VERSION 5.8 ;
BUSBITCHARS "[]" ;
DIVIDERCHAR "/" ;
UNITS
    DATABASE MICRONS 1000 ;
END UNITS

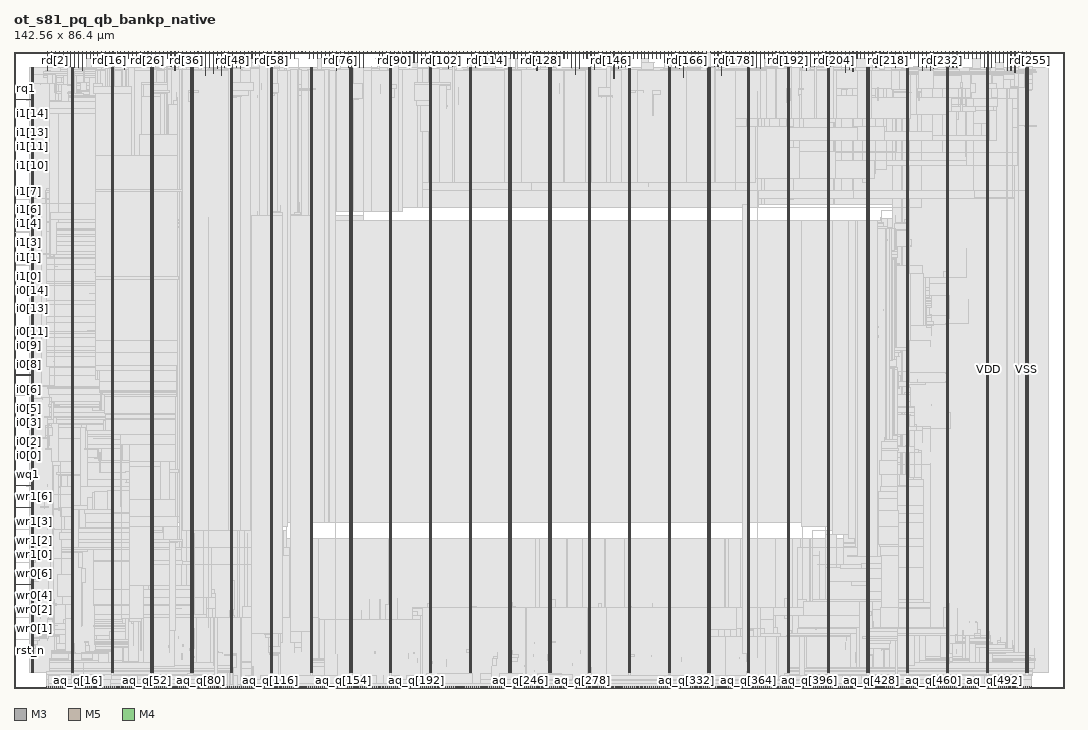
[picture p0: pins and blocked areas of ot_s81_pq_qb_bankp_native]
MACRO ot_s81_pq_qb_bankp_native
  FOREIGN ot_s81_pq_qb_bankp_native 0 0 ;
  CLASS BLOCK ;
  SIZE 142.56 BY 86.4 ;
  PIN aq_q[0]
    DIRECTION INPUT ;
    USE SIGNAL ;
    PORT
      LAYER M3 ;
        RECT  4.428 0 4.446 0.144 ;
    END
  END aq_q[0]
  PIN aq_q[100]
    DIRECTION INPUT ;
    USE SIGNAL ;
    PORT
      LAYER M3 ;
        RECT  30.6 0 30.618 0.144 ;
    END
  END aq_q[100]
  PIN aq_q[101]
    DIRECTION INPUT ;
    USE SIGNAL ;
    PORT
      LAYER M5 ;
        RECT  30.864 0 30.888 0.192 ;
    END
  END aq_q[101]
  PIN aq_q[102]
    DIRECTION INPUT ;
    USE SIGNAL ;
    PORT
      LAYER M3 ;
        RECT  31.104 0 31.122 0.144 ;
    END
  END aq_q[102]
  PIN aq_q[103]
    DIRECTION INPUT ;
    USE SIGNAL ;
    PORT
      LAYER M5 ;
        RECT  31.392 0 31.416 0.192 ;
    END
  END aq_q[103]
  PIN aq_q[104]
    DIRECTION INPUT ;
    USE SIGNAL ;
    PORT
      LAYER M3 ;
        RECT  31.644 0 31.662 0.144 ;
    END
  END aq_q[104]
  PIN aq_q[105]
    DIRECTION INPUT ;
    USE SIGNAL ;
    PORT
      LAYER M5 ;
        RECT  31.92 0 31.944 0.192 ;
    END
  END aq_q[105]
  PIN aq_q[106]
    DIRECTION INPUT ;
    USE SIGNAL ;
    PORT
      LAYER M3 ;
        RECT  32.184 0 32.202 0.144 ;
    END
  END aq_q[106]
  PIN aq_q[107]
    DIRECTION INPUT ;
    USE SIGNAL ;
    PORT
      LAYER M5 ;
        RECT  32.448 0 32.472 0.192 ;
    END
  END aq_q[107]
  PIN aq_q[108]
    DIRECTION INPUT ;
    USE SIGNAL ;
    PORT
      LAYER M3 ;
        RECT  32.688 0 32.706 0.144 ;
    END
  END aq_q[108]
  PIN aq_q[109]
    DIRECTION INPUT ;
    USE SIGNAL ;
    PORT
      LAYER M5 ;
        RECT  32.928 0 32.952 0.192 ;
    END
  END aq_q[109]
  PIN aq_q[10]
    DIRECTION INPUT ;
    USE SIGNAL ;
    PORT
      LAYER M3 ;
        RECT  7.056 0 7.074 0.144 ;
    END
  END aq_q[10]
  PIN aq_q[110]
    DIRECTION INPUT ;
    USE SIGNAL ;
    PORT
      LAYER M3 ;
        RECT  33.228 0 33.246 0.144 ;
    END
  END aq_q[110]
  PIN aq_q[111]
    DIRECTION INPUT ;
    USE SIGNAL ;
    PORT
      LAYER M5 ;
        RECT  33.456 0 33.48 0.192 ;
    END
  END aq_q[111]
  PIN aq_q[112]
    DIRECTION INPUT ;
    USE SIGNAL ;
    PORT
      LAYER M3 ;
        RECT  33.732 0 33.75 0.144 ;
    END
  END aq_q[112]
  PIN aq_q[113]
    DIRECTION INPUT ;
    USE SIGNAL ;
    PORT
      LAYER M5 ;
        RECT  33.984 0 34.008 0.192 ;
    END
  END aq_q[113]
  PIN aq_q[114]
    DIRECTION INPUT ;
    USE SIGNAL ;
    PORT
      LAYER M3 ;
        RECT  34.272 0 34.29 0.144 ;
    END
  END aq_q[114]
  PIN aq_q[115]
    DIRECTION INPUT ;
    USE SIGNAL ;
    PORT
      LAYER M5 ;
        RECT  34.512 0 34.536 0.192 ;
    END
  END aq_q[115]
  PIN aq_q[116]
    DIRECTION INPUT ;
    USE SIGNAL ;
    PORT
      LAYER M3 ;
        RECT  34.776 0 34.794 0.144 ;
    END
  END aq_q[116]
  PIN aq_q[117]
    DIRECTION INPUT ;
    USE SIGNAL ;
    PORT
      LAYER M5 ;
        RECT  35.04 0 35.064 0.192 ;
    END
  END aq_q[117]
  PIN aq_q[118]
    DIRECTION INPUT ;
    USE SIGNAL ;
    PORT
      LAYER M3 ;
        RECT  35.316 0 35.334 0.144 ;
    END
  END aq_q[118]
  PIN aq_q[119]
    DIRECTION INPUT ;
    USE SIGNAL ;
    PORT
      LAYER M5 ;
        RECT  35.568 0 35.592 0.192 ;
    END
  END aq_q[119]
  PIN aq_q[11]
    DIRECTION INPUT ;
    USE SIGNAL ;
    PORT
      LAYER M5 ;
        RECT  7.296 0 7.32 0.192 ;
    END
  END aq_q[11]
  PIN aq_q[120]
    DIRECTION INPUT ;
    USE SIGNAL ;
    PORT
      LAYER M3 ;
        RECT  35.82 0 35.838 0.144 ;
    END
  END aq_q[120]
  PIN aq_q[121]
    DIRECTION INPUT ;
    USE SIGNAL ;
    PORT
      LAYER M5 ;
        RECT  36.096 0 36.12 0.192 ;
    END
  END aq_q[121]
  PIN aq_q[122]
    DIRECTION INPUT ;
    USE SIGNAL ;
    PORT
      LAYER M3 ;
        RECT  36.36 0 36.378 0.144 ;
    END
  END aq_q[122]
  PIN aq_q[123]
    DIRECTION INPUT ;
    USE SIGNAL ;
    PORT
      LAYER M5 ;
        RECT  36.624 0 36.648 0.192 ;
    END
  END aq_q[123]
  PIN aq_q[124]
    DIRECTION INPUT ;
    USE SIGNAL ;
    PORT
      LAYER M3 ;
        RECT  36.864 0 36.882 0.144 ;
    END
  END aq_q[124]
  PIN aq_q[125]
    DIRECTION INPUT ;
    USE SIGNAL ;
    PORT
      LAYER M5 ;
        RECT  37.152 0 37.176 0.192 ;
    END
  END aq_q[125]
  PIN aq_q[126]
    DIRECTION INPUT ;
    USE SIGNAL ;
    PORT
      LAYER M3 ;
        RECT  37.404 0 37.422 0.144 ;
    END
  END aq_q[126]
  PIN aq_q[127]
    DIRECTION INPUT ;
    USE SIGNAL ;
    PORT
      LAYER M5 ;
        RECT  37.68 0 37.704 0.192 ;
    END
  END aq_q[127]
  PIN aq_q[128]
    DIRECTION INPUT ;
    USE SIGNAL ;
    PORT
      LAYER M3 ;
        RECT  37.908 0 37.926 0.144 ;
    END
  END aq_q[128]
  PIN aq_q[129]
    DIRECTION INPUT ;
    USE SIGNAL ;
    PORT
      LAYER M5 ;
        RECT  38.16 0 38.184 0.192 ;
    END
  END aq_q[129]
  PIN aq_q[12]
    DIRECTION INPUT ;
    USE SIGNAL ;
    PORT
      LAYER M3 ;
        RECT  7.596 0 7.614 0.144 ;
    END
  END aq_q[12]
  PIN aq_q[130]
    DIRECTION INPUT ;
    USE SIGNAL ;
    PORT
      LAYER M3 ;
        RECT  38.448 0 38.466 0.144 ;
    END
  END aq_q[130]
  PIN aq_q[131]
    DIRECTION INPUT ;
    USE SIGNAL ;
    PORT
      LAYER M5 ;
        RECT  38.688 0 38.712 0.192 ;
    END
  END aq_q[131]
  PIN aq_q[132]
    DIRECTION INPUT ;
    USE SIGNAL ;
    PORT
      LAYER M3 ;
        RECT  38.952 0 38.97 0.144 ;
    END
  END aq_q[132]
  PIN aq_q[133]
    DIRECTION INPUT ;
    USE SIGNAL ;
    PORT
      LAYER M5 ;
        RECT  39.216 0 39.24 0.192 ;
    END
  END aq_q[133]
  PIN aq_q[134]
    DIRECTION INPUT ;
    USE SIGNAL ;
    PORT
      LAYER M3 ;
        RECT  39.492 0 39.51 0.144 ;
    END
  END aq_q[134]
  PIN aq_q[135]
    DIRECTION INPUT ;
    USE SIGNAL ;
    PORT
      LAYER M5 ;
        RECT  39.744 0 39.768 0.192 ;
    END
  END aq_q[135]
  PIN aq_q[136]
    DIRECTION INPUT ;
    USE SIGNAL ;
    PORT
      LAYER M3 ;
        RECT  40.032 0 40.05 0.144 ;
    END
  END aq_q[136]
  PIN aq_q[137]
    DIRECTION INPUT ;
    USE SIGNAL ;
    PORT
      LAYER M5 ;
        RECT  40.272 0 40.296 0.192 ;
    END
  END aq_q[137]
  PIN aq_q[138]
    DIRECTION INPUT ;
    USE SIGNAL ;
    PORT
      LAYER M3 ;
        RECT  40.536 0 40.554 0.144 ;
    END
  END aq_q[138]
  PIN aq_q[139]
    DIRECTION INPUT ;
    USE SIGNAL ;
    PORT
      LAYER M5 ;
        RECT  40.8 0 40.824 0.192 ;
    END
  END aq_q[139]
  PIN aq_q[13]
    DIRECTION INPUT ;
    USE SIGNAL ;
    PORT
      LAYER M5 ;
        RECT  7.824 0 7.848 0.192 ;
    END
  END aq_q[13]
  PIN aq_q[140]
    DIRECTION INPUT ;
    USE SIGNAL ;
    PORT
      LAYER M3 ;
        RECT  41.076 0 41.094 0.144 ;
    END
  END aq_q[140]
  PIN aq_q[141]
    DIRECTION INPUT ;
    USE SIGNAL ;
    PORT
      LAYER M5 ;
        RECT  41.328 0 41.352 0.192 ;
    END
  END aq_q[141]
  PIN aq_q[142]
    DIRECTION INPUT ;
    USE SIGNAL ;
    PORT
      LAYER M3 ;
        RECT  41.58 0 41.598 0.144 ;
    END
  END aq_q[142]
  PIN aq_q[143]
    DIRECTION INPUT ;
    USE SIGNAL ;
    PORT
      LAYER M5 ;
        RECT  41.856 0 41.88 0.192 ;
    END
  END aq_q[143]
  PIN aq_q[144]
    DIRECTION INPUT ;
    USE SIGNAL ;
    PORT
      LAYER M3 ;
        RECT  42.12 0 42.138 0.144 ;
    END
  END aq_q[144]
  PIN aq_q[145]
    DIRECTION INPUT ;
    USE SIGNAL ;
    PORT
      LAYER M5 ;
        RECT  42.384 0 42.408 0.192 ;
    END
  END aq_q[145]
  PIN aq_q[146]
    DIRECTION INPUT ;
    USE SIGNAL ;
    PORT
      LAYER M3 ;
        RECT  42.624 0 42.642 0.144 ;
    END
  END aq_q[146]
  PIN aq_q[147]
    DIRECTION INPUT ;
    USE SIGNAL ;
    PORT
      LAYER M5 ;
        RECT  42.912 0 42.936 0.192 ;
    END
  END aq_q[147]
  PIN aq_q[148]
    DIRECTION INPUT ;
    USE SIGNAL ;
    PORT
      LAYER M3 ;
        RECT  43.164 0 43.182 0.144 ;
    END
  END aq_q[148]
  PIN aq_q[149]
    DIRECTION INPUT ;
    USE SIGNAL ;
    PORT
      LAYER M5 ;
        RECT  43.392 0 43.416 0.192 ;
    END
  END aq_q[149]
  PIN aq_q[14]
    DIRECTION INPUT ;
    USE SIGNAL ;
    PORT
      LAYER M3 ;
        RECT  8.1 0 8.118 0.144 ;
    END
  END aq_q[14]
  PIN aq_q[150]
    DIRECTION INPUT ;
    USE SIGNAL ;
    PORT
      LAYER M3 ;
        RECT  43.668 0 43.686 0.144 ;
    END
  END aq_q[150]
  PIN aq_q[151]
    DIRECTION INPUT ;
    USE SIGNAL ;
    PORT
      LAYER M5 ;
        RECT  43.92 0 43.944 0.192 ;
    END
  END aq_q[151]
  PIN aq_q[152]
    DIRECTION INPUT ;
    USE SIGNAL ;
    PORT
      LAYER M3 ;
        RECT  44.208 0 44.226 0.144 ;
    END
  END aq_q[152]
  PIN aq_q[153]
    DIRECTION INPUT ;
    USE SIGNAL ;
    PORT
      LAYER M5 ;
        RECT  44.448 0 44.472 0.192 ;
    END
  END aq_q[153]
  PIN aq_q[154]
    DIRECTION INPUT ;
    USE SIGNAL ;
    PORT
      LAYER M3 ;
        RECT  44.712 0 44.73 0.144 ;
    END
  END aq_q[154]
  PIN aq_q[155]
    DIRECTION INPUT ;
    USE SIGNAL ;
    PORT
      LAYER M5 ;
        RECT  44.976 0 45 0.192 ;
    END
  END aq_q[155]
  PIN aq_q[156]
    DIRECTION INPUT ;
    USE SIGNAL ;
    PORT
      LAYER M3 ;
        RECT  45.252 0 45.27 0.144 ;
    END
  END aq_q[156]
  PIN aq_q[157]
    DIRECTION INPUT ;
    USE SIGNAL ;
    PORT
      LAYER M5 ;
        RECT  45.504 0 45.528 0.192 ;
    END
  END aq_q[157]
  PIN aq_q[158]
    DIRECTION INPUT ;
    USE SIGNAL ;
    PORT
      LAYER M3 ;
        RECT  45.756 0 45.774 0.144 ;
    END
  END aq_q[158]
  PIN aq_q[159]
    DIRECTION INPUT ;
    USE SIGNAL ;
    PORT
      LAYER M5 ;
        RECT  46.032 0 46.056 0.192 ;
    END
  END aq_q[159]
  PIN aq_q[15]
    DIRECTION INPUT ;
    USE SIGNAL ;
    PORT
      LAYER M5 ;
        RECT  8.352 0 8.376 0.192 ;
    END
  END aq_q[15]
  PIN aq_q[160]
    DIRECTION INPUT ;
    USE SIGNAL ;
    PORT
      LAYER M3 ;
        RECT  46.296 0 46.314 0.144 ;
    END
  END aq_q[160]
  PIN aq_q[161]
    DIRECTION INPUT ;
    USE SIGNAL ;
    PORT
      LAYER M5 ;
        RECT  46.56 0 46.584 0.192 ;
    END
  END aq_q[161]
  PIN aq_q[162]
    DIRECTION INPUT ;
    USE SIGNAL ;
    PORT
      LAYER M3 ;
        RECT  46.8 0 46.818 0.144 ;
    END
  END aq_q[162]
  PIN aq_q[163]
    DIRECTION INPUT ;
    USE SIGNAL ;
    PORT
      LAYER M5 ;
        RECT  47.088 0 47.112 0.192 ;
    END
  END aq_q[163]
  PIN aq_q[164]
    DIRECTION INPUT ;
    USE SIGNAL ;
    PORT
      LAYER M3 ;
        RECT  47.34 0 47.358 0.144 ;
    END
  END aq_q[164]
  PIN aq_q[165]
    DIRECTION INPUT ;
    USE SIGNAL ;
    PORT
      LAYER M5 ;
        RECT  47.616 0 47.64 0.192 ;
    END
  END aq_q[165]
  PIN aq_q[166]
    DIRECTION INPUT ;
    USE SIGNAL ;
    PORT
      LAYER M3 ;
        RECT  47.844 0 47.862 0.144 ;
    END
  END aq_q[166]
  PIN aq_q[167]
    DIRECTION INPUT ;
    USE SIGNAL ;
    PORT
      LAYER M5 ;
        RECT  48.096 0 48.12 0.192 ;
    END
  END aq_q[167]
  PIN aq_q[168]
    DIRECTION INPUT ;
    USE SIGNAL ;
    PORT
      LAYER M3 ;
        RECT  48.384 0 48.402 0.144 ;
    END
  END aq_q[168]
  PIN aq_q[169]
    DIRECTION INPUT ;
    USE SIGNAL ;
    PORT
      LAYER M5 ;
        RECT  48.624 0 48.648 0.192 ;
    END
  END aq_q[169]
  PIN aq_q[16]
    DIRECTION INPUT ;
    USE SIGNAL ;
    PORT
      LAYER M3 ;
        RECT  8.64 0 8.658 0.144 ;
    END
  END aq_q[16]
  PIN aq_q[170]
    DIRECTION INPUT ;
    USE SIGNAL ;
    PORT
      LAYER M3 ;
        RECT  48.924 0 48.942 0.144 ;
    END
  END aq_q[170]
  PIN aq_q[171]
    DIRECTION INPUT ;
    USE SIGNAL ;
    PORT
      LAYER M5 ;
        RECT  49.152 0 49.176 0.192 ;
    END
  END aq_q[171]
  PIN aq_q[172]
    DIRECTION INPUT ;
    USE SIGNAL ;
    PORT
      LAYER M3 ;
        RECT  49.428 0 49.446 0.144 ;
    END
  END aq_q[172]
  PIN aq_q[173]
    DIRECTION INPUT ;
    USE SIGNAL ;
    PORT
      LAYER M5 ;
        RECT  49.68 0 49.704 0.192 ;
    END
  END aq_q[173]
  PIN aq_q[174]
    DIRECTION INPUT ;
    USE SIGNAL ;
    PORT
      LAYER M3 ;
        RECT  49.968 0 49.986 0.144 ;
    END
  END aq_q[174]
  PIN aq_q[175]
    DIRECTION INPUT ;
    USE SIGNAL ;
    PORT
      LAYER M5 ;
        RECT  50.208 0 50.232 0.192 ;
    END
  END aq_q[175]
  PIN aq_q[176]
    DIRECTION INPUT ;
    USE SIGNAL ;
    PORT
      LAYER M3 ;
        RECT  50.472 0 50.49 0.144 ;
    END
  END aq_q[176]
  PIN aq_q[177]
    DIRECTION INPUT ;
    USE SIGNAL ;
    PORT
      LAYER M5 ;
        RECT  50.736 0 50.76 0.192 ;
    END
  END aq_q[177]
  PIN aq_q[178]
    DIRECTION INPUT ;
    USE SIGNAL ;
    PORT
      LAYER M3 ;
        RECT  51.012 0 51.03 0.144 ;
    END
  END aq_q[178]
  PIN aq_q[179]
    DIRECTION INPUT ;
    USE SIGNAL ;
    PORT
      LAYER M5 ;
        RECT  51.264 0 51.288 0.192 ;
    END
  END aq_q[179]
  PIN aq_q[17]
    DIRECTION INPUT ;
    USE SIGNAL ;
    PORT
      LAYER M5 ;
        RECT  8.88 0 8.904 0.192 ;
    END
  END aq_q[17]
  PIN aq_q[180]
    DIRECTION INPUT ;
    USE SIGNAL ;
    PORT
      LAYER M3 ;
        RECT  51.516 0 51.534 0.144 ;
    END
  END aq_q[180]
  PIN aq_q[181]
    DIRECTION INPUT ;
    USE SIGNAL ;
    PORT
      LAYER M5 ;
        RECT  51.792 0 51.816 0.192 ;
    END
  END aq_q[181]
  PIN aq_q[182]
    DIRECTION INPUT ;
    USE SIGNAL ;
    PORT
      LAYER M3 ;
        RECT  52.056 0 52.074 0.144 ;
    END
  END aq_q[182]
  PIN aq_q[183]
    DIRECTION INPUT ;
    USE SIGNAL ;
    PORT
      LAYER M5 ;
        RECT  52.32 0 52.344 0.192 ;
    END
  END aq_q[183]
  PIN aq_q[184]
    DIRECTION INPUT ;
    USE SIGNAL ;
    PORT
      LAYER M3 ;
        RECT  52.56 0 52.578 0.144 ;
    END
  END aq_q[184]
  PIN aq_q[185]
    DIRECTION INPUT ;
    USE SIGNAL ;
    PORT
      LAYER M5 ;
        RECT  52.848 0 52.872 0.192 ;
    END
  END aq_q[185]
  PIN aq_q[186]
    DIRECTION INPUT ;
    USE SIGNAL ;
    PORT
      LAYER M3 ;
        RECT  53.1 0 53.118 0.144 ;
    END
  END aq_q[186]
  PIN aq_q[187]
    DIRECTION INPUT ;
    USE SIGNAL ;
    PORT
      LAYER M5 ;
        RECT  53.328 0 53.352 0.192 ;
    END
  END aq_q[187]
  PIN aq_q[188]
    DIRECTION INPUT ;
    USE SIGNAL ;
    PORT
      LAYER M3 ;
        RECT  53.604 0 53.622 0.144 ;
    END
  END aq_q[188]
  PIN aq_q[189]
    DIRECTION INPUT ;
    USE SIGNAL ;
    PORT
      LAYER M5 ;
        RECT  53.856 0 53.88 0.192 ;
    END
  END aq_q[189]
  PIN aq_q[18]
    DIRECTION INPUT ;
    USE SIGNAL ;
    PORT
      LAYER M3 ;
        RECT  9.144 0 9.162 0.144 ;
    END
  END aq_q[18]
  PIN aq_q[190]
    DIRECTION INPUT ;
    USE SIGNAL ;
    PORT
      LAYER M3 ;
        RECT  54.144 0 54.162 0.144 ;
    END
  END aq_q[190]
  PIN aq_q[191]
    DIRECTION INPUT ;
    USE SIGNAL ;
    PORT
      LAYER M5 ;
        RECT  54.384 0 54.408 0.192 ;
    END
  END aq_q[191]
  PIN aq_q[192]
    DIRECTION INPUT ;
    USE SIGNAL ;
    PORT
      LAYER M3 ;
        RECT  54.648 0 54.666 0.144 ;
    END
  END aq_q[192]
  PIN aq_q[193]
    DIRECTION INPUT ;
    USE SIGNAL ;
    PORT
      LAYER M5 ;
        RECT  54.912 0 54.936 0.192 ;
    END
  END aq_q[193]
  PIN aq_q[194]
    DIRECTION INPUT ;
    USE SIGNAL ;
    PORT
      LAYER M3 ;
        RECT  55.188 0 55.206 0.144 ;
    END
  END aq_q[194]
  PIN aq_q[195]
    DIRECTION INPUT ;
    USE SIGNAL ;
    PORT
      LAYER M5 ;
        RECT  55.44 0 55.464 0.192 ;
    END
  END aq_q[195]
  PIN aq_q[196]
    DIRECTION INPUT ;
    USE SIGNAL ;
    PORT
      LAYER M3 ;
        RECT  55.692 0 55.71 0.144 ;
    END
  END aq_q[196]
  PIN aq_q[197]
    DIRECTION INPUT ;
    USE SIGNAL ;
    PORT
      LAYER M5 ;
        RECT  55.968 0 55.992 0.192 ;
    END
  END aq_q[197]
  PIN aq_q[198]
    DIRECTION INPUT ;
    USE SIGNAL ;
    PORT
      LAYER M3 ;
        RECT  56.232 0 56.25 0.144 ;
    END
  END aq_q[198]
  PIN aq_q[199]
    DIRECTION INPUT ;
    USE SIGNAL ;
    PORT
      LAYER M5 ;
        RECT  56.496 0 56.52 0.192 ;
    END
  END aq_q[199]
  PIN aq_q[19]
    DIRECTION INPUT ;
    USE SIGNAL ;
    PORT
      LAYER M5 ;
        RECT  9.408 0 9.432 0.192 ;
    END
  END aq_q[19]
  PIN aq_q[1]
    DIRECTION INPUT ;
    USE SIGNAL ;
    PORT
      LAYER M5 ;
        RECT  4.704 0 4.728 0.192 ;
    END
  END aq_q[1]
  PIN aq_q[200]
    DIRECTION INPUT ;
    USE SIGNAL ;
    PORT
      LAYER M3 ;
        RECT  56.772 0 56.79 0.144 ;
    END
  END aq_q[200]
  PIN aq_q[201]
    DIRECTION INPUT ;
    USE SIGNAL ;
    PORT
      LAYER M5 ;
        RECT  57.024 0 57.048 0.192 ;
    END
  END aq_q[201]
  PIN aq_q[202]
    DIRECTION INPUT ;
    USE SIGNAL ;
    PORT
      LAYER M3 ;
        RECT  57.276 0 57.294 0.144 ;
    END
  END aq_q[202]
  PIN aq_q[203]
    DIRECTION INPUT ;
    USE SIGNAL ;
    PORT
      LAYER M5 ;
        RECT  57.552 0 57.576 0.192 ;
    END
  END aq_q[203]
  PIN aq_q[204]
    DIRECTION INPUT ;
    USE SIGNAL ;
    PORT
      LAYER M3 ;
        RECT  57.816 0 57.834 0.144 ;
    END
  END aq_q[204]
  PIN aq_q[205]
    DIRECTION INPUT ;
    USE SIGNAL ;
    PORT
      LAYER M5 ;
        RECT  58.08 0 58.104 0.192 ;
    END
  END aq_q[205]
  PIN aq_q[206]
    DIRECTION INPUT ;
    USE SIGNAL ;
    PORT
      LAYER M3 ;
        RECT  58.32 0 58.338 0.144 ;
    END
  END aq_q[206]
  PIN aq_q[207]
    DIRECTION INPUT ;
    USE SIGNAL ;
    PORT
      LAYER M5 ;
        RECT  58.56 0 58.584 0.192 ;
    END
  END aq_q[207]
  PIN aq_q[208]
    DIRECTION INPUT ;
    USE SIGNAL ;
    PORT
      LAYER M3 ;
        RECT  58.86 0 58.878 0.144 ;
    END
  END aq_q[208]
  PIN aq_q[209]
    DIRECTION INPUT ;
    USE SIGNAL ;
    PORT
      LAYER M5 ;
        RECT  59.088 0 59.112 0.192 ;
    END
  END aq_q[209]
  PIN aq_q[20]
    DIRECTION INPUT ;
    USE SIGNAL ;
    PORT
      LAYER M3 ;
        RECT  9.684 0 9.702 0.144 ;
    END
  END aq_q[20]
  PIN aq_q[210]
    DIRECTION INPUT ;
    USE SIGNAL ;
    PORT
      LAYER M3 ;
        RECT  59.364 0 59.382 0.144 ;
    END
  END aq_q[210]
  PIN aq_q[211]
    DIRECTION INPUT ;
    USE SIGNAL ;
    PORT
      LAYER M5 ;
        RECT  59.616 0 59.64 0.192 ;
    END
  END aq_q[211]
  PIN aq_q[212]
    DIRECTION INPUT ;
    USE SIGNAL ;
    PORT
      LAYER M3 ;
        RECT  59.904 0 59.922 0.144 ;
    END
  END aq_q[212]
  PIN aq_q[213]
    DIRECTION INPUT ;
    USE SIGNAL ;
    PORT
      LAYER M5 ;
        RECT  60.144 0 60.168 0.192 ;
    END
  END aq_q[213]
  PIN aq_q[214]
    DIRECTION INPUT ;
    USE SIGNAL ;
    PORT
      LAYER M3 ;
        RECT  60.408 0 60.426 0.144 ;
    END
  END aq_q[214]
  PIN aq_q[215]
    DIRECTION INPUT ;
    USE SIGNAL ;
    PORT
      LAYER M5 ;
        RECT  60.672 0 60.696 0.192 ;
    END
  END aq_q[215]
  PIN aq_q[216]
    DIRECTION INPUT ;
    USE SIGNAL ;
    PORT
      LAYER M3 ;
        RECT  60.948 0 60.966 0.144 ;
    END
  END aq_q[216]
  PIN aq_q[217]
    DIRECTION INPUT ;
    USE SIGNAL ;
    PORT
      LAYER M5 ;
        RECT  61.2 0 61.224 0.192 ;
    END
  END aq_q[217]
  PIN aq_q[218]
    DIRECTION INPUT ;
    USE SIGNAL ;
    PORT
      LAYER M3 ;
        RECT  61.452 0 61.47 0.144 ;
    END
  END aq_q[218]
  PIN aq_q[219]
    DIRECTION INPUT ;
    USE SIGNAL ;
    PORT
      LAYER M5 ;
        RECT  61.728 0 61.752 0.192 ;
    END
  END aq_q[219]
  PIN aq_q[21]
    DIRECTION INPUT ;
    USE SIGNAL ;
    PORT
      LAYER M5 ;
        RECT  9.936 0 9.96 0.192 ;
    END
  END aq_q[21]
  PIN aq_q[220]
    DIRECTION INPUT ;
    USE SIGNAL ;
    PORT
      LAYER M3 ;
        RECT  61.992 0 62.01 0.144 ;
    END
  END aq_q[220]
  PIN aq_q[221]
    DIRECTION INPUT ;
    USE SIGNAL ;
    PORT
      LAYER M5 ;
        RECT  62.256 0 62.28 0.192 ;
    END
  END aq_q[221]
  PIN aq_q[222]
    DIRECTION INPUT ;
    USE SIGNAL ;
    PORT
      LAYER M3 ;
        RECT  62.496 0 62.514 0.144 ;
    END
  END aq_q[222]
  PIN aq_q[223]
    DIRECTION INPUT ;
    USE SIGNAL ;
    PORT
      LAYER M5 ;
        RECT  62.784 0 62.808 0.192 ;
    END
  END aq_q[223]
  PIN aq_q[224]
    DIRECTION INPUT ;
    USE SIGNAL ;
    PORT
      LAYER M3 ;
        RECT  63.036 0 63.054 0.144 ;
    END
  END aq_q[224]
  PIN aq_q[225]
    DIRECTION INPUT ;
    USE SIGNAL ;
    PORT
      LAYER M5 ;
        RECT  63.312 0 63.336 0.192 ;
    END
  END aq_q[225]
  PIN aq_q[226]
    DIRECTION INPUT ;
    USE SIGNAL ;
    PORT
      LAYER M3 ;
        RECT  63.54 0 63.558 0.144 ;
    END
  END aq_q[226]
  PIN aq_q[227]
    DIRECTION INPUT ;
    USE SIGNAL ;
    PORT
      LAYER M5 ;
        RECT  63.792 0 63.816 0.192 ;
    END
  END aq_q[227]
  PIN aq_q[228]
    DIRECTION INPUT ;
    USE SIGNAL ;
    PORT
      LAYER M3 ;
        RECT  64.08 0 64.098 0.144 ;
    END
  END aq_q[228]
  PIN aq_q[229]
    DIRECTION INPUT ;
    USE SIGNAL ;
    PORT
      LAYER M5 ;
        RECT  64.32 0 64.344 0.192 ;
    END
  END aq_q[229]
  PIN aq_q[22]
    DIRECTION INPUT ;
    USE SIGNAL ;
    PORT
      LAYER M3 ;
        RECT  10.188 0 10.206 0.144 ;
    END
  END aq_q[22]
  PIN aq_q[230]
    DIRECTION INPUT ;
    USE SIGNAL ;
    PORT
      LAYER M3 ;
        RECT  64.584 0 64.602 0.144 ;
    END
  END aq_q[230]
  PIN aq_q[231]
    DIRECTION INPUT ;
    USE SIGNAL ;
    PORT
      LAYER M5 ;
        RECT  64.848 0 64.872 0.192 ;
    END
  END aq_q[231]
  PIN aq_q[232]
    DIRECTION INPUT ;
    USE SIGNAL ;
    PORT
      LAYER M3 ;
        RECT  65.124 0 65.142 0.144 ;
    END
  END aq_q[232]
  PIN aq_q[233]
    DIRECTION INPUT ;
    USE SIGNAL ;
    PORT
      LAYER M5 ;
        RECT  65.376 0 65.4 0.192 ;
    END
  END aq_q[233]
  PIN aq_q[234]
    DIRECTION INPUT ;
    USE SIGNAL ;
    PORT
      LAYER M3 ;
        RECT  65.664 0 65.682 0.144 ;
    END
  END aq_q[234]
  PIN aq_q[235]
    DIRECTION INPUT ;
    USE SIGNAL ;
    PORT
      LAYER M5 ;
        RECT  65.904 0 65.928 0.192 ;
    END
  END aq_q[235]
  PIN aq_q[236]
    DIRECTION INPUT ;
    USE SIGNAL ;
    PORT
      LAYER M3 ;
        RECT  66.168 0 66.186 0.144 ;
    END
  END aq_q[236]
  PIN aq_q[237]
    DIRECTION INPUT ;
    USE SIGNAL ;
    PORT
      LAYER M5 ;
        RECT  66.432 0 66.456 0.192 ;
    END
  END aq_q[237]
  PIN aq_q[238]
    DIRECTION INPUT ;
    USE SIGNAL ;
    PORT
      LAYER M3 ;
        RECT  66.708 0 66.726 0.144 ;
    END
  END aq_q[238]
  PIN aq_q[239]
    DIRECTION INPUT ;
    USE SIGNAL ;
    PORT
      LAYER M5 ;
        RECT  66.96 0 66.984 0.192 ;
    END
  END aq_q[239]
  PIN aq_q[23]
    DIRECTION INPUT ;
    USE SIGNAL ;
    PORT
      LAYER M5 ;
        RECT  10.464 0 10.488 0.192 ;
    END
  END aq_q[23]
  PIN aq_q[240]
    DIRECTION INPUT ;
    USE SIGNAL ;
    PORT
      LAYER M3 ;
        RECT  67.212 0 67.23 0.144 ;
    END
  END aq_q[240]
  PIN aq_q[241]
    DIRECTION INPUT ;
    USE SIGNAL ;
    PORT
      LAYER M5 ;
        RECT  67.488 0 67.512 0.192 ;
    END
  END aq_q[241]
  PIN aq_q[242]
    DIRECTION INPUT ;
    USE SIGNAL ;
    PORT
      LAYER M3 ;
        RECT  67.752 0 67.77 0.144 ;
    END
  END aq_q[242]
  PIN aq_q[243]
    DIRECTION INPUT ;
    USE SIGNAL ;
    PORT
      LAYER M5 ;
        RECT  68.016 0 68.04 0.192 ;
    END
  END aq_q[243]
  PIN aq_q[244]
    DIRECTION INPUT ;
    USE SIGNAL ;
    PORT
      LAYER M3 ;
        RECT  68.256 0 68.274 0.144 ;
    END
  END aq_q[244]
  PIN aq_q[245]
    DIRECTION INPUT ;
    USE SIGNAL ;
    PORT
      LAYER M5 ;
        RECT  68.544 0 68.568 0.192 ;
    END
  END aq_q[245]
  PIN aq_q[246]
    DIRECTION INPUT ;
    USE SIGNAL ;
    PORT
      LAYER M3 ;
        RECT  68.796 0 68.814 0.144 ;
    END
  END aq_q[246]
  PIN aq_q[247]
    DIRECTION INPUT ;
    USE SIGNAL ;
    PORT
      LAYER M5 ;
        RECT  69.024 0 69.048 0.192 ;
    END
  END aq_q[247]
  PIN aq_q[248]
    DIRECTION INPUT ;
    USE SIGNAL ;
    PORT
      LAYER M3 ;
        RECT  69.3 0 69.318 0.144 ;
    END
  END aq_q[248]
  PIN aq_q[249]
    DIRECTION INPUT ;
    USE SIGNAL ;
    PORT
      LAYER M5 ;
        RECT  69.552 0 69.576 0.192 ;
    END
  END aq_q[249]
  PIN aq_q[24]
    DIRECTION INPUT ;
    USE SIGNAL ;
    PORT
      LAYER M3 ;
        RECT  10.728 0 10.746 0.144 ;
    END
  END aq_q[24]
  PIN aq_q[250]
    DIRECTION INPUT ;
    USE SIGNAL ;
    PORT
      LAYER M3 ;
        RECT  69.84 0 69.858 0.144 ;
    END
  END aq_q[250]
  PIN aq_q[251]
    DIRECTION INPUT ;
    USE SIGNAL ;
    PORT
      LAYER M5 ;
        RECT  70.08 0 70.104 0.192 ;
    END
  END aq_q[251]
  PIN aq_q[252]
    DIRECTION INPUT ;
    USE SIGNAL ;
    PORT
      LAYER M3 ;
        RECT  70.344 0 70.362 0.144 ;
    END
  END aq_q[252]
  PIN aq_q[253]
    DIRECTION INPUT ;
    USE SIGNAL ;
    PORT
      LAYER M5 ;
        RECT  70.608 0 70.632 0.192 ;
    END
  END aq_q[253]
  PIN aq_q[254]
    DIRECTION INPUT ;
    USE SIGNAL ;
    PORT
      LAYER M3 ;
        RECT  70.884 0 70.902 0.144 ;
    END
  END aq_q[254]
  PIN aq_q[255]
    DIRECTION INPUT ;
    USE SIGNAL ;
    PORT
      LAYER M5 ;
        RECT  71.136 0 71.16 0.192 ;
    END
  END aq_q[255]
  PIN aq_q[256]
    DIRECTION INPUT ;
    USE SIGNAL ;
    PORT
      LAYER M3 ;
        RECT  71.388 0 71.406 0.144 ;
    END
  END aq_q[256]
  PIN aq_q[257]
    DIRECTION INPUT ;
    USE SIGNAL ;
    PORT
      LAYER M5 ;
        RECT  71.664 0 71.688 0.192 ;
    END
  END aq_q[257]
  PIN aq_q[258]
    DIRECTION INPUT ;
    USE SIGNAL ;
    PORT
      LAYER M3 ;
        RECT  71.928 0 71.946 0.144 ;
    END
  END aq_q[258]
  PIN aq_q[259]
    DIRECTION INPUT ;
    USE SIGNAL ;
    PORT
      LAYER M5 ;
        RECT  72.192 0 72.216 0.192 ;
    END
  END aq_q[259]
  PIN aq_q[25]
    DIRECTION INPUT ;
    USE SIGNAL ;
    PORT
      LAYER M5 ;
        RECT  10.992 0 11.016 0.192 ;
    END
  END aq_q[25]
  PIN aq_q[260]
    DIRECTION INPUT ;
    USE SIGNAL ;
    PORT
      LAYER M3 ;
        RECT  72.432 0 72.45 0.144 ;
    END
  END aq_q[260]
  PIN aq_q[261]
    DIRECTION INPUT ;
    USE SIGNAL ;
    PORT
      LAYER M5 ;
        RECT  72.72 0 72.744 0.192 ;
    END
  END aq_q[261]
  PIN aq_q[262]
    DIRECTION INPUT ;
    USE SIGNAL ;
    PORT
      LAYER M3 ;
        RECT  72.972 0 72.99 0.144 ;
    END
  END aq_q[262]
  PIN aq_q[263]
    DIRECTION INPUT ;
    USE SIGNAL ;
    PORT
      LAYER M5 ;
        RECT  73.248 0 73.272 0.192 ;
    END
  END aq_q[263]
  PIN aq_q[264]
    DIRECTION INPUT ;
    USE SIGNAL ;
    PORT
      LAYER M3 ;
        RECT  73.512 0 73.53 0.144 ;
    END
  END aq_q[264]
  PIN aq_q[265]
    DIRECTION INPUT ;
    USE SIGNAL ;
    PORT
      LAYER M5 ;
        RECT  73.776 0 73.8 0.192 ;
    END
  END aq_q[265]
  PIN aq_q[266]
    DIRECTION INPUT ;
    USE SIGNAL ;
    PORT
      LAYER M3 ;
        RECT  74.016 0 74.034 0.144 ;
    END
  END aq_q[266]
  PIN aq_q[267]
    DIRECTION INPUT ;
    USE SIGNAL ;
    PORT
      LAYER M5 ;
        RECT  74.256 0 74.28 0.192 ;
    END
  END aq_q[267]
  PIN aq_q[268]
    DIRECTION INPUT ;
    USE SIGNAL ;
    PORT
      LAYER M3 ;
        RECT  74.556 0 74.574 0.144 ;
    END
  END aq_q[268]
  PIN aq_q[269]
    DIRECTION INPUT ;
    USE SIGNAL ;
    PORT
      LAYER M5 ;
        RECT  74.784 0 74.808 0.192 ;
    END
  END aq_q[269]
  PIN aq_q[26]
    DIRECTION INPUT ;
    USE SIGNAL ;
    PORT
      LAYER M3 ;
        RECT  11.232 0 11.25 0.144 ;
    END
  END aq_q[26]
  PIN aq_q[270]
    DIRECTION INPUT ;
    USE SIGNAL ;
    PORT
      LAYER M3 ;
        RECT  75.06 0 75.078 0.144 ;
    END
  END aq_q[270]
  PIN aq_q[271]
    DIRECTION INPUT ;
    USE SIGNAL ;
    PORT
      LAYER M5 ;
        RECT  75.312 0 75.336 0.192 ;
    END
  END aq_q[271]
  PIN aq_q[272]
    DIRECTION INPUT ;
    USE SIGNAL ;
    PORT
      LAYER M3 ;
        RECT  75.6 0 75.618 0.144 ;
    END
  END aq_q[272]
  PIN aq_q[273]
    DIRECTION INPUT ;
    USE SIGNAL ;
    PORT
      LAYER M5 ;
        RECT  75.84 0 75.864 0.192 ;
    END
  END aq_q[273]
  PIN aq_q[274]
    DIRECTION INPUT ;
    USE SIGNAL ;
    PORT
      LAYER M3 ;
        RECT  76.104 0 76.122 0.144 ;
    END
  END aq_q[274]
  PIN aq_q[275]
    DIRECTION INPUT ;
    USE SIGNAL ;
    PORT
      LAYER M5 ;
        RECT  76.368 0 76.392 0.192 ;
    END
  END aq_q[275]
  PIN aq_q[276]
    DIRECTION INPUT ;
    USE SIGNAL ;
    PORT
      LAYER M3 ;
        RECT  76.644 0 76.662 0.144 ;
    END
  END aq_q[276]
  PIN aq_q[277]
    DIRECTION INPUT ;
    USE SIGNAL ;
    PORT
      LAYER M5 ;
        RECT  76.896 0 76.92 0.192 ;
    END
  END aq_q[277]
  PIN aq_q[278]
    DIRECTION INPUT ;
    USE SIGNAL ;
    PORT
      LAYER M3 ;
        RECT  77.148 0 77.166 0.144 ;
    END
  END aq_q[278]
  PIN aq_q[279]
    DIRECTION INPUT ;
    USE SIGNAL ;
    PORT
      LAYER M5 ;
        RECT  77.424 0 77.448 0.192 ;
    END
  END aq_q[279]
  PIN aq_q[27]
    DIRECTION INPUT ;
    USE SIGNAL ;
    PORT
      LAYER M5 ;
        RECT  11.52 0 11.544 0.192 ;
    END
  END aq_q[27]
  PIN aq_q[280]
    DIRECTION INPUT ;
    USE SIGNAL ;
    PORT
      LAYER M3 ;
        RECT  77.688 0 77.706 0.144 ;
    END
  END aq_q[280]
  PIN aq_q[281]
    DIRECTION INPUT ;
    USE SIGNAL ;
    PORT
      LAYER M5 ;
        RECT  77.952 0 77.976 0.192 ;
    END
  END aq_q[281]
  PIN aq_q[282]
    DIRECTION INPUT ;
    USE SIGNAL ;
    PORT
      LAYER M3 ;
        RECT  78.192 0 78.21 0.144 ;
    END
  END aq_q[282]
  PIN aq_q[283]
    DIRECTION INPUT ;
    USE SIGNAL ;
    PORT
      LAYER M5 ;
        RECT  78.48 0 78.504 0.192 ;
    END
  END aq_q[283]
  PIN aq_q[284]
    DIRECTION INPUT ;
    USE SIGNAL ;
    PORT
      LAYER M3 ;
        RECT  78.732 0 78.75 0.144 ;
    END
  END aq_q[284]
  PIN aq_q[285]
    DIRECTION INPUT ;
    USE SIGNAL ;
    PORT
      LAYER M5 ;
        RECT  79.008 0 79.032 0.192 ;
    END
  END aq_q[285]
  PIN aq_q[286]
    DIRECTION INPUT ;
    USE SIGNAL ;
    PORT
      LAYER M3 ;
        RECT  79.236 0 79.254 0.144 ;
    END
  END aq_q[286]
  PIN aq_q[287]
    DIRECTION INPUT ;
    USE SIGNAL ;
    PORT
      LAYER M5 ;
        RECT  79.488 0 79.512 0.192 ;
    END
  END aq_q[287]
  PIN aq_q[288]
    DIRECTION INPUT ;
    USE SIGNAL ;
    PORT
      LAYER M3 ;
        RECT  79.776 0 79.794 0.144 ;
    END
  END aq_q[288]
  PIN aq_q[289]
    DIRECTION INPUT ;
    USE SIGNAL ;
    PORT
      LAYER M5 ;
        RECT  80.016 0 80.04 0.192 ;
    END
  END aq_q[289]
  PIN aq_q[28]
    DIRECTION INPUT ;
    USE SIGNAL ;
    PORT
      LAYER M3 ;
        RECT  11.772 0 11.79 0.144 ;
    END
  END aq_q[28]
  PIN aq_q[290]
    DIRECTION INPUT ;
    USE SIGNAL ;
    PORT
      LAYER M3 ;
        RECT  80.28 0 80.298 0.144 ;
    END
  END aq_q[290]
  PIN aq_q[291]
    DIRECTION INPUT ;
    USE SIGNAL ;
    PORT
      LAYER M5 ;
        RECT  80.544 0 80.568 0.192 ;
    END
  END aq_q[291]
  PIN aq_q[292]
    DIRECTION INPUT ;
    USE SIGNAL ;
    PORT
      LAYER M3 ;
        RECT  80.82 0 80.838 0.144 ;
    END
  END aq_q[292]
  PIN aq_q[293]
    DIRECTION INPUT ;
    USE SIGNAL ;
    PORT
      LAYER M5 ;
        RECT  81.072 0 81.096 0.192 ;
    END
  END aq_q[293]
  PIN aq_q[294]
    DIRECTION INPUT ;
    USE SIGNAL ;
    PORT
      LAYER M3 ;
        RECT  81.324 0 81.342 0.144 ;
    END
  END aq_q[294]
  PIN aq_q[295]
    DIRECTION INPUT ;
    USE SIGNAL ;
    PORT
      LAYER M5 ;
        RECT  81.6 0 81.624 0.192 ;
    END
  END aq_q[295]
  PIN aq_q[296]
    DIRECTION INPUT ;
    USE SIGNAL ;
    PORT
      LAYER M3 ;
        RECT  81.864 0 81.882 0.144 ;
    END
  END aq_q[296]
  PIN aq_q[297]
    DIRECTION INPUT ;
    USE SIGNAL ;
    PORT
      LAYER M5 ;
        RECT  82.128 0 82.152 0.192 ;
    END
  END aq_q[297]
  PIN aq_q[298]
    DIRECTION INPUT ;
    USE SIGNAL ;
    PORT
      LAYER M3 ;
        RECT  82.404 0 82.422 0.144 ;
    END
  END aq_q[298]
  PIN aq_q[299]
    DIRECTION INPUT ;
    USE SIGNAL ;
    PORT
      LAYER M5 ;
        RECT  82.656 0 82.68 0.192 ;
    END
  END aq_q[299]
  PIN aq_q[29]
    DIRECTION INPUT ;
    USE SIGNAL ;
    PORT
      LAYER M5 ;
        RECT  12.048 0 12.072 0.192 ;
    END
  END aq_q[29]
  PIN aq_q[2]
    DIRECTION INPUT ;
    USE SIGNAL ;
    PORT
      LAYER M3 ;
        RECT  4.968 0 4.986 0.144 ;
    END
  END aq_q[2]
  PIN aq_q[300]
    DIRECTION INPUT ;
    USE SIGNAL ;
    PORT
      LAYER M3 ;
        RECT  82.908 0 82.926 0.144 ;
    END
  END aq_q[300]
  PIN aq_q[301]
    DIRECTION INPUT ;
    USE SIGNAL ;
    PORT
      LAYER M5 ;
        RECT  83.184 0 83.208 0.192 ;
    END
  END aq_q[301]
  PIN aq_q[302]
    DIRECTION INPUT ;
    USE SIGNAL ;
    PORT
      LAYER M3 ;
        RECT  83.448 0 83.466 0.144 ;
    END
  END aq_q[302]
  PIN aq_q[303]
    DIRECTION INPUT ;
    USE SIGNAL ;
    PORT
      LAYER M5 ;
        RECT  83.712 0 83.736 0.192 ;
    END
  END aq_q[303]
  PIN aq_q[304]
    DIRECTION INPUT ;
    USE SIGNAL ;
    PORT
      LAYER M3 ;
        RECT  83.952 0 83.97 0.144 ;
    END
  END aq_q[304]
  PIN aq_q[305]
    DIRECTION INPUT ;
    USE SIGNAL ;
    PORT
      LAYER M5 ;
        RECT  84.192 0 84.216 0.192 ;
    END
  END aq_q[305]
  PIN aq_q[306]
    DIRECTION INPUT ;
    USE SIGNAL ;
    PORT
      LAYER M3 ;
        RECT  84.492 0 84.51 0.144 ;
    END
  END aq_q[306]
  PIN aq_q[307]
    DIRECTION INPUT ;
    USE SIGNAL ;
    PORT
      LAYER M5 ;
        RECT  84.72 0 84.744 0.192 ;
    END
  END aq_q[307]
  PIN aq_q[308]
    DIRECTION INPUT ;
    USE SIGNAL ;
    PORT
      LAYER M3 ;
        RECT  84.996 0 85.014 0.144 ;
    END
  END aq_q[308]
  PIN aq_q[309]
    DIRECTION INPUT ;
    USE SIGNAL ;
    PORT
      LAYER M5 ;
        RECT  85.248 0 85.272 0.192 ;
    END
  END aq_q[309]
  PIN aq_q[30]
    DIRECTION INPUT ;
    USE SIGNAL ;
    PORT
      LAYER M3 ;
        RECT  12.276 0 12.294 0.144 ;
    END
  END aq_q[30]
  PIN aq_q[310]
    DIRECTION INPUT ;
    USE SIGNAL ;
    PORT
      LAYER M3 ;
        RECT  85.536 0 85.554 0.144 ;
    END
  END aq_q[310]
  PIN aq_q[311]
    DIRECTION INPUT ;
    USE SIGNAL ;
    PORT
      LAYER M5 ;
        RECT  85.776 0 85.8 0.192 ;
    END
  END aq_q[311]
  PIN aq_q[312]
    DIRECTION INPUT ;
    USE SIGNAL ;
    PORT
      LAYER M3 ;
        RECT  86.04 0 86.058 0.144 ;
    END
  END aq_q[312]
  PIN aq_q[313]
    DIRECTION INPUT ;
    USE SIGNAL ;
    PORT
      LAYER M5 ;
        RECT  86.304 0 86.328 0.192 ;
    END
  END aq_q[313]
  PIN aq_q[314]
    DIRECTION INPUT ;
    USE SIGNAL ;
    PORT
      LAYER M3 ;
        RECT  86.58 0 86.598 0.144 ;
    END
  END aq_q[314]
  PIN aq_q[315]
    DIRECTION INPUT ;
    USE SIGNAL ;
    PORT
      LAYER M5 ;
        RECT  86.832 0 86.856 0.192 ;
    END
  END aq_q[315]
  PIN aq_q[316]
    DIRECTION INPUT ;
    USE SIGNAL ;
    PORT
      LAYER M3 ;
        RECT  87.084 0 87.102 0.144 ;
    END
  END aq_q[316]
  PIN aq_q[317]
    DIRECTION INPUT ;
    USE SIGNAL ;
    PORT
      LAYER M5 ;
        RECT  87.36 0 87.384 0.192 ;
    END
  END aq_q[317]
  PIN aq_q[318]
    DIRECTION INPUT ;
    USE SIGNAL ;
    PORT
      LAYER M3 ;
        RECT  87.624 0 87.642 0.144 ;
    END
  END aq_q[318]
  PIN aq_q[319]
    DIRECTION INPUT ;
    USE SIGNAL ;
    PORT
      LAYER M5 ;
        RECT  87.888 0 87.912 0.192 ;
    END
  END aq_q[319]
  PIN aq_q[31]
    DIRECTION INPUT ;
    USE SIGNAL ;
    PORT
      LAYER M5 ;
        RECT  12.528 0 12.552 0.192 ;
    END
  END aq_q[31]
  PIN aq_q[320]
    DIRECTION INPUT ;
    USE SIGNAL ;
    PORT
      LAYER M3 ;
        RECT  88.128 0 88.146 0.144 ;
    END
  END aq_q[320]
  PIN aq_q[321]
    DIRECTION INPUT ;
    USE SIGNAL ;
    PORT
      LAYER M5 ;
        RECT  88.416 0 88.44 0.192 ;
    END
  END aq_q[321]
  PIN aq_q[322]
    DIRECTION INPUT ;
    USE SIGNAL ;
    PORT
      LAYER M3 ;
        RECT  88.668 0 88.686 0.144 ;
    END
  END aq_q[322]
  PIN aq_q[323]
    DIRECTION INPUT ;
    USE SIGNAL ;
    PORT
      LAYER M5 ;
        RECT  88.944 0 88.968 0.192 ;
    END
  END aq_q[323]
  PIN aq_q[324]
    DIRECTION INPUT ;
    USE SIGNAL ;
    PORT
      LAYER M3 ;
        RECT  89.172 0 89.19 0.144 ;
    END
  END aq_q[324]
  PIN aq_q[325]
    DIRECTION INPUT ;
    USE SIGNAL ;
    PORT
      LAYER M5 ;
        RECT  89.424 0 89.448 0.192 ;
    END
  END aq_q[325]
  PIN aq_q[326]
    DIRECTION INPUT ;
    USE SIGNAL ;
    PORT
      LAYER M3 ;
        RECT  89.712 0 89.73 0.144 ;
    END
  END aq_q[326]
  PIN aq_q[327]
    DIRECTION INPUT ;
    USE SIGNAL ;
    PORT
      LAYER M5 ;
        RECT  89.952 0 89.976 0.192 ;
    END
  END aq_q[327]
  PIN aq_q[328]
    DIRECTION INPUT ;
    USE SIGNAL ;
    PORT
      LAYER M3 ;
        RECT  90.252 0 90.27 0.144 ;
    END
  END aq_q[328]
  PIN aq_q[329]
    DIRECTION INPUT ;
    USE SIGNAL ;
    PORT
      LAYER M5 ;
        RECT  90.48 0 90.504 0.192 ;
    END
  END aq_q[329]
  PIN aq_q[32]
    DIRECTION INPUT ;
    USE SIGNAL ;
    PORT
      LAYER M3 ;
        RECT  12.816 0 12.834 0.144 ;
    END
  END aq_q[32]
  PIN aq_q[330]
    DIRECTION INPUT ;
    USE SIGNAL ;
    PORT
      LAYER M3 ;
        RECT  90.756 0 90.774 0.144 ;
    END
  END aq_q[330]
  PIN aq_q[331]
    DIRECTION INPUT ;
    USE SIGNAL ;
    PORT
      LAYER M5 ;
        RECT  91.008 0 91.032 0.192 ;
    END
  END aq_q[331]
  PIN aq_q[332]
    DIRECTION INPUT ;
    USE SIGNAL ;
    PORT
      LAYER M3 ;
        RECT  91.296 0 91.314 0.144 ;
    END
  END aq_q[332]
  PIN aq_q[333]
    DIRECTION INPUT ;
    USE SIGNAL ;
    PORT
      LAYER M5 ;
        RECT  91.536 0 91.56 0.192 ;
    END
  END aq_q[333]
  PIN aq_q[334]
    DIRECTION INPUT ;
    USE SIGNAL ;
    PORT
      LAYER M3 ;
        RECT  91.8 0 91.818 0.144 ;
    END
  END aq_q[334]
  PIN aq_q[335]
    DIRECTION INPUT ;
    USE SIGNAL ;
    PORT
      LAYER M5 ;
        RECT  92.064 0 92.088 0.192 ;
    END
  END aq_q[335]
  PIN aq_q[336]
    DIRECTION INPUT ;
    USE SIGNAL ;
    PORT
      LAYER M3 ;
        RECT  92.34 0 92.358 0.144 ;
    END
  END aq_q[336]
  PIN aq_q[337]
    DIRECTION INPUT ;
    USE SIGNAL ;
    PORT
      LAYER M5 ;
        RECT  92.592 0 92.616 0.192 ;
    END
  END aq_q[337]
  PIN aq_q[338]
    DIRECTION INPUT ;
    USE SIGNAL ;
    PORT
      LAYER M3 ;
        RECT  92.844 0 92.862 0.144 ;
    END
  END aq_q[338]
  PIN aq_q[339]
    DIRECTION INPUT ;
    USE SIGNAL ;
    PORT
      LAYER M5 ;
        RECT  93.12 0 93.144 0.192 ;
    END
  END aq_q[339]
  PIN aq_q[33]
    DIRECTION INPUT ;
    USE SIGNAL ;
    PORT
      LAYER M5 ;
        RECT  13.056 0 13.08 0.192 ;
    END
  END aq_q[33]
  PIN aq_q[340]
    DIRECTION INPUT ;
    USE SIGNAL ;
    PORT
      LAYER M3 ;
        RECT  93.384 0 93.402 0.144 ;
    END
  END aq_q[340]
  PIN aq_q[341]
    DIRECTION INPUT ;
    USE SIGNAL ;
    PORT
      LAYER M5 ;
        RECT  93.648 0 93.672 0.192 ;
    END
  END aq_q[341]
  PIN aq_q[342]
    DIRECTION INPUT ;
    USE SIGNAL ;
    PORT
      LAYER M3 ;
        RECT  93.888 0 93.906 0.144 ;
    END
  END aq_q[342]
  PIN aq_q[343]
    DIRECTION INPUT ;
    USE SIGNAL ;
    PORT
      LAYER M5 ;
        RECT  94.176 0 94.2 0.192 ;
    END
  END aq_q[343]
  PIN aq_q[344]
    DIRECTION INPUT ;
    USE SIGNAL ;
    PORT
      LAYER M3 ;
        RECT  94.428 0 94.446 0.144 ;
    END
  END aq_q[344]
  PIN aq_q[345]
    DIRECTION INPUT ;
    USE SIGNAL ;
    PORT
      LAYER M5 ;
        RECT  94.656 0 94.68 0.192 ;
    END
  END aq_q[345]
  PIN aq_q[346]
    DIRECTION INPUT ;
    USE SIGNAL ;
    PORT
      LAYER M3 ;
        RECT  94.932 0 94.95 0.144 ;
    END
  END aq_q[346]
  PIN aq_q[347]
    DIRECTION INPUT ;
    USE SIGNAL ;
    PORT
      LAYER M5 ;
        RECT  95.184 0 95.208 0.192 ;
    END
  END aq_q[347]
  PIN aq_q[348]
    DIRECTION INPUT ;
    USE SIGNAL ;
    PORT
      LAYER M3 ;
        RECT  95.472 0 95.49 0.144 ;
    END
  END aq_q[348]
  PIN aq_q[349]
    DIRECTION INPUT ;
    USE SIGNAL ;
    PORT
      LAYER M5 ;
        RECT  95.712 0 95.736 0.192 ;
    END
  END aq_q[349]
  PIN aq_q[34]
    DIRECTION INPUT ;
    USE SIGNAL ;
    PORT
      LAYER M3 ;
        RECT  13.32 0 13.338 0.144 ;
    END
  END aq_q[34]
  PIN aq_q[350]
    DIRECTION INPUT ;
    USE SIGNAL ;
    PORT
      LAYER M3 ;
        RECT  95.976 0 95.994 0.144 ;
    END
  END aq_q[350]
  PIN aq_q[351]
    DIRECTION INPUT ;
    USE SIGNAL ;
    PORT
      LAYER M5 ;
        RECT  96.24 0 96.264 0.192 ;
    END
  END aq_q[351]
  PIN aq_q[352]
    DIRECTION INPUT ;
    USE SIGNAL ;
    PORT
      LAYER M3 ;
        RECT  96.516 0 96.534 0.144 ;
    END
  END aq_q[352]
  PIN aq_q[353]
    DIRECTION INPUT ;
    USE SIGNAL ;
    PORT
      LAYER M5 ;
        RECT  96.768 0 96.792 0.192 ;
    END
  END aq_q[353]
  PIN aq_q[354]
    DIRECTION INPUT ;
    USE SIGNAL ;
    PORT
      LAYER M3 ;
        RECT  97.02 0 97.038 0.144 ;
    END
  END aq_q[354]
  PIN aq_q[355]
    DIRECTION INPUT ;
    USE SIGNAL ;
    PORT
      LAYER M5 ;
        RECT  97.296 0 97.32 0.192 ;
    END
  END aq_q[355]
  PIN aq_q[356]
    DIRECTION INPUT ;
    USE SIGNAL ;
    PORT
      LAYER M3 ;
        RECT  97.56 0 97.578 0.144 ;
    END
  END aq_q[356]
  PIN aq_q[357]
    DIRECTION INPUT ;
    USE SIGNAL ;
    PORT
      LAYER M5 ;
        RECT  97.824 0 97.848 0.192 ;
    END
  END aq_q[357]
  PIN aq_q[358]
    DIRECTION INPUT ;
    USE SIGNAL ;
    PORT
      LAYER M3 ;
        RECT  98.064 0 98.082 0.144 ;
    END
  END aq_q[358]
  PIN aq_q[359]
    DIRECTION INPUT ;
    USE SIGNAL ;
    PORT
      LAYER M5 ;
        RECT  98.352 0 98.376 0.192 ;
    END
  END aq_q[359]
  PIN aq_q[35]
    DIRECTION INPUT ;
    USE SIGNAL ;
    PORT
      LAYER M5 ;
        RECT  13.584 0 13.608 0.192 ;
    END
  END aq_q[35]
  PIN aq_q[360]
    DIRECTION INPUT ;
    USE SIGNAL ;
    PORT
      LAYER M3 ;
        RECT  98.604 0 98.622 0.144 ;
    END
  END aq_q[360]
  PIN aq_q[361]
    DIRECTION INPUT ;
    USE SIGNAL ;
    PORT
      LAYER M5 ;
        RECT  98.88 0 98.904 0.192 ;
    END
  END aq_q[361]
  PIN aq_q[362]
    DIRECTION INPUT ;
    USE SIGNAL ;
    PORT
      LAYER M3 ;
        RECT  99.144 0 99.162 0.144 ;
    END
  END aq_q[362]
  PIN aq_q[363]
    DIRECTION INPUT ;
    USE SIGNAL ;
    PORT
      LAYER M5 ;
        RECT  99.408 0 99.432 0.192 ;
    END
  END aq_q[363]
  PIN aq_q[364]
    DIRECTION INPUT ;
    USE SIGNAL ;
    PORT
      LAYER M3 ;
        RECT  99.648 0 99.666 0.144 ;
    END
  END aq_q[364]
  PIN aq_q[365]
    DIRECTION INPUT ;
    USE SIGNAL ;
    PORT
      LAYER M5 ;
        RECT  99.888 0 99.912 0.192 ;
    END
  END aq_q[365]
  PIN aq_q[366]
    DIRECTION INPUT ;
    USE SIGNAL ;
    PORT
      LAYER M3 ;
        RECT  100.188 0 100.206 0.144 ;
    END
  END aq_q[366]
  PIN aq_q[367]
    DIRECTION INPUT ;
    USE SIGNAL ;
    PORT
      LAYER M5 ;
        RECT  100.416 0 100.44 0.192 ;
    END
  END aq_q[367]
  PIN aq_q[368]
    DIRECTION INPUT ;
    USE SIGNAL ;
    PORT
      LAYER M3 ;
        RECT  100.692 0 100.71 0.144 ;
    END
  END aq_q[368]
  PIN aq_q[369]
    DIRECTION INPUT ;
    USE SIGNAL ;
    PORT
      LAYER M5 ;
        RECT  100.944 0 100.968 0.192 ;
    END
  END aq_q[369]
  PIN aq_q[36]
    DIRECTION INPUT ;
    USE SIGNAL ;
    PORT
      LAYER M3 ;
        RECT  13.86 0 13.878 0.144 ;
    END
  END aq_q[36]
  PIN aq_q[370]
    DIRECTION INPUT ;
    USE SIGNAL ;
    PORT
      LAYER M3 ;
        RECT  101.232 0 101.25 0.144 ;
    END
  END aq_q[370]
  PIN aq_q[371]
    DIRECTION INPUT ;
    USE SIGNAL ;
    PORT
      LAYER M5 ;
        RECT  101.472 0 101.496 0.192 ;
    END
  END aq_q[371]
  PIN aq_q[372]
    DIRECTION INPUT ;
    USE SIGNAL ;
    PORT
      LAYER M3 ;
        RECT  101.736 0 101.754 0.144 ;
    END
  END aq_q[372]
  PIN aq_q[373]
    DIRECTION INPUT ;
    USE SIGNAL ;
    PORT
      LAYER M5 ;
        RECT  102 0 102.024 0.192 ;
    END
  END aq_q[373]
  PIN aq_q[374]
    DIRECTION INPUT ;
    USE SIGNAL ;
    PORT
      LAYER M3 ;
        RECT  102.276 0 102.294 0.144 ;
    END
  END aq_q[374]
  PIN aq_q[375]
    DIRECTION INPUT ;
    USE SIGNAL ;
    PORT
      LAYER M5 ;
        RECT  102.528 0 102.552 0.192 ;
    END
  END aq_q[375]
  PIN aq_q[376]
    DIRECTION INPUT ;
    USE SIGNAL ;
    PORT
      LAYER M3 ;
        RECT  102.78 0 102.798 0.144 ;
    END
  END aq_q[376]
  PIN aq_q[377]
    DIRECTION INPUT ;
    USE SIGNAL ;
    PORT
      LAYER M5 ;
        RECT  103.056 0 103.08 0.192 ;
    END
  END aq_q[377]
  PIN aq_q[378]
    DIRECTION INPUT ;
    USE SIGNAL ;
    PORT
      LAYER M3 ;
        RECT  103.32 0 103.338 0.144 ;
    END
  END aq_q[378]
  PIN aq_q[379]
    DIRECTION INPUT ;
    USE SIGNAL ;
    PORT
      LAYER M5 ;
        RECT  103.584 0 103.608 0.192 ;
    END
  END aq_q[379]
  PIN aq_q[37]
    DIRECTION INPUT ;
    USE SIGNAL ;
    PORT
      LAYER M5 ;
        RECT  14.112 0 14.136 0.192 ;
    END
  END aq_q[37]
  PIN aq_q[380]
    DIRECTION INPUT ;
    USE SIGNAL ;
    PORT
      LAYER M3 ;
        RECT  103.824 0 103.842 0.144 ;
    END
  END aq_q[380]
  PIN aq_q[381]
    DIRECTION INPUT ;
    USE SIGNAL ;
    PORT
      LAYER M5 ;
        RECT  104.112 0 104.136 0.192 ;
    END
  END aq_q[381]
  PIN aq_q[382]
    DIRECTION INPUT ;
    USE SIGNAL ;
    PORT
      LAYER M3 ;
        RECT  104.364 0 104.382 0.144 ;
    END
  END aq_q[382]
  PIN aq_q[383]
    DIRECTION INPUT ;
    USE SIGNAL ;
    PORT
      LAYER M5 ;
        RECT  104.64 0 104.664 0.192 ;
    END
  END aq_q[383]
  PIN aq_q[384]
    DIRECTION INPUT ;
    USE SIGNAL ;
    PORT
      LAYER M3 ;
        RECT  104.868 0 104.886 0.144 ;
    END
  END aq_q[384]
  PIN aq_q[385]
    DIRECTION INPUT ;
    USE SIGNAL ;
    PORT
      LAYER M5 ;
        RECT  105.12 0 105.144 0.192 ;
    END
  END aq_q[385]
  PIN aq_q[386]
    DIRECTION INPUT ;
    USE SIGNAL ;
    PORT
      LAYER M3 ;
        RECT  105.408 0 105.426 0.144 ;
    END
  END aq_q[386]
  PIN aq_q[387]
    DIRECTION INPUT ;
    USE SIGNAL ;
    PORT
      LAYER M5 ;
        RECT  105.648 0 105.672 0.192 ;
    END
  END aq_q[387]
  PIN aq_q[388]
    DIRECTION INPUT ;
    USE SIGNAL ;
    PORT
      LAYER M3 ;
        RECT  105.912 0 105.93 0.144 ;
    END
  END aq_q[388]
  PIN aq_q[389]
    DIRECTION INPUT ;
    USE SIGNAL ;
    PORT
      LAYER M5 ;
        RECT  106.176 0 106.2 0.192 ;
    END
  END aq_q[389]
  PIN aq_q[38]
    DIRECTION INPUT ;
    USE SIGNAL ;
    PORT
      LAYER M3 ;
        RECT  14.364 0 14.382 0.144 ;
    END
  END aq_q[38]
  PIN aq_q[390]
    DIRECTION INPUT ;
    USE SIGNAL ;
    PORT
      LAYER M3 ;
        RECT  106.452 0 106.47 0.144 ;
    END
  END aq_q[390]
  PIN aq_q[391]
    DIRECTION INPUT ;
    USE SIGNAL ;
    PORT
      LAYER M5 ;
        RECT  106.704 0 106.728 0.192 ;
    END
  END aq_q[391]
  PIN aq_q[392]
    DIRECTION INPUT ;
    USE SIGNAL ;
    PORT
      LAYER M3 ;
        RECT  106.992 0 107.01 0.144 ;
    END
  END aq_q[392]
  PIN aq_q[393]
    DIRECTION INPUT ;
    USE SIGNAL ;
    PORT
      LAYER M5 ;
        RECT  107.232 0 107.256 0.192 ;
    END
  END aq_q[393]
  PIN aq_q[394]
    DIRECTION INPUT ;
    USE SIGNAL ;
    PORT
      LAYER M3 ;
        RECT  107.496 0 107.514 0.144 ;
    END
  END aq_q[394]
  PIN aq_q[395]
    DIRECTION INPUT ;
    USE SIGNAL ;
    PORT
      LAYER M5 ;
        RECT  107.76 0 107.784 0.192 ;
    END
  END aq_q[395]
  PIN aq_q[396]
    DIRECTION INPUT ;
    USE SIGNAL ;
    PORT
      LAYER M3 ;
        RECT  108.036 0 108.054 0.144 ;
    END
  END aq_q[396]
  PIN aq_q[397]
    DIRECTION INPUT ;
    USE SIGNAL ;
    PORT
      LAYER M5 ;
        RECT  108.288 0 108.312 0.192 ;
    END
  END aq_q[397]
  PIN aq_q[398]
    DIRECTION INPUT ;
    USE SIGNAL ;
    PORT
      LAYER M3 ;
        RECT  108.54 0 108.558 0.144 ;
    END
  END aq_q[398]
  PIN aq_q[399]
    DIRECTION INPUT ;
    USE SIGNAL ;
    PORT
      LAYER M5 ;
        RECT  108.816 0 108.84 0.192 ;
    END
  END aq_q[399]
  PIN aq_q[39]
    DIRECTION INPUT ;
    USE SIGNAL ;
    PORT
      LAYER M5 ;
        RECT  14.64 0 14.664 0.192 ;
    END
  END aq_q[39]
  PIN aq_q[3]
    DIRECTION INPUT ;
    USE SIGNAL ;
    PORT
      LAYER M5 ;
        RECT  5.232 0 5.256 0.192 ;
    END
  END aq_q[3]
  PIN aq_q[400]
    DIRECTION INPUT ;
    USE SIGNAL ;
    PORT
      LAYER M3 ;
        RECT  109.08 0 109.098 0.144 ;
    END
  END aq_q[400]
  PIN aq_q[401]
    DIRECTION INPUT ;
    USE SIGNAL ;
    PORT
      LAYER M5 ;
        RECT  109.344 0 109.368 0.192 ;
    END
  END aq_q[401]
  PIN aq_q[402]
    DIRECTION INPUT ;
    USE SIGNAL ;
    PORT
      LAYER M3 ;
        RECT  109.584 0 109.602 0.144 ;
    END
  END aq_q[402]
  PIN aq_q[403]
    DIRECTION INPUT ;
    USE SIGNAL ;
    PORT
      LAYER M5 ;
        RECT  109.872 0 109.896 0.192 ;
    END
  END aq_q[403]
  PIN aq_q[404]
    DIRECTION INPUT ;
    USE SIGNAL ;
    PORT
      LAYER M3 ;
        RECT  110.124 0 110.142 0.144 ;
    END
  END aq_q[404]
  PIN aq_q[405]
    DIRECTION INPUT ;
    USE SIGNAL ;
    PORT
      LAYER M5 ;
        RECT  110.352 0 110.376 0.192 ;
    END
  END aq_q[405]
  PIN aq_q[406]
    DIRECTION INPUT ;
    USE SIGNAL ;
    PORT
      LAYER M3 ;
        RECT  110.628 0 110.646 0.144 ;
    END
  END aq_q[406]
  PIN aq_q[407]
    DIRECTION INPUT ;
    USE SIGNAL ;
    PORT
      LAYER M5 ;
        RECT  110.88 0 110.904 0.192 ;
    END
  END aq_q[407]
  PIN aq_q[408]
    DIRECTION INPUT ;
    USE SIGNAL ;
    PORT
      LAYER M3 ;
        RECT  111.168 0 111.186 0.144 ;
    END
  END aq_q[408]
  PIN aq_q[409]
    DIRECTION INPUT ;
    USE SIGNAL ;
    PORT
      LAYER M5 ;
        RECT  111.408 0 111.432 0.192 ;
    END
  END aq_q[409]
  PIN aq_q[40]
    DIRECTION INPUT ;
    USE SIGNAL ;
    PORT
      LAYER M3 ;
        RECT  14.904 0 14.922 0.144 ;
    END
  END aq_q[40]
  PIN aq_q[410]
    DIRECTION INPUT ;
    USE SIGNAL ;
    PORT
      LAYER M3 ;
        RECT  111.672 0 111.69 0.144 ;
    END
  END aq_q[410]
  PIN aq_q[411]
    DIRECTION INPUT ;
    USE SIGNAL ;
    PORT
      LAYER M5 ;
        RECT  111.936 0 111.96 0.192 ;
    END
  END aq_q[411]
  PIN aq_q[412]
    DIRECTION INPUT ;
    USE SIGNAL ;
    PORT
      LAYER M3 ;
        RECT  112.212 0 112.23 0.144 ;
    END
  END aq_q[412]
  PIN aq_q[413]
    DIRECTION INPUT ;
    USE SIGNAL ;
    PORT
      LAYER M5 ;
        RECT  112.464 0 112.488 0.192 ;
    END
  END aq_q[413]
  PIN aq_q[414]
    DIRECTION INPUT ;
    USE SIGNAL ;
    PORT
      LAYER M3 ;
        RECT  112.716 0 112.734 0.144 ;
    END
  END aq_q[414]
  PIN aq_q[415]
    DIRECTION INPUT ;
    USE SIGNAL ;
    PORT
      LAYER M5 ;
        RECT  112.992 0 113.016 0.192 ;
    END
  END aq_q[415]
  PIN aq_q[416]
    DIRECTION INPUT ;
    USE SIGNAL ;
    PORT
      LAYER M3 ;
        RECT  113.256 0 113.274 0.144 ;
    END
  END aq_q[416]
  PIN aq_q[417]
    DIRECTION INPUT ;
    USE SIGNAL ;
    PORT
      LAYER M5 ;
        RECT  113.52 0 113.544 0.192 ;
    END
  END aq_q[417]
  PIN aq_q[418]
    DIRECTION INPUT ;
    USE SIGNAL ;
    PORT
      LAYER M3 ;
        RECT  113.76 0 113.778 0.144 ;
    END
  END aq_q[418]
  PIN aq_q[419]
    DIRECTION INPUT ;
    USE SIGNAL ;
    PORT
      LAYER M5 ;
        RECT  114.048 0 114.072 0.192 ;
    END
  END aq_q[419]
  PIN aq_q[41]
    DIRECTION INPUT ;
    USE SIGNAL ;
    PORT
      LAYER M5 ;
        RECT  15.168 0 15.192 0.192 ;
    END
  END aq_q[41]
  PIN aq_q[420]
    DIRECTION INPUT ;
    USE SIGNAL ;
    PORT
      LAYER M3 ;
        RECT  114.3 0 114.318 0.144 ;
    END
  END aq_q[420]
  PIN aq_q[421]
    DIRECTION INPUT ;
    USE SIGNAL ;
    PORT
      LAYER M5 ;
        RECT  114.576 0 114.6 0.192 ;
    END
  END aq_q[421]
  PIN aq_q[422]
    DIRECTION INPUT ;
    USE SIGNAL ;
    PORT
      LAYER M3 ;
        RECT  114.804 0 114.822 0.144 ;
    END
  END aq_q[422]
  PIN aq_q[423]
    DIRECTION INPUT ;
    USE SIGNAL ;
    PORT
      LAYER M5 ;
        RECT  115.056 0 115.08 0.192 ;
    END
  END aq_q[423]
  PIN aq_q[424]
    DIRECTION INPUT ;
    USE SIGNAL ;
    PORT
      LAYER M3 ;
        RECT  115.344 0 115.362 0.144 ;
    END
  END aq_q[424]
  PIN aq_q[425]
    DIRECTION INPUT ;
    USE SIGNAL ;
    PORT
      LAYER M5 ;
        RECT  115.584 0 115.608 0.192 ;
    END
  END aq_q[425]
  PIN aq_q[426]
    DIRECTION INPUT ;
    USE SIGNAL ;
    PORT
      LAYER M3 ;
        RECT  115.884 0 115.902 0.144 ;
    END
  END aq_q[426]
  PIN aq_q[427]
    DIRECTION INPUT ;
    USE SIGNAL ;
    PORT
      LAYER M5 ;
        RECT  116.112 0 116.136 0.192 ;
    END
  END aq_q[427]
  PIN aq_q[428]
    DIRECTION INPUT ;
    USE SIGNAL ;
    PORT
      LAYER M3 ;
        RECT  116.388 0 116.406 0.144 ;
    END
  END aq_q[428]
  PIN aq_q[429]
    DIRECTION INPUT ;
    USE SIGNAL ;
    PORT
      LAYER M5 ;
        RECT  116.64 0 116.664 0.192 ;
    END
  END aq_q[429]
  PIN aq_q[42]
    DIRECTION INPUT ;
    USE SIGNAL ;
    PORT
      LAYER M3 ;
        RECT  15.444 0 15.462 0.144 ;
    END
  END aq_q[42]
  PIN aq_q[430]
    DIRECTION INPUT ;
    USE SIGNAL ;
    PORT
      LAYER M3 ;
        RECT  116.928 0 116.946 0.144 ;
    END
  END aq_q[430]
  PIN aq_q[431]
    DIRECTION INPUT ;
    USE SIGNAL ;
    PORT
      LAYER M5 ;
        RECT  117.168 0 117.192 0.192 ;
    END
  END aq_q[431]
  PIN aq_q[432]
    DIRECTION INPUT ;
    USE SIGNAL ;
    PORT
      LAYER M3 ;
        RECT  117.432 0 117.45 0.144 ;
    END
  END aq_q[432]
  PIN aq_q[433]
    DIRECTION INPUT ;
    USE SIGNAL ;
    PORT
      LAYER M5 ;
        RECT  117.696 0 117.72 0.192 ;
    END
  END aq_q[433]
  PIN aq_q[434]
    DIRECTION INPUT ;
    USE SIGNAL ;
    PORT
      LAYER M3 ;
        RECT  117.972 0 117.99 0.144 ;
    END
  END aq_q[434]
  PIN aq_q[435]
    DIRECTION INPUT ;
    USE SIGNAL ;
    PORT
      LAYER M5 ;
        RECT  118.224 0 118.248 0.192 ;
    END
  END aq_q[435]
  PIN aq_q[436]
    DIRECTION INPUT ;
    USE SIGNAL ;
    PORT
      LAYER M3 ;
        RECT  118.476 0 118.494 0.144 ;
    END
  END aq_q[436]
  PIN aq_q[437]
    DIRECTION INPUT ;
    USE SIGNAL ;
    PORT
      LAYER M5 ;
        RECT  118.752 0 118.776 0.192 ;
    END
  END aq_q[437]
  PIN aq_q[438]
    DIRECTION INPUT ;
    USE SIGNAL ;
    PORT
      LAYER M3 ;
        RECT  119.016 0 119.034 0.144 ;
    END
  END aq_q[438]
  PIN aq_q[439]
    DIRECTION INPUT ;
    USE SIGNAL ;
    PORT
      LAYER M5 ;
        RECT  119.28 0 119.304 0.192 ;
    END
  END aq_q[439]
  PIN aq_q[43]
    DIRECTION INPUT ;
    USE SIGNAL ;
    PORT
      LAYER M5 ;
        RECT  15.696 0 15.72 0.192 ;
    END
  END aq_q[43]
  PIN aq_q[440]
    DIRECTION INPUT ;
    USE SIGNAL ;
    PORT
      LAYER M3 ;
        RECT  119.52 0 119.538 0.144 ;
    END
  END aq_q[440]
  PIN aq_q[441]
    DIRECTION INPUT ;
    USE SIGNAL ;
    PORT
      LAYER M5 ;
        RECT  119.808 0 119.832 0.192 ;
    END
  END aq_q[441]
  PIN aq_q[442]
    DIRECTION INPUT ;
    USE SIGNAL ;
    PORT
      LAYER M3 ;
        RECT  120.06 0 120.078 0.144 ;
    END
  END aq_q[442]
  PIN aq_q[443]
    DIRECTION INPUT ;
    USE SIGNAL ;
    PORT
      LAYER M5 ;
        RECT  120.288 0 120.312 0.192 ;
    END
  END aq_q[443]
  PIN aq_q[444]
    DIRECTION INPUT ;
    USE SIGNAL ;
    PORT
      LAYER M3 ;
        RECT  120.564 0 120.582 0.144 ;
    END
  END aq_q[444]
  PIN aq_q[445]
    DIRECTION INPUT ;
    USE SIGNAL ;
    PORT
      LAYER M5 ;
        RECT  120.816 0 120.84 0.192 ;
    END
  END aq_q[445]
  PIN aq_q[446]
    DIRECTION INPUT ;
    USE SIGNAL ;
    PORT
      LAYER M3 ;
        RECT  121.104 0 121.122 0.144 ;
    END
  END aq_q[446]
  PIN aq_q[447]
    DIRECTION INPUT ;
    USE SIGNAL ;
    PORT
      LAYER M5 ;
        RECT  121.344 0 121.368 0.192 ;
    END
  END aq_q[447]
  PIN aq_q[448]
    DIRECTION INPUT ;
    USE SIGNAL ;
    PORT
      LAYER M3 ;
        RECT  121.608 0 121.626 0.144 ;
    END
  END aq_q[448]
  PIN aq_q[449]
    DIRECTION INPUT ;
    USE SIGNAL ;
    PORT
      LAYER M5 ;
        RECT  121.872 0 121.896 0.192 ;
    END
  END aq_q[449]
  PIN aq_q[44]
    DIRECTION INPUT ;
    USE SIGNAL ;
    PORT
      LAYER M3 ;
        RECT  15.948 0 15.966 0.144 ;
    END
  END aq_q[44]
  PIN aq_q[450]
    DIRECTION INPUT ;
    USE SIGNAL ;
    PORT
      LAYER M3 ;
        RECT  122.148 0 122.166 0.144 ;
    END
  END aq_q[450]
  PIN aq_q[451]
    DIRECTION INPUT ;
    USE SIGNAL ;
    PORT
      LAYER M5 ;
        RECT  122.4 0 122.424 0.192 ;
    END
  END aq_q[451]
  PIN aq_q[452]
    DIRECTION INPUT ;
    USE SIGNAL ;
    PORT
      LAYER M3 ;
        RECT  122.652 0 122.67 0.144 ;
    END
  END aq_q[452]
  PIN aq_q[453]
    DIRECTION INPUT ;
    USE SIGNAL ;
    PORT
      LAYER M5 ;
        RECT  122.928 0 122.952 0.192 ;
    END
  END aq_q[453]
  PIN aq_q[454]
    DIRECTION INPUT ;
    USE SIGNAL ;
    PORT
      LAYER M3 ;
        RECT  123.192 0 123.21 0.144 ;
    END
  END aq_q[454]
  PIN aq_q[455]
    DIRECTION INPUT ;
    USE SIGNAL ;
    PORT
      LAYER M5 ;
        RECT  123.456 0 123.48 0.192 ;
    END
  END aq_q[455]
  PIN aq_q[456]
    DIRECTION INPUT ;
    USE SIGNAL ;
    PORT
      LAYER M3 ;
        RECT  123.732 0 123.75 0.144 ;
    END
  END aq_q[456]
  PIN aq_q[457]
    DIRECTION INPUT ;
    USE SIGNAL ;
    PORT
      LAYER M5 ;
        RECT  123.984 0 124.008 0.192 ;
    END
  END aq_q[457]
  PIN aq_q[458]
    DIRECTION INPUT ;
    USE SIGNAL ;
    PORT
      LAYER M3 ;
        RECT  124.236 0 124.254 0.144 ;
    END
  END aq_q[458]
  PIN aq_q[459]
    DIRECTION INPUT ;
    USE SIGNAL ;
    PORT
      LAYER M5 ;
        RECT  124.512 0 124.536 0.192 ;
    END
  END aq_q[459]
  PIN aq_q[45]
    DIRECTION INPUT ;
    USE SIGNAL ;
    PORT
      LAYER M5 ;
        RECT  16.224 0 16.248 0.192 ;
    END
  END aq_q[45]
  PIN aq_q[460]
    DIRECTION INPUT ;
    USE SIGNAL ;
    PORT
      LAYER M3 ;
        RECT  124.776 0 124.794 0.144 ;
    END
  END aq_q[460]
  PIN aq_q[461]
    DIRECTION INPUT ;
    USE SIGNAL ;
    PORT
      LAYER M5 ;
        RECT  125.04 0 125.064 0.192 ;
    END
  END aq_q[461]
  PIN aq_q[462]
    DIRECTION INPUT ;
    USE SIGNAL ;
    PORT
      LAYER M3 ;
        RECT  125.28 0 125.298 0.144 ;
    END
  END aq_q[462]
  PIN aq_q[463]
    DIRECTION INPUT ;
    USE SIGNAL ;
    PORT
      LAYER M5 ;
        RECT  125.52 0 125.544 0.192 ;
    END
  END aq_q[463]
  PIN aq_q[464]
    DIRECTION INPUT ;
    USE SIGNAL ;
    PORT
      LAYER M3 ;
        RECT  125.82 0 125.838 0.144 ;
    END
  END aq_q[464]
  PIN aq_q[465]
    DIRECTION INPUT ;
    USE SIGNAL ;
    PORT
      LAYER M5 ;
        RECT  126.048 0 126.072 0.192 ;
    END
  END aq_q[465]
  PIN aq_q[466]
    DIRECTION INPUT ;
    USE SIGNAL ;
    PORT
      LAYER M3 ;
        RECT  126.324 0 126.342 0.144 ;
    END
  END aq_q[466]
  PIN aq_q[467]
    DIRECTION INPUT ;
    USE SIGNAL ;
    PORT
      LAYER M5 ;
        RECT  126.576 0 126.6 0.192 ;
    END
  END aq_q[467]
  PIN aq_q[468]
    DIRECTION INPUT ;
    USE SIGNAL ;
    PORT
      LAYER M3 ;
        RECT  126.864 0 126.882 0.144 ;
    END
  END aq_q[468]
  PIN aq_q[469]
    DIRECTION INPUT ;
    USE SIGNAL ;
    PORT
      LAYER M5 ;
        RECT  127.104 0 127.128 0.192 ;
    END
  END aq_q[469]
  PIN aq_q[46]
    DIRECTION INPUT ;
    USE SIGNAL ;
    PORT
      LAYER M3 ;
        RECT  16.488 0 16.506 0.144 ;
    END
  END aq_q[46]
  PIN aq_q[470]
    DIRECTION INPUT ;
    USE SIGNAL ;
    PORT
      LAYER M3 ;
        RECT  127.368 0 127.386 0.144 ;
    END
  END aq_q[470]
  PIN aq_q[471]
    DIRECTION INPUT ;
    USE SIGNAL ;
    PORT
      LAYER M5 ;
        RECT  127.632 0 127.656 0.192 ;
    END
  END aq_q[471]
  PIN aq_q[472]
    DIRECTION INPUT ;
    USE SIGNAL ;
    PORT
      LAYER M3 ;
        RECT  127.908 0 127.926 0.144 ;
    END
  END aq_q[472]
  PIN aq_q[473]
    DIRECTION INPUT ;
    USE SIGNAL ;
    PORT
      LAYER M5 ;
        RECT  128.16 0 128.184 0.192 ;
    END
  END aq_q[473]
  PIN aq_q[474]
    DIRECTION INPUT ;
    USE SIGNAL ;
    PORT
      LAYER M3 ;
        RECT  128.412 0 128.43 0.144 ;
    END
  END aq_q[474]
  PIN aq_q[475]
    DIRECTION INPUT ;
    USE SIGNAL ;
    PORT
      LAYER M5 ;
        RECT  128.688 0 128.712 0.192 ;
    END
  END aq_q[475]
  PIN aq_q[476]
    DIRECTION INPUT ;
    USE SIGNAL ;
    PORT
      LAYER M3 ;
        RECT  128.952 0 128.97 0.144 ;
    END
  END aq_q[476]
  PIN aq_q[477]
    DIRECTION INPUT ;
    USE SIGNAL ;
    PORT
      LAYER M5 ;
        RECT  129.216 0 129.24 0.192 ;
    END
  END aq_q[477]
  PIN aq_q[478]
    DIRECTION INPUT ;
    USE SIGNAL ;
    PORT
      LAYER M3 ;
        RECT  129.456 0 129.474 0.144 ;
    END
  END aq_q[478]
  PIN aq_q[479]
    DIRECTION INPUT ;
    USE SIGNAL ;
    PORT
      LAYER M5 ;
        RECT  129.744 0 129.768 0.192 ;
    END
  END aq_q[479]
  PIN aq_q[47]
    DIRECTION INPUT ;
    USE SIGNAL ;
    PORT
      LAYER M5 ;
        RECT  16.752 0 16.776 0.192 ;
    END
  END aq_q[47]
  PIN aq_q[480]
    DIRECTION INPUT ;
    USE SIGNAL ;
    PORT
      LAYER M3 ;
        RECT  129.996 0 130.014 0.144 ;
    END
  END aq_q[480]
  PIN aq_q[481]
    DIRECTION INPUT ;
    USE SIGNAL ;
    PORT
      LAYER M5 ;
        RECT  130.272 0 130.296 0.192 ;
    END
  END aq_q[481]
  PIN aq_q[482]
    DIRECTION INPUT ;
    USE SIGNAL ;
    PORT
      LAYER M3 ;
        RECT  130.5 0 130.518 0.144 ;
    END
  END aq_q[482]
  PIN aq_q[483]
    DIRECTION INPUT ;
    USE SIGNAL ;
    PORT
      LAYER M5 ;
        RECT  130.752 0 130.776 0.192 ;
    END
  END aq_q[483]
  PIN aq_q[484]
    DIRECTION INPUT ;
    USE SIGNAL ;
    PORT
      LAYER M3 ;
        RECT  131.04 0 131.058 0.144 ;
    END
  END aq_q[484]
  PIN aq_q[485]
    DIRECTION INPUT ;
    USE SIGNAL ;
    PORT
      LAYER M5 ;
        RECT  131.28 0 131.304 0.192 ;
    END
  END aq_q[485]
  PIN aq_q[486]
    DIRECTION INPUT ;
    USE SIGNAL ;
    PORT
      LAYER M3 ;
        RECT  131.544 0 131.562 0.144 ;
    END
  END aq_q[486]
  PIN aq_q[487]
    DIRECTION INPUT ;
    USE SIGNAL ;
    PORT
      LAYER M5 ;
        RECT  131.808 0 131.832 0.192 ;
    END
  END aq_q[487]
  PIN aq_q[488]
    DIRECTION INPUT ;
    USE SIGNAL ;
    PORT
      LAYER M3 ;
        RECT  132.084 0 132.102 0.144 ;
    END
  END aq_q[488]
  PIN aq_q[489]
    DIRECTION INPUT ;
    USE SIGNAL ;
    PORT
      LAYER M5 ;
        RECT  132.336 0 132.36 0.192 ;
    END
  END aq_q[489]
  PIN aq_q[48]
    DIRECTION INPUT ;
    USE SIGNAL ;
    PORT
      LAYER M3 ;
        RECT  16.992 0 17.01 0.144 ;
    END
  END aq_q[48]
  PIN aq_q[490]
    DIRECTION INPUT ;
    USE SIGNAL ;
    PORT
      LAYER M3 ;
        RECT  132.624 0 132.642 0.144 ;
    END
  END aq_q[490]
  PIN aq_q[491]
    DIRECTION INPUT ;
    USE SIGNAL ;
    PORT
      LAYER M5 ;
        RECT  132.864 0 132.888 0.192 ;
    END
  END aq_q[491]
  PIN aq_q[492]
    DIRECTION INPUT ;
    USE SIGNAL ;
    PORT
      LAYER M3 ;
        RECT  133.128 0 133.146 0.144 ;
    END
  END aq_q[492]
  PIN aq_q[493]
    DIRECTION INPUT ;
    USE SIGNAL ;
    PORT
      LAYER M5 ;
        RECT  133.392 0 133.416 0.192 ;
    END
  END aq_q[493]
  PIN aq_q[494]
    DIRECTION INPUT ;
    USE SIGNAL ;
    PORT
      LAYER M3 ;
        RECT  133.668 0 133.686 0.144 ;
    END
  END aq_q[494]
  PIN aq_q[495]
    DIRECTION INPUT ;
    USE SIGNAL ;
    PORT
      LAYER M5 ;
        RECT  133.92 0 133.944 0.192 ;
    END
  END aq_q[495]
  PIN aq_q[496]
    DIRECTION INPUT ;
    USE SIGNAL ;
    PORT
      LAYER M3 ;
        RECT  134.172 0 134.19 0.144 ;
    END
  END aq_q[496]
  PIN aq_q[497]
    DIRECTION INPUT ;
    USE SIGNAL ;
    PORT
      LAYER M5 ;
        RECT  134.448 0 134.472 0.192 ;
    END
  END aq_q[497]
  PIN aq_q[498]
    DIRECTION INPUT ;
    USE SIGNAL ;
    PORT
      LAYER M3 ;
        RECT  134.712 0 134.73 0.144 ;
    END
  END aq_q[498]
  PIN aq_q[499]
    DIRECTION INPUT ;
    USE SIGNAL ;
    PORT
      LAYER M5 ;
        RECT  134.976 0 135 0.192 ;
    END
  END aq_q[499]
  PIN aq_q[49]
    DIRECTION INPUT ;
    USE SIGNAL ;
    PORT
      LAYER M5 ;
        RECT  17.232 0 17.256 0.192 ;
    END
  END aq_q[49]
  PIN aq_q[4]
    DIRECTION INPUT ;
    USE SIGNAL ;
    PORT
      LAYER M3 ;
        RECT  5.472 0 5.49 0.144 ;
    END
  END aq_q[4]
  PIN aq_q[500]
    DIRECTION INPUT ;
    USE SIGNAL ;
    PORT
      LAYER M3 ;
        RECT  135.216 0 135.234 0.144 ;
    END
  END aq_q[500]
  PIN aq_q[501]
    DIRECTION INPUT ;
    USE SIGNAL ;
    PORT
      LAYER M5 ;
        RECT  135.504 0 135.528 0.192 ;
    END
  END aq_q[501]
  PIN aq_q[502]
    DIRECTION INPUT ;
    USE SIGNAL ;
    PORT
      LAYER M3 ;
        RECT  135.756 0 135.774 0.144 ;
    END
  END aq_q[502]
  PIN aq_q[503]
    DIRECTION INPUT ;
    USE SIGNAL ;
    PORT
      LAYER M5 ;
        RECT  135.984 0 136.008 0.192 ;
    END
  END aq_q[503]
  PIN aq_q[504]
    DIRECTION INPUT ;
    USE SIGNAL ;
    PORT
      LAYER M3 ;
        RECT  136.26 0 136.278 0.144 ;
    END
  END aq_q[504]
  PIN aq_q[505]
    DIRECTION INPUT ;
    USE SIGNAL ;
    PORT
      LAYER M5 ;
        RECT  136.512 0 136.536 0.192 ;
    END
  END aq_q[505]
  PIN aq_q[506]
    DIRECTION INPUT ;
    USE SIGNAL ;
    PORT
      LAYER M3 ;
        RECT  136.8 0 136.818 0.144 ;
    END
  END aq_q[506]
  PIN aq_q[507]
    DIRECTION INPUT ;
    USE SIGNAL ;
    PORT
      LAYER M5 ;
        RECT  137.04 0 137.064 0.192 ;
    END
  END aq_q[507]
  PIN aq_q[508]
    DIRECTION INPUT ;
    USE SIGNAL ;
    PORT
      LAYER M3 ;
        RECT  137.304 0 137.322 0.144 ;
    END
  END aq_q[508]
  PIN aq_q[509]
    DIRECTION INPUT ;
    USE SIGNAL ;
    PORT
      LAYER M5 ;
        RECT  137.568 0 137.592 0.192 ;
    END
  END aq_q[509]
  PIN aq_q[50]
    DIRECTION INPUT ;
    USE SIGNAL ;
    PORT
      LAYER M3 ;
        RECT  17.532 0 17.55 0.144 ;
    END
  END aq_q[50]
  PIN aq_q[510]
    DIRECTION INPUT ;
    USE SIGNAL ;
    PORT
      LAYER M3 ;
        RECT  137.844 0 137.862 0.144 ;
    END
  END aq_q[510]
  PIN aq_q[511]
    DIRECTION INPUT ;
    USE SIGNAL ;
    PORT
      LAYER M5 ;
        RECT  138.096 0 138.12 0.192 ;
    END
  END aq_q[511]
  PIN aq_q[51]
    DIRECTION INPUT ;
    USE SIGNAL ;
    PORT
      LAYER M5 ;
        RECT  17.76 0 17.784 0.192 ;
    END
  END aq_q[51]
  PIN aq_q[52]
    DIRECTION INPUT ;
    USE SIGNAL ;
    PORT
      LAYER M3 ;
        RECT  18.036 0 18.054 0.144 ;
    END
  END aq_q[52]
  PIN aq_q[53]
    DIRECTION INPUT ;
    USE SIGNAL ;
    PORT
      LAYER M5 ;
        RECT  18.288 0 18.312 0.192 ;
    END
  END aq_q[53]
  PIN aq_q[54]
    DIRECTION INPUT ;
    USE SIGNAL ;
    PORT
      LAYER M3 ;
        RECT  18.576 0 18.594 0.144 ;
    END
  END aq_q[54]
  PIN aq_q[55]
    DIRECTION INPUT ;
    USE SIGNAL ;
    PORT
      LAYER M5 ;
        RECT  18.816 0 18.84 0.192 ;
    END
  END aq_q[55]
  PIN aq_q[56]
    DIRECTION INPUT ;
    USE SIGNAL ;
    PORT
      LAYER M3 ;
        RECT  19.08 0 19.098 0.144 ;
    END
  END aq_q[56]
  PIN aq_q[57]
    DIRECTION INPUT ;
    USE SIGNAL ;
    PORT
      LAYER M5 ;
        RECT  19.344 0 19.368 0.192 ;
    END
  END aq_q[57]
  PIN aq_q[58]
    DIRECTION INPUT ;
    USE SIGNAL ;
    PORT
      LAYER M3 ;
        RECT  19.62 0 19.638 0.144 ;
    END
  END aq_q[58]
  PIN aq_q[59]
    DIRECTION INPUT ;
    USE SIGNAL ;
    PORT
      LAYER M5 ;
        RECT  19.872 0 19.896 0.192 ;
    END
  END aq_q[59]
  PIN aq_q[5]
    DIRECTION INPUT ;
    USE SIGNAL ;
    PORT
      LAYER M5 ;
        RECT  5.76 0 5.784 0.192 ;
    END
  END aq_q[5]
  PIN aq_q[60]
    DIRECTION INPUT ;
    USE SIGNAL ;
    PORT
      LAYER M3 ;
        RECT  20.124 0 20.142 0.144 ;
    END
  END aq_q[60]
  PIN aq_q[61]
    DIRECTION INPUT ;
    USE SIGNAL ;
    PORT
      LAYER M5 ;
        RECT  20.4 0 20.424 0.192 ;
    END
  END aq_q[61]
  PIN aq_q[62]
    DIRECTION INPUT ;
    USE SIGNAL ;
    PORT
      LAYER M3 ;
        RECT  20.664 0 20.682 0.144 ;
    END
  END aq_q[62]
  PIN aq_q[63]
    DIRECTION INPUT ;
    USE SIGNAL ;
    PORT
      LAYER M5 ;
        RECT  20.928 0 20.952 0.192 ;
    END
  END aq_q[63]
  PIN aq_q[64]
    DIRECTION INPUT ;
    USE SIGNAL ;
    PORT
      LAYER M3 ;
        RECT  21.168 0 21.186 0.144 ;
    END
  END aq_q[64]
  PIN aq_q[65]
    DIRECTION INPUT ;
    USE SIGNAL ;
    PORT
      LAYER M5 ;
        RECT  21.456 0 21.48 0.192 ;
    END
  END aq_q[65]
  PIN aq_q[66]
    DIRECTION INPUT ;
    USE SIGNAL ;
    PORT
      LAYER M3 ;
        RECT  21.708 0 21.726 0.144 ;
    END
  END aq_q[66]
  PIN aq_q[67]
    DIRECTION INPUT ;
    USE SIGNAL ;
    PORT
      LAYER M5 ;
        RECT  21.984 0 22.008 0.192 ;
    END
  END aq_q[67]
  PIN aq_q[68]
    DIRECTION INPUT ;
    USE SIGNAL ;
    PORT
      LAYER M3 ;
        RECT  22.212 0 22.23 0.144 ;
    END
  END aq_q[68]
  PIN aq_q[69]
    DIRECTION INPUT ;
    USE SIGNAL ;
    PORT
      LAYER M5 ;
        RECT  22.464 0 22.488 0.192 ;
    END
  END aq_q[69]
  PIN aq_q[6]
    DIRECTION INPUT ;
    USE SIGNAL ;
    PORT
      LAYER M3 ;
        RECT  6.012 0 6.03 0.144 ;
    END
  END aq_q[6]
  PIN aq_q[70]
    DIRECTION INPUT ;
    USE SIGNAL ;
    PORT
      LAYER M3 ;
        RECT  22.752 0 22.77 0.144 ;
    END
  END aq_q[70]
  PIN aq_q[71]
    DIRECTION INPUT ;
    USE SIGNAL ;
    PORT
      LAYER M5 ;
        RECT  22.992 0 23.016 0.192 ;
    END
  END aq_q[71]
  PIN aq_q[72]
    DIRECTION INPUT ;
    USE SIGNAL ;
    PORT
      LAYER M3 ;
        RECT  23.292 0 23.31 0.144 ;
    END
  END aq_q[72]
  PIN aq_q[73]
    DIRECTION INPUT ;
    USE SIGNAL ;
    PORT
      LAYER M5 ;
        RECT  23.52 0 23.544 0.192 ;
    END
  END aq_q[73]
  PIN aq_q[74]
    DIRECTION INPUT ;
    USE SIGNAL ;
    PORT
      LAYER M3 ;
        RECT  23.796 0 23.814 0.144 ;
    END
  END aq_q[74]
  PIN aq_q[75]
    DIRECTION INPUT ;
    USE SIGNAL ;
    PORT
      LAYER M5 ;
        RECT  24.048 0 24.072 0.192 ;
    END
  END aq_q[75]
  PIN aq_q[76]
    DIRECTION INPUT ;
    USE SIGNAL ;
    PORT
      LAYER M3 ;
        RECT  24.336 0 24.354 0.144 ;
    END
  END aq_q[76]
  PIN aq_q[77]
    DIRECTION INPUT ;
    USE SIGNAL ;
    PORT
      LAYER M5 ;
        RECT  24.576 0 24.6 0.192 ;
    END
  END aq_q[77]
  PIN aq_q[78]
    DIRECTION INPUT ;
    USE SIGNAL ;
    PORT
      LAYER M3 ;
        RECT  24.84 0 24.858 0.144 ;
    END
  END aq_q[78]
  PIN aq_q[79]
    DIRECTION INPUT ;
    USE SIGNAL ;
    PORT
      LAYER M5 ;
        RECT  25.104 0 25.128 0.192 ;
    END
  END aq_q[79]
  PIN aq_q[7]
    DIRECTION INPUT ;
    USE SIGNAL ;
    PORT
      LAYER M5 ;
        RECT  6.288 0 6.312 0.192 ;
    END
  END aq_q[7]
  PIN aq_q[80]
    DIRECTION INPUT ;
    USE SIGNAL ;
    PORT
      LAYER M3 ;
        RECT  25.38 0 25.398 0.144 ;
    END
  END aq_q[80]
  PIN aq_q[81]
    DIRECTION INPUT ;
    USE SIGNAL ;
    PORT
      LAYER M5 ;
        RECT  25.632 0 25.656 0.192 ;
    END
  END aq_q[81]
  PIN aq_q[82]
    DIRECTION INPUT ;
    USE SIGNAL ;
    PORT
      LAYER M3 ;
        RECT  25.884 0 25.902 0.144 ;
    END
  END aq_q[82]
  PIN aq_q[83]
    DIRECTION INPUT ;
    USE SIGNAL ;
    PORT
      LAYER M5 ;
        RECT  26.16 0 26.184 0.192 ;
    END
  END aq_q[83]
  PIN aq_q[84]
    DIRECTION INPUT ;
    USE SIGNAL ;
    PORT
      LAYER M3 ;
        RECT  26.424 0 26.442 0.144 ;
    END
  END aq_q[84]
  PIN aq_q[85]
    DIRECTION INPUT ;
    USE SIGNAL ;
    PORT
      LAYER M5 ;
        RECT  26.688 0 26.712 0.192 ;
    END
  END aq_q[85]
  PIN aq_q[86]
    DIRECTION INPUT ;
    USE SIGNAL ;
    PORT
      LAYER M3 ;
        RECT  26.928 0 26.946 0.144 ;
    END
  END aq_q[86]
  PIN aq_q[87]
    DIRECTION INPUT ;
    USE SIGNAL ;
    PORT
      LAYER M5 ;
        RECT  27.216 0 27.24 0.192 ;
    END
  END aq_q[87]
  PIN aq_q[88]
    DIRECTION INPUT ;
    USE SIGNAL ;
    PORT
      LAYER M3 ;
        RECT  27.468 0 27.486 0.144 ;
    END
  END aq_q[88]
  PIN aq_q[89]
    DIRECTION INPUT ;
    USE SIGNAL ;
    PORT
      LAYER M5 ;
        RECT  27.696 0 27.72 0.192 ;
    END
  END aq_q[89]
  PIN aq_q[8]
    DIRECTION INPUT ;
    USE SIGNAL ;
    PORT
      LAYER M3 ;
        RECT  6.552 0 6.57 0.144 ;
    END
  END aq_q[8]
  PIN aq_q[90]
    DIRECTION INPUT ;
    USE SIGNAL ;
    PORT
      LAYER M3 ;
        RECT  27.972 0 27.99 0.144 ;
    END
  END aq_q[90]
  PIN aq_q[91]
    DIRECTION INPUT ;
    USE SIGNAL ;
    PORT
      LAYER M5 ;
        RECT  28.224 0 28.248 0.192 ;
    END
  END aq_q[91]
  PIN aq_q[92]
    DIRECTION INPUT ;
    USE SIGNAL ;
    PORT
      LAYER M3 ;
        RECT  28.512 0 28.53 0.144 ;
    END
  END aq_q[92]
  PIN aq_q[93]
    DIRECTION INPUT ;
    USE SIGNAL ;
    PORT
      LAYER M5 ;
        RECT  28.752 0 28.776 0.192 ;
    END
  END aq_q[93]
  PIN aq_q[94]
    DIRECTION INPUT ;
    USE SIGNAL ;
    PORT
      LAYER M3 ;
        RECT  29.016 0 29.034 0.144 ;
    END
  END aq_q[94]
  PIN aq_q[95]
    DIRECTION INPUT ;
    USE SIGNAL ;
    PORT
      LAYER M5 ;
        RECT  29.28 0 29.304 0.192 ;
    END
  END aq_q[95]
  PIN aq_q[96]
    DIRECTION INPUT ;
    USE SIGNAL ;
    PORT
      LAYER M3 ;
        RECT  29.556 0 29.574 0.144 ;
    END
  END aq_q[96]
  PIN aq_q[97]
    DIRECTION INPUT ;
    USE SIGNAL ;
    PORT
      LAYER M5 ;
        RECT  29.808 0 29.832 0.192 ;
    END
  END aq_q[97]
  PIN aq_q[98]
    DIRECTION INPUT ;
    USE SIGNAL ;
    PORT
      LAYER M3 ;
        RECT  30.06 0 30.078 0.144 ;
    END
  END aq_q[98]
  PIN aq_q[99]
    DIRECTION INPUT ;
    USE SIGNAL ;
    PORT
      LAYER M5 ;
        RECT  30.336 0 30.36 0.192 ;
    END
  END aq_q[99]
  PIN aq_q[9]
    DIRECTION INPUT ;
    USE SIGNAL ;
    PORT
      LAYER M5 ;
        RECT  6.816 0 6.84 0.192 ;
    END
  END aq_q[9]
  PIN clk
    DIRECTION INPUT ;
    USE SIGNAL ;
    PORT
      LAYER M4 ;
        RECT  0 42.48 0.192 42.504 ;
    END
    PORT
      LAYER M4 ;
        RECT  0.156 42.48 2.408 42.504 ;
    END
  END clk
  PIN i0[0]
    DIRECTION INPUT ;
    USE SIGNAL ;
    PORT
      LAYER M4 ;
        RECT  0 30.48 0.192 30.504 ;
    END
  END i0[0]
  PIN i0[10]
    DIRECTION INPUT ;
    USE SIGNAL ;
    PORT
      LAYER M4 ;
        RECT  0 46.944 0.192 46.968 ;
    END
  END i0[10]
  PIN i0[11]
    DIRECTION INPUT ;
    USE SIGNAL ;
    PORT
      LAYER M4 ;
        RECT  0 48.432 0.192 48.456 ;
    END
  END i0[11]
  PIN i0[12]
    DIRECTION INPUT ;
    USE SIGNAL ;
    PORT
      LAYER M4 ;
        RECT  0 49.92 0.192 49.944 ;
    END
  END i0[12]
  PIN i0[13]
    DIRECTION INPUT ;
    USE SIGNAL ;
    PORT
      LAYER M4 ;
        RECT  0 51.456 0.192 51.48 ;
    END
  END i0[13]
  PIN i0[14]
    DIRECTION INPUT ;
    USE SIGNAL ;
    PORT
      LAYER M4 ;
        RECT  0 52.944 0.192 52.968 ;
    END
  END i0[14]
  PIN i0[15]
    DIRECTION INPUT ;
    USE SIGNAL ;
    PORT
      LAYER M4 ;
        RECT  0 54.432 0.192 54.456 ;
    END
  END i0[15]
  PIN i0[1]
    DIRECTION INPUT ;
    USE SIGNAL ;
    PORT
      LAYER M4 ;
        RECT  0 32.016 0.192 32.04 ;
    END
    PORT
      LAYER M4 ;
        RECT  0.156 32.016 0.569 32.04 ;
    END
  END i0[1]
  PIN i0[2]
    DIRECTION INPUT ;
    USE SIGNAL ;
    PORT
      LAYER M4 ;
        RECT  0 33.504 0.192 33.528 ;
    END
    PORT
      LAYER M4 ;
        RECT  0.156 33.504 0.245 33.528 ;
    END
  END i0[2]
  PIN i0[3]
    DIRECTION INPUT ;
    USE SIGNAL ;
    PORT
      LAYER M4 ;
        RECT  0 34.992 0.192 35.016 ;
    END
  END i0[3]
  PIN i0[4]
    DIRECTION INPUT ;
    USE SIGNAL ;
    PORT
      LAYER M4 ;
        RECT  0 36.48 0.192 36.504 ;
    END
    PORT
      LAYER M4 ;
        RECT  0.156 36.48 0.245 36.504 ;
    END
  END i0[4]
  PIN i0[5]
    DIRECTION INPUT ;
    USE SIGNAL ;
    PORT
      LAYER M4 ;
        RECT  0 37.968 0.192 37.992 ;
    END
    PORT
      LAYER M4 ;
        RECT  0.156 37.968 0.245 37.992 ;
    END
  END i0[5]
  PIN i0[6]
    DIRECTION INPUT ;
    USE SIGNAL ;
    PORT
      LAYER M4 ;
        RECT  0 39.456 0.192 39.48 ;
    END
    PORT
      LAYER M4 ;
        RECT  0.156 39.456 0.245 39.48 ;
    END
  END i0[6]
  PIN i0[7]
    DIRECTION INPUT ;
    USE SIGNAL ;
    PORT
      LAYER M4 ;
        RECT  0 40.992 0.192 41.016 ;
    END
    PORT
      LAYER M4 ;
        RECT  0.156 40.992 0.245 41.016 ;
    END
  END i0[7]
  PIN i0[8]
    DIRECTION INPUT ;
    USE SIGNAL ;
    PORT
      LAYER M4 ;
        RECT  0 43.968 0.192 43.992 ;
    END
    PORT
      LAYER M4 ;
        RECT  0.156 43.968 0.245 43.992 ;
    END
  END i0[8]
  PIN i0[9]
    DIRECTION INPUT ;
    USE SIGNAL ;
    PORT
      LAYER M4 ;
        RECT  0 45.456 0.192 45.48 ;
    END
  END i0[9]
  PIN i1[0]
    DIRECTION INPUT ;
    USE SIGNAL ;
    PORT
      LAYER M4 ;
        RECT  0 55.92 0.192 55.944 ;
    END
  END i1[0]
  PIN i1[10]
    DIRECTION INPUT ;
    USE SIGNAL ;
    PORT
      LAYER M4 ;
        RECT  0 70.896 0.192 70.92 ;
    END
  END i1[10]
  PIN i1[11]
    DIRECTION INPUT ;
    USE SIGNAL ;
    PORT
      LAYER M4 ;
        RECT  0 72.384 0.192 72.408 ;
    END
  END i1[11]
  PIN i1[12]
    DIRECTION INPUT ;
    USE SIGNAL ;
    PORT
      LAYER M4 ;
        RECT  0 73.872 0.192 73.896 ;
    END
  END i1[12]
  PIN i1[13]
    DIRECTION INPUT ;
    USE SIGNAL ;
    PORT
      LAYER M4 ;
        RECT  0 75.36 0.192 75.384 ;
    END
  END i1[13]
  PIN i1[14]
    DIRECTION INPUT ;
    USE SIGNAL ;
    PORT
      LAYER M4 ;
        RECT  0 76.848 0.192 76.872 ;
    END
  END i1[14]
  PIN i1[15]
    DIRECTION INPUT ;
    USE SIGNAL ;
    PORT
      LAYER M4 ;
        RECT  0 78.336 0.192 78.36 ;
    END
  END i1[15]
  PIN i1[1]
    DIRECTION INPUT ;
    USE SIGNAL ;
    PORT
      LAYER M4 ;
        RECT  0 57.408 0.192 57.432 ;
    END
    PORT
      LAYER M4 ;
        RECT  0.156 57.408 0.245 57.432 ;
    END
  END i1[1]
  PIN i1[2]
    DIRECTION INPUT ;
    USE SIGNAL ;
    PORT
      LAYER M4 ;
        RECT  0 58.896 0.192 58.92 ;
    END
    PORT
      LAYER M4 ;
        RECT  0.156 58.896 0.245 58.92 ;
    END
  END i1[2]
  PIN i1[3]
    DIRECTION INPUT ;
    USE SIGNAL ;
    PORT
      LAYER M4 ;
        RECT  0 60.432 0.192 60.456 ;
    END
  END i1[3]
  PIN i1[4]
    DIRECTION INPUT ;
    USE SIGNAL ;
    PORT
      LAYER M4 ;
        RECT  0 61.92 0.192 61.944 ;
    END
    PORT
      LAYER M4 ;
        RECT  0.156 61.92 0.245 61.944 ;
    END
  END i1[4]
  PIN i1[5]
    DIRECTION INPUT ;
    USE SIGNAL ;
    PORT
      LAYER M4 ;
        RECT  0 63.408 0.192 63.432 ;
    END
    PORT
      LAYER M4 ;
        RECT  0.156 63.408 2.408 63.432 ;
    END
  END i1[5]
  PIN i1[6]
    DIRECTION INPUT ;
    USE SIGNAL ;
    PORT
      LAYER M4 ;
        RECT  0 64.896 0.192 64.92 ;
    END
    PORT
      LAYER M4 ;
        RECT  0.156 64.896 0.245 64.92 ;
    END
  END i1[6]
  PIN i1[7]
    DIRECTION INPUT ;
    USE SIGNAL ;
    PORT
      LAYER M4 ;
        RECT  0 66.384 0.192 66.408 ;
    END
    PORT
      LAYER M4 ;
        RECT  0.156 66.384 0.245 66.408 ;
    END
  END i1[7]
  PIN i1[8]
    DIRECTION INPUT ;
    USE SIGNAL ;
    PORT
      LAYER M4 ;
        RECT  0 67.872 0.192 67.896 ;
    END
    PORT
      LAYER M4 ;
        RECT  0.156 67.872 0.245 67.896 ;
    END
  END i1[8]
  PIN i1[9]
    DIRECTION INPUT ;
    USE SIGNAL ;
    PORT
      LAYER M4 ;
        RECT  0 69.36 0.192 69.384 ;
    END
  END i1[9]
  PIN rd[0]
    DIRECTION OUTPUT ;
    USE SIGNAL ;
    PORT
      LAYER M3 ;
        RECT  4.572 86.256 4.59 86.4 ;
    END
    PORT
      LAYER M3 ;
        RECT  4.572 83.831 4.59 86.268 ;
    END
  END rd[0]
  PIN rd[100]
    DIRECTION OUTPUT ;
    USE SIGNAL ;
    PORT
      LAYER M3 ;
        RECT  56.88 86.256 56.898 86.4 ;
    END
    PORT
      LAYER M3 ;
        RECT  56.88 85.483 56.898 86.268 ;
    END
  END rd[100]
  PIN rd[101]
    DIRECTION OUTPUT ;
    USE SIGNAL ;
    PORT
      LAYER M5 ;
        RECT  57.408 86.208 57.432 86.4 ;
    END
  END rd[101]
  PIN rd[102]
    DIRECTION OUTPUT ;
    USE SIGNAL ;
    PORT
      LAYER M3 ;
        RECT  57.924 86.256 57.942 86.4 ;
    END
    PORT
      LAYER M3 ;
        RECT  57.924 86.203 57.942 86.268 ;
    END
  END rd[102]
  PIN rd[103]
    DIRECTION OUTPUT ;
    USE SIGNAL ;
    PORT
      LAYER M5 ;
        RECT  58.464 86.208 58.488 86.4 ;
    END
  END rd[103]
  PIN rd[104]
    DIRECTION OUTPUT ;
    USE SIGNAL ;
    PORT
      LAYER M3 ;
        RECT  58.968 86.256 58.986 86.4 ;
    END
    PORT
      LAYER M3 ;
        RECT  58.968 84.101 58.986 86.268 ;
    END
  END rd[104]
  PIN rd[105]
    DIRECTION OUTPUT ;
    USE SIGNAL ;
    PORT
      LAYER M5 ;
        RECT  59.52 86.208 59.544 86.4 ;
    END
    PORT
      LAYER M5 ;
        RECT  59.52 84.373 59.544 86.224 ;
    END
  END rd[105]
  PIN rd[106]
    DIRECTION OUTPUT ;
    USE SIGNAL ;
    PORT
      LAYER M3 ;
        RECT  60.012 86.256 60.03 86.4 ;
    END
    PORT
      LAYER M3 ;
        RECT  60.012 84.413 60.03 86.268 ;
    END
  END rd[106]
  PIN rd[107]
    DIRECTION OUTPUT ;
    USE SIGNAL ;
    PORT
      LAYER M5 ;
        RECT  60.528 86.208 60.552 86.4 ;
    END
  END rd[107]
  PIN rd[108]
    DIRECTION OUTPUT ;
    USE SIGNAL ;
    PORT
      LAYER M3 ;
        RECT  61.056 86.256 61.074 86.4 ;
    END
    PORT
      LAYER M3 ;
        RECT  61.056 86.203 61.074 86.268 ;
    END
  END rd[108]
  PIN rd[109]
    DIRECTION OUTPUT ;
    USE SIGNAL ;
    PORT
      LAYER M5 ;
        RECT  61.584 86.208 61.608 86.4 ;
    END
  END rd[109]
  PIN rd[10]
    DIRECTION OUTPUT ;
    USE SIGNAL ;
    PORT
      LAYER M3 ;
        RECT  9.792 86.256 9.81 86.4 ;
    END
    PORT
      LAYER M3 ;
        RECT  9.792 85.517 9.81 86.268 ;
    END
  END rd[10]
  PIN rd[110]
    DIRECTION OUTPUT ;
    USE SIGNAL ;
    PORT
      LAYER M3 ;
        RECT  62.1 86.256 62.118 86.4 ;
    END
    PORT
      LAYER M3 ;
        RECT  62.1 85.517 62.118 86.268 ;
    END
  END rd[110]
  PIN rd[111]
    DIRECTION OUTPUT ;
    USE SIGNAL ;
    PORT
      LAYER M5 ;
        RECT  62.64 86.208 62.664 86.4 ;
    END
    PORT
      LAYER M5 ;
        RECT  62.64 84.263 62.664 86.224 ;
    END
  END rd[111]
  PIN rd[112]
    DIRECTION OUTPUT ;
    USE SIGNAL ;
    PORT
      LAYER M3 ;
        RECT  63.18 86.256 63.198 86.4 ;
    END
    PORT
      LAYER M3 ;
        RECT  63.18 85.517 63.198 86.268 ;
    END
  END rd[112]
  PIN rd[113]
    DIRECTION OUTPUT ;
    USE SIGNAL ;
    PORT
      LAYER M5 ;
        RECT  63.696 86.208 63.72 86.4 ;
    END
    PORT
      LAYER M5 ;
        RECT  63.696 85.477 63.72 86.224 ;
    END
  END rd[113]
  PIN rd[114]
    DIRECTION OUTPUT ;
    USE SIGNAL ;
    PORT
      LAYER M3 ;
        RECT  64.224 86.256 64.242 86.4 ;
    END
    PORT
      LAYER M3 ;
        RECT  64.224 85.517 64.242 86.268 ;
    END
  END rd[114]
  PIN rd[115]
    DIRECTION OUTPUT ;
    USE SIGNAL ;
    PORT
      LAYER M5 ;
        RECT  64.752 86.208 64.776 86.4 ;
    END
    PORT
      LAYER M5 ;
        RECT  64.752 85.477 64.776 86.224 ;
    END
  END rd[115]
  PIN rd[116]
    DIRECTION OUTPUT ;
    USE SIGNAL ;
    PORT
      LAYER M3 ;
        RECT  65.268 86.256 65.286 86.4 ;
    END
    PORT
      LAYER M3 ;
        RECT  65.268 85.517 65.394 86.261 ;
    END
    PORT
      LAYER M3 ;
        RECT  65.268 86.261 65.286 86.268 ;
    END
  END rd[116]
  PIN rd[117]
    DIRECTION OUTPUT ;
    USE SIGNAL ;
    PORT
      LAYER M5 ;
        RECT  65.76 86.208 65.784 86.4 ;
    END
    PORT
      LAYER M5 ;
        RECT  65.76 85.523 65.784 86.224 ;
    END
  END rd[117]
  PIN rd[118]
    DIRECTION OUTPUT ;
    USE SIGNAL ;
    PORT
      LAYER M3 ;
        RECT  66.312 86.256 66.33 86.4 ;
    END
    PORT
      LAYER M3 ;
        RECT  66.312 85.517 66.33 86.268 ;
    END
  END rd[118]
  PIN rd[119]
    DIRECTION OUTPUT ;
    USE SIGNAL ;
    PORT
      LAYER M5 ;
        RECT  66.816 86.208 66.84 86.4 ;
    END
    PORT
      LAYER M5 ;
        RECT  66.816 85.523 66.84 86.224 ;
    END
  END rd[119]
  PIN rd[11]
    DIRECTION OUTPUT ;
    USE SIGNAL ;
    PORT
      LAYER M5 ;
        RECT  10.32 86.208 10.344 86.4 ;
    END
    PORT
      LAYER M5 ;
        RECT  10.32 85.477 10.344 86.224 ;
    END
  END rd[11]
  PIN rd[120]
    DIRECTION OUTPUT ;
    USE SIGNAL ;
    PORT
      LAYER M3 ;
        RECT  67.356 86.256 67.374 86.4 ;
    END
    PORT
      LAYER M3 ;
        RECT  67.356 85.517 67.374 86.268 ;
    END
  END rd[120]
  PIN rd[121]
    DIRECTION OUTPUT ;
    USE SIGNAL ;
    PORT
      LAYER M5 ;
        RECT  67.872 86.208 67.896 86.4 ;
    END
    PORT
      LAYER M5 ;
        RECT  67.872 85.477 67.896 86.224 ;
    END
  END rd[121]
  PIN rd[122]
    DIRECTION OUTPUT ;
    USE SIGNAL ;
    PORT
      LAYER M3 ;
        RECT  68.4 86.256 68.418 86.4 ;
    END
    PORT
      LAYER M3 ;
        RECT  68.4 85.517 68.418 86.268 ;
    END
  END rd[122]
  PIN rd[123]
    DIRECTION OUTPUT ;
    USE SIGNAL ;
    PORT
      LAYER M5 ;
        RECT  68.928 86.208 68.952 86.4 ;
    END
    PORT
      LAYER M5 ;
        RECT  68.928 85.523 68.952 86.224 ;
    END
  END rd[123]
  PIN rd[124]
    DIRECTION OUTPUT ;
    USE SIGNAL ;
    PORT
      LAYER M3 ;
        RECT  69.444 86.256 69.462 86.4 ;
    END
    PORT
      LAYER M3 ;
        RECT  69.444 85.483 69.462 86.268 ;
    END
  END rd[124]
  PIN rd[125]
    DIRECTION OUTPUT ;
    USE SIGNAL ;
    PORT
      LAYER M5 ;
        RECT  69.984 86.208 70.008 86.4 ;
    END
    PORT
      LAYER M5 ;
        RECT  69.984 85.523 70.008 86.224 ;
    END
  END rd[125]
  PIN rd[126]
    DIRECTION OUTPUT ;
    USE SIGNAL ;
    PORT
      LAYER M3 ;
        RECT  70.488 86.256 70.506 86.4 ;
    END
    PORT
      LAYER M3 ;
        RECT  70.488 84.209 70.506 86.268 ;
    END
  END rd[126]
  PIN rd[127]
    DIRECTION OUTPUT ;
    USE SIGNAL ;
    PORT
      LAYER M5 ;
        RECT  70.992 86.208 71.016 86.4 ;
    END
    PORT
      LAYER M5 ;
        RECT  70.992 83.893 71.016 86.224 ;
    END
  END rd[127]
  PIN rd[128]
    DIRECTION OUTPUT ;
    USE SIGNAL ;
    PORT
      LAYER M3 ;
        RECT  71.532 86.256 71.55 86.4 ;
    END
    PORT
      LAYER M3 ;
        RECT  71.532 85.517 71.55 86.268 ;
    END
  END rd[128]
  PIN rd[129]
    DIRECTION OUTPUT ;
    USE SIGNAL ;
    PORT
      LAYER M5 ;
        RECT  72.048 86.208 72.072 86.4 ;
    END
    PORT
      LAYER M5 ;
        RECT  72.048 85.523 72.072 86.224 ;
    END
  END rd[129]
  PIN rd[12]
    DIRECTION OUTPUT ;
    USE SIGNAL ;
    PORT
      LAYER M3 ;
        RECT  10.836 86.256 10.854 86.4 ;
    END
    PORT
      LAYER M3 ;
        RECT  10.836 85.517 10.854 86.268 ;
    END
  END rd[12]
  PIN rd[130]
    DIRECTION OUTPUT ;
    USE SIGNAL ;
    PORT
      LAYER M3 ;
        RECT  72.576 86.256 72.594 86.4 ;
    END
    PORT
      LAYER M3 ;
        RECT  72.576 85.517 72.594 86.268 ;
    END
  END rd[130]
  PIN rd[131]
    DIRECTION OUTPUT ;
    USE SIGNAL ;
    PORT
      LAYER M5 ;
        RECT  73.104 86.208 73.128 86.4 ;
    END
    PORT
      LAYER M5 ;
        RECT  73.104 85.523 73.128 86.224 ;
    END
  END rd[131]
  PIN rd[132]
    DIRECTION OUTPUT ;
    USE SIGNAL ;
    PORT
      LAYER M3 ;
        RECT  73.62 86.256 73.638 86.4 ;
    END
    PORT
      LAYER M3 ;
        RECT  73.62 85.517 73.638 86.268 ;
    END
  END rd[132]
  PIN rd[133]
    DIRECTION OUTPUT ;
    USE SIGNAL ;
    PORT
      LAYER M5 ;
        RECT  74.16 86.208 74.184 86.4 ;
    END
    PORT
      LAYER M5 ;
        RECT  74.16 85.523 74.184 86.224 ;
    END
  END rd[133]
  PIN rd[134]
    DIRECTION OUTPUT ;
    USE SIGNAL ;
    PORT
      LAYER M3 ;
        RECT  74.664 86.256 74.682 86.4 ;
    END
    PORT
      LAYER M3 ;
        RECT  74.664 85.483 74.682 86.268 ;
    END
  END rd[134]
  PIN rd[135]
    DIRECTION OUTPUT ;
    USE SIGNAL ;
    PORT
      LAYER M5 ;
        RECT  75.168 86.208 75.192 86.4 ;
    END
    PORT
      LAYER M5 ;
        RECT  75.168 85.523 75.192 86.224 ;
    END
  END rd[135]
  PIN rd[136]
    DIRECTION OUTPUT ;
    USE SIGNAL ;
    PORT
      LAYER M3 ;
        RECT  75.708 86.256 75.726 86.4 ;
    END
    PORT
      LAYER M3 ;
        RECT  75.708 84.209 75.726 86.268 ;
    END
  END rd[136]
  PIN rd[137]
    DIRECTION OUTPUT ;
    USE SIGNAL ;
    PORT
      LAYER M5 ;
        RECT  76.224 86.208 76.248 86.4 ;
    END
    PORT
      LAYER M5 ;
        RECT  76.224 83.267 76.248 86.224 ;
    END
  END rd[137]
  PIN rd[138]
    DIRECTION OUTPUT ;
    USE SIGNAL ;
    PORT
      LAYER M3 ;
        RECT  76.752 86.256 76.77 86.4 ;
    END
    PORT
      LAYER M3 ;
        RECT  76.752 84.137 76.77 86.268 ;
    END
  END rd[138]
  PIN rd[139]
    DIRECTION OUTPUT ;
    USE SIGNAL ;
    PORT
      LAYER M5 ;
        RECT  77.28 86.208 77.304 86.4 ;
    END
    PORT
      LAYER M5 ;
        RECT  77.28 85.523 77.304 86.224 ;
    END
  END rd[139]
  PIN rd[13]
    DIRECTION OUTPUT ;
    USE SIGNAL ;
    PORT
      LAYER M5 ;
        RECT  11.376 86.208 11.4 86.4 ;
    END
    PORT
      LAYER M5 ;
        RECT  11.376 85.523 11.4 86.224 ;
    END
  END rd[13]
  PIN rd[140]
    DIRECTION OUTPUT ;
    USE SIGNAL ;
    PORT
      LAYER M3 ;
        RECT  77.796 86.256 77.814 86.4 ;
    END
    PORT
      LAYER M3 ;
        RECT  77.796 85.483 77.814 86.268 ;
    END
  END rd[140]
  PIN rd[141]
    DIRECTION OUTPUT ;
    USE SIGNAL ;
    PORT
      LAYER M5 ;
        RECT  78.336 86.208 78.36 86.4 ;
    END
    PORT
      LAYER M5 ;
        RECT  78.336 85.523 78.36 86.224 ;
    END
  END rd[141]
  PIN rd[142]
    DIRECTION OUTPUT ;
    USE SIGNAL ;
    PORT
      LAYER M3 ;
        RECT  78.84 86.256 78.858 86.4 ;
    END
    PORT
      LAYER M3 ;
        RECT  78.84 84.029 78.858 86.268 ;
    END
  END rd[142]
  PIN rd[143]
    DIRECTION OUTPUT ;
    USE SIGNAL ;
    PORT
      LAYER M5 ;
        RECT  79.392 86.208 79.416 86.4 ;
    END
    PORT
      LAYER M5 ;
        RECT  79.392 85.523 79.416 86.224 ;
    END
  END rd[143]
  PIN rd[144]
    DIRECTION OUTPUT ;
    USE SIGNAL ;
    PORT
      LAYER M3 ;
        RECT  79.92 86.256 79.938 86.4 ;
    END
    PORT
      LAYER M3 ;
        RECT  79.92 85.483 79.938 86.268 ;
    END
  END rd[144]
  PIN rd[145]
    DIRECTION OUTPUT ;
    USE SIGNAL ;
    PORT
      LAYER M5 ;
        RECT  80.4 86.208 80.424 86.4 ;
    END
    PORT
      LAYER M5 ;
        RECT  80.4 85.523 80.424 86.224 ;
    END
  END rd[145]
  PIN rd[146]
    DIRECTION OUTPUT ;
    USE SIGNAL ;
    PORT
      LAYER M3 ;
        RECT  80.964 86.256 80.982 86.4 ;
    END
    PORT
      LAYER M3 ;
        RECT  80.964 86.233 81.09 86.261 ;
    END
    PORT
      LAYER M3 ;
        RECT  80.964 86.261 80.982 86.268 ;
    END
  END rd[146]
  PIN rd[147]
    DIRECTION OUTPUT ;
    USE SIGNAL ;
    PORT
      LAYER M5 ;
        RECT  81.456 86.208 81.48 86.4 ;
    END
    PORT
      LAYER M5 ;
        RECT  81.456 82.789 81.48 86.224 ;
    END
  END rd[147]
  PIN rd[148]
    DIRECTION OUTPUT ;
    USE SIGNAL ;
    PORT
      LAYER M3 ;
        RECT  82.008 86.256 82.026 86.4 ;
    END
    PORT
      LAYER M3 ;
        RECT  82.008 84.101 82.026 86.268 ;
    END
  END rd[148]
  PIN rd[149]
    DIRECTION OUTPUT ;
    USE SIGNAL ;
    PORT
      LAYER M5 ;
        RECT  82.512 86.208 82.536 86.4 ;
    END
    PORT
      LAYER M5 ;
        RECT  82.512 84.263 82.536 86.224 ;
    END
  END rd[149]
  PIN rd[14]
    DIRECTION OUTPUT ;
    USE SIGNAL ;
    PORT
      LAYER M3 ;
        RECT  11.88 86.256 11.898 86.4 ;
    END
    PORT
      LAYER M3 ;
        RECT  11.88 85.483 11.898 86.268 ;
    END
  END rd[14]
  PIN rd[150]
    DIRECTION OUTPUT ;
    USE SIGNAL ;
    PORT
      LAYER M3 ;
        RECT  83.052 86.256 83.07 86.4 ;
    END
    PORT
      LAYER M3 ;
        RECT  83.052 84.413 83.07 86.268 ;
    END
  END rd[150]
  PIN rd[151]
    DIRECTION OUTPUT ;
    USE SIGNAL ;
    PORT
      LAYER M5 ;
        RECT  83.568 86.208 83.592 86.4 ;
    END
    PORT
      LAYER M5 ;
        RECT  83.568 85.523 83.592 86.224 ;
    END
  END rd[151]
  PIN rd[152]
    DIRECTION OUTPUT ;
    USE SIGNAL ;
    PORT
      LAYER M3 ;
        RECT  84.096 86.256 84.114 86.4 ;
    END
    PORT
      LAYER M3 ;
        RECT  84.096 85.483 84.114 86.268 ;
    END
  END rd[152]
  PIN rd[153]
    DIRECTION OUTPUT ;
    USE SIGNAL ;
    PORT
      LAYER M5 ;
        RECT  84.624 86.208 84.648 86.4 ;
    END
    PORT
      LAYER M5 ;
        RECT  84.624 85.523 84.648 86.224 ;
    END
  END rd[153]
  PIN rd[154]
    DIRECTION OUTPUT ;
    USE SIGNAL ;
    PORT
      LAYER M3 ;
        RECT  85.14 86.256 85.158 86.4 ;
    END
    PORT
      LAYER M3 ;
        RECT  85.14 85.517 85.158 86.268 ;
    END
  END rd[154]
  PIN rd[155]
    DIRECTION OUTPUT ;
    USE SIGNAL ;
    PORT
      LAYER M5 ;
        RECT  85.632 86.208 85.656 86.4 ;
    END
    PORT
      LAYER M5 ;
        RECT  85.632 85.477 85.656 86.224 ;
    END
  END rd[155]
  PIN rd[156]
    DIRECTION OUTPUT ;
    USE SIGNAL ;
    PORT
      LAYER M3 ;
        RECT  86.184 86.256 86.202 86.4 ;
    END
    PORT
      LAYER M3 ;
        RECT  86.184 85.517 86.202 86.268 ;
    END
  END rd[156]
  PIN rd[157]
    DIRECTION OUTPUT ;
    USE SIGNAL ;
    PORT
      LAYER M5 ;
        RECT  86.688 86.208 86.712 86.4 ;
    END
    PORT
      LAYER M5 ;
        RECT  86.688 85.523 86.712 86.224 ;
    END
  END rd[157]
  PIN rd[158]
    DIRECTION OUTPUT ;
    USE SIGNAL ;
    PORT
      LAYER M3 ;
        RECT  87.228 86.256 87.246 86.4 ;
    END
    PORT
      LAYER M3 ;
        RECT  87.228 85.483 87.246 86.268 ;
    END
  END rd[158]
  PIN rd[159]
    DIRECTION OUTPUT ;
    USE SIGNAL ;
    PORT
      LAYER M5 ;
        RECT  87.744 86.208 87.768 86.4 ;
    END
    PORT
      LAYER M5 ;
        RECT  87.744 85.523 87.768 86.224 ;
    END
  END rd[159]
  PIN rd[15]
    DIRECTION OUTPUT ;
    USE SIGNAL ;
    PORT
      LAYER M5 ;
        RECT  12.432 86.208 12.456 86.4 ;
    END
  END rd[15]
  PIN rd[160]
    DIRECTION OUTPUT ;
    USE SIGNAL ;
    PORT
      LAYER M3 ;
        RECT  88.272 86.256 88.29 86.4 ;
    END
    PORT
      LAYER M3 ;
        RECT  88.272 84.989 88.29 86.268 ;
    END
  END rd[160]
  PIN rd[161]
    DIRECTION OUTPUT ;
    USE SIGNAL ;
    PORT
      LAYER M5 ;
        RECT  88.8 86.208 88.824 86.4 ;
    END
    PORT
      LAYER M5 ;
        RECT  88.8 84.263 88.824 86.224 ;
    END
  END rd[161]
  PIN rd[162]
    DIRECTION OUTPUT ;
    USE SIGNAL ;
    PORT
      LAYER M3 ;
        RECT  89.316 86.256 89.334 86.4 ;
    END
    PORT
      LAYER M3 ;
        RECT  89.316 84.989 89.334 86.268 ;
    END
  END rd[162]
  PIN rd[163]
    DIRECTION OUTPUT ;
    USE SIGNAL ;
    PORT
      LAYER M5 ;
        RECT  89.856 86.208 89.88 86.4 ;
    END
    PORT
      LAYER M5 ;
        RECT  89.856 84.263 89.88 86.224 ;
    END
  END rd[163]
  PIN rd[164]
    DIRECTION OUTPUT ;
    USE SIGNAL ;
    PORT
      LAYER M3 ;
        RECT  90.36 86.256 90.378 86.4 ;
    END
    PORT
      LAYER M3 ;
        RECT  90.36 84.173 90.378 86.268 ;
    END
  END rd[164]
  PIN rd[165]
    DIRECTION OUTPUT ;
    USE SIGNAL ;
    PORT
      LAYER M5 ;
        RECT  90.864 86.208 90.888 86.4 ;
    END
    PORT
      LAYER M5 ;
        RECT  90.864 82.933 90.888 86.224 ;
    END
  END rd[165]
  PIN rd[166]
    DIRECTION OUTPUT ;
    USE SIGNAL ;
    PORT
      LAYER M3 ;
        RECT  91.404 86.256 91.422 86.4 ;
    END
    PORT
      LAYER M3 ;
        RECT  91.404 86.233 91.494 86.261 ;
    END
    PORT
      LAYER M3 ;
        RECT  91.404 86.261 91.422 86.268 ;
    END
  END rd[166]
  PIN rd[167]
    DIRECTION OUTPUT ;
    USE SIGNAL ;
    PORT
      LAYER M5 ;
        RECT  91.92 86.208 91.944 86.4 ;
    END
    PORT
      LAYER M5 ;
        RECT  91.92 85.477 91.944 86.224 ;
    END
  END rd[167]
  PIN rd[168]
    DIRECTION OUTPUT ;
    USE SIGNAL ;
    PORT
      LAYER M3 ;
        RECT  92.448 86.256 92.466 86.4 ;
    END
    PORT
      LAYER M3 ;
        RECT  92.448 85.517 92.466 86.268 ;
    END
  END rd[168]
  PIN rd[169]
    DIRECTION OUTPUT ;
    USE SIGNAL ;
    PORT
      LAYER M5 ;
        RECT  92.976 86.208 93 86.4 ;
    END
    PORT
      LAYER M5 ;
        RECT  92.976 85.477 93 86.224 ;
    END
  END rd[169]
  PIN rd[16]
    DIRECTION OUTPUT ;
    USE SIGNAL ;
    PORT
      LAYER M3 ;
        RECT  12.96 86.256 12.978 86.4 ;
    END
    PORT
      LAYER M3 ;
        RECT  12.96 86.203 12.978 86.268 ;
    END
  END rd[16]
  PIN rd[170]
    DIRECTION OUTPUT ;
    USE SIGNAL ;
    PORT
      LAYER M3 ;
        RECT  93.492 86.256 93.51 86.4 ;
    END
    PORT
      LAYER M3 ;
        RECT  93.492 86.261 93.51 86.268 ;
    END
  END rd[170]
  PIN rd[171]
    DIRECTION OUTPUT ;
    USE SIGNAL ;
    PORT
      LAYER M5 ;
        RECT  94.032 86.208 94.056 86.4 ;
    END
    PORT
      LAYER M5 ;
        RECT  94.032 84.263 94.056 86.224 ;
    END
  END rd[171]
  PIN rd[172]
    DIRECTION OUTPUT ;
    USE SIGNAL ;
    PORT
      LAYER M3 ;
        RECT  94.536 86.256 94.554 86.4 ;
    END
    PORT
      LAYER M3 ;
        RECT  94.536 86.261 94.554 86.268 ;
    END
  END rd[172]
  PIN rd[173]
    DIRECTION OUTPUT ;
    USE SIGNAL ;
    PORT
      LAYER M5 ;
        RECT  95.088 86.208 95.112 86.4 ;
    END
    PORT
      LAYER M5 ;
        RECT  95.088 84.373 95.112 86.224 ;
    END
  END rd[173]
  PIN rd[174]
    DIRECTION OUTPUT ;
    USE SIGNAL ;
    PORT
      LAYER M3 ;
        RECT  95.58 86.256 95.598 86.4 ;
    END
    PORT
      LAYER M3 ;
        RECT  95.58 84.413 95.598 86.268 ;
    END
  END rd[174]
  PIN rd[175]
    DIRECTION OUTPUT ;
    USE SIGNAL ;
    PORT
      LAYER M5 ;
        RECT  96.096 86.208 96.12 86.4 ;
    END
    PORT
      LAYER M5 ;
        RECT  96.096 83.125 96.12 86.224 ;
    END
  END rd[175]
  PIN rd[176]
    DIRECTION OUTPUT ;
    USE SIGNAL ;
    PORT
      LAYER M3 ;
        RECT  96.66 86.256 96.678 86.4 ;
    END
    PORT
      LAYER M3 ;
        RECT  96.66 84.989 96.678 86.268 ;
    END
  END rd[176]
  PIN rd[177]
    DIRECTION OUTPUT ;
    USE SIGNAL ;
    PORT
      LAYER M5 ;
        RECT  97.152 86.208 97.176 86.4 ;
    END
    PORT
      LAYER M5 ;
        RECT  97.152 84.949 97.176 86.224 ;
    END
  END rd[177]
  PIN rd[178]
    DIRECTION OUTPUT ;
    USE SIGNAL ;
    PORT
      LAYER M3 ;
        RECT  97.704 86.256 97.722 86.4 ;
    END
    PORT
      LAYER M3 ;
        RECT  97.704 85.517 97.722 86.268 ;
    END
  END rd[178]
  PIN rd[179]
    DIRECTION OUTPUT ;
    USE SIGNAL ;
    PORT
      LAYER M5 ;
        RECT  98.208 86.208 98.232 86.4 ;
    END
    PORT
      LAYER M5 ;
        RECT  98.208 85.477 98.232 86.224 ;
    END
  END rd[179]
  PIN rd[17]
    DIRECTION OUTPUT ;
    USE SIGNAL ;
    PORT
      LAYER M5 ;
        RECT  13.44 86.208 13.464 86.4 ;
    END
  END rd[17]
  PIN rd[180]
    DIRECTION OUTPUT ;
    USE SIGNAL ;
    PORT
      LAYER M3 ;
        RECT  98.748 86.256 98.766 86.4 ;
    END
    PORT
      LAYER M3 ;
        RECT  98.748 85.517 98.766 86.268 ;
    END
  END rd[180]
  PIN rd[181]
    DIRECTION OUTPUT ;
    USE SIGNAL ;
    PORT
      LAYER M5 ;
        RECT  99.264 86.208 99.288 86.4 ;
    END
    PORT
      LAYER M5 ;
        RECT  99.264 85.477 99.288 86.224 ;
    END
  END rd[181]
  PIN rd[182]
    DIRECTION OUTPUT ;
    USE SIGNAL ;
    PORT
      LAYER M3 ;
        RECT  99.792 86.256 99.81 86.4 ;
    END
    PORT
      LAYER M3 ;
        RECT  99.792 85.517 99.81 86.268 ;
    END
  END rd[182]
  PIN rd[183]
    DIRECTION OUTPUT ;
    USE SIGNAL ;
    PORT
      LAYER M5 ;
        RECT  100.32 86.208 100.344 86.4 ;
    END
    PORT
      LAYER M5 ;
        RECT  100.32 84.263 100.344 86.224 ;
    END
  END rd[183]
  PIN rd[184]
    DIRECTION OUTPUT ;
    USE SIGNAL ;
    PORT
      LAYER M3 ;
        RECT  100.836 86.256 100.854 86.4 ;
    END
    PORT
      LAYER M3 ;
        RECT  100.836 84.299 100.854 86.268 ;
    END
  END rd[184]
  PIN rd[185]
    DIRECTION OUTPUT ;
    USE SIGNAL ;
    PORT
      LAYER M5 ;
        RECT  101.328 86.208 101.352 86.4 ;
    END
    PORT
      LAYER M5 ;
        RECT  101.328 84.083 101.352 86.224 ;
    END
  END rd[185]
  PIN rd[186]
    DIRECTION OUTPUT ;
    USE SIGNAL ;
    PORT
      LAYER M3 ;
        RECT  101.88 86.256 101.898 86.4 ;
    END
    PORT
      LAYER M3 ;
        RECT  101.88 85.517 101.898 86.268 ;
    END
  END rd[186]
  PIN rd[187]
    DIRECTION OUTPUT ;
    USE SIGNAL ;
    PORT
      LAYER M5 ;
        RECT  102.384 86.208 102.408 86.4 ;
    END
    PORT
      LAYER M5 ;
        RECT  102.384 85.477 102.408 86.224 ;
    END
  END rd[187]
  PIN rd[188]
    DIRECTION OUTPUT ;
    USE SIGNAL ;
    PORT
      LAYER M3 ;
        RECT  102.924 86.256 102.942 86.4 ;
    END
    PORT
      LAYER M3 ;
        RECT  102.924 85.517 102.942 86.268 ;
    END
  END rd[188]
  PIN rd[189]
    DIRECTION OUTPUT ;
    USE SIGNAL ;
    PORT
      LAYER M5 ;
        RECT  103.44 86.208 103.464 86.4 ;
    END
    PORT
      LAYER M5 ;
        RECT  103.44 84.901 103.464 86.224 ;
    END
  END rd[189]
  PIN rd[18]
    DIRECTION OUTPUT ;
    USE SIGNAL ;
    PORT
      LAYER M3 ;
        RECT  14.004 86.256 14.022 86.4 ;
    END
    PORT
      LAYER M3 ;
        RECT  14.004 86.203 14.022 86.268 ;
    END
  END rd[18]
  PIN rd[190]
    DIRECTION OUTPUT ;
    USE SIGNAL ;
    PORT
      LAYER M3 ;
        RECT  103.968 86.256 103.986 86.4 ;
    END
    PORT
      LAYER M3 ;
        RECT  103.968 85.517 103.986 86.268 ;
    END
  END rd[190]
  PIN rd[191]
    DIRECTION OUTPUT ;
    USE SIGNAL ;
    PORT
      LAYER M5 ;
        RECT  104.496 86.208 104.52 86.4 ;
    END
    PORT
      LAYER M5 ;
        RECT  104.496 85.477 104.52 86.224 ;
    END
  END rd[191]
  PIN rd[192]
    DIRECTION OUTPUT ;
    USE SIGNAL ;
    PORT
      LAYER M3 ;
        RECT  105.012 86.256 105.03 86.4 ;
    END
    PORT
      LAYER M3 ;
        RECT  104.94 86.233 105.03 86.261 ;
    END
    PORT
      LAYER M3 ;
        RECT  105.012 86.261 105.03 86.268 ;
    END
  END rd[192]
  PIN rd[193]
    DIRECTION OUTPUT ;
    USE SIGNAL ;
    PORT
      LAYER M5 ;
        RECT  105.552 86.208 105.576 86.4 ;
    END
    PORT
      LAYER M5 ;
        RECT  105.552 85.523 105.576 86.224 ;
    END
  END rd[193]
  PIN rd[194]
    DIRECTION OUTPUT ;
    USE SIGNAL ;
    PORT
      LAYER M3 ;
        RECT  106.056 86.256 106.074 86.4 ;
    END
    PORT
      LAYER M3 ;
        RECT  106.056 85.483 106.074 86.268 ;
    END
  END rd[194]
  PIN rd[195]
    DIRECTION OUTPUT ;
    USE SIGNAL ;
    PORT
      LAYER M5 ;
        RECT  106.56 86.208 106.584 86.4 ;
    END
    PORT
      LAYER M5 ;
        RECT  106.56 85.523 106.584 86.224 ;
    END
  END rd[195]
  PIN rd[196]
    DIRECTION OUTPUT ;
    USE SIGNAL ;
    PORT
      LAYER M3 ;
        RECT  107.1 86.256 107.118 86.4 ;
    END
    PORT
      LAYER M3 ;
        RECT  107.1 84.221 107.118 86.268 ;
    END
  END rd[196]
  PIN rd[197]
    DIRECTION OUTPUT ;
    USE SIGNAL ;
    PORT
      LAYER M5 ;
        RECT  107.616 86.208 107.64 86.4 ;
    END
    PORT
      LAYER M5 ;
        RECT  107.616 83.891 107.64 86.224 ;
    END
  END rd[197]
  PIN rd[198]
    DIRECTION OUTPUT ;
    USE SIGNAL ;
    PORT
      LAYER M3 ;
        RECT  108.144 86.256 108.162 86.4 ;
    END
    PORT
      LAYER M3 ;
        RECT  108.144 84.413 108.162 86.268 ;
    END
  END rd[198]
  PIN rd[199]
    DIRECTION OUTPUT ;
    USE SIGNAL ;
    PORT
      LAYER M5 ;
        RECT  108.672 86.208 108.696 86.4 ;
    END
    PORT
      LAYER M5 ;
        RECT  108.672 84.373 108.696 86.224 ;
    END
  END rd[199]
  PIN rd[19]
    DIRECTION OUTPUT ;
    USE SIGNAL ;
    PORT
      LAYER M5 ;
        RECT  14.496 86.208 14.52 86.4 ;
    END
  END rd[19]
  PIN rd[1]
    DIRECTION OUTPUT ;
    USE SIGNAL ;
    PORT
      LAYER M5 ;
        RECT  5.088 86.208 5.112 86.4 ;
    END
  END rd[1]
  PIN rd[200]
    DIRECTION OUTPUT ;
    USE SIGNAL ;
    PORT
      LAYER M3 ;
        RECT  109.188 86.256 109.206 86.4 ;
    END
    PORT
      LAYER M3 ;
        RECT  109.188 85.517 109.206 86.268 ;
    END
  END rd[200]
  PIN rd[201]
    DIRECTION OUTPUT ;
    USE SIGNAL ;
    PORT
      LAYER M5 ;
        RECT  109.728 86.208 109.752 86.4 ;
    END
    PORT
      LAYER M5 ;
        RECT  109.728 85.477 109.752 86.224 ;
    END
  END rd[201]
  PIN rd[202]
    DIRECTION OUTPUT ;
    USE SIGNAL ;
    PORT
      LAYER M3 ;
        RECT  110.232 86.256 110.25 86.4 ;
    END
    PORT
      LAYER M3 ;
        RECT  110.232 85.517 110.25 86.268 ;
    END
  END rd[202]
  PIN rd[203]
    DIRECTION OUTPUT ;
    USE SIGNAL ;
    PORT
      LAYER M5 ;
        RECT  110.784 86.208 110.808 86.4 ;
    END
    PORT
      LAYER M5 ;
        RECT  110.784 84.373 110.808 86.224 ;
    END
  END rd[203]
  PIN rd[204]
    DIRECTION OUTPUT ;
    USE SIGNAL ;
    PORT
      LAYER M3 ;
        RECT  111.276 86.256 111.294 86.4 ;
    END
    PORT
      LAYER M3 ;
        RECT  111.276 85.517 111.294 86.268 ;
    END
  END rd[204]
  PIN rd[205]
    DIRECTION OUTPUT ;
    USE SIGNAL ;
    PORT
      LAYER M5 ;
        RECT  111.792 86.208 111.816 86.4 ;
    END
    PORT
      LAYER M5 ;
        RECT  111.792 85.477 111.816 86.224 ;
    END
  END rd[205]
  PIN rd[206]
    DIRECTION OUTPUT ;
    USE SIGNAL ;
    PORT
      LAYER M3 ;
        RECT  112.32 86.256 112.338 86.4 ;
    END
    PORT
      LAYER M3 ;
        RECT  112.32 85.517 112.41 86.261 ;
    END
    PORT
      LAYER M3 ;
        RECT  112.32 86.261 112.338 86.268 ;
    END
  END rd[206]
  PIN rd[207]
    DIRECTION OUTPUT ;
    USE SIGNAL ;
    PORT
      LAYER M5 ;
        RECT  112.848 86.208 112.872 86.4 ;
    END
    PORT
      LAYER M5 ;
        RECT  112.848 83.557 112.872 86.224 ;
    END
  END rd[207]
  PIN rd[208]
    DIRECTION OUTPUT ;
    USE SIGNAL ;
    PORT
      LAYER M3 ;
        RECT  113.4 86.256 113.418 86.4 ;
    END
    PORT
      LAYER M3 ;
        RECT  113.4 84.029 113.418 86.268 ;
    END
  END rd[208]
  PIN rd[209]
    DIRECTION OUTPUT ;
    USE SIGNAL ;
    PORT
      LAYER M5 ;
        RECT  113.904 86.208 113.928 86.4 ;
    END
    PORT
      LAYER M5 ;
        RECT  113.904 83.749 113.928 86.224 ;
    END
  END rd[209]
  PIN rd[20]
    DIRECTION OUTPUT ;
    USE SIGNAL ;
    PORT
      LAYER M3 ;
        RECT  15.048 86.256 15.066 86.4 ;
    END
    PORT
      LAYER M3 ;
        RECT  15.048 84.029 15.066 86.268 ;
    END
  END rd[20]
  PIN rd[210]
    DIRECTION OUTPUT ;
    USE SIGNAL ;
    PORT
      LAYER M3 ;
        RECT  114.444 86.256 114.462 86.4 ;
    END
    PORT
      LAYER M3 ;
        RECT  114.444 85.517 114.462 86.268 ;
    END
  END rd[210]
  PIN rd[211]
    DIRECTION OUTPUT ;
    USE SIGNAL ;
    PORT
      LAYER M5 ;
        RECT  114.96 86.208 114.984 86.4 ;
    END
    PORT
      LAYER M5 ;
        RECT  114.96 85.477 114.984 86.224 ;
    END
  END rd[211]
  PIN rd[212]
    DIRECTION OUTPUT ;
    USE SIGNAL ;
    PORT
      LAYER M3 ;
        RECT  115.488 86.256 115.506 86.4 ;
    END
    PORT
      LAYER M3 ;
        RECT  115.488 85.517 115.506 86.268 ;
    END
  END rd[212]
  PIN rd[213]
    DIRECTION OUTPUT ;
    USE SIGNAL ;
    PORT
      LAYER M5 ;
        RECT  116.016 86.208 116.04 86.4 ;
    END
    PORT
      LAYER M5 ;
        RECT  116.016 85.477 116.04 86.224 ;
    END
  END rd[213]
  PIN rd[214]
    DIRECTION OUTPUT ;
    USE SIGNAL ;
    PORT
      LAYER M3 ;
        RECT  116.532 86.256 116.55 86.4 ;
    END
    PORT
      LAYER M3 ;
        RECT  116.532 85.517 116.55 86.268 ;
    END
  END rd[214]
  PIN rd[215]
    DIRECTION OUTPUT ;
    USE SIGNAL ;
    PORT
      LAYER M5 ;
        RECT  117.024 86.208 117.048 86.4 ;
    END
    PORT
      LAYER M5 ;
        RECT  117.024 84.249 117.048 86.224 ;
    END
  END rd[215]
  PIN rd[216]
    DIRECTION OUTPUT ;
    USE SIGNAL ;
    PORT
      LAYER M3 ;
        RECT  117.576 86.256 117.594 86.4 ;
    END
    PORT
      LAYER M3 ;
        RECT  117.576 85.517 117.594 86.268 ;
    END
  END rd[216]
  PIN rd[217]
    DIRECTION OUTPUT ;
    USE SIGNAL ;
    PORT
      LAYER M5 ;
        RECT  118.08 86.208 118.104 86.4 ;
    END
  END rd[217]
  PIN rd[218]
    DIRECTION OUTPUT ;
    USE SIGNAL ;
    PORT
      LAYER M3 ;
        RECT  118.62 86.256 118.638 86.4 ;
    END
    PORT
      LAYER M3 ;
        RECT  118.62 86.203 118.638 86.268 ;
    END
  END rd[218]
  PIN rd[219]
    DIRECTION OUTPUT ;
    USE SIGNAL ;
    PORT
      LAYER M5 ;
        RECT  119.136 86.208 119.16 86.4 ;
    END
  END rd[219]
  PIN rd[21]
    DIRECTION OUTPUT ;
    USE SIGNAL ;
    PORT
      LAYER M5 ;
        RECT  15.552 86.208 15.576 86.4 ;
    END
    PORT
      LAYER M5 ;
        RECT  15.552 85.523 15.576 86.224 ;
    END
  END rd[21]
  PIN rd[220]
    DIRECTION OUTPUT ;
    USE SIGNAL ;
    PORT
      LAYER M3 ;
        RECT  119.664 86.256 119.682 86.4 ;
    END
    PORT
      LAYER M3 ;
        RECT  119.664 84.209 119.682 86.268 ;
    END
  END rd[220]
  PIN rd[221]
    DIRECTION OUTPUT ;
    USE SIGNAL ;
    PORT
      LAYER M5 ;
        RECT  120.192 86.208 120.216 86.4 ;
    END
  END rd[221]
  PIN rd[222]
    DIRECTION OUTPUT ;
    USE SIGNAL ;
    PORT
      LAYER M3 ;
        RECT  120.708 86.256 120.726 86.4 ;
    END
    PORT
      LAYER M3 ;
        RECT  120.708 86.203 120.726 86.268 ;
    END
  END rd[222]
  PIN rd[223]
    DIRECTION OUTPUT ;
    USE SIGNAL ;
    PORT
      LAYER M5 ;
        RECT  121.248 86.208 121.272 86.4 ;
    END
  END rd[223]
  PIN rd[224]
    DIRECTION OUTPUT ;
    USE SIGNAL ;
    PORT
      LAYER M3 ;
        RECT  121.752 86.256 121.77 86.4 ;
    END
    PORT
      LAYER M3 ;
        RECT  121.752 85.483 121.77 86.268 ;
    END
  END rd[224]
  PIN rd[225]
    DIRECTION OUTPUT ;
    USE SIGNAL ;
    PORT
      LAYER M5 ;
        RECT  122.256 86.208 122.28 86.4 ;
    END
    PORT
      LAYER M5 ;
        RECT  122.256 85.523 122.28 86.224 ;
    END
  END rd[225]
  PIN rd[226]
    DIRECTION OUTPUT ;
    USE SIGNAL ;
    PORT
      LAYER M3 ;
        RECT  122.796 86.256 122.814 86.4 ;
    END
    PORT
      LAYER M3 ;
        RECT  122.796 84.317 122.814 86.268 ;
    END
  END rd[226]
  PIN rd[227]
    DIRECTION OUTPUT ;
    USE SIGNAL ;
    PORT
      LAYER M5 ;
        RECT  123.312 86.208 123.336 86.4 ;
    END
    PORT
      LAYER M5 ;
        RECT  123.312 83.891 123.336 86.224 ;
    END
  END rd[227]
  PIN rd[228]
    DIRECTION OUTPUT ;
    USE SIGNAL ;
    PORT
      LAYER M3 ;
        RECT  123.84 86.256 123.858 86.4 ;
    END
    PORT
      LAYER M3 ;
        RECT  123.84 84.209 123.858 86.268 ;
    END
  END rd[228]
  PIN rd[229]
    DIRECTION OUTPUT ;
    USE SIGNAL ;
    PORT
      LAYER M5 ;
        RECT  124.368 86.208 124.392 86.4 ;
    END
    PORT
      LAYER M5 ;
        RECT  124.368 83.843 124.392 86.224 ;
    END
  END rd[229]
  PIN rd[22]
    DIRECTION OUTPUT ;
    USE SIGNAL ;
    PORT
      LAYER M3 ;
        RECT  16.092 86.256 16.11 86.4 ;
    END
    PORT
      LAYER M3 ;
        RECT  16.092 85.483 16.11 86.268 ;
    END
  END rd[22]
  PIN rd[230]
    DIRECTION OUTPUT ;
    USE SIGNAL ;
    PORT
      LAYER M3 ;
        RECT  124.884 86.256 124.902 86.4 ;
    END
    PORT
      LAYER M3 ;
        RECT  124.884 84.101 124.902 86.268 ;
    END
  END rd[230]
  PIN rd[231]
    DIRECTION OUTPUT ;
    USE SIGNAL ;
    PORT
      LAYER M5 ;
        RECT  125.424 86.208 125.448 86.4 ;
    END
  END rd[231]
  PIN rd[232]
    DIRECTION OUTPUT ;
    USE SIGNAL ;
    PORT
      LAYER M3 ;
        RECT  125.928 86.256 125.946 86.4 ;
    END
    PORT
      LAYER M3 ;
        RECT  125.928 86.203 125.946 86.268 ;
    END
  END rd[232]
  PIN rd[233]
    DIRECTION OUTPUT ;
    USE SIGNAL ;
    PORT
      LAYER M5 ;
        RECT  126.48 86.208 126.504 86.4 ;
    END
  END rd[233]
  PIN rd[234]
    DIRECTION OUTPUT ;
    USE SIGNAL ;
    PORT
      LAYER M3 ;
        RECT  126.972 86.256 126.99 86.4 ;
    END
    PORT
      LAYER M3 ;
        RECT  126.972 84.413 126.99 86.268 ;
    END
  END rd[234]
  PIN rd[235]
    DIRECTION OUTPUT ;
    USE SIGNAL ;
    PORT
      LAYER M5 ;
        RECT  127.488 86.208 127.512 86.4 ;
    END
    PORT
      LAYER M5 ;
        RECT  127.488 84.263 127.512 86.224 ;
    END
  END rd[235]
  PIN rd[236]
    DIRECTION OUTPUT ;
    USE SIGNAL ;
    PORT
      LAYER M3 ;
        RECT  128.016 86.256 128.034 86.4 ;
    END
    PORT
      LAYER M3 ;
        RECT  128.016 84.209 128.034 86.268 ;
    END
  END rd[236]
  PIN rd[237]
    DIRECTION OUTPUT ;
    USE SIGNAL ;
    PORT
      LAYER M5 ;
        RECT  128.544 86.208 128.568 86.4 ;
    END
    PORT
      LAYER M5 ;
        RECT  128.544 85.523 128.568 86.224 ;
    END
  END rd[237]
  PIN rd[238]
    DIRECTION OUTPUT ;
    USE SIGNAL ;
    PORT
      LAYER M3 ;
        RECT  129.06 86.256 129.078 86.4 ;
    END
    PORT
      LAYER M3 ;
        RECT  129.06 85.483 129.078 86.268 ;
    END
  END rd[238]
  PIN rd[239]
    DIRECTION OUTPUT ;
    USE SIGNAL ;
    PORT
      LAYER M5 ;
        RECT  129.6 86.208 129.624 86.4 ;
    END
    PORT
      LAYER M5 ;
        RECT  129.6 85.523 129.624 86.224 ;
    END
  END rd[239]
  PIN rd[23]
    DIRECTION OUTPUT ;
    USE SIGNAL ;
    PORT
      LAYER M5 ;
        RECT  16.608 86.208 16.632 86.4 ;
    END
    PORT
      LAYER M5 ;
        RECT  16.608 85.523 16.632 86.224 ;
    END
  END rd[23]
  PIN rd[240]
    DIRECTION OUTPUT ;
    USE SIGNAL ;
    PORT
      LAYER M3 ;
        RECT  130.14 86.256 130.158 86.4 ;
    END
    PORT
      LAYER M3 ;
        RECT  130.14 85.517 130.158 86.268 ;
    END
  END rd[240]
  PIN rd[241]
    DIRECTION OUTPUT ;
    USE SIGNAL ;
    PORT
      LAYER M5 ;
        RECT  130.656 86.208 130.68 86.4 ;
    END
    PORT
      LAYER M5 ;
        RECT  130.656 85.477 130.68 86.224 ;
    END
  END rd[241]
  PIN rd[242]
    DIRECTION OUTPUT ;
    USE SIGNAL ;
    PORT
      LAYER M3 ;
        RECT  131.184 86.256 131.202 86.4 ;
    END
    PORT
      LAYER M3 ;
        RECT  131.184 85.517 131.274 86.261 ;
    END
    PORT
      LAYER M3 ;
        RECT  131.184 86.261 131.202 86.268 ;
    END
  END rd[242]
  PIN rd[243]
    DIRECTION OUTPUT ;
    USE SIGNAL ;
    PORT
      LAYER M5 ;
        RECT  131.712 86.208 131.736 86.4 ;
    END
    PORT
      LAYER M5 ;
        RECT  131.712 84.263 131.736 86.224 ;
    END
  END rd[243]
  PIN rd[244]
    DIRECTION OUTPUT ;
    USE SIGNAL ;
    PORT
      LAYER M3 ;
        RECT  132.228 86.256 132.246 86.4 ;
    END
    PORT
      LAYER M3 ;
        RECT  132.228 84.257 132.246 86.268 ;
    END
  END rd[244]
  PIN rd[245]
    DIRECTION OUTPUT ;
    USE SIGNAL ;
    PORT
      LAYER M5 ;
        RECT  132.72 86.208 132.744 86.4 ;
    END
    PORT
      LAYER M5 ;
        RECT  132.72 84.263 132.744 86.224 ;
    END
  END rd[245]
  PIN rd[246]
    DIRECTION OUTPUT ;
    USE SIGNAL ;
    PORT
      LAYER M3 ;
        RECT  133.272 86.256 133.29 86.4 ;
    END
    PORT
      LAYER M3 ;
        RECT  133.272 84.989 133.29 86.268 ;
    END
  END rd[246]
  PIN rd[247]
    DIRECTION OUTPUT ;
    USE SIGNAL ;
    PORT
      LAYER M5 ;
        RECT  133.776 86.208 133.8 86.4 ;
    END
    PORT
      LAYER M5 ;
        RECT  133.776 84.949 133.8 86.224 ;
    END
  END rd[247]
  PIN rd[248]
    DIRECTION OUTPUT ;
    USE SIGNAL ;
    PORT
      LAYER M3 ;
        RECT  134.316 86.256 134.334 86.4 ;
    END
    PORT
      LAYER M3 ;
        RECT  134.316 84.989 134.334 86.268 ;
    END
  END rd[248]
  PIN rd[249]
    DIRECTION OUTPUT ;
    USE SIGNAL ;
    PORT
      LAYER M5 ;
        RECT  134.832 86.208 134.856 86.4 ;
    END
    PORT
      LAYER M5 ;
        RECT  134.832 83.797 134.856 86.224 ;
    END
  END rd[249]
  PIN rd[24]
    DIRECTION OUTPUT ;
    USE SIGNAL ;
    PORT
      LAYER M3 ;
        RECT  17.136 86.256 17.154 86.4 ;
    END
    PORT
      LAYER M3 ;
        RECT  17.136 85.483 17.154 86.268 ;
    END
  END rd[24]
  PIN rd[250]
    DIRECTION OUTPUT ;
    USE SIGNAL ;
    PORT
      LAYER M3 ;
        RECT  135.36 86.256 135.378 86.4 ;
    END
    PORT
      LAYER M3 ;
        RECT  135.36 83.837 135.378 86.268 ;
    END
  END rd[250]
  PIN rd[251]
    DIRECTION OUTPUT ;
    USE SIGNAL ;
    PORT
      LAYER M5 ;
        RECT  135.888 86.208 135.912 86.4 ;
    END
    PORT
      LAYER M5 ;
        RECT  135.888 83.507 135.912 86.224 ;
    END
  END rd[251]
  PIN rd[252]
    DIRECTION OUTPUT ;
    USE SIGNAL ;
    PORT
      LAYER M3 ;
        RECT  136.404 86.256 136.422 86.4 ;
    END
    PORT
      LAYER M3 ;
        RECT  136.404 84.989 136.422 86.268 ;
    END
  END rd[252]
  PIN rd[253]
    DIRECTION OUTPUT ;
    USE SIGNAL ;
    PORT
      LAYER M5 ;
        RECT  136.944 86.208 136.968 86.4 ;
    END
    PORT
      LAYER M5 ;
        RECT  136.944 84.949 136.968 86.224 ;
    END
  END rd[253]
  PIN rd[254]
    DIRECTION OUTPUT ;
    USE SIGNAL ;
    PORT
      LAYER M3 ;
        RECT  137.448 86.256 137.466 86.4 ;
    END
    PORT
      LAYER M3 ;
        RECT  137.448 84.989 137.466 86.268 ;
    END
  END rd[254]
  PIN rd[255]
    DIRECTION OUTPUT ;
    USE SIGNAL ;
    PORT
      LAYER M5 ;
        RECT  137.952 86.208 137.976 86.4 ;
    END
    PORT
      LAYER M5 ;
        RECT  137.952 85.477 137.976 86.224 ;
    END
  END rd[255]
  PIN rd[25]
    DIRECTION OUTPUT ;
    USE SIGNAL ;
    PORT
      LAYER M5 ;
        RECT  17.664 86.208 17.688 86.4 ;
    END
    PORT
      LAYER M5 ;
        RECT  17.664 85.523 17.688 86.224 ;
    END
  END rd[25]
  PIN rd[26]
    DIRECTION OUTPUT ;
    USE SIGNAL ;
    PORT
      LAYER M3 ;
        RECT  18.18 86.256 18.198 86.4 ;
    END
    PORT
      LAYER M3 ;
        RECT  18.18 85.483 18.198 86.268 ;
    END
  END rd[26]
  PIN rd[27]
    DIRECTION OUTPUT ;
    USE SIGNAL ;
    PORT
      LAYER M5 ;
        RECT  18.672 86.208 18.696 86.4 ;
    END
    PORT
      LAYER M5 ;
        RECT  18.672 85.523 18.696 86.224 ;
    END
  END rd[27]
  PIN rd[28]
    DIRECTION OUTPUT ;
    USE SIGNAL ;
    PORT
      LAYER M3 ;
        RECT  19.224 86.256 19.242 86.4 ;
    END
    PORT
      LAYER M3 ;
        RECT  19.224 84.989 19.242 86.268 ;
    END
  END rd[28]
  PIN rd[29]
    DIRECTION OUTPUT ;
    USE SIGNAL ;
    PORT
      LAYER M5 ;
        RECT  19.728 86.208 19.752 86.4 ;
    END
    PORT
      LAYER M5 ;
        RECT  19.728 85.523 19.752 86.224 ;
    END
  END rd[29]
  PIN rd[2]
    DIRECTION OUTPUT ;
    USE SIGNAL ;
    PORT
      LAYER M3 ;
        RECT  5.616 86.256 5.634 86.4 ;
    END
    PORT
      LAYER M3 ;
        RECT  5.616 86.203 5.634 86.268 ;
    END
  END rd[2]
  PIN rd[30]
    DIRECTION OUTPUT ;
    USE SIGNAL ;
    PORT
      LAYER M3 ;
        RECT  20.268 86.256 20.286 86.4 ;
    END
    PORT
      LAYER M3 ;
        RECT  20.268 85.483 20.286 86.268 ;
    END
  END rd[30]
  PIN rd[31]
    DIRECTION OUTPUT ;
    USE SIGNAL ;
    PORT
      LAYER M5 ;
        RECT  20.784 86.208 20.808 86.4 ;
    END
    PORT
      LAYER M5 ;
        RECT  20.784 85.523 20.808 86.224 ;
    END
  END rd[31]
  PIN rd[32]
    DIRECTION OUTPUT ;
    USE SIGNAL ;
    PORT
      LAYER M3 ;
        RECT  21.312 86.256 21.33 86.4 ;
    END
    PORT
      LAYER M3 ;
        RECT  21.312 84.365 21.33 86.268 ;
    END
  END rd[32]
  PIN rd[33]
    DIRECTION OUTPUT ;
    USE SIGNAL ;
    PORT
      LAYER M5 ;
        RECT  21.84 86.208 21.864 86.4 ;
    END
    PORT
      LAYER M5 ;
        RECT  21.84 83.893 21.864 86.224 ;
    END
  END rd[33]
  PIN rd[34]
    DIRECTION OUTPUT ;
    USE SIGNAL ;
    PORT
      LAYER M3 ;
        RECT  22.356 86.256 22.374 86.4 ;
    END
    PORT
      LAYER M3 ;
        RECT  22.356 85.517 22.374 86.268 ;
    END
  END rd[34]
  PIN rd[35]
    DIRECTION OUTPUT ;
    USE SIGNAL ;
    PORT
      LAYER M5 ;
        RECT  22.896 86.208 22.92 86.4 ;
    END
  END rd[35]
  PIN rd[36]
    DIRECTION OUTPUT ;
    USE SIGNAL ;
    PORT
      LAYER M3 ;
        RECT  23.4 86.256 23.418 86.4 ;
    END
    PORT
      LAYER M3 ;
        RECT  23.4 86.203 23.418 86.268 ;
    END
  END rd[36]
  PIN rd[37]
    DIRECTION OUTPUT ;
    USE SIGNAL ;
    PORT
      LAYER M5 ;
        RECT  23.904 86.208 23.928 86.4 ;
    END
  END rd[37]
  PIN rd[38]
    DIRECTION OUTPUT ;
    USE SIGNAL ;
    PORT
      LAYER M3 ;
        RECT  24.444 86.256 24.462 86.4 ;
    END
    PORT
      LAYER M3 ;
        RECT  24.444 85.517 24.462 86.268 ;
    END
  END rd[38]
  PIN rd[39]
    DIRECTION OUTPUT ;
    USE SIGNAL ;
    PORT
      LAYER M5 ;
        RECT  24.96 86.208 24.984 86.4 ;
    END
    PORT
      LAYER M5 ;
        RECT  24.96 85.523 24.984 86.224 ;
    END
  END rd[39]
  PIN rd[3]
    DIRECTION OUTPUT ;
    USE SIGNAL ;
    PORT
      LAYER M5 ;
        RECT  6.144 86.208 6.168 86.4 ;
    END
  END rd[3]
  PIN rd[40]
    DIRECTION OUTPUT ;
    USE SIGNAL ;
    PORT
      LAYER M3 ;
        RECT  25.488 86.256 25.506 86.4 ;
    END
    PORT
      LAYER M3 ;
        RECT  25.488 85.517 25.506 86.268 ;
    END
  END rd[40]
  PIN rd[41]
    DIRECTION OUTPUT ;
    USE SIGNAL ;
    PORT
      LAYER M5 ;
        RECT  26.016 86.208 26.04 86.4 ;
    END
    PORT
      LAYER M5 ;
        RECT  26.016 83.125 26.04 86.224 ;
    END
  END rd[41]
  PIN rd[42]
    DIRECTION OUTPUT ;
    USE SIGNAL ;
    PORT
      LAYER M3 ;
        RECT  26.532 86.256 26.55 86.4 ;
    END
    PORT
      LAYER M3 ;
        RECT  26.532 84.209 26.55 86.268 ;
    END
  END rd[42]
  PIN rd[43]
    DIRECTION OUTPUT ;
    USE SIGNAL ;
    PORT
      LAYER M5 ;
        RECT  27.072 86.208 27.096 86.4 ;
    END
    PORT
      LAYER M5 ;
        RECT  27.072 83.411 27.096 86.224 ;
    END
  END rd[43]
  PIN rd[44]
    DIRECTION OUTPUT ;
    USE SIGNAL ;
    PORT
      LAYER M3 ;
        RECT  27.576 86.256 27.594 86.4 ;
    END
    PORT
      LAYER M3 ;
        RECT  27.576 84.173 27.594 86.268 ;
    END
  END rd[44]
  PIN rd[45]
    DIRECTION OUTPUT ;
    USE SIGNAL ;
    PORT
      LAYER M5 ;
        RECT  28.128 86.208 28.152 86.4 ;
    END
    PORT
      LAYER M5 ;
        RECT  28.128 83.173 28.152 86.224 ;
    END
  END rd[45]
  PIN rd[46]
    DIRECTION OUTPUT ;
    USE SIGNAL ;
    PORT
      LAYER M3 ;
        RECT  28.62 86.256 28.638 86.4 ;
    END
    PORT
      LAYER M3 ;
        RECT  28.62 84.209 28.638 86.268 ;
    END
  END rd[46]
  PIN rd[47]
    DIRECTION OUTPUT ;
    USE SIGNAL ;
    PORT
      LAYER M5 ;
        RECT  29.136 86.208 29.16 86.4 ;
    END
    PORT
      LAYER M5 ;
        RECT  29.136 84.263 29.16 86.224 ;
    END
  END rd[47]
  PIN rd[48]
    DIRECTION OUTPUT ;
    USE SIGNAL ;
    PORT
      LAYER M3 ;
        RECT  29.7 86.256 29.718 86.4 ;
    END
    PORT
      LAYER M3 ;
        RECT  29.7 84.299 29.718 86.268 ;
    END
  END rd[48]
  PIN rd[49]
    DIRECTION OUTPUT ;
    USE SIGNAL ;
    PORT
      LAYER M5 ;
        RECT  30.192 86.208 30.216 86.4 ;
    END
    PORT
      LAYER M5 ;
        RECT  30.192 84.263 30.216 86.224 ;
    END
  END rd[49]
  PIN rd[4]
    DIRECTION OUTPUT ;
    USE SIGNAL ;
    PORT
      LAYER M3 ;
        RECT  6.66 86.256 6.678 86.4 ;
    END
    PORT
      LAYER M3 ;
        RECT  6.66 85.483 6.678 86.268 ;
    END
  END rd[4]
  PIN rd[50]
    DIRECTION OUTPUT ;
    USE SIGNAL ;
    PORT
      LAYER M3 ;
        RECT  30.744 86.256 30.762 86.4 ;
    END
    PORT
      LAYER M3 ;
        RECT  30.744 84.173 30.762 86.268 ;
    END
  END rd[50]
  PIN rd[51]
    DIRECTION OUTPUT ;
    USE SIGNAL ;
    PORT
      LAYER M5 ;
        RECT  31.248 86.208 31.272 86.4 ;
    END
    PORT
      LAYER M5 ;
        RECT  31.248 85.523 31.272 86.224 ;
    END
  END rd[51]
  PIN rd[52]
    DIRECTION OUTPUT ;
    USE SIGNAL ;
    PORT
      LAYER M3 ;
        RECT  31.788 86.256 31.806 86.4 ;
    END
    PORT
      LAYER M3 ;
        RECT  31.788 85.517 31.806 86.268 ;
    END
  END rd[52]
  PIN rd[53]
    DIRECTION OUTPUT ;
    USE SIGNAL ;
    PORT
      LAYER M5 ;
        RECT  32.304 86.208 32.328 86.4 ;
    END
    PORT
      LAYER M5 ;
        RECT  32.304 85.523 32.328 86.224 ;
    END
  END rd[53]
  PIN rd[54]
    DIRECTION OUTPUT ;
    USE SIGNAL ;
    PORT
      LAYER M3 ;
        RECT  32.832 86.256 32.85 86.4 ;
    END
    PORT
      LAYER M3 ;
        RECT  32.832 85.517 32.85 86.268 ;
    END
  END rd[54]
  PIN rd[55]
    DIRECTION OUTPUT ;
    USE SIGNAL ;
    PORT
      LAYER M5 ;
        RECT  33.36 86.208 33.384 86.4 ;
    END
    PORT
      LAYER M5 ;
        RECT  33.36 84.949 33.384 86.224 ;
    END
  END rd[55]
  PIN rd[56]
    DIRECTION OUTPUT ;
    USE SIGNAL ;
    PORT
      LAYER M3 ;
        RECT  33.876 86.256 33.894 86.4 ;
    END
    PORT
      LAYER M3 ;
        RECT  33.876 84.989 33.894 86.268 ;
    END
  END rd[56]
  PIN rd[57]
    DIRECTION OUTPUT ;
    USE SIGNAL ;
    PORT
      LAYER M5 ;
        RECT  34.368 86.208 34.392 86.4 ;
    END
  END rd[57]
  PIN rd[58]
    DIRECTION OUTPUT ;
    USE SIGNAL ;
    PORT
      LAYER M3 ;
        RECT  34.92 86.256 34.938 86.4 ;
    END
    PORT
      LAYER M3 ;
        RECT  34.92 86.203 34.938 86.268 ;
    END
  END rd[58]
  PIN rd[59]
    DIRECTION OUTPUT ;
    USE SIGNAL ;
    PORT
      LAYER M5 ;
        RECT  35.424 86.208 35.448 86.4 ;
    END
  END rd[59]
  PIN rd[5]
    DIRECTION OUTPUT ;
    USE SIGNAL ;
    PORT
      LAYER M5 ;
        RECT  7.2 86.208 7.224 86.4 ;
    END
    PORT
      LAYER M5 ;
        RECT  7.2 85.523 7.224 86.224 ;
    END
  END rd[5]
  PIN rd[60]
    DIRECTION OUTPUT ;
    USE SIGNAL ;
    PORT
      LAYER M3 ;
        RECT  35.964 86.256 35.982 86.4 ;
    END
    PORT
      LAYER M3 ;
        RECT  35.964 85.517 35.982 86.268 ;
    END
  END rd[60]
  PIN rd[61]
    DIRECTION OUTPUT ;
    USE SIGNAL ;
    PORT
      LAYER M5 ;
        RECT  36.48 86.208 36.504 86.4 ;
    END
    PORT
      LAYER M5 ;
        RECT  36.48 84.949 36.504 86.224 ;
    END
  END rd[61]
  PIN rd[62]
    DIRECTION OUTPUT ;
    USE SIGNAL ;
    PORT
      LAYER M3 ;
        RECT  37.008 86.256 37.026 86.4 ;
    END
    PORT
      LAYER M3 ;
        RECT  37.008 84.989 37.026 86.268 ;
    END
  END rd[62]
  PIN rd[63]
    DIRECTION OUTPUT ;
    USE SIGNAL ;
    PORT
      LAYER M5 ;
        RECT  37.536 86.208 37.56 86.4 ;
    END
    PORT
      LAYER M5 ;
        RECT  37.536 85.523 37.56 86.224 ;
    END
  END rd[63]
  PIN rd[64]
    DIRECTION OUTPUT ;
    USE SIGNAL ;
    PORT
      LAYER M3 ;
        RECT  38.052 86.256 38.07 86.4 ;
    END
    PORT
      LAYER M3 ;
        RECT  38.052 85.517 38.07 86.268 ;
    END
  END rd[64]
  PIN rd[65]
    DIRECTION OUTPUT ;
    USE SIGNAL ;
    PORT
      LAYER M5 ;
        RECT  38.592 86.208 38.616 86.4 ;
    END
  END rd[65]
  PIN rd[66]
    DIRECTION OUTPUT ;
    USE SIGNAL ;
    PORT
      LAYER M3 ;
        RECT  39.096 86.256 39.114 86.4 ;
    END
    PORT
      LAYER M3 ;
        RECT  39.096 86.203 39.114 86.268 ;
    END
  END rd[66]
  PIN rd[67]
    DIRECTION OUTPUT ;
    USE SIGNAL ;
    PORT
      LAYER M5 ;
        RECT  39.6 86.208 39.624 86.4 ;
    END
  END rd[67]
  PIN rd[68]
    DIRECTION OUTPUT ;
    USE SIGNAL ;
    PORT
      LAYER M3 ;
        RECT  40.14 86.256 40.158 86.4 ;
    END
    PORT
      LAYER M3 ;
        RECT  40.14 85.483 40.158 86.268 ;
    END
  END rd[68]
  PIN rd[69]
    DIRECTION OUTPUT ;
    USE SIGNAL ;
    PORT
      LAYER M5 ;
        RECT  40.656 86.208 40.68 86.4 ;
    END
    PORT
      LAYER M5 ;
        RECT  40.656 85.523 40.68 86.224 ;
    END
  END rd[69]
  PIN rd[6]
    DIRECTION OUTPUT ;
    USE SIGNAL ;
    PORT
      LAYER M3 ;
        RECT  7.704 86.256 7.722 86.4 ;
    END
    PORT
      LAYER M3 ;
        RECT  7.704 84.413 7.722 86.268 ;
    END
  END rd[6]
  PIN rd[70]
    DIRECTION OUTPUT ;
    USE SIGNAL ;
    PORT
      LAYER M3 ;
        RECT  41.184 86.256 41.202 86.4 ;
    END
    PORT
      LAYER M3 ;
        RECT  41.184 85.517 41.202 86.268 ;
    END
  END rd[70]
  PIN rd[71]
    DIRECTION OUTPUT ;
    USE SIGNAL ;
    PORT
      LAYER M5 ;
        RECT  41.712 86.208 41.736 86.4 ;
    END
    PORT
      LAYER M5 ;
        RECT  41.712 85.571 41.736 86.224 ;
    END
  END rd[71]
  PIN rd[72]
    DIRECTION OUTPUT ;
    USE SIGNAL ;
    PORT
      LAYER M3 ;
        RECT  42.228 86.256 42.246 86.4 ;
    END
    PORT
      LAYER M3 ;
        RECT  42.228 85.517 42.246 86.268 ;
    END
  END rd[72]
  PIN rd[73]
    DIRECTION OUTPUT ;
    USE SIGNAL ;
    PORT
      LAYER M5 ;
        RECT  42.768 86.208 42.792 86.4 ;
    END
    PORT
      LAYER M5 ;
        RECT  42.768 85.571 42.792 86.224 ;
    END
  END rd[73]
  PIN rd[74]
    DIRECTION OUTPUT ;
    USE SIGNAL ;
    PORT
      LAYER M3 ;
        RECT  43.272 86.256 43.29 86.4 ;
    END
    PORT
      LAYER M3 ;
        RECT  43.272 85.531 43.29 86.268 ;
    END
  END rd[74]
  PIN rd[75]
    DIRECTION OUTPUT ;
    USE SIGNAL ;
    PORT
      LAYER M5 ;
        RECT  43.824 86.208 43.848 86.4 ;
    END
    PORT
      LAYER M5 ;
        RECT  43.824 83.893 43.848 86.224 ;
    END
  END rd[75]
  PIN rd[76]
    DIRECTION OUTPUT ;
    USE SIGNAL ;
    PORT
      LAYER M3 ;
        RECT  44.316 86.256 44.334 86.4 ;
    END
    PORT
      LAYER M3 ;
        RECT  44.316 86.189 44.334 86.268 ;
    END
  END rd[76]
  PIN rd[77]
    DIRECTION OUTPUT ;
    USE SIGNAL ;
    PORT
      LAYER M5 ;
        RECT  44.832 86.208 44.856 86.4 ;
    END
    PORT
      LAYER M5 ;
        RECT  44.832 86.149 44.856 86.224 ;
    END
  END rd[77]
  PIN rd[78]
    DIRECTION OUTPUT ;
    USE SIGNAL ;
    PORT
      LAYER M3 ;
        RECT  45.36 86.256 45.378 86.4 ;
    END
    PORT
      LAYER M3 ;
        RECT  45.36 84.257 45.378 86.268 ;
    END
  END rd[78]
  PIN rd[79]
    DIRECTION OUTPUT ;
    USE SIGNAL ;
    PORT
      LAYER M5 ;
        RECT  45.888 86.208 45.912 86.4 ;
    END
    PORT
      LAYER M5 ;
        RECT  45.888 84.263 45.912 86.224 ;
    END
  END rd[79]
  PIN rd[7]
    DIRECTION OUTPUT ;
    USE SIGNAL ;
    PORT
      LAYER M5 ;
        RECT  8.208 86.208 8.232 86.4 ;
    END
    PORT
      LAYER M5 ;
        RECT  8.208 84.263 8.232 86.224 ;
    END
  END rd[7]
  PIN rd[80]
    DIRECTION OUTPUT ;
    USE SIGNAL ;
    PORT
      LAYER M3 ;
        RECT  46.44 86.256 46.458 86.4 ;
    END
    PORT
      LAYER M3 ;
        RECT  46.44 84.413 46.458 86.268 ;
    END
  END rd[80]
  PIN rd[81]
    DIRECTION OUTPUT ;
    USE SIGNAL ;
    PORT
      LAYER M5 ;
        RECT  46.944 86.208 46.968 86.4 ;
    END
    PORT
      LAYER M5 ;
        RECT  46.944 84.181 46.968 86.224 ;
    END
  END rd[81]
  PIN rd[82]
    DIRECTION OUTPUT ;
    USE SIGNAL ;
    PORT
      LAYER M3 ;
        RECT  47.484 86.256 47.502 86.4 ;
    END
    PORT
      LAYER M3 ;
        RECT  47.484 84.221 47.502 86.268 ;
    END
  END rd[82]
  PIN rd[83]
    DIRECTION OUTPUT ;
    USE SIGNAL ;
    PORT
      LAYER M5 ;
        RECT  48 86.208 48.024 86.4 ;
    END
  END rd[83]
  PIN rd[84]
    DIRECTION OUTPUT ;
    USE SIGNAL ;
    PORT
      LAYER M3 ;
        RECT  48.528 86.256 48.546 86.4 ;
    END
    PORT
      LAYER M3 ;
        RECT  48.528 86.203 48.546 86.268 ;
    END
  END rd[84]
  PIN rd[85]
    DIRECTION OUTPUT ;
    USE SIGNAL ;
    PORT
      LAYER M5 ;
        RECT  49.056 86.208 49.08 86.4 ;
    END
  END rd[85]
  PIN rd[86]
    DIRECTION OUTPUT ;
    USE SIGNAL ;
    PORT
      LAYER M3 ;
        RECT  49.572 86.256 49.59 86.4 ;
    END
    PORT
      LAYER M3 ;
        RECT  49.572 85.517 49.59 86.268 ;
    END
  END rd[86]
  PIN rd[87]
    DIRECTION OUTPUT ;
    USE SIGNAL ;
    PORT
      LAYER M5 ;
        RECT  50.064 86.208 50.088 86.4 ;
    END
    PORT
      LAYER M5 ;
        RECT  50.064 85.523 50.088 86.224 ;
    END
  END rd[87]
  PIN rd[88]
    DIRECTION OUTPUT ;
    USE SIGNAL ;
    PORT
      LAYER M3 ;
        RECT  50.616 86.256 50.634 86.4 ;
    END
    PORT
      LAYER M3 ;
        RECT  50.616 85.483 50.634 86.268 ;
    END
  END rd[88]
  PIN rd[89]
    DIRECTION OUTPUT ;
    USE SIGNAL ;
    PORT
      LAYER M5 ;
        RECT  51.12 86.208 51.144 86.4 ;
    END
    PORT
      LAYER M5 ;
        RECT  51.12 85.523 51.144 86.224 ;
    END
  END rd[89]
  PIN rd[8]
    DIRECTION OUTPUT ;
    USE SIGNAL ;
    PORT
      LAYER M3 ;
        RECT  8.748 86.256 8.766 86.4 ;
    END
    PORT
      LAYER M3 ;
        RECT  8.748 84.209 8.766 86.268 ;
    END
  END rd[8]
  PIN rd[90]
    DIRECTION OUTPUT ;
    USE SIGNAL ;
    PORT
      LAYER M3 ;
        RECT  51.66 86.256 51.678 86.4 ;
    END
    PORT
      LAYER M3 ;
        RECT  51.66 86.233 51.75 86.261 ;
    END
    PORT
      LAYER M3 ;
        RECT  51.66 86.261 51.678 86.268 ;
    END
  END rd[90]
  PIN rd[91]
    DIRECTION OUTPUT ;
    USE SIGNAL ;
    PORT
      LAYER M5 ;
        RECT  52.176 86.208 52.2 86.4 ;
    END
  END rd[91]
  PIN rd[92]
    DIRECTION OUTPUT ;
    USE SIGNAL ;
    PORT
      LAYER M3 ;
        RECT  52.704 86.256 52.722 86.4 ;
    END
    PORT
      LAYER M3 ;
        RECT  52.704 86.203 52.722 86.268 ;
    END
  END rd[92]
  PIN rd[93]
    DIRECTION OUTPUT ;
    USE SIGNAL ;
    PORT
      LAYER M5 ;
        RECT  53.232 86.208 53.256 86.4 ;
    END
  END rd[93]
  PIN rd[94]
    DIRECTION OUTPUT ;
    USE SIGNAL ;
    PORT
      LAYER M3 ;
        RECT  53.748 86.256 53.766 86.4 ;
    END
    PORT
      LAYER M3 ;
        RECT  53.748 84.989 53.766 86.268 ;
    END
  END rd[94]
  PIN rd[95]
    DIRECTION OUTPUT ;
    USE SIGNAL ;
    PORT
      LAYER M5 ;
        RECT  54.288 86.208 54.312 86.4 ;
    END
    PORT
      LAYER M5 ;
        RECT  54.288 84.949 54.312 86.224 ;
    END
  END rd[95]
  PIN rd[96]
    DIRECTION OUTPUT ;
    USE SIGNAL ;
    PORT
      LAYER M3 ;
        RECT  54.792 86.256 54.81 86.4 ;
    END
    PORT
      LAYER M3 ;
        RECT  54.792 84.989 54.81 86.268 ;
    END
  END rd[96]
  PIN rd[97]
    DIRECTION OUTPUT ;
    USE SIGNAL ;
    PORT
      LAYER M5 ;
        RECT  55.296 86.208 55.32 86.4 ;
    END
    PORT
      LAYER M5 ;
        RECT  55.296 85.523 55.32 86.224 ;
    END
  END rd[97]
  PIN rd[98]
    DIRECTION OUTPUT ;
    USE SIGNAL ;
    PORT
      LAYER M3 ;
        RECT  55.836 86.256 55.854 86.4 ;
    END
    PORT
      LAYER M3 ;
        RECT  55.836 85.483 55.854 86.268 ;
    END
  END rd[98]
  PIN rd[99]
    DIRECTION OUTPUT ;
    USE SIGNAL ;
    PORT
      LAYER M5 ;
        RECT  56.352 86.208 56.376 86.4 ;
    END
    PORT
      LAYER M5 ;
        RECT  56.352 85.523 56.376 86.224 ;
    END
  END rd[99]
  PIN rd[9]
    DIRECTION OUTPUT ;
    USE SIGNAL ;
    PORT
      LAYER M5 ;
        RECT  9.264 86.208 9.288 86.4 ;
    END
    PORT
      LAYER M5 ;
        RECT  9.264 83.843 9.288 86.224 ;
    END
  END rd[9]
  PIN rq0
    DIRECTION INPUT ;
    USE SIGNAL ;
    PORT
      LAYER M4 ;
        RECT  0 79.872 0.192 79.896 ;
    END
    PORT
      LAYER M4 ;
        RECT  0.156 79.872 2.408 79.896 ;
    END
  END rq0
  PIN rq1
    DIRECTION INPUT ;
    USE SIGNAL ;
    PORT
      LAYER M4 ;
        RECT  0 81.36 0.192 81.384 ;
    END
    PORT
      LAYER M4 ;
        RECT  0.156 81.36 0.245 81.384 ;
    END
  END rq1
  PIN rst_n
    DIRECTION INPUT ;
    USE SIGNAL ;
    PORT
      LAYER M4 ;
        RECT  0 5.088 0.192 5.112 ;
    END
    PORT
      LAYER M4 ;
        RECT  0.156 5.088 0.245 5.112 ;
    END
  END rst_n
  PIN wq0
    DIRECTION INPUT ;
    USE SIGNAL ;
    PORT
      LAYER M4 ;
        RECT  0 27.504 0.192 27.528 ;
    END
    PORT
      LAYER M4 ;
        RECT  0.156 27.504 2.408 27.528 ;
    END
  END wq0
  PIN wq1
    DIRECTION INPUT ;
    USE SIGNAL ;
    PORT
      LAYER M4 ;
        RECT  0 28.992 0.192 29.016 ;
    END
    PORT
      LAYER M4 ;
        RECT  0.156 28.992 0.245 29.016 ;
    END
  END wq1
  PIN wr0[0]
    DIRECTION INPUT ;
    USE SIGNAL ;
    PORT
      LAYER M4 ;
        RECT  0 6.576 0.192 6.6 ;
    END
    PORT
      LAYER M4 ;
        RECT  0.156 6.576 0.245 6.6 ;
    END
  END wr0[0]
  PIN wr0[1]
    DIRECTION INPUT ;
    USE SIGNAL ;
    PORT
      LAYER M4 ;
        RECT  0 8.064 0.192 8.088 ;
    END
    PORT
      LAYER M4 ;
        RECT  0.156 8.064 0.245 8.088 ;
    END
  END wr0[1]
  PIN wr0[2]
    DIRECTION INPUT ;
    USE SIGNAL ;
    PORT
      LAYER M4 ;
        RECT  0 9.552 0.192 9.576 ;
    END
    PORT
      LAYER M4 ;
        RECT  0.156 9.552 0.245 9.576 ;
    END
  END wr0[2]
  PIN wr0[3]
    DIRECTION INPUT ;
    USE SIGNAL ;
    PORT
      LAYER M4 ;
        RECT  0 11.04 0.192 11.064 ;
    END
    PORT
      LAYER M4 ;
        RECT  0.156 11.04 0.245 11.064 ;
    END
  END wr0[3]
  PIN wr0[4]
    DIRECTION INPUT ;
    USE SIGNAL ;
    PORT
      LAYER M4 ;
        RECT  0 12.576 0.192 12.6 ;
    END
    PORT
      LAYER M4 ;
        RECT  0.156 12.576 2.408 12.6 ;
    END
  END wr0[4]
  PIN wr0[5]
    DIRECTION INPUT ;
    USE SIGNAL ;
    PORT
      LAYER M4 ;
        RECT  0 14.064 0.192 14.088 ;
    END
    PORT
      LAYER M4 ;
        RECT  0.156 14.064 2.408 14.088 ;
    END
  END wr0[5]
  PIN wr0[6]
    DIRECTION INPUT ;
    USE SIGNAL ;
    PORT
      LAYER M4 ;
        RECT  0 15.552 0.192 15.576 ;
    END
    PORT
      LAYER M4 ;
        RECT  0.156 15.552 0.245 15.576 ;
    END
  END wr0[6]
  PIN wr1[0]
    DIRECTION INPUT ;
    USE SIGNAL ;
    PORT
      LAYER M4 ;
        RECT  0 17.04 0.192 17.064 ;
    END
    PORT
      LAYER M4 ;
        RECT  0.156 17.04 0.245 17.064 ;
    END
  END wr1[0]
  PIN wr1[1]
    DIRECTION INPUT ;
    USE SIGNAL ;
    PORT
      LAYER M4 ;
        RECT  0 18.528 0.192 18.552 ;
    END
    PORT
      LAYER M4 ;
        RECT  0.156 18.528 0.245 18.552 ;
    END
  END wr1[1]
  PIN wr1[2]
    DIRECTION INPUT ;
    USE SIGNAL ;
    PORT
      LAYER M4 ;
        RECT  0 20.016 0.192 20.04 ;
    END
    PORT
      LAYER M4 ;
        RECT  0.156 20.016 0.245 20.04 ;
    END
  END wr1[2]
  PIN wr1[3]
    DIRECTION INPUT ;
    USE SIGNAL ;
    PORT
      LAYER M4 ;
        RECT  0 21.552 0.192 21.576 ;
    END
    PORT
      LAYER M4 ;
        RECT  0.156 21.552 0.245 21.576 ;
    END
  END wr1[3]
  PIN wr1[4]
    DIRECTION INPUT ;
    USE SIGNAL ;
    PORT
      LAYER M4 ;
        RECT  0 23.04 0.192 23.064 ;
    END
    PORT
      LAYER M4 ;
        RECT  0.156 23.04 0.245 23.064 ;
    END
  END wr1[4]
  PIN wr1[5]
    DIRECTION INPUT ;
    USE SIGNAL ;
    PORT
      LAYER M4 ;
        RECT  0 24.528 0.192 24.552 ;
    END
    PORT
      LAYER M4 ;
        RECT  0.156 24.528 2.408 24.552 ;
    END
  END wr1[5]
  PIN wr1[6]
    DIRECTION INPUT ;
    USE SIGNAL ;
    PORT
      LAYER M4 ;
        RECT  0 26.016 0.192 26.04 ;
    END
    PORT
      LAYER M4 ;
        RECT  0.156 26.016 0.245 26.04 ;
    END
  END wr1[6]
  PIN VDD
    DIRECTION INOUT ;
    USE POWER ;
    PORT
      LAYER M5 ;
        RECT  137.592 2.151 137.712 84.249 ;
        RECT  132.192 2.151 132.312 84.249 ;
        RECT  126.792 2.151 126.912 84.249 ;
        RECT  121.392 2.151 121.512 84.249 ;
        RECT  115.992 2.151 116.112 84.249 ;
        RECT  110.592 2.151 110.712 84.249 ;
        RECT  105.192 2.151 105.312 84.249 ;
        RECT  99.792 2.151 99.912 84.249 ;
        RECT  94.392 2.151 94.512 84.249 ;
        RECT  88.992 2.151 89.112 84.249 ;
        RECT  83.592 2.151 83.712 84.249 ;
        RECT  78.192 2.151 78.312 84.249 ;
        RECT  72.792 2.151 72.912 84.249 ;
        RECT  67.392 2.151 67.512 84.249 ;
        RECT  61.992 2.151 62.112 84.249 ;
        RECT  56.592 2.151 56.712 84.249 ;
        RECT  51.192 2.151 51.312 84.249 ;
        RECT  45.792 2.151 45.912 84.249 ;
        RECT  40.392 2.151 40.512 84.249 ;
        RECT  34.992 2.151 35.112 84.249 ;
        RECT  29.592 2.151 29.712 84.249 ;
        RECT  24.192 2.151 24.312 84.249 ;
        RECT  18.792 2.151 18.912 84.249 ;
        RECT  13.392 2.151 13.512 84.249 ;
        RECT  7.992 2.151 8.112 84.249 ;
        RECT  2.592 2.151 2.712 84.249 ;
    END
  END VDD
  PIN VSS
    DIRECTION INOUT ;
    USE GROUND ;
    PORT
      LAYER M5 ;
        RECT  137.4 2.137 137.52 84.263 ;
        RECT  132 2.137 132.12 84.263 ;
        RECT  126.6 2.137 126.72 84.263 ;
        RECT  121.2 2.137 121.32 84.263 ;
        RECT  115.8 2.137 115.92 84.263 ;
        RECT  110.4 2.137 110.52 84.263 ;
        RECT  105 2.137 105.12 84.263 ;
        RECT  99.6 2.137 99.72 84.263 ;
        RECT  94.2 2.137 94.32 84.263 ;
        RECT  88.8 2.137 88.92 84.263 ;
        RECT  83.4 2.137 83.52 84.263 ;
        RECT  78 2.137 78.12 84.263 ;
        RECT  72.6 2.137 72.72 84.263 ;
        RECT  67.2 2.137 67.32 84.263 ;
        RECT  61.8 2.137 61.92 84.263 ;
        RECT  56.4 2.137 56.52 84.263 ;
        RECT  51 2.137 51.12 84.263 ;
        RECT  45.6 2.137 45.72 84.263 ;
        RECT  40.2 2.137 40.32 84.263 ;
        RECT  34.8 2.137 34.92 84.263 ;
        RECT  29.4 2.137 29.52 84.263 ;
        RECT  24 2.137 24.12 84.263 ;
        RECT  18.6 2.137 18.72 84.263 ;
        RECT  13.2 2.137 13.32 84.263 ;
        RECT  7.8 2.137 7.92 84.263 ;
        RECT  2.4 2.137 2.52 84.263 ;
    END
  END VSS
  # OT_OBS_CLOSED layer=M5 d_um=1.536 added=269
  OBS
    LAYER RVTN ;
     RECT  2.16 2.16 140.4 2.295 ;
     RECT  2.16 2.565 140.4 2.835 ;
     RECT  2.16 3.105 140.4 3.375 ;
     RECT  2.16 3.645 140.4 3.915 ;
     RECT  2.16 4.185 140.4 4.455 ;
     RECT  2.16 4.725 140.4 4.995 ;
     RECT  2.16 5.265 140.4 5.535 ;
     RECT  2.16 5.805 140.4 6.075 ;
     RECT  2.16 6.345 140.4 6.615 ;
     RECT  2.16 6.885 140.4 7.155 ;
     RECT  2.16 7.425 140.4 7.695 ;
     RECT  2.16 7.965 140.4 8.235 ;
     RECT  2.16 8.505 140.4 8.775 ;
     RECT  2.16 9.045 140.4 9.315 ;
     RECT  2.16 9.585 140.4 9.855 ;
     RECT  2.16 10.125 140.4 10.395 ;
     RECT  2.16 10.665 140.4 10.935 ;
     RECT  2.16 11.205 140.4 11.475 ;
     RECT  2.16 11.745 140.4 12.015 ;
     RECT  2.16 12.285 140.4 12.555 ;
     RECT  2.16 12.825 140.4 13.095 ;
     RECT  2.16 13.365 140.4 13.635 ;
     RECT  2.16 13.905 140.4 14.175 ;
     RECT  2.16 14.445 140.4 14.715 ;
     RECT  2.16 14.985 140.4 15.255 ;
     RECT  2.16 15.525 140.4 15.795 ;
     RECT  2.16 16.065 140.4 16.335 ;
     RECT  2.16 16.605 140.4 16.875 ;
     RECT  2.16 17.145 140.4 17.415 ;
     RECT  2.16 17.685 140.4 17.955 ;
     RECT  2.16 18.225 140.4 18.495 ;
     RECT  2.16 18.765 140.4 19.035 ;
     RECT  2.16 19.305 140.4 19.575 ;
     RECT  2.16 19.845 140.4 20.115 ;
     RECT  2.16 20.385 20.412 20.655 ;
     RECT  119.34 20.385 140.4 20.655 ;
     RECT  2.16 20.925 20.412 21.195 ;
     RECT  119.34 20.925 140.4 21.195 ;
     RECT  2.16 21.465 20.412 21.735 ;
     RECT  119.34 21.465 140.4 21.735 ;
     RECT  2.16 22.005 20.412 22.275 ;
     RECT  119.34 22.005 140.4 22.275 ;
     RECT  2.16 22.545 20.412 22.815 ;
     RECT  119.34 22.545 140.4 22.815 ;
     RECT  2.16 23.085 20.412 23.355 ;
     RECT  119.34 23.085 140.4 23.355 ;
     RECT  2.16 23.625 20.412 23.895 ;
     RECT  119.34 23.625 140.4 23.895 ;
     RECT  2.16 24.165 20.412 24.435 ;
     RECT  119.34 24.165 140.4 24.435 ;
     RECT  2.16 24.705 20.412 24.975 ;
     RECT  119.34 24.705 140.4 24.975 ;
     RECT  2.16 25.245 20.412 25.515 ;
     RECT  119.34 25.245 140.4 25.515 ;
     RECT  2.16 25.785 20.412 26.055 ;
     RECT  119.34 25.785 140.4 26.055 ;
     RECT  2.16 26.325 20.412 26.595 ;
     RECT  119.34 26.325 140.4 26.595 ;
     RECT  2.16 26.865 20.412 27.135 ;
     RECT  119.34 26.865 140.4 27.135 ;
     RECT  2.16 27.405 20.412 27.675 ;
     RECT  119.34 27.405 140.4 27.675 ;
     RECT  2.16 27.945 20.412 28.215 ;
     RECT  119.34 27.945 140.4 28.215 ;
     RECT  2.16 28.485 20.412 28.755 ;
     RECT  119.34 28.485 140.4 28.755 ;
     RECT  2.16 29.025 20.412 29.295 ;
     RECT  119.34 29.025 140.4 29.295 ;
     RECT  2.16 29.565 20.412 29.835 ;
     RECT  119.34 29.565 140.4 29.835 ;
     RECT  2.16 30.105 20.412 30.375 ;
     RECT  119.34 30.105 140.4 30.375 ;
     RECT  2.16 30.645 20.412 30.915 ;
     RECT  119.34 30.645 140.4 30.915 ;
     RECT  2.16 31.185 20.412 31.455 ;
     RECT  119.34 31.185 140.4 31.455 ;
     RECT  2.16 31.725 20.412 31.995 ;
     RECT  119.34 31.725 140.4 31.995 ;
     RECT  2.16 32.265 20.412 32.535 ;
     RECT  119.34 32.265 140.4 32.535 ;
     RECT  2.16 32.805 20.412 33.075 ;
     RECT  119.34 32.805 140.4 33.075 ;
     RECT  2.16 33.345 20.412 33.615 ;
     RECT  119.34 33.345 140.4 33.615 ;
     RECT  2.16 33.885 20.412 34.155 ;
     RECT  119.34 33.885 140.4 34.155 ;
     RECT  2.16 34.425 20.412 34.695 ;
     RECT  119.34 34.425 140.4 34.695 ;
     RECT  2.16 34.965 20.412 35.235 ;
     RECT  119.34 34.965 140.4 35.235 ;
     RECT  2.16 35.505 20.412 35.775 ;
     RECT  119.34 35.505 140.4 35.775 ;
     RECT  2.16 36.045 20.412 36.315 ;
     RECT  119.34 36.045 140.4 36.315 ;
     RECT  2.16 36.585 20.412 36.855 ;
     RECT  119.34 36.585 140.4 36.855 ;
     RECT  2.16 37.125 20.412 37.395 ;
     RECT  119.34 37.125 140.4 37.395 ;
     RECT  2.16 37.665 20.412 37.935 ;
     RECT  119.34 37.665 140.4 37.935 ;
     RECT  2.16 38.205 20.412 38.475 ;
     RECT  119.34 38.205 140.4 38.475 ;
     RECT  2.16 38.745 20.412 39.015 ;
     RECT  119.34 38.745 140.4 39.015 ;
     RECT  2.16 39.285 20.412 39.555 ;
     RECT  119.34 39.285 140.4 39.555 ;
     RECT  2.16 39.825 20.412 40.095 ;
     RECT  119.34 39.825 140.4 40.095 ;
     RECT  2.16 40.365 20.412 40.635 ;
     RECT  119.34 40.365 140.4 40.635 ;
     RECT  2.16 40.905 20.412 41.175 ;
     RECT  119.34 40.905 140.4 41.175 ;
     RECT  2.16 41.445 20.412 41.715 ;
     RECT  119.34 41.445 140.4 41.715 ;
     RECT  2.16 41.985 20.412 42.255 ;
     RECT  119.34 41.985 140.4 42.255 ;
     RECT  2.16 42.525 20.412 42.795 ;
     RECT  119.34 42.525 140.4 42.795 ;
     RECT  2.16 43.065 20.412 43.335 ;
     RECT  119.34 43.065 140.4 43.335 ;
     RECT  2.16 43.605 20.412 43.875 ;
     RECT  119.34 43.605 140.4 43.875 ;
     RECT  2.16 44.145 20.412 44.415 ;
     RECT  119.34 44.145 140.4 44.415 ;
     RECT  2.16 44.685 20.412 44.955 ;
     RECT  119.34 44.685 140.4 44.955 ;
     RECT  2.16 45.225 20.412 45.495 ;
     RECT  119.34 45.225 140.4 45.495 ;
     RECT  2.16 45.765 20.412 46.035 ;
     RECT  119.34 45.765 140.4 46.035 ;
     RECT  2.16 46.305 20.412 46.575 ;
     RECT  119.34 46.305 140.4 46.575 ;
     RECT  2.16 46.845 20.412 47.115 ;
     RECT  119.34 46.845 140.4 47.115 ;
     RECT  2.16 47.385 20.412 47.655 ;
     RECT  119.34 47.385 140.4 47.655 ;
     RECT  2.16 47.925 20.412 48.195 ;
     RECT  119.34 47.925 140.4 48.195 ;
     RECT  2.16 48.465 20.412 48.735 ;
     RECT  119.34 48.465 140.4 48.735 ;
     RECT  2.16 49.005 20.412 49.275 ;
     RECT  119.34 49.005 140.4 49.275 ;
     RECT  2.16 49.545 20.412 49.815 ;
     RECT  119.34 49.545 140.4 49.815 ;
     RECT  2.16 50.085 20.412 50.355 ;
     RECT  119.34 50.085 140.4 50.355 ;
     RECT  2.16 50.625 20.412 50.895 ;
     RECT  119.34 50.625 140.4 50.895 ;
     RECT  2.16 51.165 20.412 51.435 ;
     RECT  119.34 51.165 140.4 51.435 ;
     RECT  2.16 51.705 20.412 51.975 ;
     RECT  119.34 51.705 140.4 51.975 ;
     RECT  2.16 52.245 20.412 52.515 ;
     RECT  119.34 52.245 140.4 52.515 ;
     RECT  2.16 52.785 20.412 53.055 ;
     RECT  119.34 52.785 140.4 53.055 ;
     RECT  2.16 53.325 20.412 53.595 ;
     RECT  119.34 53.325 140.4 53.595 ;
     RECT  2.16 53.865 20.412 54.135 ;
     RECT  119.34 53.865 140.4 54.135 ;
     RECT  2.16 54.405 20.412 54.675 ;
     RECT  119.34 54.405 140.4 54.675 ;
     RECT  2.16 54.945 20.412 55.215 ;
     RECT  119.34 54.945 140.4 55.215 ;
     RECT  2.16 55.485 20.412 55.755 ;
     RECT  119.34 55.485 140.4 55.755 ;
     RECT  2.16 56.025 20.412 56.295 ;
     RECT  119.34 56.025 140.4 56.295 ;
     RECT  2.16 56.565 20.412 56.835 ;
     RECT  119.34 56.565 140.4 56.835 ;
     RECT  2.16 57.105 20.412 57.375 ;
     RECT  119.34 57.105 140.4 57.375 ;
     RECT  2.16 57.645 20.412 57.915 ;
     RECT  119.34 57.645 140.4 57.915 ;
     RECT  2.16 58.185 20.412 58.455 ;
     RECT  119.34 58.185 140.4 58.455 ;
     RECT  2.16 58.725 20.412 58.995 ;
     RECT  119.34 58.725 140.4 58.995 ;
     RECT  2.16 59.265 20.412 59.535 ;
     RECT  119.34 59.265 140.4 59.535 ;
     RECT  2.16 59.805 20.412 60.075 ;
     RECT  119.34 59.805 140.4 60.075 ;
     RECT  2.16 60.345 20.412 60.615 ;
     RECT  119.34 60.345 140.4 60.615 ;
     RECT  2.16 60.885 20.412 61.155 ;
     RECT  119.34 60.885 140.4 61.155 ;
     RECT  2.16 61.425 20.412 61.695 ;
     RECT  119.34 61.425 140.4 61.695 ;
     RECT  2.16 61.965 20.412 62.235 ;
     RECT  119.34 61.965 140.4 62.235 ;
     RECT  2.16 62.505 20.412 62.775 ;
     RECT  119.34 62.505 140.4 62.775 ;
     RECT  2.16 63.045 20.412 63.315 ;
     RECT  119.34 63.045 140.4 63.315 ;
     RECT  2.16 63.585 20.412 63.855 ;
     RECT  119.34 63.585 140.4 63.855 ;
     RECT  2.16 64.125 20.412 64.395 ;
     RECT  119.34 64.125 140.4 64.395 ;
     RECT  2.16 64.665 20.412 64.935 ;
     RECT  119.34 64.665 140.4 64.935 ;
     RECT  2.16 65.205 20.412 65.475 ;
     RECT  119.34 65.205 140.4 65.475 ;
     RECT  2.16 65.745 140.4 66.015 ;
     RECT  2.16 66.285 140.4 66.555 ;
     RECT  2.16 66.825 140.4 67.095 ;
     RECT  2.16 67.365 140.4 67.635 ;
     RECT  2.16 67.905 140.4 68.175 ;
     RECT  2.16 68.445 140.4 68.715 ;
     RECT  2.16 68.985 140.4 69.255 ;
     RECT  2.16 69.525 140.4 69.795 ;
     RECT  2.16 70.065 140.4 70.335 ;
     RECT  2.16 70.605 140.4 70.875 ;
     RECT  2.16 71.145 140.4 71.415 ;
     RECT  2.16 71.685 140.4 71.955 ;
     RECT  2.16 72.225 140.4 72.495 ;
     RECT  2.16 72.765 140.4 73.035 ;
     RECT  2.16 73.305 140.4 73.575 ;
     RECT  2.16 73.845 140.4 74.115 ;
     RECT  2.16 74.385 140.4 74.655 ;
     RECT  2.16 74.925 140.4 75.195 ;
     RECT  2.16 75.465 140.4 75.735 ;
     RECT  2.16 76.005 140.4 76.275 ;
     RECT  2.16 76.545 140.4 76.815 ;
     RECT  2.16 77.085 140.4 77.355 ;
     RECT  2.16 77.625 140.4 77.895 ;
     RECT  2.16 78.165 140.4 78.435 ;
     RECT  2.16 78.705 140.4 78.975 ;
     RECT  2.16 79.245 140.4 79.515 ;
     RECT  2.16 79.785 140.4 80.055 ;
     RECT  2.16 80.325 140.4 80.595 ;
     RECT  2.16 80.865 140.4 81.135 ;
     RECT  2.16 81.405 140.4 81.675 ;
     RECT  2.16 81.945 140.4 82.215 ;
     RECT  2.16 82.485 140.4 82.755 ;
     RECT  2.16 83.025 140.4 83.295 ;
     RECT  2.16 83.565 140.4 83.835 ;
     RECT  2.16 84.105 140.4 84.24 ;
    LAYER RVTP ;
     RECT  2.16 2.295 140.4 2.565 ;
     RECT  2.16 2.835 140.4 3.105 ;
     RECT  2.16 3.375 140.4 3.645 ;
     RECT  2.16 3.915 140.4 4.185 ;
     RECT  2.16 4.455 140.4 4.725 ;
     RECT  2.16 4.995 140.4 5.265 ;
     RECT  2.16 5.535 140.4 5.805 ;
     RECT  2.16 6.075 140.4 6.345 ;
     RECT  2.16 6.615 140.4 6.885 ;
     RECT  2.16 7.155 140.4 7.425 ;
     RECT  2.16 7.695 140.4 7.965 ;
     RECT  2.16 8.235 140.4 8.505 ;
     RECT  2.16 8.775 140.4 9.045 ;
     RECT  2.16 9.315 140.4 9.585 ;
     RECT  2.16 9.855 140.4 10.125 ;
     RECT  2.16 10.395 140.4 10.665 ;
     RECT  2.16 10.935 140.4 11.205 ;
     RECT  2.16 11.475 140.4 11.745 ;
     RECT  2.16 12.015 140.4 12.285 ;
     RECT  2.16 12.555 140.4 12.825 ;
     RECT  2.16 13.095 140.4 13.365 ;
     RECT  2.16 13.635 140.4 13.905 ;
     RECT  2.16 14.175 140.4 14.445 ;
     RECT  2.16 14.715 140.4 14.985 ;
     RECT  2.16 15.255 140.4 15.525 ;
     RECT  2.16 15.795 140.4 16.065 ;
     RECT  2.16 16.335 140.4 16.605 ;
     RECT  2.16 16.875 140.4 17.145 ;
     RECT  2.16 17.415 140.4 17.685 ;
     RECT  2.16 17.955 140.4 18.225 ;
     RECT  2.16 18.495 140.4 18.765 ;
     RECT  2.16 19.035 140.4 19.305 ;
     RECT  2.16 19.575 140.4 19.845 ;
     RECT  2.16 20.115 140.4 20.25 ;
     RECT  2.16 20.25 20.412 20.385 ;
     RECT  119.34 20.25 140.4 20.385 ;
     RECT  2.16 20.655 20.412 20.925 ;
     RECT  119.34 20.655 140.4 20.925 ;
     RECT  2.16 21.195 20.412 21.465 ;
     RECT  119.34 21.195 140.4 21.465 ;
     RECT  2.16 21.735 20.412 22.005 ;
     RECT  119.34 21.735 140.4 22.005 ;
     RECT  2.16 22.275 20.412 22.545 ;
     RECT  119.34 22.275 140.4 22.545 ;
     RECT  2.16 22.815 20.412 23.085 ;
     RECT  119.34 22.815 140.4 23.085 ;
     RECT  2.16 23.355 20.412 23.625 ;
     RECT  119.34 23.355 140.4 23.625 ;
     RECT  2.16 23.895 20.412 24.165 ;
     RECT  119.34 23.895 140.4 24.165 ;
     RECT  2.16 24.435 20.412 24.705 ;
     RECT  119.34 24.435 140.4 24.705 ;
     RECT  2.16 24.975 20.412 25.245 ;
     RECT  119.34 24.975 140.4 25.245 ;
     RECT  2.16 25.515 20.412 25.785 ;
     RECT  119.34 25.515 140.4 25.785 ;
     RECT  2.16 26.055 20.412 26.325 ;
     RECT  119.34 26.055 140.4 26.325 ;
     RECT  2.16 26.595 20.412 26.865 ;
     RECT  119.34 26.595 140.4 26.865 ;
     RECT  2.16 27.135 20.412 27.405 ;
     RECT  119.34 27.135 140.4 27.405 ;
     RECT  2.16 27.675 20.412 27.945 ;
     RECT  119.34 27.675 140.4 27.945 ;
     RECT  2.16 28.215 20.412 28.485 ;
     RECT  119.34 28.215 140.4 28.485 ;
     RECT  2.16 28.755 20.412 29.025 ;
     RECT  119.34 28.755 140.4 29.025 ;
     RECT  2.16 29.295 20.412 29.565 ;
     RECT  119.34 29.295 140.4 29.565 ;
     RECT  2.16 29.835 20.412 30.105 ;
     RECT  119.34 29.835 140.4 30.105 ;
     RECT  2.16 30.375 20.412 30.645 ;
     RECT  119.34 30.375 140.4 30.645 ;
     RECT  2.16 30.915 20.412 31.185 ;
     RECT  119.34 30.915 140.4 31.185 ;
     RECT  2.16 31.455 20.412 31.725 ;
     RECT  119.34 31.455 140.4 31.725 ;
     RECT  2.16 31.995 20.412 32.265 ;
     RECT  119.34 31.995 140.4 32.265 ;
     RECT  2.16 32.535 20.412 32.805 ;
     RECT  119.34 32.535 140.4 32.805 ;
     RECT  2.16 33.075 20.412 33.345 ;
     RECT  119.34 33.075 140.4 33.345 ;
     RECT  2.16 33.615 20.412 33.885 ;
     RECT  119.34 33.615 140.4 33.885 ;
     RECT  2.16 34.155 20.412 34.425 ;
     RECT  119.34 34.155 140.4 34.425 ;
     RECT  2.16 34.695 20.412 34.965 ;
     RECT  119.34 34.695 140.4 34.965 ;
     RECT  2.16 35.235 20.412 35.505 ;
     RECT  119.34 35.235 140.4 35.505 ;
     RECT  2.16 35.775 20.412 36.045 ;
     RECT  119.34 35.775 140.4 36.045 ;
     RECT  2.16 36.315 20.412 36.585 ;
     RECT  119.34 36.315 140.4 36.585 ;
     RECT  2.16 36.855 20.412 37.125 ;
     RECT  119.34 36.855 140.4 37.125 ;
     RECT  2.16 37.395 20.412 37.665 ;
     RECT  119.34 37.395 140.4 37.665 ;
     RECT  2.16 37.935 20.412 38.205 ;
     RECT  119.34 37.935 140.4 38.205 ;
     RECT  2.16 38.475 20.412 38.745 ;
     RECT  119.34 38.475 140.4 38.745 ;
     RECT  2.16 39.015 20.412 39.285 ;
     RECT  119.34 39.015 140.4 39.285 ;
     RECT  2.16 39.555 20.412 39.825 ;
     RECT  119.34 39.555 140.4 39.825 ;
     RECT  2.16 40.095 20.412 40.365 ;
     RECT  119.34 40.095 140.4 40.365 ;
     RECT  2.16 40.635 20.412 40.905 ;
     RECT  119.34 40.635 140.4 40.905 ;
     RECT  2.16 41.175 20.412 41.445 ;
     RECT  119.34 41.175 140.4 41.445 ;
     RECT  2.16 41.715 20.412 41.985 ;
     RECT  119.34 41.715 140.4 41.985 ;
     RECT  2.16 42.255 20.412 42.525 ;
     RECT  119.34 42.255 140.4 42.525 ;
     RECT  2.16 42.795 20.412 43.065 ;
     RECT  119.34 42.795 140.4 43.065 ;
     RECT  2.16 43.335 20.412 43.605 ;
     RECT  119.34 43.335 140.4 43.605 ;
     RECT  2.16 43.875 20.412 44.145 ;
     RECT  119.34 43.875 140.4 44.145 ;
     RECT  2.16 44.415 20.412 44.685 ;
     RECT  119.34 44.415 140.4 44.685 ;
     RECT  2.16 44.955 20.412 45.225 ;
     RECT  119.34 44.955 140.4 45.225 ;
     RECT  2.16 45.495 20.412 45.765 ;
     RECT  119.34 45.495 140.4 45.765 ;
     RECT  2.16 46.035 20.412 46.305 ;
     RECT  119.34 46.035 140.4 46.305 ;
     RECT  2.16 46.575 20.412 46.845 ;
     RECT  119.34 46.575 140.4 46.845 ;
     RECT  2.16 47.115 20.412 47.385 ;
     RECT  119.34 47.115 140.4 47.385 ;
     RECT  2.16 47.655 20.412 47.925 ;
     RECT  119.34 47.655 140.4 47.925 ;
     RECT  2.16 48.195 20.412 48.465 ;
     RECT  119.34 48.195 140.4 48.465 ;
     RECT  2.16 48.735 20.412 49.005 ;
     RECT  119.34 48.735 140.4 49.005 ;
     RECT  2.16 49.275 20.412 49.545 ;
     RECT  119.34 49.275 140.4 49.545 ;
     RECT  2.16 49.815 20.412 50.085 ;
     RECT  119.34 49.815 140.4 50.085 ;
     RECT  2.16 50.355 20.412 50.625 ;
     RECT  119.34 50.355 140.4 50.625 ;
     RECT  2.16 50.895 20.412 51.165 ;
     RECT  119.34 50.895 140.4 51.165 ;
     RECT  2.16 51.435 20.412 51.705 ;
     RECT  119.34 51.435 140.4 51.705 ;
     RECT  2.16 51.975 20.412 52.245 ;
     RECT  119.34 51.975 140.4 52.245 ;
     RECT  2.16 52.515 20.412 52.785 ;
     RECT  119.34 52.515 140.4 52.785 ;
     RECT  2.16 53.055 20.412 53.325 ;
     RECT  119.34 53.055 140.4 53.325 ;
     RECT  2.16 53.595 20.412 53.865 ;
     RECT  119.34 53.595 140.4 53.865 ;
     RECT  2.16 54.135 20.412 54.405 ;
     RECT  119.34 54.135 140.4 54.405 ;
     RECT  2.16 54.675 20.412 54.945 ;
     RECT  119.34 54.675 140.4 54.945 ;
     RECT  2.16 55.215 20.412 55.485 ;
     RECT  119.34 55.215 140.4 55.485 ;
     RECT  2.16 55.755 20.412 56.025 ;
     RECT  119.34 55.755 140.4 56.025 ;
     RECT  2.16 56.295 20.412 56.565 ;
     RECT  119.34 56.295 140.4 56.565 ;
     RECT  2.16 56.835 20.412 57.105 ;
     RECT  119.34 56.835 140.4 57.105 ;
     RECT  2.16 57.375 20.412 57.645 ;
     RECT  119.34 57.375 140.4 57.645 ;
     RECT  2.16 57.915 20.412 58.185 ;
     RECT  119.34 57.915 140.4 58.185 ;
     RECT  2.16 58.455 20.412 58.725 ;
     RECT  119.34 58.455 140.4 58.725 ;
     RECT  2.16 58.995 20.412 59.265 ;
     RECT  119.34 58.995 140.4 59.265 ;
     RECT  2.16 59.535 20.412 59.805 ;
     RECT  119.34 59.535 140.4 59.805 ;
     RECT  2.16 60.075 20.412 60.345 ;
     RECT  119.34 60.075 140.4 60.345 ;
     RECT  2.16 60.615 20.412 60.885 ;
     RECT  119.34 60.615 140.4 60.885 ;
     RECT  2.16 61.155 20.412 61.425 ;
     RECT  119.34 61.155 140.4 61.425 ;
     RECT  2.16 61.695 20.412 61.965 ;
     RECT  119.34 61.695 140.4 61.965 ;
     RECT  2.16 62.235 20.412 62.505 ;
     RECT  119.34 62.235 140.4 62.505 ;
     RECT  2.16 62.775 20.412 63.045 ;
     RECT  119.34 62.775 140.4 63.045 ;
     RECT  2.16 63.315 20.412 63.585 ;
     RECT  119.34 63.315 140.4 63.585 ;
     RECT  2.16 63.855 20.412 64.125 ;
     RECT  119.34 63.855 140.4 64.125 ;
     RECT  2.16 64.395 20.412 64.665 ;
     RECT  119.34 64.395 140.4 64.665 ;
     RECT  2.16 64.935 20.412 65.205 ;
     RECT  119.34 64.935 140.4 65.205 ;
     RECT  2.16 65.475 20.412 65.61 ;
     RECT  119.34 65.475 140.4 65.61 ;
     RECT  2.16 65.61 140.4 65.745 ;
     RECT  2.16 66.015 140.4 66.285 ;
     RECT  2.16 66.555 140.4 66.825 ;
     RECT  2.16 67.095 140.4 67.365 ;
     RECT  2.16 67.635 140.4 67.905 ;
     RECT  2.16 68.175 140.4 68.445 ;
     RECT  2.16 68.715 140.4 68.985 ;
     RECT  2.16 69.255 140.4 69.525 ;
     RECT  2.16 69.795 140.4 70.065 ;
     RECT  2.16 70.335 140.4 70.605 ;
     RECT  2.16 70.875 140.4 71.145 ;
     RECT  2.16 71.415 140.4 71.685 ;
     RECT  2.16 71.955 140.4 72.225 ;
     RECT  2.16 72.495 140.4 72.765 ;
     RECT  2.16 73.035 140.4 73.305 ;
     RECT  2.16 73.575 140.4 73.845 ;
     RECT  2.16 74.115 140.4 74.385 ;
     RECT  2.16 74.655 140.4 74.925 ;
     RECT  2.16 75.195 140.4 75.465 ;
     RECT  2.16 75.735 140.4 76.005 ;
     RECT  2.16 76.275 140.4 76.545 ;
     RECT  2.16 76.815 140.4 77.085 ;
     RECT  2.16 77.355 140.4 77.625 ;
     RECT  2.16 77.895 140.4 78.165 ;
     RECT  2.16 78.435 140.4 78.705 ;
     RECT  2.16 78.975 140.4 79.245 ;
     RECT  2.16 79.515 140.4 79.785 ;
     RECT  2.16 80.055 140.4 80.325 ;
     RECT  2.16 80.595 140.4 80.865 ;
     RECT  2.16 81.135 140.4 81.405 ;
     RECT  2.16 81.675 140.4 81.945 ;
     RECT  2.16 82.215 140.4 82.485 ;
     RECT  2.16 82.755 140.4 83.025 ;
     RECT  2.16 83.295 140.4 83.565 ;
     RECT  2.16 83.835 140.4 84.105 ;
    LAYER M1 ;
     RECT  2.16 2.151 140.4 20.259 ;
     RECT  22.464 22.464 117.288 63.528 ;
     RECT  2.16 20.259 20.412 65.601 ;
     RECT  119.34 20.259 140.4 65.601 ;
     RECT  2.16 65.601 140.4 84.249 ;
    LAYER M2 ;
     RECT  0.211 5.04 2.16 5.058 ;
     RECT  0.211 6.552 2.16 6.57 ;
     RECT  0.211 8.172 2.16 8.19 ;
     RECT  0.211 9.558 2.16 9.576 ;
     RECT  0.211 11.142 2.16 11.16 ;
     RECT  1.723 12.492 2.16 12.51 ;
     RECT  0.211 15.57 2.16 15.588 ;
     RECT  0.211 17.082 2.16 17.1 ;
     RECT  0.211 18.702 2.16 18.72 ;
     RECT  0.211 20.052 2.16 20.07 ;
     RECT  0.211 21.51 2.16 21.528 ;
     RECT  0.211 23.058 2.16 23.076 ;
     RECT  0.211 26.028 2.16 26.046 ;
     RECT  1.723 27.342 2.16 27.36 ;
     RECT  0.211 28.962 2.16 28.98 ;
     RECT  0.535 32.004 2.16 32.022 ;
     RECT  0.211 33.552 2.16 33.57 ;
     RECT  0.211 36.522 2.16 36.54 ;
     RECT  0.211 38.142 2.16 38.16 ;
     RECT  0.211 39.762 2.16 39.78 ;
     RECT  0.211 40.95 2.16 40.968 ;
     RECT  0.211 44.082 2.16 44.1 ;
     RECT  0.211 57.42 2.16 57.438 ;
     RECT  0.211 58.932 2.16 58.95 ;
     RECT  0.211 61.902 2.16 61.92 ;
     RECT  0.211 64.908 2.16 64.926 ;
     RECT  0.211 66.33 2.16 66.348 ;
     RECT  0.211 67.842 2.16 67.86 ;
     RECT  1.723 79.758 2.16 79.776 ;
     RECT  0.211 81.378 2.16 81.396 ;
     RECT  2.16 2.151 11.047 84.249 ;
     RECT  11.047 1.728 11.255 84.249 ;
     RECT  13.171 0.144 13.343 0.162 ;
     RECT  11.255 2.151 20.412 84.249 ;
     RECT  20.412 22.824 20.435 22.914 ;
     RECT  20.412 25.326 20.435 25.848 ;
     RECT  20.435 25.326 20.543 25.74 ;
     RECT  20.435 22.824 20.615 22.842 ;
     RECT  20.543 25.722 20.615 25.74 ;
     RECT  20.412 36.216 20.723 36.234 ;
     RECT  20.412 32.778 20.759 33.912 ;
     RECT  20.412 35.136 20.795 35.19 ;
     RECT  20.412 53.028 20.795 53.046 ;
     RECT  20.412 51.606 20.939 51.624 ;
     RECT  20.412 57.186 21.011 57.204 ;
     RECT  20.412 61.236 21.011 61.254 ;
     RECT  20.412 62.712 21.011 62.73 ;
     RECT  20.412 37.566 21.263 37.584 ;
     RECT  20.759 32.778 21.335 33.534 ;
     RECT  21.235 35.901 21.335 35.919 ;
     RECT  21.199 27.261 21.371 27.279 ;
     RECT  20.412 28.764 21.659 28.782 ;
     RECT  22.135 55.494 22.171 55.512 ;
     RECT  20.412 2.151 22.464 21.96 ;
     RECT  21.703 24.876 22.464 24.894 ;
     RECT  21.335 33.516 22.464 33.534 ;
     RECT  20.795 35.136 22.464 35.154 ;
     RECT  20.412 41.526 22.464 41.544 ;
     RECT  20.412 47.826 22.464 47.844 ;
     RECT  20.412 48.978 22.464 48.996 ;
     RECT  22.171 55.494 22.464 55.71 ;
     RECT  22.063 56.466 22.464 56.484 ;
     RECT  20.412 63.594 22.464 84.249 ;
     RECT  22.464 2.151 23.459 84.249 ;
     RECT  23.459 2.151 24.367 64.728 ;
     RECT  24.367 2.106 25.663 64.728 ;
     RECT  28.543 0.486 28.687 0.504 ;
     RECT  23.459 65.601 29.695 84.249 ;
     RECT  29.695 65.601 29.867 84.294 ;
     RECT  25.663 1.881 30.379 64.728 ;
     RECT  30.379 1.764 30.631 64.728 ;
     RECT  28.687 0.378 30.739 0.504 ;
     RECT  30.739 0.378 31.279 0.9 ;
     RECT  30.631 1.692 31.279 64.728 ;
     RECT  31.279 0.378 32.639 64.728 ;
     RECT  32.639 0.378 35.519 21.384 ;
     RECT  35.519 21.366 36.563 21.384 ;
     RECT  32.639 22.464 37.859 64.728 ;
     RECT  35.519 0.378 41.287 20.259 ;
     RECT  37.859 22.464 42.935 64.692 ;
     RECT  42.935 22.464 47.507 64.116 ;
     RECT  41.287 0.342 50.899 20.259 ;
     RECT  50.899 0.144 51.035 20.259 ;
     RECT  51.655 86.238 51.755 86.256 ;
     RECT  65.263 86.238 65.399 86.256 ;
     RECT  51.035 0.342 70.807 20.259 ;
     RECT  70.807 0.144 71.411 20.259 ;
     RECT  71.411 0.342 75.055 20.259 ;
     RECT  75.055 0.144 75.155 20.259 ;
     RECT  75.155 0.342 77.143 20.259 ;
     RECT  77.143 0.144 77.243 20.259 ;
     RECT  77.243 0.342 80.203 20.259 ;
     RECT  80.203 0.144 80.303 20.259 ;
     RECT  80.959 86.238 81.095 86.256 ;
     RECT  80.303 0.342 82.831 20.259 ;
     RECT  82.831 0.144 83.471 20.259 ;
     RECT  91.399 86.238 91.499 86.256 ;
     RECT  93.487 86.238 93.983 86.256 ;
     RECT  83.471 0.342 96.511 20.259 ;
     RECT  96.511 0.144 96.611 20.259 ;
     RECT  96.611 0.342 97.007 20.259 ;
     RECT  97.007 0.414 98.699 20.259 ;
     RECT  98.699 0.846 99.571 20.259 ;
     RECT  99.571 0.144 99.671 20.259 ;
     RECT  29.867 65.601 101.479 84.249 ;
     RECT  101.479 65.601 101.903 84.294 ;
     RECT  99.671 0.846 103.379 20.259 ;
     RECT  103.747 0.144 103.847 0.162 ;
     RECT  104.935 86.238 105.035 86.256 ;
     RECT  103.379 1.494 105.755 20.259 ;
     RECT  105.907 0.144 106.007 0.162 ;
     RECT  105.755 1.836 106.727 20.259 ;
     RECT  106.727 1.998 108.031 20.259 ;
     RECT  108.031 1.728 108.167 20.259 ;
     RECT  108.167 1.998 110.623 20.259 ;
     RECT  110.623 1.728 110.759 20.259 ;
     RECT  101.903 65.601 111.271 84.249 ;
     RECT  111.271 65.601 111.371 84.474 ;
     RECT  112.315 86.238 112.415 86.256 ;
     RECT  47.507 22.464 113.035 63.528 ;
     RECT  110.759 1.998 113.819 20.259 ;
     RECT  113.819 2.07 115.339 20.259 ;
     RECT  115.339 1.728 115.511 20.259 ;
     RECT  115.879 0.144 115.979 0.162 ;
     RECT  108.391 21.366 116.743 21.384 ;
     RECT  113.035 22.401 117.288 63.528 ;
     RECT  117.288 52.056 117.419 57.744 ;
     RECT  117.288 30.312 117.455 30.636 ;
     RECT  116.743 21.096 117.527 21.384 ;
     RECT  117.288 34.164 117.527 34.794 ;
     RECT  117.288 62.676 117.679 63.528 ;
     RECT  117.288 23.292 118.031 23.31 ;
     RECT  117.288 42.066 118.039 42.354 ;
     RECT  117.288 50.832 118.039 51.192 ;
     RECT  117.288 58.626 118.039 59.634 ;
     RECT  117.288 22.401 118.067 22.419 ;
     RECT  117.288 44.892 118.075 44.91 ;
     RECT  117.288 45.81 118.075 46.368 ;
     RECT  117.288 49.896 118.075 50.004 ;
     RECT  118.039 50.751 118.075 51.192 ;
     RECT  118.075 49.896 118.111 51.192 ;
     RECT  117.288 33.048 118.255 33.066 ;
     RECT  118.111 49.896 118.255 51.228 ;
     RECT  117.419 52.056 118.255 54.774 ;
     RECT  117.288 35.856 118.291 36.612 ;
     RECT  117.288 40.176 118.399 41.13 ;
     RECT  118.039 42.066 118.399 42.444 ;
     RECT  118.399 40.14 118.435 41.13 ;
     RECT  117.288 38.286 118.507 38.736 ;
     RECT  117.288 43.506 118.543 43.632 ;
     RECT  117.527 34.164 118.579 34.65 ;
     RECT  118.507 38.142 118.579 38.736 ;
     RECT  118.435 40.104 118.579 41.13 ;
     RECT  118.399 42.03 118.579 42.444 ;
     RECT  118.543 43.308 118.579 43.632 ;
     RECT  117.288 48.276 118.579 48.762 ;
     RECT  118.255 49.896 118.579 54.774 ;
     RECT  117.419 55.53 118.579 57.744 ;
     RECT  118.039 58.626 118.579 59.724 ;
     RECT  117.679 62.676 118.579 63.81 ;
     RECT  118.651 22.131 118.831 22.149 ;
     RECT  118.291 35.442 118.867 36.612 ;
     RECT  118.867 35.406 118.903 36.612 ;
     RECT  118.903 35.406 119.047 36.954 ;
     RECT  117.288 60.966 119.047 61.722 ;
     RECT  118.579 47.592 119.083 48.762 ;
     RECT  118.579 38.142 119.119 43.632 ;
     RECT  118.075 44.892 119.119 46.368 ;
     RECT  119.119 44.892 119.155 46.53 ;
     RECT  119.083 47.592 119.155 48.924 ;
     RECT  118.579 49.896 119.155 59.724 ;
     RECT  119.119 38.016 119.335 43.632 ;
     RECT  115.511 2.07 119.34 20.259 ;
     RECT  117.527 21.366 119.34 21.384 ;
     RECT  118.831 22.131 119.34 22.23 ;
     RECT  118.255 33.012 119.34 33.066 ;
     RECT  118.579 34.092 119.34 34.65 ;
     RECT  119.047 35.406 119.34 37.044 ;
     RECT  119.335 37.944 119.34 43.632 ;
     RECT  119.155 44.892 119.34 46.764 ;
     RECT  119.155 47.592 119.34 59.724 ;
     RECT  119.047 60.66 119.34 61.722 ;
     RECT  118.579 62.586 119.34 63.81 ;
     RECT  117.715 64.836 119.34 64.854 ;
     RECT  111.371 65.601 119.34 84.249 ;
     RECT  119.34 2.07 120.559 84.249 ;
     RECT  120.559 1.728 120.695 84.249 ;
     RECT  120.695 2.07 121.559 84.249 ;
     RECT  131.179 86.238 131.279 86.256 ;
     RECT  121.559 2.151 132.079 84.249 ;
     RECT  132.079 1.728 132.251 84.249 ;
     RECT  132.251 2.151 134.707 84.249 ;
     RECT  134.707 1.728 134.843 84.249 ;
     RECT  134.843 2.151 135.787 84.249 ;
     RECT  135.787 2.106 136.319 84.249 ;
     RECT  136.319 2.151 137.443 84.249 ;
     RECT  137.443 2.151 137.579 84.366 ;
     RECT  137.579 2.151 140.4 84.249 ;
    LAYER M3 ;
     RECT  4.446 0.108 4.968 0.144 ;
     RECT  4.986 0.108 5.472 0.144 ;
     RECT  5.49 0.108 6.012 0.144 ;
     RECT  6.03 0.108 6.552 0.144 ;
     RECT  6.57 0.108 7.056 0.144 ;
     RECT  7.074 0.108 7.596 0.144 ;
     RECT  7.614 0.108 8.1 0.144 ;
     RECT  8.118 0.108 8.64 0.144 ;
     RECT  8.658 0.108 9.144 0.144 ;
     RECT  9.162 0.108 9.684 0.144 ;
     RECT  9.702 0.108 10.188 0.144 ;
     RECT  10.206 0.108 10.728 0.144 ;
     RECT  10.746 0.108 11.232 0.144 ;
     RECT  11.25 0.108 11.772 0.144 ;
     RECT  11.79 0.108 12.276 0.144 ;
     RECT  12.294 0.108 12.816 0.144 ;
     RECT  12.834 0.108 13.32 0.144 ;
     RECT  13.338 0.108 13.86 0.144 ;
     RECT  13.878 0.108 14.364 0.144 ;
     RECT  14.382 0.108 14.904 0.144 ;
     RECT  14.922 0.108 15.444 0.144 ;
     RECT  15.462 0.108 15.948 0.144 ;
     RECT  15.966 0.108 16.488 0.144 ;
     RECT  16.506 0.108 16.992 0.144 ;
     RECT  17.01 0.108 17.532 0.144 ;
     RECT  17.55 0.108 18.036 0.144 ;
     RECT  18.054 0.108 18.576 0.144 ;
     RECT  18.594 0.108 19.08 0.144 ;
     RECT  19.098 0.108 19.62 0.144 ;
     RECT  19.638 0.108 20.124 0.144 ;
     RECT  20.142 0.108 20.664 0.144 ;
     RECT  20.682 0.108 21.168 0.144 ;
     RECT  21.186 0.108 21.708 0.144 ;
     RECT  21.726 0.108 22.212 0.144 ;
     RECT  22.23 0.108 22.752 0.144 ;
     RECT  22.77 0.108 23.292 0.144 ;
     RECT  23.31 0.108 23.796 0.144 ;
     RECT  23.814 0.108 24.336 0.144 ;
     RECT  24.354 0.108 24.84 0.144 ;
     RECT  24.858 0.108 25.38 0.144 ;
     RECT  25.398 0.108 25.884 0.144 ;
     RECT  25.902 0.108 26.424 0.144 ;
     RECT  26.442 0.108 26.928 0.144 ;
     RECT  26.946 0.108 27.468 0.144 ;
     RECT  27.486 0.108 27.972 0.144 ;
     RECT  27.99 0.108 28.512 0.144 ;
     RECT  28.53 0.108 29.016 0.144 ;
     RECT  29.034 0.108 29.556 0.144 ;
     RECT  29.574 0.108 30.06 0.144 ;
     RECT  30.078 0.108 30.6 0.144 ;
     RECT  30.618 0.108 31.104 0.144 ;
     RECT  31.122 0.108 31.644 0.144 ;
     RECT  31.662 0.108 32.184 0.144 ;
     RECT  32.202 0.108 32.688 0.144 ;
     RECT  32.706 0.108 33.228 0.144 ;
     RECT  33.246 0.108 33.732 0.144 ;
     RECT  33.75 0.108 34.272 0.144 ;
     RECT  34.29 0.108 34.776 0.144 ;
     RECT  34.794 0.108 35.316 0.144 ;
     RECT  35.334 0.108 35.82 0.144 ;
     RECT  35.838 0.108 36.36 0.144 ;
     RECT  36.378 0.108 36.864 0.144 ;
     RECT  36.882 0.108 37.404 0.144 ;
     RECT  37.422 0.108 37.908 0.144 ;
     RECT  37.926 0.108 38.448 0.144 ;
     RECT  38.466 0.108 38.952 0.144 ;
     RECT  38.97 0.108 39.492 0.144 ;
     RECT  39.51 0.108 40.032 0.144 ;
     RECT  40.05 0.108 40.536 0.144 ;
     RECT  40.554 0.108 41.076 0.144 ;
     RECT  41.094 0.108 41.58 0.144 ;
     RECT  41.598 0.108 42.12 0.144 ;
     RECT  42.138 0.108 42.624 0.144 ;
     RECT  42.642 0.108 43.164 0.144 ;
     RECT  43.182 0.108 43.668 0.144 ;
     RECT  43.686 0.108 44.208 0.144 ;
     RECT  44.226 0.108 44.712 0.144 ;
     RECT  44.73 0.108 45.252 0.144 ;
     RECT  45.27 0.108 45.756 0.144 ;
     RECT  45.774 0.108 46.296 0.144 ;
     RECT  46.314 0.108 46.8 0.144 ;
     RECT  46.818 0.108 47.34 0.144 ;
     RECT  47.358 0.108 47.844 0.144 ;
     RECT  47.862 0.108 48.384 0.144 ;
     RECT  48.402 0.108 48.924 0.144 ;
     RECT  48.942 0.108 49.428 0.144 ;
     RECT  49.446 0.108 49.968 0.144 ;
     RECT  49.986 0.108 50.472 0.144 ;
     RECT  50.49 0.108 51.012 0.144 ;
     RECT  51.03 0.108 51.516 0.144 ;
     RECT  51.534 0.108 52.056 0.144 ;
     RECT  52.074 0.108 52.56 0.144 ;
     RECT  52.578 0.108 53.1 0.144 ;
     RECT  53.118 0.108 53.604 0.144 ;
     RECT  53.622 0.108 54.144 0.144 ;
     RECT  54.162 0.108 54.648 0.144 ;
     RECT  54.666 0.108 55.188 0.144 ;
     RECT  55.206 0.108 55.692 0.144 ;
     RECT  55.71 0.108 56.232 0.144 ;
     RECT  56.25 0.108 56.772 0.144 ;
     RECT  56.79 0.108 57.276 0.144 ;
     RECT  57.294 0.108 57.816 0.144 ;
     RECT  57.834 0.108 58.32 0.144 ;
     RECT  58.338 0.108 58.86 0.144 ;
     RECT  58.878 0.108 59.364 0.144 ;
     RECT  59.382 0.108 59.904 0.144 ;
     RECT  59.922 0.108 60.408 0.144 ;
     RECT  60.426 0.108 60.948 0.144 ;
     RECT  60.966 0.108 61.452 0.144 ;
     RECT  61.47 0.108 61.992 0.144 ;
     RECT  62.01 0.108 62.496 0.144 ;
     RECT  62.514 0.108 63.036 0.144 ;
     RECT  63.054 0.108 63.54 0.144 ;
     RECT  63.558 0.108 64.08 0.144 ;
     RECT  64.098 0.108 64.584 0.144 ;
     RECT  64.602 0.108 65.124 0.144 ;
     RECT  65.142 0.108 65.664 0.144 ;
     RECT  65.682 0.108 66.168 0.144 ;
     RECT  66.186 0.108 66.708 0.144 ;
     RECT  66.726 0.108 67.212 0.144 ;
     RECT  67.23 0.108 67.752 0.144 ;
     RECT  67.77 0.108 68.256 0.144 ;
     RECT  68.274 0.108 68.796 0.144 ;
     RECT  68.814 0.108 69.3 0.144 ;
     RECT  69.318 0.108 69.84 0.144 ;
     RECT  69.858 0.108 70.344 0.144 ;
     RECT  70.362 0.108 70.884 0.144 ;
     RECT  70.902 0.108 71.388 0.144 ;
     RECT  71.406 0.108 71.928 0.144 ;
     RECT  71.946 0.108 72.432 0.144 ;
     RECT  72.45 0.108 72.972 0.144 ;
     RECT  72.99 0.108 73.512 0.144 ;
     RECT  73.53 0.108 74.016 0.144 ;
     RECT  74.034 0.108 74.556 0.144 ;
     RECT  74.574 0.108 75.06 0.144 ;
     RECT  75.078 0.108 75.6 0.144 ;
     RECT  75.618 0.108 76.104 0.144 ;
     RECT  76.122 0.108 76.644 0.144 ;
     RECT  76.662 0.108 77.148 0.144 ;
     RECT  77.166 0.108 77.688 0.144 ;
     RECT  77.706 0.108 78.192 0.144 ;
     RECT  78.21 0.108 78.732 0.144 ;
     RECT  78.75 0.108 79.236 0.144 ;
     RECT  79.254 0.108 79.776 0.144 ;
     RECT  79.794 0.108 80.28 0.144 ;
     RECT  80.298 0.108 80.82 0.144 ;
     RECT  80.838 0.108 81.324 0.144 ;
     RECT  81.342 0.108 81.864 0.144 ;
     RECT  81.882 0.108 82.404 0.144 ;
     RECT  82.422 0.108 82.908 0.144 ;
     RECT  82.926 0.108 83.448 0.144 ;
     RECT  83.466 0.108 83.952 0.144 ;
     RECT  83.97 0.108 84.492 0.144 ;
     RECT  84.51 0.108 84.996 0.144 ;
     RECT  85.014 0.108 85.536 0.144 ;
     RECT  85.554 0.108 86.04 0.144 ;
     RECT  86.058 0.108 86.58 0.144 ;
     RECT  86.598 0.108 87.084 0.144 ;
     RECT  87.102 0.108 87.624 0.144 ;
     RECT  87.642 0.108 88.128 0.144 ;
     RECT  88.146 0.108 88.668 0.144 ;
     RECT  88.686 0.108 89.172 0.144 ;
     RECT  89.19 0.108 89.712 0.144 ;
     RECT  89.73 0.108 90.252 0.144 ;
     RECT  90.27 0.108 90.756 0.144 ;
     RECT  90.774 0.108 91.296 0.144 ;
     RECT  91.314 0.108 91.8 0.144 ;
     RECT  91.818 0.108 92.34 0.144 ;
     RECT  92.358 0.108 92.844 0.144 ;
     RECT  92.862 0.108 93.384 0.144 ;
     RECT  93.402 0.108 93.888 0.144 ;
     RECT  93.906 0.108 94.428 0.144 ;
     RECT  94.446 0.108 94.932 0.144 ;
     RECT  94.95 0.108 95.472 0.144 ;
     RECT  95.49 0.108 95.976 0.144 ;
     RECT  95.994 0.108 96.516 0.144 ;
     RECT  96.534 0.108 97.02 0.144 ;
     RECT  97.038 0.108 97.56 0.144 ;
     RECT  97.578 0.108 98.064 0.144 ;
     RECT  98.082 0.108 98.604 0.144 ;
     RECT  98.622 0.108 99.144 0.144 ;
     RECT  99.162 0.108 99.648 0.144 ;
     RECT  99.666 0.108 100.188 0.144 ;
     RECT  100.206 0.108 100.692 0.144 ;
     RECT  100.71 0.108 101.232 0.144 ;
     RECT  101.25 0.108 101.736 0.144 ;
     RECT  101.754 0.108 102.276 0.144 ;
     RECT  102.294 0.108 102.78 0.144 ;
     RECT  102.798 0.108 103.32 0.144 ;
     RECT  103.338 0.108 103.824 0.144 ;
     RECT  103.842 0.108 104.364 0.144 ;
     RECT  104.382 0.108 104.868 0.144 ;
     RECT  104.886 0.108 105.408 0.144 ;
     RECT  105.426 0.108 105.912 0.144 ;
     RECT  105.93 0.108 106.452 0.144 ;
     RECT  106.47 0.108 106.992 0.144 ;
     RECT  107.01 0.108 107.496 0.144 ;
     RECT  107.514 0.108 108.036 0.144 ;
     RECT  108.054 0.108 108.54 0.144 ;
     RECT  108.558 0.108 109.08 0.144 ;
     RECT  109.098 0.108 109.584 0.144 ;
     RECT  109.602 0.108 110.124 0.144 ;
     RECT  110.142 0.108 110.628 0.144 ;
     RECT  110.646 0.108 111.168 0.144 ;
     RECT  111.186 0.108 111.672 0.144 ;
     RECT  111.69 0.108 112.212 0.144 ;
     RECT  112.23 0.108 112.716 0.144 ;
     RECT  112.734 0.108 113.256 0.144 ;
     RECT  113.274 0.108 113.76 0.144 ;
     RECT  113.778 0.108 114.3 0.144 ;
     RECT  114.318 0.108 114.804 0.144 ;
     RECT  114.822 0.108 115.344 0.144 ;
     RECT  115.362 0.108 115.884 0.144 ;
     RECT  115.902 0.108 116.388 0.144 ;
     RECT  116.406 0.108 116.928 0.144 ;
     RECT  116.946 0.108 117.432 0.144 ;
     RECT  117.45 0.108 117.972 0.144 ;
     RECT  117.99 0.108 118.476 0.144 ;
     RECT  118.494 0.108 119.016 0.144 ;
     RECT  119.034 0.108 119.52 0.144 ;
     RECT  119.538 0.108 120.06 0.144 ;
     RECT  120.078 0.108 120.564 0.144 ;
     RECT  120.582 0.108 121.104 0.144 ;
     RECT  121.122 0.108 121.608 0.144 ;
     RECT  121.626 0.108 122.148 0.144 ;
     RECT  122.166 0.108 122.652 0.144 ;
     RECT  122.67 0.108 123.192 0.144 ;
     RECT  123.21 0.108 123.732 0.144 ;
     RECT  123.75 0.108 124.236 0.144 ;
     RECT  124.254 0.108 124.776 0.144 ;
     RECT  124.794 0.108 125.28 0.144 ;
     RECT  125.298 0.108 125.82 0.144 ;
     RECT  125.838 0.108 126.324 0.144 ;
     RECT  126.342 0.108 126.864 0.144 ;
     RECT  126.882 0.108 127.368 0.144 ;
     RECT  127.386 0.108 127.908 0.144 ;
     RECT  127.926 0.108 128.412 0.144 ;
     RECT  128.43 0.108 128.952 0.144 ;
     RECT  128.97 0.108 129.456 0.144 ;
     RECT  129.474 0.108 129.996 0.144 ;
     RECT  130.014 0.108 130.5 0.144 ;
     RECT  130.518 0.108 131.04 0.144 ;
     RECT  131.058 0.108 131.544 0.144 ;
     RECT  131.562 0.108 132.084 0.144 ;
     RECT  132.102 0.108 132.624 0.144 ;
     RECT  132.642 0.108 133.128 0.144 ;
     RECT  133.146 0.108 133.668 0.144 ;
     RECT  133.686 0.108 134.172 0.144 ;
     RECT  134.19 0.108 134.712 0.144 ;
     RECT  134.73 0.108 135.216 0.144 ;
     RECT  135.234 0.108 135.756 0.144 ;
     RECT  135.774 0.108 136.26 0.144 ;
     RECT  136.278 0.108 136.8 0.144 ;
     RECT  136.818 0.108 137.304 0.144 ;
     RECT  137.322 0.108 137.844 0.144 ;
     RECT  4.428 0.144 137.862 0.167 ;
     RECT  4.428 0.167 70.902 1.147 ;
     RECT  71.928 0.167 137.862 1.723 ;
     RECT  4.428 1.147 71.154 1.867 ;
     RECT  71.928 1.723 138.294 1.867 ;
     RECT  4.428 1.867 138.294 2.291 ;
     RECT  4.824 2.291 138.294 2.371 ;
     RECT  2.415 2.143 2.505 2.413 ;
     RECT  4.824 2.371 138.33 2.641 ;
     RECT  4.824 2.641 138.51 3.415 ;
     RECT  4.788 3.415 138.51 3.721 ;
     RECT  4.788 3.721 138.69 3.839 ;
     RECT  4.788 3.839 38.538 3.965 ;
     RECT  39.276 3.839 138.69 4.019 ;
     RECT  39.276 4.019 138.546 4.379 ;
     RECT  39.276 4.379 137.697 4.415 ;
     RECT  88.344 4.415 137.697 4.451 ;
     RECT  88.344 4.451 97.29 4.559 ;
     RECT  9.108 3.965 38.538 4.693 ;
     RECT  39.276 4.415 87.462 4.693 ;
     RECT  5.148 3.965 8.154 4.729 ;
     RECT  88.344 4.559 97.218 4.757 ;
     RECT  2.415 2.413 2.697 4.765 ;
     RECT  9.108 4.693 87.462 4.793 ;
     RECT  98.064 4.451 137.697 4.793 ;
     RECT  2.376 4.765 2.697 4.801 ;
     RECT  5.148 4.729 8.298 4.829 ;
     RECT  136.8 4.793 137.697 4.829 ;
     RECT  5.148 4.829 8.226 4.919 ;
     RECT  9.684 4.793 83.898 4.955 ;
     RECT  9.684 4.955 57.582 4.991 ;
     RECT  58.32 4.955 83.898 5.027 ;
     RECT  98.064 4.793 135.702 5.063 ;
     RECT  5.148 4.919 7.002 5.099 ;
     RECT  10.98 4.991 57.582 5.099 ;
     RECT  0.216 5.035 0.234 5.117 ;
     RECT  58.392 5.027 83.898 5.117 ;
     RECT  5.724 5.099 7.002 5.189 ;
     RECT  65.232 5.117 73.638 5.189 ;
     RECT  74.664 5.117 83.898 5.189 ;
     RECT  11.088 5.099 57.582 5.261 ;
     RECT  74.664 5.189 76.41 5.297 ;
     RECT  77.544 5.189 83.898 5.297 ;
     RECT  138.528 4.379 138.546 5.297 ;
     RECT  58.392 5.117 64.494 5.333 ;
     RECT  99.468 5.063 135.702 5.333 ;
     RECT  2.304 4.801 2.697 5.341 ;
     RECT  65.52 5.189 73.638 5.357 ;
     RECT  59.94 5.333 64.494 5.459 ;
     RECT  74.664 5.297 75.474 5.459 ;
     RECT  74.664 5.459 75.402 5.495 ;
     RECT  60.048 5.459 64.494 5.597 ;
     RECT  11.088 5.261 57.402 5.603 ;
     RECT  65.52 5.357 71.55 5.639 ;
     RECT  60.048 5.597 62.19 5.645 ;
     RECT  9.684 4.991 10.242 5.729 ;
     RECT  98.064 5.063 98.73 5.755 ;
     RECT  2.304 5.341 2.97 5.765 ;
     RECT  43.596 5.603 57.402 5.765 ;
     RECT  72.396 5.357 73.638 5.801 ;
     RECT  135.54 5.333 135.702 5.801 ;
     RECT  43.596 5.765 53.19 5.837 ;
     RECT  62.964 5.597 64.494 5.837 ;
     RECT  65.808 5.639 71.55 5.837 ;
     RECT  77.544 5.297 81.558 5.837 ;
     RECT  2.415 5.765 2.97 5.881 ;
     RECT  11.088 5.603 42.822 5.881 ;
     RECT  76.392 5.297 76.41 5.909 ;
     RECT  99.468 5.333 134.55 5.909 ;
     RECT  98.028 5.755 98.73 5.999 ;
     RECT  10.98 5.881 42.822 6.007 ;
     RECT  88.38 4.757 97.218 6.007 ;
     RECT  98.028 5.999 98.622 6.007 ;
     RECT  60.048 5.645 62.097 6.029 ;
     RECT  5.76 5.189 7.002 6.071 ;
     RECT  72.468 5.801 73.638 6.071 ;
     RECT  99.468 5.909 132.786 6.071 ;
     RECT  88.38 6.007 98.622 6.077 ;
     RECT  7.815 4.919 8.226 6.107 ;
     RECT  9.684 5.729 10.17 6.143 ;
     RECT  10.908 6.007 42.822 6.143 ;
     RECT  127.8 6.071 132.786 6.143 ;
     RECT  9.684 6.143 10.098 6.151 ;
     RECT  99.468 6.071 127.062 6.151 ;
     RECT  44.784 5.837 53.19 6.173 ;
     RECT  44.784 6.173 52.326 6.179 ;
     RECT  65.808 5.837 71.514 6.179 ;
     RECT  133.596 5.909 134.55 6.179 ;
     RECT  9.54 6.151 10.098 6.269 ;
     RECT  10.908 6.143 42.786 6.269 ;
     RECT  60.048 6.029 60.066 6.269 ;
     RECT  58.392 5.333 58.986 6.305 ;
     RECT  63.684 5.837 64.494 6.341 ;
     RECT  99.36 6.151 127.062 6.341 ;
     RECT  127.8 6.143 132.57 6.341 ;
     RECT  99.468 6.341 127.062 6.365 ;
     RECT  53.172 6.173 53.19 6.413 ;
     RECT  133.596 6.179 133.974 6.413 ;
     RECT  2.415 5.881 3.222 6.421 ;
     RECT  135.54 5.801 135.558 6.449 ;
     RECT  48.24 6.179 52.326 6.461 ;
     RECT  72.504 6.071 73.638 6.461 ;
     RECT  76.536 6.421 76.554 6.511 ;
     RECT  64.476 6.341 64.494 6.539 ;
     RECT  76.536 6.511 76.734 6.539 ;
     RECT  99.504 6.365 127.062 6.575 ;
     RECT  0.216 6.547 0.234 6.605 ;
     RECT  63.684 6.341 63.702 6.605 ;
     RECT  60.984 6.029 62.097 6.611 ;
     RECT  88.38 6.077 97.218 6.611 ;
     RECT  98.064 6.077 98.622 6.647 ;
     RECT  84.636 4.793 87.462 6.653 ;
     RECT  4.5 6.511 4.518 6.655 ;
     RECT  74.664 5.495 75.006 6.683 ;
     RECT  76.716 6.539 76.734 6.683 ;
     RECT  128.844 6.341 132.57 6.683 ;
     RECT  4.5 6.655 4.662 6.691 ;
     RECT  74.772 6.683 75.006 6.701 ;
     RECT  99.615 6.575 127.062 6.701 ;
     RECT  128.844 6.683 129.654 6.719 ;
     RECT  66.312 6.179 71.514 6.809 ;
     RECT  133.956 6.413 133.974 6.809 ;
     RECT  2.415 6.421 3.438 6.811 ;
     RECT  4.284 6.691 4.662 6.811 ;
     RECT  2.415 6.811 4.662 6.845 ;
     RECT  54.036 5.765 57.402 6.845 ;
     RECT  72.615 6.461 73.638 6.845 ;
     RECT  85.212 6.653 87.462 6.845 ;
     RECT  130.392 6.683 132.57 6.845 ;
     RECT  128.844 6.719 129.366 6.881 ;
     RECT  88.56 6.611 97.218 6.893 ;
     RECT  77.544 5.837 79.83 6.941 ;
     RECT  44.784 6.179 47.322 6.953 ;
     RECT  101.304 6.701 127.062 6.953 ;
     RECT  3.42 6.845 4.662 6.961 ;
     RECT  5.76 6.071 6.21 6.961 ;
     RECT  132.015 6.845 132.57 6.989 ;
     RECT  80.64 5.837 81.558 7.051 ;
     RECT  82.296 5.297 83.898 7.051 ;
     RECT  128.844 6.881 129.186 7.079 ;
     RECT  104.94 6.953 127.062 7.115 ;
     RECT  66.312 6.809 69.822 7.133 ;
     RECT  132.015 6.989 132.534 7.133 ;
     RECT  69.084 7.133 69.822 7.151 ;
     RECT  88.56 6.893 92.538 7.181 ;
     RECT  3.42 6.961 6.21 7.187 ;
     RECT  10.908 6.269 42.102 7.187 ;
     RECT  127.8 6.341 128.07 7.223 ;
     RECT  87.048 6.845 87.39 7.229 ;
     RECT  3.456 7.187 6.21 7.259 ;
     RECT  43.596 5.837 43.902 7.259 ;
     RECT  74.988 6.701 75.006 7.259 ;
     RECT  3.672 7.259 6.21 7.321 ;
     RECT  6.984 6.071 7.002 7.321 ;
     RECT  48.24 6.461 52.038 7.321 ;
     RECT  44.784 6.953 47.214 7.349 ;
     RECT  70.596 6.809 71.514 7.349 ;
     RECT  130.392 6.845 131.202 7.349 ;
     RECT  101.304 6.953 104.094 7.421 ;
     RECT  44.784 7.349 46.422 7.429 ;
     RECT  105.015 7.115 127.062 7.457 ;
     RECT  88.56 7.181 92.142 7.469 ;
     RECT  48.24 7.321 52.47 7.493 ;
     RECT  38.34 7.187 42.102 7.501 ;
     RECT  44.676 7.429 46.422 7.529 ;
     RECT  85.212 6.845 86.31 7.619 ;
     RECT  132.015 7.133 132.498 7.619 ;
     RECT  44.676 7.529 45.897 7.663 ;
     RECT  77.976 6.941 79.83 7.709 ;
     RECT  38.34 7.501 42.786 7.727 ;
     RECT  44.604 7.663 45.897 7.757 ;
     RECT  49.14 7.493 52.47 7.763 ;
     RECT  66.312 7.133 68.094 7.763 ;
     RECT  105.015 7.457 105.498 7.763 ;
     RECT  42.732 7.727 42.786 7.771 ;
     RECT  99.615 6.701 100.422 7.771 ;
     RECT  48.24 7.493 48.294 7.799 ;
     RECT  69.804 7.151 69.822 7.799 ;
     RECT  128.844 7.079 128.862 7.799 ;
     RECT  3.672 7.321 7.002 7.889 ;
     RECT  70.596 7.349 70.614 7.889 ;
     RECT  99.324 7.771 100.422 7.889 ;
     RECT  42.732 7.771 42.858 7.925 ;
     RECT  45 7.757 45.897 7.925 ;
     RECT  130.788 7.349 131.202 7.925 ;
     RECT  50.436 7.763 52.47 7.961 ;
     RECT  99.504 7.889 100.422 7.961 ;
     RECT  93.492 6.893 95.67 7.997 ;
     RECT  98.064 6.647 98.082 7.997 ;
     RECT  58.392 6.305 58.41 8.033 ;
     RECT  99.576 7.961 100.422 8.033 ;
     RECT  106.344 7.457 127.062 8.033 ;
     RECT  96.516 6.893 97.218 8.041 ;
     RECT  38.34 7.727 41.49 8.045 ;
     RECT  101.304 7.421 101.934 8.045 ;
     RECT  10.908 7.187 37.566 8.069 ;
     RECT  106.452 8.033 127.062 8.069 ;
     RECT  96.516 8.041 97.254 8.159 ;
     RECT  106.524 8.069 127.062 8.159 ;
     RECT  0.216 8.059 0.234 8.195 ;
     RECT  106.524 8.159 124.902 8.195 ;
     RECT  99.615 8.033 100.422 8.237 ;
     RECT  52.02 7.961 52.47 8.267 ;
     RECT  103.104 7.421 103.698 8.267 ;
     RECT  38.34 8.045 39.474 8.285 ;
     RECT  10.908 8.069 33.282 8.311 ;
     RECT  87.048 7.229 87.138 8.339 ;
     RECT  10.836 8.311 33.282 8.429 ;
     RECT  42.732 7.925 42.75 8.429 ;
     RECT  71.496 7.349 71.514 8.429 ;
     RECT  80.64 7.051 83.898 8.465 ;
     RECT  9.144 8.311 9.162 8.509 ;
     RECT  66.312 7.763 68.022 8.573 ;
     RECT  94.215 7.997 95.67 8.573 ;
     RECT  101.304 8.045 101.322 8.573 ;
     RECT  45.615 7.925 45.897 8.671 ;
     RECT  78.015 7.709 79.83 8.671 ;
     RECT  3.996 7.889 7.002 8.699 ;
     RECT  93.348 8.545 93.438 8.699 ;
     RECT  45.504 8.671 45.897 8.717 ;
     RECT  77.904 8.671 79.83 8.717 ;
     RECT  98.604 8.539 98.622 8.717 ;
     RECT  3.996 8.699 5.274 8.735 ;
     RECT  6.264 8.699 7.002 8.735 ;
     RECT  61.272 6.611 62.097 8.735 ;
     RECT  38.556 8.285 39.474 8.765 ;
     RECT  61.344 8.735 62.097 8.771 ;
     RECT  10.908 8.429 33.282 8.813 ;
     RECT  85.212 7.619 85.23 8.843 ;
     RECT  130.788 7.925 130.806 8.851 ;
     RECT  34.092 8.069 37.566 8.879 ;
     RECT  88.56 7.469 92.106 8.879 ;
     RECT  130.536 8.851 130.806 8.879 ;
     RECT  129.672 8.851 129.69 8.969 ;
     RECT  10.908 8.813 33.066 9.005 ;
     RECT  91.008 8.879 92.106 9.005 ;
     RECT  130.536 8.879 130.626 9.005 ;
     RECT  29.268 9.005 33.066 9.077 ;
     RECT  93.06 8.851 93.078 9.077 ;
     RECT  130.608 9.005 130.626 9.077 ;
     RECT  81.072 8.465 83.898 9.113 ;
     RECT  94.215 8.573 95.49 9.149 ;
     RECT  4.572 8.735 5.274 9.239 ;
     RECT  6.66 8.735 7.002 9.239 ;
     RECT  10.908 9.005 28.35 9.239 ;
     RECT  10.908 9.239 28.278 9.275 ;
     RECT  103.104 8.267 103.122 9.293 ;
     RECT  26.892 9.275 28.278 9.311 ;
     RECT  49.14 7.763 49.698 9.311 ;
     RECT  34.236 8.879 37.566 9.347 ;
     RECT  96.516 8.159 97.218 9.347 ;
     RECT  31.032 9.077 33.066 9.383 ;
     RECT  88.56 8.879 90.198 9.383 ;
     RECT  4.572 9.239 4.734 9.389 ;
     RECT  40.215 8.045 41.49 9.389 ;
     RECT  6.984 9.239 7.002 9.391 ;
     RECT  7.815 6.107 8.097 9.391 ;
     RECT  105.015 7.763 105.297 9.391 ;
     RECT  86.292 7.619 86.31 9.419 ;
     RECT  4.716 9.389 4.734 9.509 ;
     RECT  26.892 9.311 27.666 9.509 ;
     RECT  88.815 9.383 90.198 9.509 ;
     RECT  38.556 8.765 38.574 9.517 ;
     RECT  40.215 9.389 41.382 9.533 ;
     RECT  40.215 9.533 41.022 9.545 ;
     RECT  0.216 9.544 0.234 9.581 ;
     RECT  3.564 9.481 3.582 9.581 ;
     RECT  38.556 9.517 38.646 9.581 ;
     RECT  39.456 8.765 39.474 9.617 ;
     RECT  38.628 9.581 38.646 9.653 ;
     RECT  94.215 9.149 95.022 9.779 ;
     RECT  94.215 9.779 94.734 9.815 ;
     RECT  54.108 6.845 57.402 9.821 ;
     RECT  96.516 9.347 96.534 9.851 ;
     RECT  29.268 9.077 29.898 9.887 ;
     RECT  89.928 9.509 90.198 9.887 ;
     RECT  10.908 9.275 26.118 9.923 ;
     RECT  81.576 9.113 83.898 9.923 ;
     RECT  25.74 9.923 26.118 9.959 ;
     RECT  82.404 9.923 83.898 9.959 ;
     RECT  91.008 9.005 91.602 10.049 ;
     RECT  55.512 9.821 57.402 10.349 ;
     RECT  54.108 9.821 54.738 10.355 ;
     RECT  82.728 9.959 83.898 10.391 ;
     RECT  81.576 9.923 81.594 10.427 ;
     RECT  89.928 9.887 89.946 10.463 ;
     RECT  47.196 7.349 47.214 10.499 ;
     RECT  29.268 9.887 29.862 10.589 ;
     RECT  87.12 8.339 87.138 10.589 ;
     RECT  91.008 10.049 91.026 10.625 ;
     RECT  29.415 10.589 29.862 10.669 ;
     RECT  26.1 9.959 26.118 10.741 ;
     RECT  26.892 9.509 27.414 10.741 ;
     RECT  106.524 8.195 124.47 10.741 ;
     RECT  78.015 8.717 79.83 10.843 ;
     RECT  88.815 9.509 89.097 10.843 ;
     RECT  99.615 8.237 99.897 10.843 ;
     RECT  56.16 10.349 57.402 10.859 ;
     RECT  128.052 7.223 128.07 10.859 ;
     RECT  61.815 8.771 62.097 10.867 ;
     RECT  77.904 10.843 79.83 10.867 ;
     RECT  54.108 10.355 54.126 10.877 ;
     RECT  43.596 7.259 43.614 10.895 ;
     RECT  88.704 10.843 89.097 10.895 ;
     RECT  99.504 10.843 99.897 10.895 ;
     RECT  106.38 10.741 124.47 10.895 ;
     RECT  77.832 10.867 79.83 10.925 ;
     RECT  66.6 8.573 68.022 10.931 ;
     RECT  126.18 8.159 127.062 10.931 ;
     RECT  78.015 10.925 79.83 10.967 ;
     RECT  98.604 10.867 98.622 10.967 ;
     RECT  61.815 10.867 62.73 11.003 ;
     RECT  67.215 10.931 68.022 11.003 ;
     RECT  31.032 9.383 32.634 11.039 ;
     RECT  83.415 10.391 83.898 11.039 ;
     RECT  31.464 11.039 32.634 11.129 ;
     RECT  10.908 9.923 24.57 11.137 ;
     RECT  0.216 11.035 0.234 11.165 ;
     RECT  5.688 11.209 5.706 11.281 ;
     RECT  50.436 7.961 51.297 11.309 ;
     RECT  6.984 9.391 8.097 11.371 ;
     RECT  10.836 11.137 24.57 11.371 ;
     RECT  90.252 11.281 90.27 11.399 ;
     RECT  5.004 11.281 5.706 11.435 ;
     RECT  56.16 10.859 56.697 11.435 ;
     RECT  126.615 10.931 127.062 11.435 ;
     RECT  79.416 10.967 79.83 11.471 ;
     RECT  79.416 11.471 79.434 11.507 ;
     RECT  86.652 10.867 86.67 11.507 ;
     RECT  90.432 11.407 90.45 11.507 ;
     RECT  67.215 11.003 67.698 11.543 ;
     RECT  108.396 10.895 124.47 11.543 ;
     RECT  67.215 11.543 67.59 11.579 ;
     RECT  108.396 11.543 124.398 11.579 ;
     RECT  9.144 8.509 9.234 11.669 ;
     RECT  9.216 11.669 9.234 11.821 ;
     RECT  5.004 11.435 5.058 11.981 ;
     RECT  49.68 9.311 49.698 12.011 ;
     RECT  108.396 11.579 123.462 12.011 ;
     RECT  48.276 7.799 48.294 12.047 ;
     RECT  106.38 10.895 107.658 12.047 ;
     RECT  72.615 6.845 73.566 12.083 ;
     RECT  52.02 8.267 52.038 12.119 ;
     RECT  104.58 9.391 105.297 12.119 ;
     RECT  26.1 10.741 27.414 12.269 ;
     RECT  6.588 11.371 8.097 12.361 ;
     RECT  5.004 11.981 5.022 12.479 ;
     RECT  2.415 6.845 2.697 12.487 ;
     RECT  1.728 12.487 2.697 12.605 ;
     RECT  2.415 12.605 2.697 12.631 ;
     RECT  3.456 12.427 3.474 12.631 ;
     RECT  2.415 12.631 3.546 12.749 ;
     RECT  2.415 12.749 3.15 12.785 ;
     RECT  26.784 12.269 27.414 12.857 ;
     RECT  10.8 11.371 24.57 13.373 ;
     RECT  26.784 12.857 27.198 13.397 ;
     RECT  23.976 13.373 24.57 13.949 ;
     RECT  2.415 12.785 2.697 14.059 ;
     RECT  9.216 11.821 9.342 14.341 ;
     RECT  2.304 14.059 2.697 14.405 ;
     RECT  4.68 14.347 4.698 14.405 ;
     RECT  2.415 14.405 2.697 14.521 ;
     RECT  29.415 10.669 29.97 14.549 ;
     RECT  4.824 14.521 4.842 14.639 ;
     RECT  2.415 14.521 3.366 14.675 ;
     RECT  5.94 12.361 8.097 15.449 ;
     RECT  0.216 15.547 0.234 15.593 ;
     RECT  5.004 15.565 5.022 15.601 ;
     RECT  5.004 15.601 5.166 15.629 ;
     RECT  5.148 15.629 5.166 15.719 ;
     RECT  3.96 15.601 3.978 15.755 ;
     RECT  9.216 14.341 9.702 16.259 ;
     RECT  110.196 12.011 123.462 16.301 ;
     RECT  9.216 16.259 9.342 16.411 ;
     RECT  2.415 14.675 2.697 17.077 ;
     RECT  0.216 17.035 0.234 17.105 ;
     RECT  10.8 13.373 22.77 17.179 ;
     RECT  2.415 17.077 2.862 17.339 ;
     RECT  10.8 17.179 22.842 17.357 ;
     RECT  31.68 11.129 31.77 17.411 ;
     RECT  3.888 17.491 3.906 17.645 ;
     RECT  34.236 9.347 37.458 17.951 ;
     RECT  108.396 12.011 109.386 17.951 ;
     RECT  6.516 15.449 8.097 18.463 ;
     RECT  8.82 16.411 9.342 18.463 ;
     RECT  109.368 17.951 109.386 18.527 ;
     RECT  6.516 18.463 9.342 18.571 ;
     RECT  0.216 18.523 0.234 18.725 ;
     RECT  6.516 18.571 10.026 18.805 ;
     RECT  10.8 17.357 22.77 18.805 ;
     RECT  4.248 18.769 4.266 18.995 ;
     RECT  36.54 17.951 37.458 19.085 ;
     RECT  106.38 12.047 107.01 19.085 ;
     RECT  6.516 18.805 22.77 19.103 ;
     RECT  26.784 13.397 26.802 19.103 ;
     RECT  4.644 19.111 4.662 19.181 ;
     RECT  112.644 16.301 123.462 19.277 ;
     RECT  112.644 19.277 114.39 19.661 ;
     RECT  8.82 19.103 22.77 19.741 ;
     RECT  112.644 19.661 114.282 19.805 ;
     RECT  24.015 13.949 24.57 19.997 ;
     RECT  29.415 14.549 29.697 19.997 ;
     RECT  40.215 9.545 40.497 19.997 ;
     RECT  45.615 8.717 45.897 19.997 ;
     RECT  51.015 11.309 51.297 19.997 ;
     RECT  56.415 11.435 56.697 19.997 ;
     RECT  61.815 11.003 62.097 19.997 ;
     RECT  67.215 11.579 67.497 19.997 ;
     RECT  72.615 12.083 72.897 19.997 ;
     RECT  78.015 10.967 78.297 19.997 ;
     RECT  83.415 11.039 83.697 19.997 ;
     RECT  88.815 10.895 89.097 19.997 ;
     RECT  94.215 9.815 94.497 19.997 ;
     RECT  99.615 10.895 99.897 19.997 ;
     RECT  105.015 12.119 105.297 19.997 ;
     RECT  0.216 20.011 0.234 20.075 ;
     RECT  5.148 19.963 5.166 20.075 ;
     RECT  6.516 19.103 8.097 20.191 ;
     RECT  8.82 19.741 22.842 20.219 ;
     RECT  24.207 19.997 24.57 20.267 ;
     RECT  29.607 19.997 29.697 20.267 ;
     RECT  34.236 17.951 35.514 20.267 ;
     RECT  40.407 19.997 40.497 20.267 ;
     RECT  45.807 19.997 45.897 20.267 ;
     RECT  51.207 19.997 51.297 20.267 ;
     RECT  56.607 19.997 56.697 20.267 ;
     RECT  62.007 19.997 62.097 20.267 ;
     RECT  67.407 19.997 67.497 20.267 ;
     RECT  72.807 19.997 72.897 20.267 ;
     RECT  78.207 19.997 78.297 20.267 ;
     RECT  83.607 19.997 83.697 20.267 ;
     RECT  89.007 19.997 89.097 20.267 ;
     RECT  94.407 19.997 94.497 20.267 ;
     RECT  99.807 19.997 99.897 20.267 ;
     RECT  105.207 19.997 105.297 20.267 ;
     RECT  115.236 19.277 123.462 20.267 ;
     RECT  5.328 20.191 5.346 20.309 ;
     RECT  3.672 20.191 3.69 20.345 ;
     RECT  110.196 16.301 111.618 20.813 ;
     RECT  35.496 20.267 35.514 20.849 ;
     RECT  112.644 19.805 114.138 20.861 ;
     RECT  34.236 20.267 34.362 20.885 ;
     RECT  31.752 17.411 31.77 20.921 ;
     RECT  24.552 20.267 24.57 20.957 ;
     RECT  8.82 20.219 22.698 21.101 ;
     RECT  6.12 20.191 8.097 21.155 ;
     RECT  36.54 19.085 37.062 21.389 ;
     RECT  108.396 17.951 108.414 21.389 ;
     RECT  110.196 20.813 110.754 21.389 ;
     RECT  34.344 20.885 34.362 21.437 ;
     RECT  112.644 20.861 113.058 21.437 ;
     RECT  115.236 20.267 115.794 21.485 ;
     RECT  0.216 21.505 0.234 21.581 ;
     RECT  5.292 21.541 5.454 21.581 ;
     RECT  5.436 21.581 5.454 21.659 ;
     RECT  8.82 21.101 22.662 21.677 ;
     RECT  4.536 21.541 4.554 21.695 ;
     RECT  115.452 21.485 115.794 21.725 ;
     RECT  8.82 21.677 22.23 21.803 ;
     RECT  9.72 21.803 22.23 22.464 ;
     RECT  32.616 11.129 32.634 22.464 ;
     RECT  37.044 21.389 37.062 22.464 ;
     RECT  106.992 19.085 107.01 22.464 ;
     RECT  110.196 21.389 110.214 22.464 ;
     RECT  111.6 20.813 111.618 22.464 ;
     RECT  113.04 21.437 113.058 22.464 ;
     RECT  114.12 20.861 114.138 22.464 ;
     RECT  115.452 21.725 115.542 22.464 ;
     RECT  116.604 20.267 123.462 22.464 ;
     RECT  0.216 23.035 0.234 23.081 ;
     RECT  3.564 23.161 3.582 23.315 ;
     RECT  9.72 22.464 123.462 23.665 ;
     RECT  6.516 21.155 8.097 24.133 ;
     RECT  5.976 24.133 8.097 24.205 ;
     RECT  5.472 24.205 8.097 24.359 ;
     RECT  8.82 21.803 8.838 24.395 ;
     RECT  2.415 17.339 2.697 24.475 ;
     RECT  4.104 24.367 4.122 24.511 ;
     RECT  2.268 24.475 2.697 24.557 ;
     RECT  3.564 24.511 4.698 24.629 ;
     RECT  3.564 24.629 4.122 24.665 ;
     RECT  9.576 23.665 123.462 24.763 ;
     RECT  0.216 26.011 0.234 26.051 ;
     RECT  2.415 24.557 2.697 26.131 ;
     RECT  2.415 26.131 2.862 26.249 ;
     RECT  5.976 24.359 8.097 26.249 ;
     RECT  4.104 24.665 4.122 26.401 ;
     RECT  4.068 26.401 4.266 26.519 ;
     RECT  4.068 26.519 4.086 26.555 ;
     RECT  9 24.763 123.462 27.329 ;
     RECT  2.415 26.249 2.697 27.337 ;
     RECT  6.048 26.249 8.097 27.365 ;
     RECT  1.728 27.337 2.697 27.533 ;
     RECT  4.536 27.337 4.554 27.635 ;
     RECT  9.936 27.329 123.462 28.301 ;
     RECT  9.936 28.301 123.21 28.349 ;
     RECT  121.068 28.349 123.21 28.541 ;
     RECT  6.048 27.365 6.462 28.831 ;
     RECT  7.2 27.365 8.097 28.831 ;
     RECT  9 27.329 9.018 28.831 ;
     RECT  6.048 28.831 9.018 28.921 ;
     RECT  0.216 28.957 0.234 29.021 ;
     RECT  5.796 28.921 9.018 29.021 ;
     RECT  5.796 29.021 8.097 29.255 ;
     RECT  5.256 30.235 5.274 30.299 ;
     RECT  124.38 11.579 124.398 30.413 ;
     RECT  9.936 28.349 120.33 30.653 ;
     RECT  6.048 29.255 8.097 30.721 ;
     RECT  118.296 30.653 120.33 31.229 ;
     RECT  9.936 30.653 117.486 31.325 ;
     RECT  118.836 31.229 120.33 31.963 ;
     RECT  121.068 28.541 121.497 31.963 ;
     RECT  0.54 31.999 0.558 32.045 ;
     RECT  118.836 31.963 121.497 32.093 ;
     RECT  3.492 31.891 3.51 32.189 ;
     RECT  122.256 28.541 123.21 32.285 ;
     RECT  122.256 32.285 122.814 32.333 ;
     RECT  4.284 32.341 4.302 32.443 ;
     RECT  4.284 32.443 4.626 32.495 ;
     RECT  122.256 32.333 122.31 32.765 ;
     RECT  121.068 32.093 121.497 32.861 ;
     RECT  118.836 32.093 120.33 32.957 ;
     RECT  9.936 31.325 117.378 33.043 ;
     RECT  0.216 33.499 0.234 33.575 ;
     RECT  2.415 27.533 2.697 33.691 ;
     RECT  5.976 30.721 8.097 33.889 ;
     RECT  9 29.021 9.018 33.889 ;
     RECT  2.415 33.691 2.79 33.925 ;
     RECT  2.415 33.925 3.294 33.961 ;
     RECT  4.752 32.971 4.77 33.961 ;
     RECT  2.415 33.961 3.438 34.079 ;
     RECT  118.26 33.007 118.278 34.087 ;
     RECT  119.232 32.957 120.33 34.087 ;
     RECT  2.415 34.079 3.15 34.115 ;
     RECT  9.936 33.043 117.414 34.159 ;
     RECT  4.212 33.961 4.77 34.321 ;
     RECT  118.26 34.087 120.33 34.397 ;
     RECT  9.936 34.159 117.45 34.465 ;
     RECT  118.26 34.397 119.934 34.465 ;
     RECT  121.215 32.861 121.497 34.465 ;
     RECT  121.104 34.465 121.497 34.627 ;
     RECT  9.936 34.465 119.934 34.939 ;
     RECT  123.3 33.385 123.318 34.973 ;
     RECT  122.292 32.765 122.31 35.131 ;
     RECT  126.615 11.435 126.897 35.227 ;
     RECT  5.976 33.889 9.018 35.323 ;
     RECT  4.212 34.321 5.238 35.339 ;
     RECT  124.416 32.071 124.434 35.453 ;
     RECT  4.212 35.339 5.094 35.609 ;
     RECT  122.292 35.131 122.562 35.735 ;
     RECT  5.976 35.323 9.162 35.815 ;
     RECT  9.9 34.939 119.934 35.815 ;
     RECT  5.976 35.815 119.934 35.851 ;
     RECT  120.816 34.627 121.497 35.933 ;
     RECT  5.832 35.851 119.934 36.391 ;
     RECT  4.752 35.609 5.094 36.475 ;
     RECT  0.216 36.475 0.234 36.545 ;
     RECT  4.572 36.475 5.094 36.661 ;
     RECT  5.832 36.391 120.006 36.661 ;
     RECT  4.176 36.661 120.006 36.815 ;
     RECT  120.852 35.933 121.497 37.051 ;
     RECT  122.292 35.735 122.31 37.051 ;
     RECT  126.615 35.227 127.134 37.355 ;
     RECT  4.752 36.815 120.006 37.471 ;
     RECT  120.852 37.051 122.31 37.471 ;
     RECT  4.752 37.471 122.31 38.129 ;
     RECT  0.216 37.963 0.234 38.165 ;
     RECT  4.752 38.129 120.294 38.173 ;
     RECT  121.215 38.129 122.31 38.237 ;
     RECT  4.68 38.173 120.294 38.435 ;
     RECT  124.596 38.371 124.614 38.471 ;
     RECT  4.752 38.435 120.294 38.875 ;
     RECT  121.215 38.237 121.698 38.875 ;
     RECT  3.816 39.181 3.834 39.341 ;
     RECT  0.216 39.451 0.234 39.785 ;
     RECT  4.752 38.875 121.698 39.829 ;
     RECT  4.716 39.829 121.698 39.869 ;
     RECT  3.564 39.403 3.726 39.901 ;
     RECT  3.528 39.901 3.726 40.019 ;
     RECT  3.528 40.019 3.546 40.055 ;
     RECT  120.852 39.869 121.698 40.055 ;
     RECT  4.716 39.869 120.006 40.675 ;
     RECT  4.572 40.675 120.006 40.711 ;
     RECT  4.572 40.711 120.186 40.829 ;
     RECT  121.215 40.055 121.698 40.829 ;
     RECT  4.752 40.829 120.186 40.891 ;
     RECT  0.216 40.945 0.234 41.021 ;
     RECT  3.456 40.981 3.474 41.021 ;
     RECT  123.696 41.179 123.714 41.216 ;
     RECT  126.615 37.355 126.897 41.512 ;
     RECT  121.215 40.829 121.497 41.521 ;
     RECT  126.504 41.512 126.897 41.549 ;
     RECT  121.104 41.521 121.497 41.597 ;
     RECT  122.688 41.419 122.706 41.909 ;
     RECT  4.752 40.891 120.294 42.449 ;
     RECT  126.54 41.549 126.897 42.727 ;
     RECT  121.215 41.597 121.497 42.859 ;
     RECT  126.504 42.727 126.897 42.893 ;
     RECT  121.215 42.859 121.59 42.899 ;
     RECT  4.752 42.449 119.97 43.529 ;
     RECT  4.752 43.529 119.862 43.645 ;
     RECT  0.216 43.963 0.234 44.105 ;
     RECT  2.415 34.115 2.697 44.221 ;
     RECT  2.415 44.221 2.826 44.339 ;
     RECT  4.392 43.645 119.862 45.019 ;
     RECT  4.392 45.019 120.15 45.571 ;
     RECT  4.392 45.571 120.402 45.805 ;
     RECT  121.215 42.899 121.497 45.805 ;
     RECT  4.392 45.805 121.497 46.301 ;
     RECT  124.38 46.345 124.398 47.213 ;
     RECT  121.104 46.301 121.497 47.611 ;
     RECT  4.392 46.301 120.15 47.615 ;
     RECT  121.104 47.611 121.554 47.821 ;
     RECT  121.104 47.821 121.626 47.899 ;
     RECT  4.392 47.615 119.898 48.155 ;
     RECT  121.104 47.899 121.734 48.271 ;
     RECT  120.96 48.271 121.734 48.433 ;
     RECT  4.392 48.155 118.386 48.434 ;
     RECT  120.816 48.433 121.734 48.533 ;
     RECT  119.124 48.155 119.898 48.901 ;
     RECT  124.596 47.857 124.614 48.901 ;
     RECT  123.948 48.901 124.614 49.195 ;
     RECT  119.088 48.901 119.898 49.277 ;
     RECT  126.615 42.893 126.897 49.339 ;
     RECT  126.54 49.339 126.897 49.517 ;
     RECT  4.392 48.434 118.35 49.627 ;
     RECT  123.948 49.195 124.866 49.775 ;
     RECT  121.104 48.533 121.734 49.867 ;
     RECT  119.376 49.277 119.898 49.891 ;
     RECT  119.376 49.891 120.258 50.008 ;
     RECT  126.615 49.517 126.897 50.125 ;
     RECT  119.376 50.008 120.366 50.203 ;
     RECT  121.104 49.867 121.914 50.203 ;
     RECT  123.948 49.775 124.614 50.299 ;
     RECT  4.392 49.627 118.602 50.476 ;
     RECT  119.376 50.203 121.914 50.476 ;
     RECT  126.615 50.125 126.954 50.521 ;
     RECT  126.54 50.521 126.954 50.573 ;
     RECT  123.84 50.299 124.614 50.717 ;
     RECT  123.84 50.717 124.254 51.691 ;
     RECT  123.84 51.691 124.614 51.931 ;
     RECT  4.392 50.476 121.914 52.051 ;
     RECT  123.768 51.931 124.614 52.171 ;
     RECT  123.624 52.171 124.614 52.483 ;
     RECT  123.516 52.483 124.614 52.583 ;
     RECT  4.392 52.051 121.986 52.591 ;
     RECT  129.564 49.483 129.582 52.709 ;
     RECT  123.696 52.583 124.614 52.853 ;
     RECT  123.768 52.853 124.614 53.249 ;
     RECT  126.615 50.573 126.954 53.309 ;
     RECT  123.768 53.249 124.326 53.905 ;
     RECT  123.372 53.905 124.326 54.365 ;
     RECT  4.392 52.591 122.526 54.635 ;
     RECT  4.392 54.635 121.734 54.869 ;
     RECT  123.372 54.365 123.786 54.869 ;
     RECT  126.615 53.309 126.897 54.907 ;
     RECT  4.392 54.869 120.258 55.229 ;
     RECT  126.216 54.907 126.897 55.483 ;
     RECT  123.372 54.869 123.714 55.715 ;
     RECT  125.532 55.483 126.897 55.715 ;
     RECT  121.215 54.869 121.734 56.065 ;
     RECT  121.104 56.065 121.734 56.255 ;
     RECT  123.372 55.715 123.462 56.285 ;
     RECT  126.216 55.715 126.897 56.489 ;
     RECT  121.104 56.255 121.497 56.669 ;
     RECT  4.392 55.229 119.934 56.765 ;
     RECT  123.372 56.285 123.39 57.389 ;
     RECT  0.216 57.403 0.234 57.443 ;
     RECT  118.584 56.765 119.934 57.451 ;
     RECT  4.392 56.765 117.45 57.533 ;
     RECT  118.584 57.451 120.222 57.569 ;
     RECT  4.392 57.533 117.414 58.267 ;
     RECT  118.584 57.569 119.862 58.267 ;
     RECT  4.392 58.267 119.862 58.495 ;
     RECT  4.392 58.495 119.898 58.801 ;
     RECT  4.032 58.801 119.898 58.919 ;
     RECT  0.216 58.891 0.234 58.955 ;
     RECT  4.032 58.919 4.77 58.955 ;
     RECT  5.796 58.919 119.898 59.261 ;
     RECT  129.276 55.771 129.294 59.729 ;
     RECT  121.215 56.669 121.497 59.995 ;
     RECT  5.796 59.261 118.602 60.091 ;
     RECT  5.796 60.091 118.638 60.655 ;
     RECT  119.376 59.261 119.898 60.655 ;
     RECT  121.215 59.995 121.878 60.845 ;
     RECT  5.796 60.655 119.898 61.243 ;
     RECT  121.215 60.845 121.554 61.339 ;
     RECT  120.924 61.339 121.554 61.385 ;
     RECT  5.796 61.243 120.078 61.531 ;
     RECT  0.216 61.897 0.234 61.949 ;
     RECT  4.392 58.955 4.77 62.005 ;
     RECT  4.392 62.005 4.914 62.045 ;
     RECT  5.796 61.531 120.15 62.107 ;
     RECT  121.215 61.385 121.554 62.107 ;
     RECT  5.796 62.107 121.554 62.159 ;
     RECT  5.796 62.159 121.497 62.237 ;
     RECT  5.796 62.237 118.602 62.333 ;
     RECT  16.452 62.333 118.602 62.609 ;
     RECT  16.452 62.609 118.062 63.005 ;
     RECT  119.484 62.237 121.497 63.113 ;
     RECT  16.452 63.005 118.026 63.149 ;
     RECT  4.392 62.045 4.77 63.211 ;
     RECT  5.796 62.333 15.606 63.239 ;
     RECT  119.628 63.113 121.497 63.239 ;
     RECT  2.415 44.339 2.697 63.247 ;
     RECT  4.392 63.211 4.842 63.275 ;
     RECT  2.268 63.247 2.697 63.437 ;
     RECT  16.452 63.149 117.738 63.528 ;
     RECT  120.852 63.239 121.497 63.545 ;
     RECT  117.684 63.528 117.738 63.815 ;
     RECT  38.736 63.528 38.754 63.887 ;
     RECT  24.336 63.528 24.426 63.959 ;
     RECT  119.628 63.239 119.646 64.085 ;
     RECT  3.42 64.741 3.438 64.859 ;
     RECT  117.72 63.815 117.738 64.859 ;
     RECT  0.216 64.891 0.234 64.931 ;
     RECT  24.336 63.959 24.354 65.593 ;
     RECT  35.007 65.593 35.097 65.611 ;
     RECT  40.407 65.593 40.497 65.611 ;
     RECT  45.807 65.593 45.897 65.611 ;
     RECT  51.207 65.593 51.297 65.611 ;
     RECT  56.607 65.593 56.697 65.611 ;
     RECT  62.007 65.593 62.097 65.611 ;
     RECT  67.407 65.593 67.497 65.611 ;
     RECT  99.807 65.593 99.897 65.611 ;
     RECT  36.144 65.515 36.162 65.669 ;
     RECT  35.007 65.611 35.19 65.705 ;
     RECT  40.32 65.611 40.59 65.705 ;
     RECT  45.72 65.611 45.99 65.705 ;
     RECT  51.12 65.611 51.39 65.705 ;
     RECT  56.52 65.611 56.79 65.705 ;
     RECT  61.92 65.611 62.19 65.705 ;
     RECT  67.32 65.611 67.59 65.705 ;
     RECT  99.396 65.611 99.897 65.707 ;
     RECT  71.244 65.611 71.262 65.747 ;
     RECT  35.007 65.705 35.097 65.749 ;
     RECT  38.952 65.611 38.97 65.749 ;
     RECT  70.704 65.755 71.046 65.785 ;
     RECT  34.776 65.749 35.097 65.849 ;
     RECT  38.952 65.749 39.366 65.849 ;
     RECT  23.436 65.245 23.454 65.863 ;
     RECT  24.207 65.593 24.354 65.863 ;
     RECT  29.607 65.593 29.697 65.863 ;
     RECT  40.32 65.705 40.497 65.863 ;
     RECT  45.72 65.705 45.897 65.863 ;
     RECT  51.12 65.705 51.297 65.863 ;
     RECT  56.52 65.705 56.697 65.863 ;
     RECT  61.92 65.705 62.097 65.863 ;
     RECT  67.32 65.705 67.497 65.863 ;
     RECT  72.807 65.593 72.897 65.863 ;
     RECT  78.207 65.593 78.297 65.863 ;
     RECT  83.607 65.593 83.697 65.863 ;
     RECT  89.007 65.593 89.097 65.863 ;
     RECT  94.407 65.593 94.497 65.863 ;
     RECT  105.207 65.593 105.297 65.863 ;
     RECT  110.607 65.593 110.697 65.863 ;
     RECT  116.007 65.593 116.097 65.863 ;
     RECT  70.092 65.785 71.046 65.885 ;
     RECT  70.704 65.885 71.046 65.939 ;
     RECT  100.944 65.899 100.962 65.939 ;
     RECT  38.952 65.849 38.97 65.947 ;
     RECT  38.772 65.947 38.97 66.125 ;
     RECT  4.392 63.275 4.77 66.209 ;
     RECT  99.36 65.707 99.897 66.245 ;
     RECT  105.015 65.863 105.297 66.361 ;
     RECT  0.216 66.325 0.234 66.413 ;
     RECT  3.456 66.361 3.474 66.413 ;
     RECT  99.396 66.245 99.897 66.479 ;
     RECT  121.215 63.545 121.497 66.571 ;
     RECT  110.415 65.863 110.697 66.991 ;
     RECT  121.14 66.571 121.497 66.991 ;
     RECT  34.815 65.849 35.097 67.003 ;
     RECT  45.615 65.863 45.897 67.003 ;
     RECT  56.415 65.863 56.697 67.003 ;
     RECT  67.215 65.863 67.497 67.003 ;
     RECT  78.015 65.863 78.297 67.003 ;
     RECT  88.815 65.863 89.097 67.003 ;
     RECT  16.452 63.528 22.446 67.027 ;
     RECT  23.436 65.863 24.354 67.027 ;
     RECT  32.544 65.911 32.562 67.027 ;
     RECT  34.704 67.003 35.097 67.055 ;
     RECT  45.504 67.003 45.897 67.055 ;
     RECT  56.304 67.003 56.697 67.055 ;
     RECT  67.104 67.003 67.497 67.055 ;
     RECT  4.752 66.209 4.77 67.243 ;
     RECT  26.28 67.099 26.298 67.387 ;
     RECT  34.815 67.055 35.097 67.387 ;
     RECT  42.084 63.528 42.102 67.531 ;
     RECT  42.912 64.669 42.93 67.531 ;
     RECT  61.815 65.863 62.097 67.531 ;
     RECT  132.015 7.619 132.297 67.531 ;
     RECT  137.415 4.829 137.697 67.531 ;
     RECT  4.32 67.243 4.77 67.559 ;
     RECT  110.304 66.991 110.697 67.565 ;
     RECT  77.904 67.003 78.297 67.568 ;
     RECT  88.704 67.003 89.097 67.568 ;
     RECT  99.504 66.479 99.897 67.568 ;
     RECT  121.104 66.991 121.497 67.568 ;
     RECT  131.904 67.531 132.297 67.568 ;
     RECT  137.304 67.531 137.697 67.568 ;
     RECT  40.215 65.863 40.497 67.627 ;
     RECT  16.452 67.027 24.354 67.661 ;
     RECT  26.28 67.387 26.802 67.661 ;
     RECT  30.888 67.531 30.906 67.661 ;
     RECT  34.815 67.387 35.118 67.661 ;
     RECT  42.084 67.531 42.93 67.661 ;
     RECT  54.72 67.531 54.738 67.661 ;
     RECT  61.815 67.531 62.73 67.661 ;
     RECT  4.464 67.559 4.77 67.829 ;
     RECT  0.216 67.837 0.234 67.901 ;
     RECT  34.815 67.661 35.097 68.155 ;
     RECT  99.615 67.568 99.897 68.635 ;
     RECT  86.148 68.107 86.166 68.683 ;
     RECT  115.815 65.863 116.097 68.683 ;
     RECT  32.508 67.027 32.562 68.731 ;
     RECT  115.2 68.683 116.097 69.211 ;
     RECT  99.615 68.635 100.602 69.223 ;
     RECT  86.148 68.683 86.886 69.259 ;
     RECT  72.615 65.863 72.897 69.295 ;
     RECT  115.2 69.211 116.802 69.787 ;
     RECT  78.015 67.568 78.297 69.799 ;
     RECT  88.815 67.568 89.097 70.375 ;
     RECT  97.92 66.991 97.938 70.507 ;
     RECT  40.215 67.627 40.914 70.555 ;
     RECT  97.92 70.507 98.622 70.637 ;
     RECT  135.612 66.523 135.63 70.939 ;
     RECT  45.615 67.055 45.897 70.951 ;
     RECT  129.312 71.611 129.33 72.121 ;
     RECT  52.668 64.651 52.686 72.235 ;
     RECT  53.928 71.707 53.946 72.235 ;
     RECT  135.612 70.939 136.242 72.667 ;
     RECT  126.615 56.489 126.897 72.715 ;
     RECT  119.7 71.083 119.718 72.763 ;
     RECT  88.596 70.375 89.097 72.811 ;
     RECT  99.615 69.223 101.07 73.339 ;
     RECT  30.888 73.309 30.906 73.381 ;
     RECT  30.816 73.381 30.906 73.409 ;
     RECT  45.615 70.951 46.422 73.471 ;
     RECT  56.415 67.055 56.697 73.471 ;
     RECT  67.215 67.055 67.497 73.471 ;
     RECT  99.576 73.339 101.07 73.483 ;
     RECT  45.504 73.471 46.422 73.517 ;
     RECT  56.304 73.471 56.697 73.517 ;
     RECT  67.104 73.471 67.497 73.517 ;
     RECT  27.648 67.567 27.666 73.813 ;
     RECT  49.608 73.273 49.626 73.819 ;
     RECT  37.836 64.705 37.854 74.299 ;
     RECT  132.015 67.568 132.297 74.353 ;
     RECT  90.684 73.237 90.702 74.389 ;
     RECT  45.615 73.517 46.422 74.443 ;
     RECT  56.415 73.517 56.697 74.443 ;
     RECT  67.215 73.517 67.497 74.443 ;
     RECT  90.684 74.389 90.918 74.443 ;
     RECT  45.504 74.443 46.422 74.489 ;
     RECT  56.304 74.443 56.697 74.489 ;
     RECT  67.104 74.443 67.497 74.489 ;
     RECT  94.215 65.863 94.497 74.587 ;
     RECT  77.472 69.799 78.297 74.635 ;
     RECT  95.832 72.157 95.85 74.635 ;
     RECT  90.648 74.443 90.918 74.669 ;
     RECT  132.015 74.353 132.462 74.923 ;
     RECT  123.192 65.227 123.21 74.971 ;
     RECT  106.632 73.291 106.65 75.115 ;
     RECT  42.912 67.661 42.93 75.163 ;
     RECT  49.608 73.819 50.094 75.541 ;
     RECT  55.368 68.107 55.386 75.541 ;
     RECT  56.415 74.489 56.697 75.541 ;
     RECT  55.368 75.541 56.697 75.581 ;
     RECT  16.452 67.661 22.446 75.631 ;
     RECT  23.364 67.661 24.354 75.631 ;
     RECT  30.816 73.409 30.834 75.631 ;
     RECT  45.615 74.489 46.422 75.631 ;
     RECT  67.215 74.489 67.497 75.631 ;
     RECT  77.472 74.635 78.894 75.643 ;
     RECT  75.528 75.691 75.546 75.739 ;
     RECT  30.816 75.631 31.086 76.009 ;
     RECT  42.084 67.661 42.102 76.009 ;
     RECT  42.912 75.163 43.29 76.009 ;
     RECT  55.368 75.581 55.386 76.009 ;
     RECT  61.815 67.661 62.097 76.009 ;
     RECT  75.24 75.739 75.546 76.009 ;
     RECT  97.92 70.637 97.938 76.009 ;
     RECT  106.632 75.115 107.226 76.009 ;
     RECT  99.504 73.483 101.07 76.072 ;
     RECT  110.415 67.565 110.697 76.072 ;
     RECT  113.904 67.579 113.922 76.075 ;
     RECT  115.2 69.787 117.018 76.075 ;
     RECT  135.612 72.667 136.278 76.081 ;
     RECT  99.468 76.072 101.07 76.109 ;
     RECT  106.596 76.009 107.226 76.109 ;
     RECT  110.304 76.072 110.697 76.109 ;
     RECT  105.015 66.361 105.786 76.171 ;
     RECT  104.868 76.171 105.786 76.208 ;
     RECT  118.44 70.363 118.458 76.219 ;
     RECT  113.904 76.075 117.018 76.253 ;
     RECT  74.664 76.009 75.546 76.267 ;
     RECT  76.356 76.171 76.374 76.267 ;
     RECT  36.216 69.259 36.234 76.279 ;
     RECT  74.664 76.267 76.374 76.301 ;
     RECT  97.92 76.009 98.622 76.301 ;
     RECT  138.78 76.267 138.798 76.315 ;
     RECT  138.708 76.315 138.798 76.379 ;
     RECT  130.32 67.003 130.338 76.621 ;
     RECT  131.364 74.923 132.462 76.621 ;
     RECT  16.452 75.631 24.354 76.649 ;
     RECT  30.78 76.009 31.086 76.649 ;
     RECT  42.084 76.009 43.29 76.649 ;
     RECT  45.504 75.631 46.422 76.649 ;
     RECT  54.72 76.009 55.386 76.649 ;
     RECT  56.304 75.581 56.697 76.649 ;
     RECT  61.815 76.009 62.73 76.649 ;
     RECT  67.104 75.631 67.497 76.649 ;
     RECT  74.664 76.301 76.266 76.649 ;
     RECT  110.415 76.109 110.697 76.711 ;
     RECT  111.492 72.139 111.51 76.711 ;
     RECT  69.192 69.331 69.21 76.747 ;
     RECT  70.236 67.531 70.254 76.747 ;
     RECT  81.72 72.187 81.738 76.747 ;
     RECT  69.192 76.747 70.254 76.783 ;
     RECT  34.308 68.155 35.097 76.819 ;
     RECT  26.28 67.661 26.298 76.855 ;
     RECT  127.944 74.395 127.962 77.251 ;
     RECT  121.14 67.568 121.497 77.275 ;
     RECT  103.932 76.171 103.95 77.287 ;
     RECT  81.72 76.747 82.35 77.323 ;
     RECT  71.028 68.719 71.046 77.371 ;
     RECT  51.015 65.863 51.297 77.611 ;
     RECT  74.448 77.323 74.466 77.659 ;
     RECT  102.564 70.603 102.582 77.791 ;
     RECT  103.932 77.287 104.202 77.791 ;
     RECT  110.415 76.711 111.51 77.791 ;
     RECT  121.14 77.275 121.77 77.791 ;
     RECT  97.92 76.301 98.01 77.803 ;
     RECT  126.072 72.715 126.897 77.803 ;
     RECT  67.215 76.649 67.497 77.827 ;
     RECT  119.7 72.763 119.826 77.851 ;
     RECT  27.648 73.813 28.242 77.899 ;
     RECT  29.415 65.863 29.697 77.899 ;
     RECT  88.596 72.811 89.37 77.899 ;
     RECT  97.92 77.803 98.622 77.933 ;
     RECT  4.752 67.829 4.77 78.061 ;
     RECT  5.976 63.239 15.606 78.061 ;
     RECT  45.615 76.649 46.422 78.331 ;
     RECT  56.415 76.649 56.697 78.331 ;
     RECT  67.14 77.827 67.497 78.331 ;
     RECT  99.504 76.109 101.07 78.331 ;
     RECT  110.304 77.791 111.51 78.365 ;
     RECT  56.304 78.331 56.697 78.368 ;
     RECT  67.104 78.331 67.497 78.368 ;
     RECT  81.72 77.323 82.386 78.403 ;
     RECT  83.415 65.863 83.697 78.403 ;
     RECT  130.32 76.621 132.462 78.427 ;
     RECT  133.416 74.347 133.434 78.427 ;
     RECT  81.72 78.403 83.697 78.439 ;
     RECT  81.72 78.439 84.222 78.475 ;
     RECT  44.352 65.821 44.37 78.619 ;
     RECT  45.504 78.331 46.422 78.619 ;
     RECT  135.576 76.081 136.278 78.619 ;
     RECT  137.376 67.568 137.697 78.619 ;
     RECT  135.576 78.619 137.697 78.665 ;
     RECT  61.815 76.649 62.097 78.667 ;
     RECT  68.616 76.783 70.254 78.673 ;
     RECT  70.992 77.371 71.046 78.673 ;
     RECT  99.468 78.331 101.07 78.673 ;
     RECT  4.752 78.061 15.606 78.701 ;
     RECT  113.904 76.253 113.922 78.715 ;
     RECT  36.036 76.279 36.234 78.811 ;
     RECT  55.368 76.649 55.386 78.871 ;
     RECT  130.32 78.427 133.434 78.907 ;
     RECT  61.815 78.667 62.19 78.941 ;
     RECT  79.956 71.659 79.974 78.943 ;
     RECT  126.036 77.803 126.897 78.955 ;
     RECT  127.944 77.251 128.25 78.955 ;
     RECT  119.376 77.851 119.826 79.003 ;
     RECT  121.104 77.791 121.77 79.003 ;
     RECT  65.628 78.979 65.646 79.051 ;
     RECT  61.815 78.941 62.097 79.141 ;
     RECT  54.684 78.871 55.386 79.181 ;
     RECT  94.215 74.587 94.554 79.195 ;
     RECT  95.292 74.635 95.85 79.195 ;
     RECT  126.036 78.955 128.25 79.195 ;
     RECT  129.24 72.121 129.33 79.195 ;
     RECT  58.896 79.003 58.914 79.229 ;
     RECT  126.036 79.195 129.33 79.241 ;
     RECT  106.632 76.109 107.226 79.435 ;
     RECT  108.468 78.427 108.486 79.435 ;
     RECT  81.288 78.475 84.222 79.483 ;
     RECT  79.884 78.943 79.974 79.519 ;
     RECT  4.752 78.701 14.562 79.619 ;
     RECT  38.772 66.125 38.79 79.681 ;
     RECT  39.564 70.555 40.914 79.681 ;
     RECT  106.632 79.435 108.486 79.709 ;
     RECT  93.06 75.505 93.078 79.723 ;
     RECT  94.215 79.195 95.85 79.723 ;
     RECT  4.752 79.619 6.462 79.745 ;
     RECT  2.415 63.437 2.697 79.753 ;
     RECT  52.668 72.235 53.946 79.753 ;
     RECT  122.616 74.971 123.21 79.753 ;
     RECT  4.752 79.745 5.274 79.805 ;
     RECT  52.668 79.753 54.558 79.805 ;
     RECT  122.544 79.753 123.21 79.805 ;
     RECT  1.728 79.753 2.697 79.901 ;
     RECT  93.06 79.723 95.85 80.059 ;
     RECT  135.576 78.665 136.278 80.059 ;
     RECT  15.3 78.701 15.606 80.107 ;
     RECT  16.452 76.649 22.446 80.107 ;
     RECT  129.24 79.241 129.33 80.107 ;
     RECT  130.32 78.907 133.542 80.107 ;
     RECT  30.816 76.649 31.086 80.155 ;
     RECT  27.648 77.899 29.697 80.203 ;
     RECT  32.508 68.731 32.598 80.203 ;
     RECT  33.732 76.819 35.097 80.203 ;
     RECT  50.832 77.611 51.297 80.203 ;
     RECT  81.288 79.483 84.834 80.203 ;
     RECT  7.344 79.619 14.562 80.221 ;
     RECT  15.3 80.107 22.446 80.221 ;
     RECT  27.108 80.203 29.697 80.221 ;
     RECT  79.74 79.519 79.974 80.221 ;
     RECT  81.18 80.203 84.834 80.221 ;
     RECT  90.684 74.669 90.918 80.221 ;
     RECT  32.508 80.203 35.097 80.249 ;
     RECT  110.415 78.365 111.51 80.251 ;
     RECT  26.208 76.855 26.298 80.257 ;
     RECT  27.036 80.221 29.697 80.257 ;
     RECT  7.344 80.221 22.446 80.285 ;
     RECT  112.356 67.051 112.374 80.299 ;
     RECT  50.832 80.203 51.642 80.321 ;
     RECT  93.06 80.059 96.462 80.347 ;
     RECT  26.208 80.257 29.697 80.357 ;
     RECT  7.344 80.285 15.678 80.381 ;
     RECT  30.78 80.155 31.086 80.381 ;
     RECT  79.74 80.221 84.834 80.381 ;
     RECT  56.415 78.368 56.697 80.392 ;
     RECT  67.14 78.368 67.497 80.392 ;
     RECT  113.904 78.715 113.994 80.395 ;
     RECT  115.2 76.253 117.018 80.395 ;
     RECT  90.684 80.221 91.314 80.401 ;
     RECT  67.104 80.392 67.497 80.429 ;
     RECT  35.928 78.811 36.234 80.485 ;
     RECT  35.928 80.485 36.558 80.491 ;
     RECT  52.668 79.805 53.946 80.587 ;
     RECT  33.732 80.249 35.097 80.599 ;
     RECT  35.928 80.491 36.63 80.599 ;
     RECT  74.052 77.659 74.466 80.599 ;
     RECT  75.24 76.649 76.266 80.599 ;
     RECT  81.288 80.381 84.834 80.635 ;
     RECT  86.148 69.259 87.318 80.635 ;
     RECT  110.016 80.251 111.51 80.635 ;
     RECT  6.048 79.745 6.462 80.671 ;
     RECT  5.652 80.671 6.462 80.717 ;
     RECT  109.8 80.635 111.51 80.761 ;
     RECT  33.732 80.599 36.63 80.765 ;
     RECT  109.8 80.761 111.618 80.779 ;
     RECT  42.912 76.649 43.29 80.797 ;
     RECT  44.352 78.619 46.422 80.797 ;
     RECT  109.692 80.779 111.618 80.813 ;
     RECT  27.036 80.357 29.697 80.833 ;
     RECT  35.928 80.765 36.63 80.861 ;
     RECT  74.052 80.599 76.266 80.861 ;
     RECT  122.616 79.805 123.21 80.869 ;
     RECT  119.376 79.003 121.77 80.905 ;
     RECT  122.544 80.869 123.21 80.905 ;
     RECT  60.984 80.131 61.002 80.923 ;
     RECT  61.776 79.141 62.097 80.923 ;
     RECT  5.724 80.717 6.462 80.957 ;
     RECT  119.376 80.905 123.21 80.957 ;
     RECT  7.344 80.381 14.562 80.969 ;
     RECT  56.304 80.392 56.697 80.969 ;
     RECT  32.508 80.249 32.994 81.031 ;
     RECT  33.732 80.765 35.097 81.031 ;
     RECT  38.772 79.681 40.914 81.031 ;
     RECT  81.288 80.635 87.318 81.031 ;
     RECT  88.416 77.899 89.37 81.031 ;
     RECT  104.94 76.208 105.786 81.031 ;
     RECT  106.632 79.709 107.73 81.031 ;
     RECT  7.815 80.969 14.562 81.059 ;
     RECT  81.288 81.031 89.37 81.103 ;
     RECT  60.984 80.923 62.097 81.139 ;
     RECT  63.252 81.067 63.27 81.139 ;
     RECT  90.684 80.401 91.386 81.139 ;
     RECT  97.92 77.933 98.01 81.139 ;
     RECT  38.772 81.031 40.95 81.149 ;
     RECT  81.288 81.103 89.838 81.149 ;
     RECT  42.912 80.797 46.422 81.163 ;
     RECT  59.04 81.139 59.058 81.175 ;
     RECT  137.376 78.665 137.697 81.175 ;
     RECT  7.815 81.059 9.054 81.203 ;
     RECT  9.9 81.059 14.562 81.211 ;
     RECT  15.3 80.381 15.606 81.211 ;
     RECT  88.416 81.149 89.838 81.211 ;
     RECT  90.684 81.139 91.782 81.211 ;
     RECT  102.564 77.791 104.202 81.211 ;
     RECT  112.356 80.299 113.058 81.211 ;
     RECT  137.376 81.175 138.15 81.211 ;
     RECT  88.416 81.211 91.782 81.239 ;
     RECT  97.92 81.139 98.622 81.239 ;
     RECT  50.832 80.321 51.297 81.355 ;
     RECT  59.04 81.175 59.166 81.373 ;
     RECT  60.984 81.139 63.27 81.389 ;
     RECT  0.216 81.355 0.234 81.401 ;
     RECT  135.216 80.059 136.278 81.445 ;
     RECT  135.18 81.445 136.278 81.485 ;
     RECT  16.452 80.285 22.446 81.499 ;
     RECT  23.364 76.649 24.354 81.499 ;
     RECT  79.74 80.381 79.974 81.499 ;
     RECT  113.904 80.395 117.018 81.499 ;
     RECT  135.216 81.485 136.278 81.499 ;
     RECT  30.816 80.381 31.086 81.571 ;
     RECT  35.928 80.861 36.234 81.595 ;
     RECT  65.628 79.051 66.042 81.595 ;
     RECT  124.668 75.499 124.686 81.595 ;
     RECT  58.86 81.373 59.166 81.607 ;
     RECT  124.488 81.595 124.686 81.643 ;
     RECT  16.452 81.499 24.354 81.679 ;
     RECT  32.508 81.031 35.097 81.679 ;
     RECT  58.86 81.607 59.382 81.679 ;
     RECT  60.156 81.499 60.174 81.679 ;
     RECT  124.272 81.643 124.686 81.715 ;
     RECT  64.548 79.015 64.566 81.751 ;
     RECT  65.628 81.595 66.078 81.751 ;
     RECT  68.616 78.673 71.046 81.751 ;
     RECT  77.364 75.643 78.894 81.751 ;
     RECT  112.356 81.211 113.166 81.751 ;
     RECT  113.904 81.499 117.198 81.751 ;
     RECT  124.128 81.715 124.686 81.751 ;
     RECT  124.128 81.751 125.082 81.821 ;
     RECT  9.9 81.211 15.606 81.832 ;
     RECT  16.344 81.679 24.354 81.832 ;
     RECT  56.415 80.969 56.697 81.832 ;
     RECT  7.815 81.203 9.018 81.841 ;
     RECT  9.9 81.832 24.354 81.869 ;
     RECT  58.86 81.679 60.174 81.869 ;
     RECT  88.416 81.239 91.71 81.869 ;
     RECT  102.42 81.211 104.202 81.869 ;
     RECT  112.356 81.751 117.198 81.869 ;
     RECT  75.24 80.861 76.266 81.883 ;
     RECT  38.772 81.149 40.914 81.931 ;
     RECT  42.084 76.649 42.102 81.931 ;
     RECT  55.368 79.181 55.386 81.931 ;
     RECT  56.16 81.832 56.697 81.931 ;
     RECT  102.42 81.869 104.058 81.931 ;
     RECT  25.236 71.491 25.254 81.949 ;
     RECT  109.692 80.813 111.51 81.949 ;
     RECT  112.356 81.869 117.162 81.949 ;
     RECT  74.052 80.861 74.466 81.976 ;
     RECT  75.204 81.883 76.266 81.976 ;
     RECT  20.844 81.869 24.354 81.979 ;
     RECT  25.236 81.949 25.29 81.979 ;
     RECT  67.14 80.429 67.497 81.979 ;
     RECT  74.052 81.976 76.266 81.979 ;
     RECT  26.208 80.357 26.298 81.985 ;
     RECT  38.772 81.931 42.102 81.985 ;
     RECT  49.212 75.541 50.094 81.985 ;
     RECT  50.832 81.355 51.93 81.985 ;
     RECT  55.368 81.931 56.697 81.985 ;
     RECT  64.008 81.751 66.078 81.985 ;
     RECT  97.92 81.239 98.37 81.985 ;
     RECT  109.692 81.949 117.162 81.985 ;
     RECT  3.636 81.985 3.654 82.021 ;
     RECT  30.78 81.571 31.086 82.021 ;
     RECT  32.256 81.679 35.097 82.021 ;
     RECT  37.764 74.299 37.854 82.021 ;
     RECT  38.628 81.985 42.102 82.021 ;
     RECT  42.876 81.163 46.422 82.021 ;
     RECT  63.864 81.985 66.078 82.021 ;
     RECT  66.816 81.979 67.497 82.021 ;
     RECT  72.615 69.295 73.098 82.021 ;
     RECT  73.908 81.979 76.266 82.021 ;
     RECT  77.22 81.751 78.894 82.021 ;
     RECT  97.776 81.985 98.37 82.021 ;
     RECT  126.036 79.241 128.25 82.021 ;
     RECT  129.24 80.107 133.542 82.021 ;
     RECT  137.376 81.211 138.222 82.021 ;
     RECT  49.212 81.985 51.93 82.049 ;
     RECT  3.636 82.021 3.906 82.061 ;
     RECT  6.048 80.957 6.462 82.075 ;
     RECT  7.236 81.841 9.018 82.075 ;
     RECT  30.78 82.021 35.097 82.075 ;
     RECT  47.484 63.528 47.502 82.075 ;
     RECT  55.26 81.985 56.697 82.075 ;
     RECT  58.86 81.869 60.03 82.075 ;
     RECT  60.984 81.389 62.838 82.075 ;
     RECT  81.288 81.149 87.318 82.075 ;
     RECT  93.06 80.347 96.93 82.075 ;
     RECT  129.24 82.021 134.082 82.075 ;
     RECT  92.916 82.075 96.93 82.109 ;
     RECT  27.036 80.833 30.006 82.111 ;
     RECT  30.78 82.075 35.118 82.111 ;
     RECT  35.928 81.595 36.81 82.111 ;
     RECT  60.84 82.075 62.838 82.111 ;
     RECT  63.864 82.021 67.497 82.111 ;
     RECT  97.776 82.021 98.658 82.111 ;
     RECT  6.048 82.075 9.018 82.123 ;
     RECT  52.668 80.587 54.414 82.123 ;
     RECT  55.188 82.075 56.697 82.123 ;
     RECT  5.796 82.123 9.018 82.139 ;
     RECT  90.684 81.869 91.71 82.139 ;
     RECT  108.468 79.709 108.486 82.139 ;
     RECT  119.376 80.957 121.77 82.139 ;
     RECT  26.1 81.985 26.298 82.147 ;
     RECT  27.036 82.111 35.118 82.147 ;
     RECT  37.764 82.021 37.89 82.147 ;
     RECT  38.628 82.021 46.422 82.147 ;
     RECT  52.668 82.123 56.697 82.147 ;
     RECT  77.076 82.021 78.894 82.147 ;
     RECT  79.74 81.499 80.55 82.147 ;
     RECT  81.288 82.075 87.678 82.147 ;
     RECT  104.94 81.031 107.73 82.147 ;
     RECT  119.376 82.139 121.626 82.157 ;
     RECT  58.788 82.075 60.03 82.171 ;
     RECT  52.2 82.147 56.697 82.183 ;
     RECT  97.74 82.111 98.658 82.183 ;
     RECT  99.432 78.673 101.07 82.183 ;
     RECT  35.928 82.111 36.918 82.219 ;
     RECT  37.764 82.147 46.422 82.219 ;
     RECT  47.196 82.075 47.502 82.219 ;
     RECT  57.672 82.111 57.69 82.219 ;
     RECT  58.644 82.171 60.03 82.219 ;
     RECT  92.916 82.109 93.078 82.219 ;
     RECT  129.024 82.075 134.082 82.219 ;
     RECT  9.9 81.869 20.07 82.255 ;
     RECT  26.1 82.147 35.118 82.255 ;
     RECT  35.928 82.219 36.954 82.255 ;
     RECT  57.672 82.219 60.03 82.255 ;
     RECT  60.84 82.111 67.626 82.255 ;
     RECT  68.616 81.751 71.586 82.255 ;
     RECT  94.068 82.109 96.93 82.255 ;
     RECT  97.74 82.183 101.07 82.255 ;
     RECT  118.116 76.219 118.458 82.255 ;
     RECT  119.376 82.157 121.59 82.255 ;
     RECT  122.616 80.957 123.21 82.255 ;
     RECT  124.128 81.821 124.686 82.255 ;
     RECT  104.904 82.147 107.73 82.267 ;
     RECT  26.1 82.255 36.954 82.291 ;
     RECT  37.764 82.219 47.502 82.291 ;
     RECT  90.792 82.139 91.71 82.291 ;
     RECT  102.096 81.931 104.058 82.291 ;
     RECT  109.548 81.985 117.162 82.291 ;
     RECT  122.616 82.255 124.686 82.291 ;
     RECT  125.892 82.021 128.25 82.291 ;
     RECT  129.024 82.219 134.118 82.291 ;
     RECT  135.216 81.499 136.422 82.291 ;
     RECT  52.2 82.183 56.826 82.381 ;
     RECT  57.6 82.255 60.03 82.381 ;
     RECT  109.224 82.291 117.162 82.409 ;
     RECT  129.024 82.291 136.422 82.409 ;
     RECT  60.84 82.255 71.586 82.445 ;
     RECT  129.096 82.409 136.422 82.445 ;
     RECT  94.068 82.255 101.07 82.453 ;
     RECT  101.844 82.291 104.058 82.453 ;
     RECT  26.1 82.291 47.502 82.507 ;
     RECT  48.348 66.451 48.366 82.507 ;
     RECT  26.1 82.507 48.366 82.525 ;
     RECT  49.212 82.049 51.318 82.525 ;
     RECT  90.792 82.291 91.998 82.525 ;
     RECT  92.736 82.219 93.078 82.525 ;
     RECT  7.236 82.139 9.018 82.561 ;
     RECT  9.792 82.255 20.07 82.561 ;
     RECT  72.615 82.021 76.266 82.561 ;
     RECT  77.076 82.147 87.678 82.561 ;
     RECT  88.416 81.869 89.838 82.561 ;
     RECT  109.224 82.409 117.09 82.561 ;
     RECT  122.544 82.291 124.686 82.561 ;
     RECT  125.46 82.291 128.25 82.561 ;
     RECT  129.348 82.445 136.422 82.561 ;
     RECT  137.304 82.021 138.222 82.561 ;
     RECT  4.752 79.805 4.77 82.651 ;
     RECT  7.236 82.561 20.07 82.651 ;
     RECT  20.844 81.979 25.29 82.651 ;
     RECT  122.544 82.561 128.25 82.651 ;
     RECT  94.068 82.453 104.058 82.679 ;
     RECT  7.236 82.651 25.326 82.687 ;
     RECT  60.948 82.445 71.586 82.688 ;
     RECT  77.076 82.561 89.838 82.795 ;
     RECT  4.572 82.651 4.77 82.831 ;
     RECT  5.796 82.139 6.462 82.831 ;
     RECT  77.076 82.795 89.946 82.831 ;
     RECT  90.792 82.525 93.078 82.831 ;
     RECT  94.068 82.679 94.59 82.831 ;
     RECT  95.436 82.679 104.058 82.831 ;
     RECT  104.904 82.267 108.342 82.831 ;
     RECT  26.1 82.525 51.318 82.843 ;
     RECT  5.724 82.831 6.462 82.921 ;
     RECT  7.236 82.687 25.362 82.921 ;
     RECT  26.1 82.843 51.39 82.921 ;
     RECT  52.2 82.381 60.03 82.921 ;
     RECT  77.076 82.831 90.054 82.921 ;
     RECT  90.792 82.831 94.59 82.921 ;
     RECT  72.615 82.561 76.338 82.993 ;
     RECT  77.076 82.921 94.59 82.993 ;
     RECT  72.615 82.993 94.59 83.065 ;
     RECT  95.436 82.831 108.342 83.065 ;
     RECT  109.152 82.561 117.09 83.065 ;
     RECT  5.724 82.921 60.03 83.101 ;
     RECT  60.984 82.688 71.586 83.101 ;
     RECT  72.468 83.065 94.59 83.101 ;
     RECT  117.972 82.255 121.59 83.101 ;
     RECT  122.364 82.651 128.25 83.101 ;
     RECT  117.972 83.101 128.286 83.179 ;
     RECT  3.96 82.831 4.77 83.219 ;
     RECT  4.068 83.219 4.77 83.227 ;
     RECT  5.724 83.101 60.138 83.227 ;
     RECT  95.436 83.065 117.09 83.275 ;
     RECT  117.972 83.179 128.574 83.275 ;
     RECT  95.436 83.275 128.61 83.335 ;
     RECT  129.348 82.561 138.33 83.335 ;
     RECT  60.984 83.101 94.59 83.461 ;
     RECT  95.436 83.335 138.33 83.461 ;
     RECT  4.068 83.227 60.138 83.489 ;
     RECT  60.984 83.461 138.33 83.489 ;
     RECT  26.28 83.489 60.138 83.569 ;
     RECT  60.984 83.489 107.226 83.569 ;
     RECT  108.072 83.489 138.33 83.605 ;
     RECT  108.072 83.605 138.762 83.669 ;
     RECT  4.068 83.489 25.542 83.759 ;
     RECT  26.28 83.569 107.226 83.759 ;
     RECT  108.072 83.669 128.79 83.759 ;
     RECT  129.672 83.669 138.762 83.759 ;
     RECT  4.284 83.759 4.914 83.795 ;
     RECT  26.28 83.759 31.302 83.795 ;
     RECT  32.148 83.759 36.018 83.795 ;
     RECT  39.888 83.759 42.786 83.795 ;
     RECT  48.42 83.759 56.697 83.795 ;
     RECT  57.42 83.759 79.974 83.795 ;
     RECT  87.768 83.759 107.118 83.795 ;
     RECT  108.072 83.759 116.55 83.795 ;
     RECT  4.284 83.795 4.59 83.831 ;
     RECT  18.36 83.759 25.506 83.831 ;
     RECT  57.42 83.795 60.138 83.831 ;
     RECT  135.36 83.759 138.726 83.837 ;
     RECT  48.42 83.795 52.542 83.903 ;
     RECT  80.964 83.759 86.886 83.903 ;
     RECT  18.615 83.831 25.506 83.933 ;
     RECT  39.888 83.795 42.75 83.933 ;
     RECT  43.992 83.759 47.502 83.933 ;
     RECT  39.888 83.933 42.39 83.939 ;
     RECT  2.415 79.901 2.697 83.987 ;
     RECT  6.264 83.759 16.362 83.987 ;
     RECT  53.28 83.795 56.697 83.987 ;
     RECT  80.964 83.903 83.697 83.987 ;
     RECT  6.264 83.987 7.905 84.029 ;
     RECT  8.64 83.987 16.362 84.029 ;
     RECT  18.615 83.933 21.546 84.029 ;
     RECT  22.356 83.933 25.506 84.029 ;
     RECT  26.28 83.795 31.014 84.029 ;
     RECT  37.98 83.759 38.97 84.029 ;
     RECT  39.996 83.939 42.39 84.029 ;
     RECT  50.724 83.903 52.542 84.029 ;
     RECT  53.28 83.987 56.505 84.029 ;
     RECT  57.42 83.831 60.03 84.029 ;
     RECT  61.056 83.795 79.974 84.029 ;
     RECT  80.964 83.987 83.574 84.029 ;
     RECT  84.636 83.903 86.886 84.029 ;
     RECT  87.768 83.795 93.15 84.029 ;
     RECT  93.96 83.795 107.118 84.029 ;
     RECT  108.072 83.795 113.418 84.029 ;
     RECT  117.576 83.759 118.206 84.029 ;
     RECT  119.088 83.759 128.394 84.029 ;
     RECT  129.672 83.759 132.534 84.029 ;
     RECT  133.272 83.759 134.514 84.029 ;
     RECT  136.404 83.837 138.726 84.029 ;
     RECT  16.236 84.029 16.362 84.065 ;
     RECT  36.756 83.759 37.026 84.065 ;
     RECT  43.992 83.933 44.334 84.065 ;
     RECT  45.36 83.933 47.502 84.065 ;
     RECT  106.38 84.029 107.118 84.065 ;
     RECT  12.852 84.029 13.554 84.077 ;
     RECT  32.148 83.795 35.982 84.077 ;
     RECT  8.748 84.029 10.926 84.101 ;
     RECT  20.772 84.029 21.51 84.101 ;
     RECT  40.215 84.029 40.374 84.101 ;
     RECT  58.14 84.029 58.986 84.101 ;
     RECT  61.524 84.029 65.394 84.101 ;
     RECT  76.608 84.029 78.105 84.101 ;
     RECT  81 84.029 82.026 84.101 ;
     RECT  88.236 84.029 93.15 84.101 ;
     RECT  96.66 84.029 105.606 84.101 ;
     RECT  120.492 84.029 122.814 84.101 ;
     RECT  124.884 84.029 125.406 84.101 ;
     RECT  126.54 84.029 128.034 84.101 ;
     RECT  129.78 84.029 131.274 84.101 ;
     RECT  132.015 84.029 132.534 84.101 ;
     RECT  133.272 84.029 134.406 84.101 ;
     RECT  47.268 84.065 47.502 84.137 ;
     RECT  66.564 84.029 67.374 84.137 ;
     RECT  69.516 84.029 69.534 84.137 ;
     RECT  76.752 84.101 76.95 84.137 ;
     RECT  11.88 84.029 11.898 84.173 ;
     RECT  18.615 84.029 19.962 84.173 ;
     RECT  26.388 84.029 27.594 84.173 ;
     RECT  28.62 84.029 30.762 84.173 ;
     RECT  48.528 83.903 49.59 84.173 ;
     RECT  90.36 84.101 93.15 84.173 ;
     RECT  6.264 84.029 6.282 84.209 ;
     RECT  8.748 84.101 10.494 84.209 ;
     RECT  12.852 84.077 13.305 84.209 ;
     RECT  26.388 84.173 26.55 84.209 ;
     RECT  28.62 84.173 29.862 84.209 ;
     RECT  38.592 84.029 38.826 84.209 ;
     RECT  50.724 84.029 51.75 84.209 ;
     RECT  53.712 84.029 54.81 84.209 ;
     RECT  66.636 84.137 67.374 84.209 ;
     RECT  70.488 84.029 70.794 84.209 ;
     RECT  71.532 84.029 73.71 84.209 ;
     RECT  75.708 84.029 75.798 84.209 ;
     RECT  81 84.101 81.27 84.209 ;
     RECT  91.224 84.173 93.15 84.209 ;
     RECT  100.62 84.101 105.606 84.209 ;
     RECT  108.144 84.029 112.41 84.209 ;
     RECT  114.192 83.795 116.55 84.209 ;
     RECT  119.088 84.029 119.682 84.209 ;
     RECT  120.744 84.101 122.814 84.209 ;
     RECT  123.588 84.029 123.858 84.209 ;
     RECT  126.615 84.101 128.034 84.209 ;
     RECT  16.344 84.065 16.362 84.221 ;
     RECT  47.448 84.137 47.502 84.221 ;
     RECT  106.596 84.065 107.118 84.221 ;
     RECT  2.415 83.987 2.505 84.257 ;
     RECT  7.2 84.029 7.905 84.257 ;
     RECT  13.215 84.209 13.305 84.257 ;
     RECT  18.615 84.173 19.926 84.257 ;
     RECT  24.015 84.029 24.105 84.257 ;
     RECT  29.415 84.209 29.862 84.257 ;
     RECT  32.292 84.077 35.982 84.257 ;
     RECT  40.215 84.101 40.305 84.257 ;
     RECT  45.36 84.065 46.458 84.257 ;
     RECT  51.015 84.209 51.75 84.257 ;
     RECT  56.415 84.029 56.505 84.257 ;
     RECT  71.532 84.209 73.638 84.257 ;
     RECT  78.015 84.101 78.105 84.257 ;
     RECT  108.144 84.209 110.505 84.257 ;
     RECT  121.215 84.209 121.41 84.257 ;
     RECT  126.615 84.209 126.99 84.257 ;
     RECT  132.015 84.101 132.246 84.257 ;
     RECT  29.7 84.257 29.862 84.299 ;
     RECT  100.836 84.209 105.606 84.299 ;
     RECT  122.148 84.209 122.814 84.317 ;
     RECT  20.772 84.101 21.33 84.365 ;
     RECT  48.528 84.173 48.546 84.365 ;
     RECT  136.404 84.029 138.258 84.371 ;
     RECT  7.2 84.257 7.722 84.413 ;
     RECT  46.116 84.257 46.458 84.413 ;
     RECT  59.724 84.029 60.03 84.413 ;
     RECT  81 84.209 81.09 84.413 ;
     RECT  83.052 84.029 83.574 84.413 ;
     RECT  93.96 84.029 95.598 84.413 ;
     RECT  101.88 84.299 105.606 84.413 ;
     RECT  108.144 84.257 110.25 84.413 ;
     RECT  121.392 84.257 121.41 84.413 ;
     RECT  126.936 84.257 126.99 84.413 ;
     RECT  101.88 84.413 104.958 84.941 ;
     RECT  19.224 84.257 19.926 84.989 ;
     RECT  32.292 84.257 34.398 84.989 ;
     RECT  36.864 84.065 37.026 84.989 ;
     RECT  51.192 84.257 51.75 84.989 ;
     RECT  53.748 84.209 54.81 84.989 ;
     RECT  85.14 84.029 86.886 84.989 ;
     RECT  88.272 84.101 89.334 84.989 ;
     RECT  96.66 84.101 99.81 84.989 ;
     RECT  133.272 84.101 134.334 84.989 ;
     RECT  136.404 84.371 137.466 84.989 ;
     RECT  9.792 84.209 10.494 85.483 ;
     RECT  25.056 84.029 25.506 85.483 ;
     RECT  32.292 84.989 32.85 85.483 ;
     RECT  38.592 84.209 38.61 85.483 ;
     RECT  41.184 84.029 41.742 85.483 ;
     RECT  66.816 84.209 67.374 85.483 ;
     RECT  71.532 84.257 72.198 85.483 ;
     RECT  73.224 84.257 73.638 85.483 ;
     RECT  9.792 85.483 10.854 85.517 ;
     RECT  22.356 84.029 22.914 85.517 ;
     RECT  24.444 85.483 25.506 85.517 ;
     RECT  31.788 85.483 32.85 85.517 ;
     RECT  35.424 84.257 35.982 85.517 ;
     RECT  38.052 85.483 38.61 85.517 ;
     RECT  41.184 85.483 42.246 85.517 ;
     RECT  49.356 84.173 49.59 85.517 ;
     RECT  61.596 84.101 62.118 85.517 ;
     RECT  63.18 84.101 65.394 85.517 ;
     RECT  66.312 85.483 67.374 85.517 ;
     RECT  68.148 84.029 68.418 85.517 ;
     RECT  71.532 85.483 73.638 85.517 ;
     RECT  85.14 84.989 86.202 85.517 ;
     RECT  91.476 84.209 93.15 85.517 ;
     RECT  97.704 84.989 99.81 85.517 ;
     RECT  101.88 84.941 102.942 85.517 ;
     RECT  103.968 84.941 104.958 85.517 ;
     RECT  109.188 84.413 110.25 85.517 ;
     RECT  111.276 84.209 112.41 85.517 ;
     RECT  114.444 84.209 116.55 85.517 ;
     RECT  117.576 84.029 118.17 85.517 ;
     RECT  130.14 84.101 131.274 85.517 ;
     RECT  138.24 84.371 138.258 85.517 ;
     RECT  44.244 84.065 44.334 86.189 ;
     RECT  51.732 84.989 51.75 86.233 ;
     RECT  81.072 84.413 81.09 86.233 ;
     RECT  91.476 85.517 91.494 86.233 ;
     RECT  93.96 84.413 94.554 86.233 ;
     RECT  104.94 85.517 104.958 86.233 ;
     RECT  93.492 86.233 94.554 86.256 ;
     RECT  93.51 86.256 94.536 86.261 ;
    LAYER M4 ;
     RECT  2.408 2.148 2.512 84.252 ;
     RECT  2.512 2.418 2.704 83.982 ;
     RECT  2.704 42.48 3.683 42.504 ;
     RECT  2.704 39.312 3.845 39.432 ;
     RECT  2.704 6.672 4.057 6.696 ;
     RECT  2.704 65.76 4.309 66.408 ;
     RECT  4.057 6.672 4.345 6.84 ;
     RECT  4.309 65.76 4.393 67.272 ;
     RECT  2.704 82.032 4.561 82.056 ;
     RECT  2.704 83.232 4.561 83.256 ;
     RECT  4.345 6.672 4.637 7.8 ;
     RECT  2.704 33.936 4.643 33.96 ;
     RECT  4.604 19.152 4.645 19.176 ;
     RECT  4.645 19.152 4.691 19.992 ;
     RECT  4.645 14.352 4.732 14.376 ;
     RECT  4.393 65.76 4.835 66.408 ;
     RECT  4.789 63.216 4.837 63.24 ;
     RECT  4.789 64.56 4.837 64.584 ;
     RECT  4.796 58.56 4.844 58.584 ;
     RECT  4.844 62.016 4.931 62.04 ;
     RECT  4.837 63.216 4.931 64.584 ;
     RECT  2.704 12.432 5.029 12.456 ;
     RECT  4.637 7.392 5.068 7.8 ;
     RECT  4.645 15.6 5.068 15.624 ;
     RECT  4.559 32.448 5.123 32.472 ;
     RECT  4.556 36.48 5.123 36.504 ;
     RECT  3.845 39.408 5.123 39.432 ;
     RECT  4.691 19.968 5.177 19.992 ;
     RECT  4.561 82.032 5.209 83.256 ;
     RECT  5.077 30.72 5.245 30.744 ;
     RECT  5.077 38.4 5.353 38.424 ;
     RECT  4.777 3.936 5.357 3.96 ;
     RECT  5.068 7.776 5.365 7.8 ;
     RECT  4.561 9.36 5.365 9.384 ;
     RECT  5.029 11.952 5.365 12.456 ;
     RECT  5.365 7.776 5.411 9.384 ;
     RECT  5.365 11.376 5.411 12.456 ;
     RECT  4.844 58.56 5.42 58.872 ;
     RECT  5.353 38.4 5.437 38.808 ;
     RECT  5.42 58.32 5.501 58.872 ;
     RECT  5.411 11.376 5.507 11.976 ;
     RECT  2.704 40.992 5.507 41.016 ;
     RECT  5.42 44.352 5.507 44.376 ;
     RECT  5.501 58.32 5.507 58.344 ;
     RECT  5.245 79.776 5.603 79.8 ;
     RECT  5.209 82.032 5.603 83.352 ;
     RECT  5.461 80.928 5.605 80.952 ;
     RECT  5.603 82.032 5.605 82.152 ;
     RECT  5.605 80.928 5.612 82.152 ;
     RECT  5.603 83.136 5.681 83.256 ;
     RECT  5.612 80.688 5.699 82.152 ;
     RECT  5.605 86.208 5.699 86.232 ;
     RECT  5.699 80.928 5.753 82.152 ;
     RECT  5.681 83.136 5.753 83.208 ;
     RECT  5.411 8.448 5.897 8.472 ;
     RECT  5.461 57.264 5.897 57.288 ;
     RECT  5.437 38.4 6.113 38.424 ;
     RECT  4.693 1.728 6.149 1.752 ;
     RECT  4.093 26.256 6.323 26.28 ;
     RECT  6.236 27.264 6.323 27.288 ;
     RECT  5.245 30.24 6.329 30.744 ;
     RECT  6.329 30.24 6.364 30.264 ;
     RECT  6.277 23.28 6.433 23.304 ;
     RECT  6.037 24.432 6.433 24.456 ;
     RECT  5.753 81.888 6.721 82.152 ;
     RECT  5.753 83.184 6.721 83.208 ;
     RECT  5.785 0.576 6.805 0.6 ;
     RECT  6.649 85.488 6.851 85.512 ;
     RECT  6.805 0.576 6.977 1.176 ;
     RECT  7.148 84.384 7.235 84.408 ;
     RECT  6.721 81.888 7.261 83.208 ;
     RECT  6.977 0.576 7.331 0.6 ;
     RECT  5.461 4.656 7.369 4.68 ;
     RECT  7.369 3.696 7.808 4.68 ;
     RECT  5.507 11.376 7.808 11.4 ;
     RECT  4.645 17.616 7.808 17.64 ;
     RECT  5.281 21.552 7.808 21.576 ;
     RECT  6.433 23.28 7.808 24.456 ;
     RECT  6.277 28.944 7.808 28.968 ;
     RECT  5.365 35.856 7.808 35.88 ;
     RECT  4.931 63.648 7.808 64.584 ;
     RECT  4.835 65.76 7.808 65.784 ;
     RECT  7.285 80.784 7.808 80.808 ;
     RECT  7.261 81.888 7.808 84.252 ;
     RECT  7.808 2.148 7.813 84.252 ;
     RECT  7.813 1.728 7.912 84.252 ;
     RECT  7.912 1.728 8.104 83.982 ;
     RECT  8.104 80.688 8.243 83.688 ;
     RECT  8.243 80.688 8.531 83.208 ;
     RECT  8.104 1.728 8.915 1.752 ;
     RECT  8.531 80.688 9.101 80.808 ;
     RECT  8.104 3.696 9.137 4.68 ;
     RECT  9.169 3.408 9.397 3.432 ;
     RECT  8.531 82.176 9.421 83.208 ;
     RECT  9.397 2.88 9.497 3.432 ;
     RECT  9.421 82.176 9.505 83.832 ;
     RECT  9.133 35.328 9.683 35.352 ;
     RECT  8.104 24.192 9.961 24.792 ;
     RECT  9.961 24.192 10.033 24.984 ;
     RECT  9.445 80.496 10.213 80.52 ;
     RECT  9.505 82.176 10.213 82.872 ;
     RECT  9.925 1.728 10.253 1.752 ;
     RECT  9.497 3.408 10.289 3.432 ;
     RECT  9.137 4.656 10.609 4.68 ;
     RECT  10.141 38.112 10.609 38.136 ;
     RECT  10.033 24.192 10.717 25.848 ;
     RECT  10.453 1.152 10.753 1.176 ;
     RECT  8.104 63.648 10.825 63.672 ;
     RECT  10.825 63.552 10.865 63.672 ;
     RECT  10.717 24.192 10.969 26.52 ;
     RECT  10.753 0.576 10.973 1.176 ;
     RECT  10.973 0.576 11.027 0.6 ;
     RECT  10.213 80.496 11.029 82.872 ;
     RECT  11.005 42.576 11.077 42.6 ;
     RECT  10.105 43.68 11.077 43.704 ;
     RECT  11.077 42.528 11.113 43.704 ;
     RECT  11.113 41.952 11.125 43.704 ;
     RECT  11.029 45.504 11.125 45.528 ;
     RECT  11.077 78.432 11.125 78.456 ;
     RECT  11.125 78.432 11.173 78.792 ;
     RECT  10.897 6.624 11.221 6.648 ;
     RECT  11.125 41.952 11.315 43.896 ;
     RECT  11.173 78.432 11.317 79.512 ;
     RECT  11.029 80.496 11.317 83.832 ;
     RECT  10.933 31.2 11.365 31.224 ;
     RECT  9.637 32.448 11.365 32.472 ;
     RECT  11.317 78.432 11.401 83.832 ;
     RECT  10.609 3.696 11.473 4.68 ;
     RECT  11.365 31.2 11.509 32.472 ;
     RECT  11.545 40.128 11.557 40.152 ;
     RECT  10.609 37.728 11.581 38.136 ;
     RECT  11.581 37.728 11.617 38.52 ;
     RECT  11.557 40.128 11.653 40.392 ;
     RECT  11.617 37.728 11.689 38.76 ;
     RECT  11.653 40.128 11.689 40.872 ;
     RECT  11.689 37.728 11.701 40.872 ;
     RECT  11.315 41.952 11.701 43.704 ;
     RECT  11.653 74.592 11.701 74.616 ;
     RECT  11.401 78.432 11.747 83.88 ;
     RECT  10.897 56.352 11.833 56.376 ;
     RECT  11.701 37.728 11.843 43.704 ;
     RECT  11.509 30.912 11.869 32.472 ;
     RECT  10.309 85.488 11.909 85.512 ;
     RECT  9.889 34.944 12.085 34.968 ;
     RECT  11.701 74.352 12.181 74.616 ;
     RECT  12.085 34.944 12.193 35.208 ;
     RECT  12.157 36.24 12.193 36.264 ;
     RECT  11.473 1.728 12.269 1.752 ;
     RECT  11.843 37.728 12.325 40.92 ;
     RECT  12.181 74.352 12.325 75.432 ;
     RECT  12.193 34.944 12.373 36.264 ;
     RECT  12.325 37.344 12.373 40.92 ;
     RECT  12.325 74.352 12.373 75.528 ;
     RECT  11.747 79.488 12.421 83.88 ;
     RECT  11.833 56.352 12.517 56.568 ;
     RECT  12.373 0.192 12.563 0.216 ;
     RECT  11.125 45.504 12.709 46.344 ;
     RECT  10.969 24.192 12.733 26.616 ;
     RECT  11.843 41.952 12.757 43.704 ;
     RECT  11.747 78.432 12.757 78.456 ;
     RECT  12.421 79.488 12.757 84.072 ;
     RECT  9.997 48.528 12.769 48.552 ;
     RECT  11.473 3.456 12.841 4.68 ;
     RECT  12.421 76.8 12.853 76.824 ;
     RECT  12.373 74.352 12.901 75.72 ;
     RECT  12.853 76.752 12.901 76.824 ;
     RECT  12.901 76.752 12.949 77.352 ;
     RECT  12.757 78.432 12.949 84.072 ;
     RECT  12.908 86.208 12.995 86.232 ;
     RECT  11.221 6.624 13.021 7.176 ;
     RECT  12.841 3.456 13.208 5.016 ;
     RECT  13.021 6.624 13.208 7.656 ;
     RECT  12.733 24.192 13.208 26.808 ;
     RECT  11.653 29.28 13.208 29.304 ;
     RECT  11.869 30.912 13.208 32.568 ;
     RECT  10.789 33.84 13.208 33.864 ;
     RECT  12.373 34.944 13.208 40.92 ;
     RECT  12.757 41.952 13.208 44.376 ;
     RECT  12.709 45.504 13.208 46.872 ;
     RECT  12.769 48.528 13.208 48.984 ;
     RECT  10.645 50.4 13.208 50.424 ;
     RECT  10.213 53.568 13.208 53.592 ;
     RECT  12.517 56.256 13.208 56.568 ;
     RECT  13.057 58.224 13.208 58.248 ;
     RECT  10.865 63.552 13.208 63.576 ;
     RECT  8.104 65.76 13.208 65.784 ;
     RECT  12.229 73.248 13.208 73.272 ;
     RECT  12.901 74.352 13.208 75.768 ;
     RECT  12.949 76.752 13.208 84.072 ;
     RECT  13.208 2.148 13.429 84.252 ;
     RECT  13.429 2.148 13.504 84.36 ;
     RECT  13.504 76.752 13.619 84.36 ;
     RECT  13.504 45.408 13.673 46.872 ;
     RECT  13.045 1.152 13.781 1.176 ;
     RECT  13.964 86.208 14.051 86.232 ;
     RECT  13.504 52.224 14.533 54.408 ;
     RECT  13.504 56.256 14.569 56.664 ;
     RECT  14.569 56.256 14.605 57.336 ;
     RECT  13.504 58.368 14.605 58.392 ;
     RECT  13.619 76.752 14.641 83.88 ;
     RECT  14.533 9.36 14.677 9.384 ;
     RECT  13.504 30.912 14.677 32.568 ;
     RECT  13.504 33.792 14.677 44.376 ;
     RECT  13.504 73.248 14.677 75.768 ;
     RECT  14.641 76.752 14.677 83.928 ;
     RECT  13.504 3.696 14.785 5.544 ;
     RECT  14.605 56.256 14.785 58.392 ;
     RECT  14.785 3.6 14.857 5.544 ;
     RECT  13.504 29.28 15.077 29.304 ;
     RECT  14.677 73.248 15.109 83.928 ;
     RECT  13.504 6.528 15.145 7.656 ;
     RECT  14.677 8.784 15.145 9.384 ;
     RECT  15.109 72.816 15.205 83.928 ;
     RECT  15.109 27.936 15.217 27.96 ;
     RECT  14.785 55.968 15.253 58.392 ;
     RECT  15.205 72.192 15.301 83.928 ;
     RECT  15.301 71.712 15.541 83.928 ;
     RECT  14.857 3.552 15.577 5.544 ;
     RECT  15.145 6.528 15.577 9.384 ;
     RECT  13.504 50.4 15.587 50.424 ;
     RECT  13.673 45.408 15.685 46.776 ;
     RECT  13.504 47.904 15.685 49.368 ;
     RECT  15.685 45.408 15.733 49.368 ;
     RECT  13.504 23.808 15.757 26.808 ;
     RECT  15.685 62.016 15.757 62.232 ;
     RECT  15.253 55.536 15.793 58.392 ;
     RECT  15.757 62.016 15.829 62.28 ;
     RECT  15.181 29.328 15.925 29.352 ;
     RECT  14.677 30.912 15.925 44.376 ;
     RECT  14.533 51.552 15.937 54.408 ;
     RECT  15.793 55.536 15.937 58.488 ;
     RECT  15.829 62.016 16.021 62.328 ;
     RECT  16.021 61.728 16.045 62.328 ;
     RECT  15.937 51.552 16.081 58.488 ;
     RECT  15.733 45.408 16.163 49.608 ;
     RECT  16.045 60.816 16.225 62.328 ;
     RECT  16.081 51.552 16.259 59.064 ;
     RECT  15.757 23.328 16.261 26.808 ;
     RECT  15.217 27.936 16.261 28.248 ;
     RECT  16.259 51.696 16.357 59.064 ;
     RECT  16.225 60.672 16.357 62.328 ;
     RECT  15.541 71.712 16.373 84.216 ;
     RECT  16.309 13.392 16.405 13.656 ;
     RECT  16.405 13.344 16.499 13.656 ;
     RECT  16.261 23.328 16.585 28.248 ;
     RECT  15.925 29.328 16.585 44.376 ;
     RECT  13.993 1.728 16.693 1.752 ;
     RECT  16.693 1.728 16.787 1.8 ;
     RECT  16.837 69.84 16.885 69.864 ;
     RECT  15.577 3.552 16.909 9.384 ;
     RECT  16.885 69.264 16.933 69.864 ;
     RECT  16.741 17.424 16.981 17.448 ;
     RECT  17.017 0.576 17.053 0.6 ;
     RECT  16.933 68.736 17.413 69.864 ;
     RECT  17.413 68.16 17.461 69.864 ;
     RECT  17.053 0.48 17.557 0.6 ;
     RECT  16.787 1.728 17.557 1.752 ;
     RECT  16.909 3.408 17.557 9.384 ;
     RECT  13.504 65.76 17.797 65.784 ;
     RECT  16.163 45.408 17.809 49.56 ;
     RECT  16.585 23.328 17.845 44.376 ;
     RECT  17.809 45.408 17.845 50.376 ;
     RECT  17.461 68.16 18.085 70.584 ;
     RECT  17.845 23.328 18.133 50.376 ;
     RECT  16.357 51.696 18.133 62.328 ;
     RECT  16.499 13.344 18.229 13.416 ;
     RECT  16.081 85.488 18.253 85.512 ;
     RECT  17.557 0.48 18.608 1.752 ;
     RECT  17.557 3.408 18.608 9.528 ;
     RECT  15.829 12.24 18.608 12.264 ;
     RECT  18.229 13.344 18.608 13.944 ;
     RECT  16.981 16.8 18.608 17.448 ;
     RECT  16.357 19.056 18.608 19.08 ;
     RECT  16.309 21.408 18.608 21.432 ;
     RECT  18.133 23.328 18.608 62.328 ;
     RECT  13.504 63.648 18.608 63.672 ;
     RECT  16.693 64.656 18.608 64.68 ;
     RECT  17.797 65.76 18.608 65.976 ;
     RECT  18.085 68.112 18.608 70.584 ;
     RECT  16.373 71.712 18.608 83.88 ;
     RECT  18.469 84.912 18.608 84.936 ;
     RECT  18.608 0.48 18.707 84.936 ;
     RECT  18.707 0.48 18.712 84.252 ;
     RECT  18.712 0.48 18.904 83.982 ;
     RECT  18.904 68.112 19.379 83.928 ;
     RECT  18.904 23.328 19.897 62.328 ;
     RECT  18.904 63.648 19.897 63.672 ;
     RECT  18.904 64.656 19.897 64.728 ;
     RECT  19.717 84.96 19.937 84.984 ;
     RECT  18.904 0.48 20.041 1.752 ;
     RECT  18.904 21.408 20.149 21.912 ;
     RECT  18.904 65.76 20.197 65.976 ;
     RECT  20.197 65.76 20.245 66.552 ;
     RECT  20.149 21.072 20.293 21.912 ;
     RECT  20.041 0.48 20.435 1.8 ;
     RECT  20.257 85.488 20.435 85.512 ;
     RECT  20.245 65.76 20.437 67.032 ;
     RECT  19.379 68.112 20.437 83.88 ;
     RECT  20.437 65.76 20.473 83.88 ;
     RECT  20.473 65.76 20.761 83.928 ;
     RECT  20.761 65.76 20.845 84.36 ;
     RECT  19.897 63.648 21.349 64.728 ;
     RECT  20.845 65.76 21.349 84.024 ;
     RECT  18.904 2.88 21.773 9.528 ;
     RECT  18.904 19.056 21.805 19.08 ;
     RECT  20.293 20.16 21.805 21.912 ;
     RECT  19.897 23.328 22.165 62.52 ;
     RECT  21.805 19.056 22.536 21.912 ;
     RECT  22.165 23.232 22.536 62.52 ;
     RECT  21.349 63.648 22.536 84.024 ;
     RECT  22.536 19.056 22.709 84.024 ;
     RECT  21.913 10.8 22.781 10.824 ;
     RECT  18.904 16.8 22.853 17.352 ;
     RECT  22.709 19.056 22.853 20.136 ;
     RECT  22.709 21.408 22.853 84.024 ;
     RECT  22.853 20.112 22.876 20.136 ;
     RECT  22.844 85.488 22.931 85.512 ;
     RECT  23.372 86.208 23.459 86.232 ;
     RECT  20.435 0.48 23.509 1.752 ;
     RECT  23.509 0.48 24.008 1.992 ;
     RECT  21.773 3.024 24.008 9.528 ;
     RECT  18.904 12.24 24.008 12.264 ;
     RECT  18.904 13.344 24.008 13.944 ;
     RECT  22.853 16.8 24.008 17.208 ;
     RECT  22.853 19.056 24.008 19.08 ;
     RECT  22.853 21.408 24.008 83.928 ;
     RECT  24.008 21.408 24.112 84.252 ;
     RECT  24.008 0.48 24.2 19.992 ;
     RECT  24.2 0.48 24.304 20.262 ;
     RECT  24.112 21.408 24.304 83.982 ;
     RECT  24.304 16.8 24.401 17.208 ;
     RECT  24.304 0.48 24.419 2.28 ;
     RECT  24.304 3.36 24.437 9.528 ;
     RECT  24.437 3.408 24.725 9.528 ;
     RECT  24.373 85.488 25.085 85.512 ;
     RECT  24.304 12.24 26.129 12.264 ;
     RECT  24.725 3.504 26.737 9.528 ;
     RECT  26.737 3.456 27.097 9.528 ;
     RECT  24.419 0.48 27.169 1.848 ;
     RECT  27.097 3.12 27.169 9.528 ;
     RECT  27.169 0.48 27.641 9.528 ;
     RECT  27.641 0.48 28.969 2.088 ;
     RECT  24.304 21.408 29.125 83.88 ;
     RECT  28.969 0.192 29.315 2.088 ;
     RECT  29.315 0.48 29.365 2.088 ;
     RECT  27.641 3.12 29.365 9.528 ;
     RECT  29.365 0.48 29.408 9.528 ;
     RECT  24.401 16.8 29.408 16.824 ;
     RECT  24.304 19.056 29.408 19.08 ;
     RECT  29.125 21.408 29.408 84.072 ;
     RECT  29.408 21.408 29.512 84.252 ;
     RECT  29.408 0.48 29.6 19.992 ;
     RECT  29.6 0.48 29.704 20.262 ;
     RECT  29.704 0.48 30.697 9.528 ;
     RECT  29.512 21.408 30.773 84.072 ;
     RECT  30.697 0.192 30.899 9.528 ;
     RECT  30.899 0.48 30.953 9.528 ;
     RECT  30.773 21.408 32.137 83.88 ;
     RECT  30.953 0.48 32.245 2.664 ;
     RECT  30.953 3.648 32.245 9.528 ;
     RECT  31.777 85.488 32.339 85.512 ;
     RECT  32.137 21.408 33.349 84.072 ;
     RECT  33.349 21.408 34.373 84.984 ;
     RECT  34.373 21.888 34.444 84.984 ;
     RECT  32.245 0.48 34.808 9.528 ;
     RECT  34.513 10.8 34.808 10.824 ;
     RECT  29.704 16.8 34.808 16.824 ;
     RECT  29.704 19.056 34.808 19.08 ;
     RECT  34.444 21.888 34.912 84.252 ;
     RECT  34.808 0.48 35 19.992 ;
     RECT  35 0.48 35.104 20.262 ;
     RECT  34.909 86.208 35.219 86.232 ;
     RECT  35.372 85.488 35.459 85.512 ;
     RECT  34.912 21.888 35.747 84.072 ;
     RECT  35.104 0.48 35.881 9.528 ;
     RECT  35.881 0.192 36.131 9.528 ;
     RECT  36.469 84.96 36.893 84.984 ;
     RECT  35.747 21.888 37.073 83.88 ;
     RECT  35.104 19.056 37.469 19.08 ;
     RECT  37.073 22.464 37.525 83.88 ;
     RECT  37.525 22.464 38.509 83.928 ;
     RECT  38.509 22.464 38.593 84.024 ;
     RECT  38.041 85.488 38.627 85.512 ;
     RECT  38.593 22.464 39.025 83.928 ;
     RECT  39.068 86.208 39.155 86.232 ;
     RECT  39.025 22.464 40.021 83.88 ;
     RECT  39.973 85.488 40.169 85.512 ;
     RECT  36.131 0.48 40.208 9.528 ;
     RECT  40.021 22.464 40.208 83.928 ;
     RECT  40.208 22.464 40.312 84.252 ;
     RECT  40.208 0.48 40.4 19.992 ;
     RECT  40.4 0.48 40.504 20.262 ;
     RECT  40.312 22.464 40.504 83.982 ;
     RECT  40.504 0.48 40.529 9.528 ;
     RECT  40.529 3.984 41.393 9.528 ;
     RECT  41.393 3.984 41.501 9.384 ;
     RECT  40.529 0.48 42.109 2.856 ;
     RECT  41.501 3.984 42.109 9.288 ;
     RECT  41.701 85.488 42.133 85.512 ;
     RECT  40.504 22.464 42.181 83.88 ;
     RECT  42.133 85.488 42.371 85.56 ;
     RECT  42.181 22.464 42.755 84.024 ;
     RECT  42.755 22.464 42.805 83.928 ;
     RECT  42.371 85.536 43.301 85.56 ;
     RECT  42.805 22.464 43.619 83.88 ;
     RECT  43.619 64.656 43.813 83.88 ;
     RECT  44.233 86.16 44.867 86.184 ;
     RECT  42.109 0.48 45.608 9.288 ;
     RECT  43.813 64.656 45.608 83.928 ;
     RECT  45.608 0.48 45.8 19.992 ;
     RECT  45.608 64.656 45.877 84.252 ;
     RECT  45.8 0.48 45.904 20.262 ;
     RECT  45.877 64.656 46.145 84.408 ;
     RECT  46.145 64.656 47.477 84.216 ;
     RECT  47.477 64.656 48.517 83.88 ;
     RECT  48.476 86.208 48.563 86.232 ;
     RECT  48.517 64.656 48.601 84.36 ;
     RECT  49.045 85.488 49.385 85.512 ;
     RECT  50.605 85.488 50.689 85.512 ;
     RECT  45.904 0.48 51.008 9.288 ;
     RECT  48.601 64.656 51.008 83.88 ;
     RECT  51.008 64.656 51.109 84.252 ;
     RECT  51.008 0.48 51.2 19.992 ;
     RECT  51.109 64.656 51.221 84.984 ;
     RECT  51.2 0.48 51.304 20.262 ;
     RECT  51.221 64.656 52.211 84.888 ;
     RECT  52.211 64.656 52.697 83.976 ;
     RECT  52.652 86.208 52.739 86.232 ;
     RECT  54.236 84.96 54.323 84.984 ;
     RECT  52.697 65.232 54.745 83.976 ;
     RECT  51.304 0.48 55.177 9.288 ;
     RECT  54.745 65.232 55.397 84.072 ;
     RECT  55.177 0.48 55.501 9.816 ;
     RECT  54.097 10.848 55.501 10.872 ;
     RECT  55.765 85.488 55.865 85.512 ;
     RECT  55.397 68.64 56.245 84.072 ;
     RECT  56.245 68.64 56.387 84.408 ;
     RECT  55.501 0.48 56.408 10.872 ;
     RECT  55.397 65.232 56.408 67.656 ;
     RECT  56.387 68.64 56.408 84.252 ;
     RECT  56.408 65.232 56.512 84.252 ;
     RECT  56.408 0.48 56.6 19.992 ;
     RECT  56.6 0.48 56.704 20.262 ;
     RECT  56.512 65.232 56.704 84.072 ;
     RECT  56.869 85.488 56.953 85.512 ;
     RECT  56.704 68.64 57.731 84.072 ;
     RECT  57.884 86.208 57.971 86.232 ;
     RECT  57.731 68.64 59.509 83.928 ;
     RECT  59.509 68.64 59.753 84.408 ;
     RECT  60.997 86.208 61.085 86.232 ;
     RECT  61.573 85.488 61.66 85.512 ;
     RECT  56.704 0.48 61.808 10.872 ;
     RECT  56.704 65.232 61.808 67.608 ;
     RECT  59.753 68.64 61.808 83.88 ;
     RECT  61.808 65.232 61.912 84.252 ;
     RECT  61.808 0.48 62 19.992 ;
     RECT  62 0.48 62.104 20.262 ;
     RECT  61.912 65.232 62.104 83.982 ;
     RECT  63.644 85.488 63.731 85.512 ;
     RECT  64.741 85.488 64.937 85.512 ;
     RECT  62.104 68.64 66.545 83.88 ;
     RECT  66.301 85.488 66.851 85.512 ;
     RECT  62.104 0.48 67.208 10.872 ;
     RECT  62.104 65.232 67.208 67.656 ;
     RECT  66.545 68.64 67.208 83.928 ;
     RECT  67.208 65.232 67.312 84.252 ;
     RECT  67.208 0.48 67.4 19.992 ;
     RECT  67.4 0.48 67.504 20.262 ;
     RECT  67.312 65.232 67.504 83.982 ;
     RECT  67.861 85.488 68.177 85.512 ;
     RECT  67.504 68.64 68.965 83.88 ;
     RECT  67.504 0.48 69.469 10.872 ;
     RECT  69.433 85.488 69.517 85.512 ;
     RECT  69.469 0.192 69.587 10.872 ;
     RECT  69.587 0.48 72.608 10.872 ;
     RECT  67.504 65.232 72.608 67.608 ;
     RECT  68.965 68.64 72.608 83.928 ;
     RECT  72.608 65.232 72.712 84.252 ;
     RECT  72.608 0.48 72.8 19.992 ;
     RECT  72.8 0.48 72.904 20.262 ;
     RECT  72.712 65.232 72.904 83.982 ;
     RECT  72.037 85.488 73.253 85.512 ;
     RECT  72.904 68.64 74.581 83.88 ;
     RECT  74.581 68.64 74.675 83.928 ;
     RECT  74.653 85.488 74.737 85.512 ;
     RECT  74.675 68.64 77.533 83.88 ;
     RECT  72.904 0.48 77.821 10.872 ;
     RECT  77.785 85.488 77.939 85.512 ;
     RECT  77.821 0.48 78.008 10.92 ;
     RECT  72.904 65.232 78.008 67.608 ;
     RECT  77.533 68.64 78.008 83.928 ;
     RECT  78.008 0.48 78.2 19.992 ;
     RECT  78.2 0.48 78.304 20.262 ;
     RECT  78.008 65.232 78.304 84.252 ;
     RECT  78.304 68.64 78.325 84.252 ;
     RECT  78.325 68.64 78.467 84.36 ;
     RECT  79.909 85.488 80.003 85.512 ;
     RECT  78.467 68.64 80.389 83.928 ;
     RECT  78.304 0.48 80.453 10.872 ;
     RECT  80.389 68.64 81.029 84.408 ;
     RECT  81.029 68.64 82.501 83.88 ;
     RECT  80.453 0.528 83.408 10.872 ;
     RECT  78.304 65.232 83.408 67.608 ;
     RECT  82.501 68.64 83.408 83.928 ;
     RECT  83.408 65.232 83.516 84.252 ;
     RECT  83.408 0.528 83.6 19.992 ;
     RECT  83.516 65.232 83.603 84.408 ;
     RECT  83.6 0.528 83.704 20.262 ;
     RECT  83.603 65.232 83.704 83.982 ;
     RECT  84.037 85.488 84.125 85.512 ;
     RECT  83.704 68.64 84.709 83.928 ;
     RECT  85.621 85.488 85.708 85.512 ;
     RECT  86.677 84.96 86.897 84.984 ;
     RECT  87.217 85.488 87.395 85.512 ;
     RECT  83.704 0.528 88.808 10.872 ;
     RECT  83.704 65.232 88.808 67.608 ;
     RECT  84.709 68.64 88.808 83.88 ;
     RECT  88.748 84.96 88.808 84.984 ;
     RECT  88.808 65.232 88.835 84.984 ;
     RECT  88.835 65.232 88.912 84.252 ;
     RECT  88.808 0.528 89 19.992 ;
     RECT  89 0.528 89.104 20.262 ;
     RECT  88.912 65.232 89.104 83.982 ;
     RECT  89.104 68.64 91.325 83.88 ;
     RECT  91.868 85.488 91.955 85.512 ;
     RECT  92.965 85.488 93.161 85.512 ;
     RECT  89.104 0.528 94.208 10.872 ;
     RECT  89.104 65.232 94.208 67.608 ;
     RECT  91.325 68.64 94.208 83.832 ;
     RECT  94.208 0.528 94.4 19.992 ;
     RECT  94.4 0.528 94.504 20.262 ;
     RECT  94.208 65.232 94.504 84.252 ;
     RECT  94.504 0.528 94.601 10.872 ;
     RECT  94.504 68.64 95.077 84.252 ;
     RECT  95.077 68.64 95.285 84.408 ;
     RECT  94.601 0.528 96.545 6.936 ;
     RECT  97.141 84.96 97.373 84.984 ;
     RECT  95.285 68.64 98.021 83.832 ;
     RECT  94.601 7.968 98.093 10.872 ;
     RECT  98.197 85.488 98.284 85.512 ;
     RECT  96.545 0.528 99.029 0.552 ;
     RECT  99.253 85.488 99.389 85.512 ;
     RECT  96.545 1.536 99.608 6.936 ;
     RECT  98.093 8.016 99.608 10.872 ;
     RECT  94.504 65.232 99.608 67.608 ;
     RECT  98.021 68.64 99.608 76.296 ;
     RECT  98.021 77.28 99.608 83.832 ;
     RECT  99.608 65.232 99.712 84.252 ;
     RECT  99.608 1.536 99.8 19.992 ;
     RECT  99.8 1.536 99.904 20.262 ;
     RECT  99.712 65.232 99.904 83.982 ;
     RECT  99.904 68.64 100.613 76.2 ;
     RECT  99.904 65.232 101.075 67.608 ;
     RECT  99.904 77.28 101.317 83.832 ;
     RECT  99.904 8.016 101.333 10.872 ;
     RECT  101.333 8.016 101.945 8.04 ;
     RECT  99.904 1.536 101.969 6.936 ;
     RECT  101.969 1.152 102.053 6.936 ;
     RECT  101.317 77.28 102.181 83.88 ;
     RECT  102.373 85.488 102.521 85.512 ;
     RECT  101.333 9.264 103.133 10.872 ;
     RECT  102.181 77.28 103.417 84.072 ;
     RECT  103.417 77.28 103.501 84.936 ;
     RECT  102.053 1.536 103.573 6.936 ;
     RECT  103.573 1.152 103.853 6.936 ;
     RECT  104.425 85.488 104.531 85.512 ;
     RECT  103.853 1.536 105.008 6.936 ;
     RECT  103.133 9.792 105.008 10.872 ;
     RECT  101.075 65.232 105.008 65.256 ;
     RECT  101.075 66.528 105.008 67.608 ;
     RECT  100.613 69.216 105.008 76.2 ;
     RECT  103.501 77.28 105.008 84.072 ;
     RECT  105.008 1.536 105.2 19.992 ;
     RECT  105.2 1.536 105.304 20.262 ;
     RECT  105.008 65.232 105.304 84.252 ;
     RECT  105.304 77.28 105.541 84.252 ;
     RECT  105.541 77.28 105.628 84.408 ;
     RECT  105.304 1.536 105.653 1.752 ;
     RECT  106.045 85.488 106.129 85.512 ;
     RECT  105.653 1.728 106.585 1.752 ;
     RECT  105.304 2.736 106.585 6.936 ;
     RECT  105.628 77.28 106.633 84.216 ;
     RECT  105.304 69.216 106.661 73.32 ;
     RECT  106.633 77.28 106.957 83.88 ;
     RECT  43.619 22.464 106.981 63.528 ;
     RECT  105.304 9.792 107.233 10.872 ;
     RECT  106.585 1.728 107.281 6.936 ;
     RECT  107.281 2.688 107.561 6.936 ;
     RECT  107.593 0.576 107.795 0.6 ;
     RECT  106.957 77.28 108.661 83.832 ;
     RECT  108.661 77.28 108.893 84.408 ;
     RECT  108.853 7.968 108.965 7.992 ;
     RECT  108.277 1.728 109.249 1.752 ;
     RECT  109.249 1.728 109.379 1.8 ;
     RECT  109.676 85.488 109.763 85.512 ;
     RECT  109.379 1.728 110.408 1.752 ;
     RECT  107.561 2.832 110.408 6.936 ;
     RECT  107.233 9.792 110.408 11.688 ;
     RECT  109.033 16.8 110.408 16.824 ;
     RECT  106.369 19.056 110.408 19.08 ;
     RECT  105.304 65.232 110.408 65.256 ;
     RECT  105.304 66.528 110.408 67.608 ;
     RECT  106.661 69.216 110.408 72.792 ;
     RECT  105.304 74.352 110.408 76.104 ;
     RECT  108.893 77.28 110.408 83.832 ;
     RECT  110.408 1.728 110.6 19.992 ;
     RECT  110.6 1.728 110.704 20.262 ;
     RECT  110.408 65.232 110.704 84.252 ;
     RECT  106.981 21.888 110.725 63.528 ;
     RECT  110.704 77.28 110.773 84.252 ;
     RECT  110.725 21.36 111.085 63.528 ;
     RECT  110.773 77.28 111.305 84.408 ;
     RECT  110.704 69.216 111.521 72.792 ;
     RECT  111.305 77.28 111.629 83.832 ;
     RECT  111.781 85.488 111.917 85.512 ;
     RECT  110.704 16.8 112.201 16.824 ;
     RECT  111.085 20.784 113.353 63.528 ;
     RECT  110.704 2.736 113.533 7.032 ;
     RECT  110.704 1.728 113.555 1.752 ;
     RECT  110.704 14.496 113.749 14.52 ;
     RECT  110.704 66.528 113.933 67.608 ;
     RECT  113.173 17.904 113.965 17.928 ;
     RECT  110.704 19.056 114.145 19.08 ;
     RECT  114.145 19.056 114.253 19.128 ;
     RECT  113.353 20.304 114.253 63.528 ;
     RECT  113.533 2.736 114.397 7.368 ;
     RECT  113.965 17.904 114.469 18.024 ;
     RECT  114.253 19.056 114.469 63.528 ;
     RECT  110.704 74.352 114.577 76.104 ;
     RECT  111.629 77.28 114.577 80.424 ;
     RECT  111.629 81.408 114.577 83.832 ;
     RECT  112.813 0.576 114.611 0.6 ;
     RECT  114.397 2.736 114.757 8.232 ;
     RECT  110.704 9.792 114.757 11.688 ;
     RECT  114.908 85.488 114.995 85.512 ;
     RECT  112.201 16.272 115.117 16.824 ;
     RECT  115.045 1.728 115.129 1.752 ;
     RECT  114.757 2.736 115.808 11.688 ;
     RECT  113.749 13.92 115.808 14.52 ;
     RECT  115.117 16.272 115.808 16.872 ;
     RECT  114.469 17.904 115.808 63.528 ;
     RECT  110.704 65.232 115.808 65.256 ;
     RECT  113.933 66.528 115.808 67.56 ;
     RECT  111.521 69.216 115.808 71.64 ;
     RECT  111.521 72.672 115.808 72.792 ;
     RECT  114.577 74.352 115.808 76.248 ;
     RECT  114.577 77.28 115.808 83.832 ;
     RECT  115.808 65.232 115.912 84.252 ;
     RECT  115.808 2.148 116.104 63.528 ;
     RECT  115.912 65.232 116.104 83.982 ;
     RECT  116.005 85.488 116.201 85.512 ;
     RECT  116.104 77.28 116.417 83.832 ;
     RECT  115.573 1.152 116.489 1.176 ;
     RECT  116.104 2.736 116.579 11.688 ;
     RECT  116.579 2.736 116.669 9.096 ;
     RECT  116.104 69.216 116.813 71.64 ;
     RECT  116.813 69.792 117.029 71.64 ;
     RECT  116.104 17.904 117.216 63.528 ;
     RECT  117.216 17.904 117.635 22.248 ;
     RECT  116.579 10.704 117.731 11.688 ;
     RECT  116.104 16.272 118.067 16.872 ;
     RECT  116.669 2.736 118.069 8.232 ;
     RECT  116.104 74.352 118.145 76.248 ;
     RECT  118.069 2.736 118.153 9.096 ;
     RECT  118.069 85.488 118.181 85.512 ;
     RECT  117.635 17.904 118.307 19.8 ;
     RECT  118.117 10.272 118.361 10.296 ;
     RECT  117.216 23.232 118.361 62.424 ;
     RECT  117.029 70.368 118.469 71.64 ;
     RECT  118.361 26.592 118.505 62.424 ;
     RECT  117.635 20.784 118.649 22.248 ;
     RECT  118.604 86.208 118.691 86.232 ;
     RECT  118.067 16.56 118.721 16.872 ;
     RECT  118.307 17.904 118.739 19.656 ;
     RECT  118.739 17.904 118.835 19.416 ;
     RECT  118.505 26.976 118.901 62.424 ;
     RECT  118.153 2.736 118.931 8.232 ;
     RECT  116.417 81.408 119.077 83.832 ;
     RECT  118.649 20.784 119.171 22.104 ;
     RECT  118.901 44.448 119.189 62.424 ;
     RECT  118.901 26.976 119.225 43.32 ;
     RECT  116.104 13.104 119.267 14.856 ;
     RECT  119.267 13.104 119.315 13.944 ;
     RECT  119.225 30.384 119.315 43.32 ;
     RECT  119.189 44.448 119.333 58.2 ;
     RECT  118.721 16.8 119.369 16.872 ;
     RECT  118.931 8.208 119.401 8.232 ;
     RECT  119.171 20.784 119.411 22.056 ;
     RECT  119.315 31.392 119.459 43.32 ;
     RECT  119.401 8.208 119.485 9.096 ;
     RECT  119.315 13.92 119.507 13.944 ;
     RECT  119.459 31.392 119.507 33.144 ;
     RECT  119.459 34.368 119.513 43.32 ;
     RECT  119.189 59.424 119.513 62.424 ;
     RECT  119.333 44.544 119.549 58.2 ;
     RECT  119.513 59.52 119.549 62.424 ;
     RECT  119.369 16.8 119.555 16.824 ;
     RECT  119.549 44.544 119.585 45.144 ;
     RECT  119.549 46.176 119.621 58.2 ;
     RECT  116.593 1.728 119.653 1.752 ;
     RECT  118.931 2.736 119.653 7.128 ;
     RECT  119.507 31.392 119.657 32.856 ;
     RECT  119.621 46.176 119.657 58.104 ;
     RECT  119.549 59.52 119.657 62.328 ;
     RECT  118.361 23.232 119.747 25.464 ;
     RECT  119.657 59.52 119.765 62.136 ;
     RECT  119.411 21.792 119.795 22.056 ;
     RECT  119.411 20.784 119.801 20.808 ;
     RECT  119.585 44.544 119.801 45.048 ;
     RECT  119.765 59.904 119.801 62.136 ;
     RECT  116.104 72.672 119.837 72.792 ;
     RECT  117.731 11.664 119.843 11.688 ;
     RECT  118.835 17.904 119.873 19.08 ;
     RECT  119.657 46.272 119.873 58.104 ;
     RECT  119.873 19.056 119.891 19.08 ;
     RECT  119.653 1.728 119.909 7.128 ;
     RECT  119.225 26.976 119.909 28.92 ;
     RECT  119.513 34.368 119.909 43.224 ;
     RECT  119.747 23.328 119.939 25.464 ;
     RECT  119.939 23.328 119.945 24.12 ;
     RECT  119.909 38.208 119.945 43.224 ;
     RECT  119.873 17.904 119.981 17.928 ;
     RECT  119.939 25.44 119.981 25.464 ;
     RECT  119.945 38.208 119.981 42.936 ;
     RECT  119.795 21.792 119.987 22.008 ;
     RECT  119.905 10.8 120.017 10.824 ;
     RECT  119.485 8.208 120.035 8.232 ;
     RECT  119.945 23.904 120.035 24.12 ;
     RECT  119.981 40.896 120.053 42.936 ;
     RECT  119.987 21.984 120.083 22.008 ;
     RECT  120.035 24.096 120.083 24.12 ;
     RECT  119.909 27.456 120.161 28.92 ;
     RECT  119.801 45.024 120.161 45.048 ;
     RECT  119.077 81.216 120.181 83.832 ;
     RECT  120.668 86.208 120.755 86.232 ;
     RECT  119.909 1.728 120.805 1.752 ;
     RECT  120.805 1.152 121.025 1.752 ;
     RECT  121.025 1.728 121.208 1.752 ;
     RECT  119.909 2.736 121.208 7.128 ;
     RECT  120.161 27.552 121.208 28.92 ;
     RECT  119.315 30.384 121.208 30.408 ;
     RECT  119.657 31.968 121.208 32.856 ;
     RECT  119.909 34.368 121.208 37.08 ;
     RECT  119.981 38.208 121.208 39.864 ;
     RECT  120.053 40.896 121.208 41.592 ;
     RECT  120.053 42.912 121.208 42.936 ;
     RECT  119.873 46.272 121.208 57.384 ;
     RECT  119.801 60 121.208 62.136 ;
     RECT  116.104 65.232 121.208 65.256 ;
     RECT  116.104 66.528 121.208 67.56 ;
     RECT  118.469 70.944 121.208 71.64 ;
     RECT  119.837 72.672 121.208 72.744 ;
     RECT  118.145 74.352 121.208 75.528 ;
     RECT  116.417 77.28 121.208 80.136 ;
     RECT  120.181 81.216 121.208 83.88 ;
     RECT  121.208 1.728 121.237 84.252 ;
     RECT  121.237 1.728 121.421 84.408 ;
     RECT  121.421 1.728 121.504 84.312 ;
     RECT  121.504 60 121.565 60.888 ;
     RECT  121.504 37.056 121.709 37.08 ;
     RECT  121.504 47.184 121.709 56.28 ;
     RECT  121.709 47.184 121.745 47.928 ;
     RECT  121.504 77.28 121.781 83.256 ;
     RECT  121.741 85.488 121.825 85.512 ;
     RECT  121.565 60 121.889 60.024 ;
     RECT  121.504 28.272 122.141 28.536 ;
     RECT  121.504 84.288 122.177 84.312 ;
     RECT  121.504 31.968 122.285 32.76 ;
     RECT  121.504 3.072 122.321 7.128 ;
     RECT  121.504 38.208 122.321 38.232 ;
     RECT  121.504 34.944 122.573 35.544 ;
     RECT  121.781 77.808 122.573 83.256 ;
     RECT  122.285 31.968 122.825 32.328 ;
     RECT  122.573 81.408 122.869 83.256 ;
     RECT  122.321 3.456 122.897 7.128 ;
     RECT  121.504 1.728 122.963 1.752 ;
     RECT  122.825 31.968 123.149 32.28 ;
     RECT  123.149 32.256 123.221 32.28 ;
     RECT  121.504 65.232 123.221 65.256 ;
     RECT  122.573 34.944 123.329 35.448 ;
     RECT  121.504 57.36 123.401 57.384 ;
     RECT  122.141 28.272 123.473 28.296 ;
     RECT  121.709 49.2 123.473 56.28 ;
     RECT  122.897 3.696 123.689 7.128 ;
     RECT  123.445 1.152 123.725 1.176 ;
     RECT  121.504 41.184 123.725 41.544 ;
     RECT  123.473 49.2 123.725 55.8 ;
     RECT  123.725 49.2 123.797 51.96 ;
     RECT  123.797 49.2 123.869 51.72 ;
     RECT  123.869 50.544 124.265 51.72 ;
     RECT  123.725 53.04 124.301 53.304 ;
     RECT  123.725 54.336 124.337 55.8 ;
     RECT  121.504 30.384 124.409 30.408 ;
     RECT  121.745 47.184 124.409 47.208 ;
     RECT  123.329 35.232 124.445 35.448 ;
     RECT  124.265 50.544 124.625 50.712 ;
     RECT  124.265 51.696 124.625 51.72 ;
     RECT  121.504 74.352 124.697 75.528 ;
     RECT  122.869 81.408 124.841 83.88 ;
     RECT  123.869 49.2 124.877 49.368 ;
     RECT  123.973 1.728 125.555 1.752 ;
     RECT  123.689 4.224 125.845 7.128 ;
     RECT  125.893 86.208 125.98 86.232 ;
     RECT  125.917 0.192 126.083 0.216 ;
     RECT  124.877 49.344 126.529 49.368 ;
     RECT  125.845 4.128 126.565 7.128 ;
     RECT  126.565 1.728 126.608 1.752 ;
     RECT  126.565 3.312 126.608 7.128 ;
     RECT  124.445 35.232 126.608 35.256 ;
     RECT  123.725 41.52 126.608 41.544 ;
     RECT  121.504 42.864 126.608 42.888 ;
     RECT  126.529 49.344 126.608 49.512 ;
     RECT  124.625 50.544 126.608 50.568 ;
     RECT  124.301 53.28 126.608 53.304 ;
     RECT  124.337 54.912 126.608 55.8 ;
     RECT  121.504 66.528 126.608 67.56 ;
     RECT  121.504 70.944 126.608 71.64 ;
     RECT  121.504 72.672 126.608 72.744 ;
     RECT  124.697 74.352 126.608 74.952 ;
     RECT  122.573 77.808 126.608 80.136 ;
     RECT  124.841 81.408 126.608 83.208 ;
     RECT  126.469 84.384 126.608 84.408 ;
     RECT  126.608 1.728 126.904 84.408 ;
     RECT  126.904 53.28 126.965 53.304 ;
     RECT  126.904 84.384 126.965 84.408 ;
     RECT  126.904 3.312 127.001 6.072 ;
     RECT  126.904 35.232 127.145 35.256 ;
     RECT  126.904 78.336 127.253 80.136 ;
     RECT  127.253 78.336 127.289 78.984 ;
     RECT  127.001 3.648 127.433 6.072 ;
     RECT  126.904 1.728 127.621 1.752 ;
     RECT  127.621 1.152 127.865 1.752 ;
     RECT  127.289 78.336 128.54 78.936 ;
     RECT  127.253 80.064 128.54 80.136 ;
     RECT  126.904 81.408 128.581 83.208 ;
     RECT  128.54 78.336 128.771 80.136 ;
     RECT  127.433 4.224 128.833 6.072 ;
     RECT  128.833 4.032 129.121 6.072 ;
     RECT  126.904 7.104 129.121 7.128 ;
     RECT  126.904 55.776 129.305 55.8 ;
     RECT  126.904 70.944 129.341 71.64 ;
     RECT  129.049 85.488 129.395 85.512 ;
     RECT  126.904 49.488 129.593 49.512 ;
     RECT  129.121 4.032 129.665 7.128 ;
     RECT  129.665 4.032 129.697 6.072 ;
     RECT  128.771 80.064 129.877 80.136 ;
     RECT  128.581 81.408 129.877 83.304 ;
     RECT  129.877 80.064 129.961 83.352 ;
     RECT  127.865 1.728 130.307 1.752 ;
     RECT  126.904 66.528 130.349 67.56 ;
     RECT  129.697 3.456 130.529 6.072 ;
     RECT  128.771 78.336 130.565 78.936 ;
     RECT  130.561 85.488 130.691 85.512 ;
     RECT  130.417 0.528 130.787 0.552 ;
     RECT  130.529 3.456 131.029 5.496 ;
     RECT  131.065 0.192 131.315 0.216 ;
     RECT  131.713 1.728 132.008 1.752 ;
     RECT  131.029 3.408 132.008 5.496 ;
     RECT  129.665 7.104 132.008 7.128 ;
     RECT  130.349 66.528 132.008 66.552 ;
     RECT  130.349 67.536 132.008 67.56 ;
     RECT  129.341 70.944 132.008 70.968 ;
     RECT  126.904 72.672 132.008 72.696 ;
     RECT  126.904 74.352 132.008 74.952 ;
     RECT  130.565 78.432 132.008 78.936 ;
     RECT  129.961 80.064 132.008 83.304 ;
     RECT  132.008 1.728 132.112 84.252 ;
     RECT  132.112 1.728 132.304 83.982 ;
     RECT  132.304 7.104 132.545 7.128 ;
     RECT  132.304 80.064 132.725 83.256 ;
     RECT  132.725 81.408 132.841 83.256 ;
     RECT  132.304 3.408 132.869 4.68 ;
     RECT  132.304 78.432 133.013 78.936 ;
     RECT  132.304 74.352 133.445 74.376 ;
     RECT  133.013 78.912 133.553 78.936 ;
     RECT  133.585 84.96 133.811 84.984 ;
     RECT  132.841 81.408 134.381 83.16 ;
     RECT  132.869 4.656 134.597 4.68 ;
     RECT  132.869 3.408 134.633 3.576 ;
     RECT  132.725 80.064 135.245 80.088 ;
     RECT  134.381 81.408 135.317 82.632 ;
     RECT  134.633 3.552 135.349 3.576 ;
     RECT  132.304 1.728 135.493 1.752 ;
     RECT  135.349 3.552 135.601 3.672 ;
     RECT  132.304 66.528 135.641 66.552 ;
     RECT  135.493 1.152 135.713 1.752 ;
     RECT  134.821 83.808 135.713 83.832 ;
     RECT  135.317 81.696 135.877 82.632 ;
     RECT  132.304 70.944 136.253 70.968 ;
     RECT  132.304 72.672 136.289 72.696 ;
     RECT  135.877 81.696 136.393 83.496 ;
     RECT  136.933 84.96 137.117 84.984 ;
     RECT  136.405 76.32 137.221 76.344 ;
     RECT  136.393 81.504 137.221 83.496 ;
     RECT  135.601 3.408 137.293 3.672 ;
     RECT  135.713 1.728 137.408 1.752 ;
     RECT  137.293 3.408 137.408 4.152 ;
     RECT  132.304 67.536 137.408 67.56 ;
     RECT  137.221 76.272 137.408 76.344 ;
     RECT  136.556 78.624 137.408 78.648 ;
     RECT  137.221 81.504 137.408 83.832 ;
     RECT  137.408 1.728 137.512 84.252 ;
     RECT  137.512 1.728 137.704 83.982 ;
     RECT  137.704 3.408 137.765 4.152 ;
     RECT  137.765 4.128 137.945 4.152 ;
     RECT  137.941 85.488 138.269 85.512 ;
     RECT  137.704 1.728 138.305 1.752 ;
     RECT  137.704 76.272 138.737 76.344 ;
     RECT  138.737 76.272 138.809 76.296 ;
    LAYER M5 ;
     RECT  4.728 0.144 5.232 0.192 ;
     RECT  5.256 0.144 5.76 0.192 ;
     RECT  5.784 0.144 6.288 0.192 ;
     RECT  6.312 0.144 6.816 0.192 ;
     RECT  6.84 0.144 7.296 0.192 ;
     RECT  7.32 0.144 7.824 0.192 ;
     RECT  7.848 0.144 8.352 0.192 ;
     RECT  8.376 0.144 8.88 0.192 ;
     RECT  8.904 0.144 9.408 0.192 ;
     RECT  9.432 0.144 9.936 0.192 ;
     RECT  9.96 0.144 10.464 0.192 ;
     RECT  10.488 0.144 10.992 0.192 ;
     RECT  11.016 0.144 11.52 0.192 ;
     RECT  11.544 0.144 12.048 0.192 ;
     RECT  12.072 0.144 12.528 0.192 ;
     RECT  12.552 0.144 13.056 0.192 ;
     RECT  13.08 0.144 13.584 0.192 ;
     RECT  13.608 0.144 14.112 0.192 ;
     RECT  14.136 0.144 14.64 0.192 ;
     RECT  14.664 0.144 15.168 0.192 ;
     RECT  15.192 0.144 15.696 0.192 ;
     RECT  15.72 0.144 16.224 0.192 ;
     RECT  16.248 0.144 16.752 0.192 ;
     RECT  16.776 0.144 17.232 0.192 ;
     RECT  17.256 0.144 17.76 0.192 ;
     RECT  17.784 0.144 18.288 0.192 ;
     RECT  18.312 0.144 18.816 0.192 ;
     RECT  18.84 0.144 19.344 0.192 ;
     RECT  19.368 0.144 19.872 0.192 ;
     RECT  19.896 0.144 20.4 0.192 ;
     RECT  20.424 0.144 20.928 0.192 ;
     RECT  20.952 0.144 21.456 0.192 ;
     RECT  21.48 0.144 21.984 0.192 ;
     RECT  22.008 0.144 22.464 0.192 ;
     RECT  22.488 0.144 22.992 0.192 ;
     RECT  23.016 0.144 23.52 0.192 ;
     RECT  23.544 0.144 24.048 0.192 ;
     RECT  24.072 0.144 24.576 0.192 ;
     RECT  24.6 0.144 25.104 0.192 ;
     RECT  25.128 0.144 25.632 0.192 ;
     RECT  25.656 0.144 26.16 0.192 ;
     RECT  26.184 0.144 26.688 0.192 ;
     RECT  26.712 0.144 27.216 0.192 ;
     RECT  27.24 0.144 27.696 0.192 ;
     RECT  27.72 0.144 28.224 0.192 ;
     RECT  28.248 0.144 28.752 0.192 ;
     RECT  28.776 0.144 29.28 0.192 ;
     RECT  29.304 0.144 29.808 0.192 ;
     RECT  29.832 0.144 30.336 0.192 ;
     RECT  30.36 0.144 30.864 0.192 ;
     RECT  30.888 0.144 31.392 0.192 ;
     RECT  31.416 0.144 31.92 0.192 ;
     RECT  31.944 0.144 32.448 0.192 ;
     RECT  32.472 0.144 32.928 0.192 ;
     RECT  32.952 0.144 33.456 0.192 ;
     RECT  33.48 0.144 33.984 0.192 ;
     RECT  34.008 0.144 34.512 0.192 ;
     RECT  34.536 0.144 35.04 0.192 ;
     RECT  35.064 0.144 35.568 0.192 ;
     RECT  35.592 0.144 36.096 0.192 ;
     RECT  36.12 0.144 36.624 0.192 ;
     RECT  36.648 0.144 37.152 0.192 ;
     RECT  37.176 0.144 37.68 0.192 ;
     RECT  37.704 0.144 38.16 0.192 ;
     RECT  38.184 0.144 38.688 0.192 ;
     RECT  38.712 0.144 39.216 0.192 ;
     RECT  39.24 0.144 39.744 0.192 ;
     RECT  39.768 0.144 40.272 0.192 ;
     RECT  40.296 0.144 40.8 0.192 ;
     RECT  40.824 0.144 41.328 0.192 ;
     RECT  41.352 0.144 41.856 0.192 ;
     RECT  41.88 0.144 42.384 0.192 ;
     RECT  42.408 0.144 42.912 0.192 ;
     RECT  42.936 0.144 43.392 0.192 ;
     RECT  43.416 0.144 43.92 0.192 ;
     RECT  43.944 0.144 44.448 0.192 ;
     RECT  44.472 0.144 44.976 0.192 ;
     RECT  45 0.144 45.504 0.192 ;
     RECT  45.528 0.144 46.032 0.192 ;
     RECT  46.056 0.144 46.56 0.192 ;
     RECT  46.584 0.144 47.088 0.192 ;
     RECT  47.112 0.144 47.616 0.192 ;
     RECT  47.64 0.144 48.096 0.192 ;
     RECT  48.12 0.144 48.624 0.192 ;
     RECT  48.648 0.144 49.152 0.192 ;
     RECT  49.176 0.144 49.68 0.192 ;
     RECT  49.704 0.144 50.208 0.192 ;
     RECT  50.232 0.144 50.736 0.192 ;
     RECT  50.76 0.144 51.264 0.192 ;
     RECT  51.288 0.144 51.792 0.192 ;
     RECT  51.816 0.144 52.32 0.192 ;
     RECT  52.344 0.144 52.848 0.192 ;
     RECT  52.872 0.144 53.328 0.192 ;
     RECT  53.352 0.144 53.856 0.192 ;
     RECT  53.88 0.144 54.384 0.192 ;
     RECT  54.408 0.144 54.912 0.192 ;
     RECT  54.936 0.144 55.44 0.192 ;
     RECT  55.464 0.144 55.968 0.192 ;
     RECT  55.992 0.144 56.496 0.192 ;
     RECT  56.52 0.144 57.024 0.192 ;
     RECT  57.048 0.144 57.552 0.192 ;
     RECT  57.576 0.144 58.08 0.192 ;
     RECT  58.104 0.144 58.56 0.192 ;
     RECT  58.584 0.144 59.088 0.192 ;
     RECT  59.112 0.144 59.616 0.192 ;
     RECT  59.64 0.144 60.144 0.192 ;
     RECT  60.168 0.144 60.672 0.192 ;
     RECT  60.696 0.144 61.2 0.192 ;
     RECT  61.224 0.144 61.728 0.192 ;
     RECT  61.752 0.144 62.256 0.192 ;
     RECT  62.28 0.144 62.784 0.192 ;
     RECT  62.808 0.144 63.312 0.192 ;
     RECT  63.336 0.144 63.792 0.192 ;
     RECT  63.816 0.144 64.32 0.192 ;
     RECT  64.344 0.144 64.848 0.192 ;
     RECT  64.872 0.144 65.376 0.192 ;
     RECT  65.4 0.144 65.904 0.192 ;
     RECT  65.928 0.144 66.432 0.192 ;
     RECT  66.456 0.144 66.96 0.192 ;
     RECT  66.984 0.144 67.488 0.192 ;
     RECT  67.512 0.144 68.016 0.192 ;
     RECT  68.04 0.144 68.544 0.192 ;
     RECT  68.568 0.144 69.024 0.192 ;
     RECT  69.048 0.144 69.552 0.192 ;
     RECT  69.576 0.144 70.08 0.192 ;
     RECT  70.104 0.144 70.608 0.192 ;
     RECT  70.632 0.144 71.136 0.192 ;
     RECT  71.16 0.144 71.664 0.192 ;
     RECT  71.688 0.144 72.192 0.192 ;
     RECT  72.216 0.144 72.72 0.192 ;
     RECT  72.744 0.144 73.248 0.192 ;
     RECT  73.272 0.144 73.776 0.192 ;
     RECT  73.8 0.144 74.256 0.192 ;
     RECT  74.28 0.144 74.784 0.192 ;
     RECT  74.808 0.144 75.312 0.192 ;
     RECT  75.336 0.144 75.84 0.192 ;
     RECT  75.864 0.144 76.368 0.192 ;
     RECT  76.392 0.144 76.896 0.192 ;
     RECT  76.92 0.144 77.424 0.192 ;
     RECT  77.448 0.144 77.952 0.192 ;
     RECT  77.976 0.144 78.48 0.192 ;
     RECT  78.504 0.144 79.008 0.192 ;
     RECT  79.032 0.144 79.488 0.192 ;
     RECT  79.512 0.144 80.016 0.192 ;
     RECT  80.04 0.144 80.544 0.192 ;
     RECT  80.568 0.144 81.072 0.192 ;
     RECT  81.096 0.144 81.6 0.192 ;
     RECT  81.624 0.144 82.128 0.192 ;
     RECT  82.152 0.144 82.656 0.192 ;
     RECT  82.68 0.144 83.184 0.192 ;
     RECT  83.208 0.144 83.712 0.192 ;
     RECT  83.736 0.144 84.192 0.192 ;
     RECT  84.216 0.144 84.72 0.192 ;
     RECT  84.744 0.144 85.248 0.192 ;
     RECT  85.272 0.144 85.776 0.192 ;
     RECT  85.8 0.144 86.304 0.192 ;
     RECT  86.328 0.144 86.832 0.192 ;
     RECT  86.856 0.144 87.36 0.192 ;
     RECT  87.384 0.144 87.888 0.192 ;
     RECT  87.912 0.144 88.416 0.192 ;
     RECT  88.44 0.144 88.944 0.192 ;
     RECT  88.968 0.144 89.424 0.192 ;
     RECT  89.448 0.144 89.952 0.192 ;
     RECT  89.976 0.144 90.48 0.192 ;
     RECT  90.504 0.144 91.008 0.192 ;
     RECT  91.032 0.144 91.536 0.192 ;
     RECT  91.56 0.144 92.064 0.192 ;
     RECT  92.088 0.144 92.592 0.192 ;
     RECT  92.616 0.144 93.12 0.192 ;
     RECT  93.144 0.144 93.648 0.192 ;
     RECT  93.672 0.144 94.176 0.192 ;
     RECT  94.2 0.144 94.656 0.192 ;
     RECT  94.68 0.144 95.184 0.192 ;
     RECT  95.208 0.144 95.712 0.192 ;
     RECT  95.736 0.144 96.24 0.192 ;
     RECT  96.264 0.144 96.768 0.192 ;
     RECT  96.792 0.144 97.296 0.192 ;
     RECT  97.32 0.144 97.824 0.192 ;
     RECT  97.848 0.144 98.352 0.192 ;
     RECT  98.376 0.144 98.88 0.192 ;
     RECT  98.904 0.144 99.408 0.192 ;
     RECT  99.432 0.144 99.888 0.192 ;
     RECT  99.912 0.144 100.416 0.192 ;
     RECT  100.44 0.144 100.944 0.192 ;
     RECT  100.968 0.144 101.472 0.192 ;
     RECT  101.496 0.144 102 0.192 ;
     RECT  102.024 0.144 102.528 0.192 ;
     RECT  102.552 0.144 103.056 0.192 ;
     RECT  103.08 0.144 103.584 0.192 ;
     RECT  103.608 0.144 104.112 0.192 ;
     RECT  104.136 0.144 104.64 0.192 ;
     RECT  104.664 0.144 105.12 0.192 ;
     RECT  105.144 0.144 105.648 0.192 ;
     RECT  105.672 0.144 106.176 0.192 ;
     RECT  106.2 0.144 106.704 0.192 ;
     RECT  106.728 0.144 107.232 0.192 ;
     RECT  107.256 0.144 107.76 0.192 ;
     RECT  107.784 0.144 108.288 0.192 ;
     RECT  108.312 0.144 108.816 0.192 ;
     RECT  108.84 0.144 109.344 0.192 ;
     RECT  109.368 0.144 109.872 0.192 ;
     RECT  109.896 0.144 110.352 0.192 ;
     RECT  110.376 0.144 110.88 0.192 ;
     RECT  110.904 0.144 111.408 0.192 ;
     RECT  111.432 0.144 111.936 0.192 ;
     RECT  111.96 0.144 112.464 0.192 ;
     RECT  112.488 0.144 112.992 0.192 ;
     RECT  113.016 0.144 113.52 0.192 ;
     RECT  113.544 0.144 114.048 0.192 ;
     RECT  114.072 0.144 114.576 0.192 ;
     RECT  114.6 0.144 115.056 0.192 ;
     RECT  115.08 0.144 115.584 0.192 ;
     RECT  115.608 0.144 116.112 0.192 ;
     RECT  116.136 0.144 116.64 0.192 ;
     RECT  116.664 0.144 117.168 0.192 ;
     RECT  117.192 0.144 117.696 0.192 ;
     RECT  117.72 0.144 118.224 0.192 ;
     RECT  118.248 0.144 118.752 0.192 ;
     RECT  118.776 0.144 119.28 0.192 ;
     RECT  119.304 0.144 119.808 0.192 ;
     RECT  119.832 0.144 120.288 0.192 ;
     RECT  120.312 0.144 120.816 0.192 ;
     RECT  120.84 0.144 121.344 0.192 ;
     RECT  121.368 0.144 121.872 0.192 ;
     RECT  121.896 0.144 122.4 0.192 ;
     RECT  122.424 0.144 122.928 0.192 ;
     RECT  122.952 0.144 123.456 0.192 ;
     RECT  123.48 0.144 123.984 0.192 ;
     RECT  124.008 0.144 124.512 0.192 ;
     RECT  124.536 0.144 125.04 0.192 ;
     RECT  125.064 0.144 125.52 0.192 ;
     RECT  125.544 0.144 126.048 0.192 ;
     RECT  126.072 0.144 126.576 0.192 ;
     RECT  126.6 0.144 127.104 0.192 ;
     RECT  127.128 0.144 127.632 0.192 ;
     RECT  127.656 0.144 128.16 0.192 ;
     RECT  128.184 0.144 128.688 0.192 ;
     RECT  128.712 0.144 129.216 0.192 ;
     RECT  129.24 0.144 129.744 0.192 ;
     RECT  129.768 0.144 130.272 0.192 ;
     RECT  130.296 0.144 130.752 0.192 ;
     RECT  130.776 0.144 131.28 0.192 ;
     RECT  131.304 0.144 131.808 0.192 ;
     RECT  131.832 0.144 132.336 0.192 ;
     RECT  132.36 0.144 132.864 0.192 ;
     RECT  132.888 0.144 133.392 0.192 ;
     RECT  133.416 0.144 133.92 0.192 ;
     RECT  133.944 0.144 134.448 0.192 ;
     RECT  134.472 0.144 134.976 0.192 ;
     RECT  135 0.144 135.504 0.192 ;
     RECT  135.528 0.144 135.984 0.192 ;
     RECT  136.008 0.144 136.512 0.192 ;
     RECT  136.536 0.144 137.04 0.192 ;
     RECT  137.064 0.144 137.568 0.192 ;
     RECT  137.592 0.144 138.096 0.192 ;
     RECT  4.704 0.192 138.12 0.227 ;
     RECT  126.576 0.227 130.776 0.563 ;
     RECT  4.704 0.227 12.072 0.611 ;
     RECT  13.056 0.227 28.776 0.611 ;
     RECT  31.392 0.227 35.592 0.611 ;
     RECT  36.624 0.227 69.048 0.611 ;
     RECT  70.08 0.227 125.544 0.611 ;
     RECT  70.08 0.611 107.256 0.995 ;
     RECT  17.76 0.611 28.776 1.091 ;
     RECT  6.816 0.611 6.84 1.187 ;
     RECT  7.824 0.611 10.488 1.187 ;
     RECT  13.056 0.611 16.776 1.187 ;
     RECT  19.344 1.091 28.776 1.187 ;
     RECT  31.392 0.611 34.536 1.187 ;
     RECT  51.264 0.611 54.936 1.187 ;
     RECT  63.312 0.611 69.048 1.187 ;
     RECT  70.08 0.995 75.864 1.187 ;
     RECT  76.896 0.995 107.256 1.187 ;
     RECT  115.056 0.611 125.544 1.187 ;
     RECT  126.576 0.563 130.296 1.187 ;
     RECT  131.808 0.227 138.12 1.187 ;
     RECT  4.704 0.611 5.784 1.763 ;
     RECT  7.824 1.187 9.96 1.763 ;
     RECT  11.52 0.611 12.072 1.763 ;
     RECT  13.2 1.187 16.776 1.763 ;
     RECT  17.76 1.091 18.312 1.763 ;
     RECT  19.344 1.187 26.184 1.763 ;
     RECT  27.216 1.187 28.776 1.763 ;
     RECT  29.808 0.227 30.36 1.763 ;
     RECT  31.392 1.187 32.472 1.763 ;
     RECT  33.456 1.187 34.536 1.763 ;
     RECT  35.568 0.611 35.592 1.763 ;
     RECT  36.624 0.611 36.648 1.763 ;
     RECT  37.68 0.611 43.944 1.763 ;
     RECT  44.976 0.611 49.176 1.763 ;
     RECT  50.208 0.611 50.232 1.763 ;
     RECT  51.264 1.187 52.344 1.763 ;
     RECT  53.328 1.187 54.936 1.763 ;
     RECT  77.424 1.187 101.496 1.763 ;
     RECT  102.528 1.187 103.08 1.763 ;
     RECT  104.112 1.187 107.256 1.763 ;
     RECT  108.288 0.611 112.488 1.763 ;
     RECT  113.52 0.611 113.544 1.763 ;
     RECT  115.056 1.187 122.952 1.763 ;
     RECT  123.984 1.187 125.544 1.763 ;
     RECT  126.576 1.187 127.128 1.763 ;
     RECT  128.16 1.187 130.296 1.763 ;
     RECT  131.808 1.187 135 1.763 ;
     RECT  135.984 1.187 138.12 1.763 ;
     RECT  16.752 1.763 16.776 1.811 ;
     RECT  20.4 1.763 20.424 1.811 ;
     RECT  27.216 1.763 27.24 1.811 ;
     RECT  37.68 1.763 37.704 1.811 ;
     RECT  109.344 1.763 109.368 1.811 ;
     RECT  71.136 1.187 75.864 1.859 ;
     RECT  77.424 1.763 78.504 1.859 ;
     RECT  94.176 1.763 94.512 1.859 ;
     RECT  55.968 0.611 56.52 1.907 ;
     RECT  57.552 0.611 62.28 1.907 ;
     RECT  63.312 1.187 64.872 1.907 ;
     RECT  65.904 1.187 69.048 1.907 ;
     RECT  71.136 1.859 74.28 1.907 ;
     RECT  23.52 1.763 24.408 2.003 ;
     RECT  104.64 1.763 105.312 2.003 ;
     RECT  7.824 1.763 8.112 2.137 ;
     RECT  29.808 1.763 29.832 2.137 ;
     RECT  51.264 1.763 51.312 2.137 ;
     RECT  2.4 2.137 2.52 2.151 ;
     RECT  56.4 1.907 56.52 2.151 ;
     RECT  99.408 1.763 99.912 2.291 ;
     RECT  70.608 2.293 70.632 2.435 ;
     RECT  78 1.859 78.408 2.723 ;
     RECT  29.4 2.137 29.832 2.821 ;
     RECT  9.408 1.763 9.432 2.915 ;
     RECT  32.448 1.763 32.472 2.915 ;
     RECT  64.848 1.907 64.872 2.963 ;
     RECT  69.312 2.917 69.336 3.059 ;
     RECT  75.84 3.109 75.864 3.299 ;
     RECT  56.4 2.151 56.712 3.349 ;
     RECT  67.2 1.907 67.512 3.397 ;
     RECT  56.4 3.349 56.808 3.539 ;
     RECT  67.2 3.397 67.608 3.541 ;
     RECT  99.6 2.291 99.912 3.541 ;
     RECT  72.6 1.907 72.912 3.733 ;
     RECT  58.704 2.917 58.728 3.923 ;
     RECT  54.72 3.493 54.744 3.971 ;
     RECT  64.992 3.013 65.448 3.971 ;
     RECT  65.04 3.971 65.448 4.069 ;
     RECT  98.448 3.973 98.472 4.115 ;
     RECT  126.6 1.763 126.912 4.117 ;
     RECT  90.624 3.589 90.648 4.163 ;
     RECT  24 2.003 24.408 4.165 ;
     RECT  67.2 3.541 68.376 4.165 ;
     RECT  83.4 1.763 83.712 4.213 ;
     RECT  65.04 4.069 65.688 4.259 ;
     RECT  24 4.165 24.456 4.307 ;
     RECT  29.4 2.821 30.264 4.357 ;
     RECT  115.8 1.763 116.112 4.357 ;
     RECT  86.496 4.213 86.52 4.403 ;
     RECT  34.8 2.137 35.112 4.453 ;
     RECT  28.608 4.357 30.264 4.499 ;
     RECT  67.2 4.165 68.52 4.499 ;
     RECT  70.56 4.309 70.584 4.499 ;
     RECT  72.48 3.733 72.912 4.499 ;
     RECT  34.8 4.453 35.784 4.549 ;
     RECT  43.872 1.763 43.896 4.595 ;
     RECT  83.4 4.213 84.216 4.595 ;
     RECT  115.8 4.357 116.568 4.597 ;
     RECT  22.8 3.925 22.824 4.643 ;
     RECT  53.568 3.973 53.592 4.643 ;
     RECT  126.6 4.117 127.416 4.643 ;
     RECT  34.704 4.549 35.784 4.645 ;
     RECT  99.504 3.541 99.912 4.645 ;
     RECT  29.4 4.499 30.264 4.691 ;
     RECT  114.192 3.397 114.216 4.693 ;
     RECT  28.32 4.693 28.344 4.789 ;
     RECT  65.664 4.259 65.688 4.835 ;
     RECT  114.192 4.693 114.312 4.835 ;
     RECT  34.704 4.645 36.168 4.837 ;
     RECT  61.8 1.907 62.112 4.837 ;
     RECT  27.744 4.789 28.344 4.883 ;
     RECT  54.288 4.645 54.312 4.883 ;
     RECT  114.192 4.835 114.216 4.883 ;
     RECT  27.744 4.883 27.768 4.979 ;
     RECT  49.008 4.645 49.032 4.979 ;
     RECT  67.2 4.499 67.704 5.075 ;
     RECT  76.896 4.645 76.92 5.123 ;
     RECT  24 4.307 24.408 5.125 ;
     RECT  127.968 4.645 127.992 5.171 ;
     RECT  117.792 5.029 117.816 5.173 ;
     RECT  118.848 4.789 118.872 5.173 ;
     RECT  61.392 4.837 62.112 5.219 ;
     RECT  23.856 5.125 24.408 5.411 ;
     RECT  24 5.411 24.408 5.413 ;
     RECT  115.8 4.597 116.664 5.413 ;
     RECT  117.792 5.173 118.872 5.413 ;
     RECT  21.12 4.837 21.144 5.509 ;
     RECT  38.016 4.837 38.04 5.557 ;
     RECT  39.024 4.933 39.048 5.557 ;
     RECT  34.512 4.837 36.168 5.651 ;
     RECT  24 5.413 24.456 5.701 ;
     RECT  69.552 4.837 69.576 5.747 ;
     RECT  20.976 5.509 21.144 5.795 ;
     RECT  21.072 5.795 21.144 5.939 ;
     RECT  22.944 5.653 22.968 5.939 ;
     RECT  112.896 5.221 112.92 5.989 ;
     RECT  115.8 5.413 118.872 6.085 ;
     RECT  24 5.701 24.504 6.131 ;
     RECT  112.848 5.989 112.92 6.131 ;
     RECT  72.6 4.499 72.912 6.181 ;
     RECT  70.704 6.085 70.728 6.227 ;
     RECT  36.144 5.651 36.168 6.229 ;
     RECT  38.016 5.557 39.048 6.229 ;
     RECT  72.6 6.181 73.56 6.323 ;
     RECT  115.8 6.085 119.016 6.421 ;
     RECT  115.8 6.421 119.928 6.709 ;
     RECT  112.992 6.517 113.016 6.803 ;
     RECT  34.512 5.651 35.112 6.805 ;
     RECT  22.32 6.757 22.344 6.947 ;
     RECT  115.152 6.709 119.928 6.947 ;
     RECT  34.128 6.805 35.112 7.237 ;
     RECT  32.256 4.837 32.28 7.333 ;
     RECT  34.032 7.237 35.112 7.333 ;
     RECT  5.472 4.645 5.496 7.381 ;
     RECT  32.256 7.333 35.112 7.381 ;
     RECT  36.144 6.229 36.504 7.381 ;
     RECT  37.488 6.229 39.048 7.669 ;
     RECT  40.2 1.763 40.512 7.669 ;
     RECT  115.68 6.947 119.928 7.715 ;
     RECT  4.992 7.381 5.496 7.811 ;
     RECT  21.072 5.939 21.096 7.813 ;
     RECT  24 6.131 24.456 8.051 ;
     RECT  115.8 7.715 119.928 8.099 ;
     RECT  117.696 8.099 119.928 8.197 ;
     RECT  16.176 5.749 16.2 8.821 ;
     RECT  15.888 8.821 16.2 8.965 ;
     RECT  17.232 5.029 17.256 8.965 ;
     RECT  15.888 8.965 17.256 9.013 ;
     RECT  15.744 9.013 17.256 9.493 ;
     RECT  115.8 8.099 116.568 9.827 ;
     RECT  115.8 9.827 116.424 10.355 ;
     RECT  117.696 8.197 120.024 10.979 ;
     RECT  5.376 7.811 5.496 11.941 ;
     RECT  5.28 11.941 5.496 11.987 ;
     RECT  5.28 11.987 5.4 12.421 ;
     RECT  4.656 12.421 5.4 12.467 ;
     RECT  15.744 9.493 17.592 13.909 ;
     RECT  18.6 2.137 18.912 13.909 ;
     RECT  4.656 12.467 5.304 15.635 ;
     RECT  4.992 15.635 5.304 17.605 ;
     RECT  117.744 10.979 120.024 17.989 ;
     RECT  117.696 17.989 120.024 19.237 ;
     RECT  117.552 19.237 120.024 19.525 ;
     RECT  21.072 7.813 21.864 19.765 ;
     RECT  21.072 19.765 22.2 19.957 ;
     RECT  4.656 17.605 5.304 20.003 ;
     RECT  21.072 19.957 22.824 20.147 ;
     RECT  21.072 20.147 22.2 20.149 ;
     RECT  7.8 2.137 8.112 21.541 ;
     RECT  15.744 13.909 18.912 21.877 ;
     RECT  20.304 20.149 22.2 21.877 ;
     RECT  117.36 19.525 120.024 21.973 ;
     RECT  15.744 21.877 22.2 23.267 ;
     RECT  6.816 21.541 8.112 23.269 ;
     RECT  6.288 23.269 8.112 23.315 ;
     RECT  117.36 21.973 120.072 24.131 ;
     RECT  14.544 9.349 14.568 24.661 ;
     RECT  15.744 23.267 21.864 25.619 ;
     RECT  117.36 24.131 119.976 25.667 ;
     RECT  117.408 25.667 119.976 26.723 ;
     RECT  117.648 26.723 119.976 27.299 ;
     RECT  117.744 27.299 119.976 28.933 ;
     RECT  21.072 25.619 21.864 29.317 ;
     RECT  21.072 29.317 22.296 29.603 ;
     RECT  15.744 25.619 19.848 30.037 ;
     RECT  5.28 20.003 5.304 30.275 ;
     RECT  6.288 23.315 6.312 30.275 ;
     RECT  15.744 30.037 19.896 30.805 ;
     RECT  21.072 29.603 21.864 30.805 ;
     RECT  117.504 28.933 119.976 30.851 ;
     RECT  11.664 29.269 11.688 31.955 ;
     RECT  117.744 30.851 119.976 32.245 ;
     RECT  5.088 30.709 5.112 32.437 ;
     RECT  4.608 32.437 5.112 32.483 ;
     RECT  117.744 32.245 120.12 32.483 ;
     RECT  14.496 24.661 14.568 33.013 ;
     RECT  14.496 33.013 14.712 33.061 ;
     RECT  15.744 30.805 21.864 33.061 ;
     RECT  117.744 32.483 119.976 33.443 ;
     RECT  118.128 33.443 119.976 33.731 ;
     RECT  118.128 33.731 118.344 34.019 ;
     RECT  118.32 34.019 118.344 34.211 ;
     RECT  119.328 33.731 119.976 34.307 ;
     RECT  13.2 1.763 13.512 34.453 ;
     RECT  14.496 33.061 21.864 34.453 ;
     RECT  119.952 34.307 119.976 34.595 ;
     RECT  9.648 32.437 9.672 35.363 ;
     RECT  4.608 32.483 4.632 35.845 ;
     RECT  4.608 35.845 5.4 36.515 ;
     RECT  13.2 34.453 21.864 36.517 ;
     RECT  12.48 36.517 21.864 36.613 ;
     RECT  12.432 36.613 21.864 37.141 ;
     RECT  12.384 37.141 21.864 37.333 ;
     RECT  5.088 36.515 5.4 38.819 ;
     RECT  2.4 2.151 2.712 39.301 ;
     RECT  5.088 38.819 5.112 39.443 ;
     RECT  12.336 37.333 21.864 39.541 ;
     RECT  12.336 39.541 22.056 39.829 ;
     RECT  11.952 39.829 22.056 40.069 ;
     RECT  11.856 40.069 22.056 40.309 ;
     RECT  11.76 40.309 22.056 40.357 ;
     RECT  11.568 40.357 22.056 41.653 ;
     RECT  11.568 41.653 22.104 43.045 ;
     RECT  11.184 43.045 22.104 43.093 ;
     RECT  11.088 43.093 22.104 43.765 ;
     RECT  11.088 43.765 22.152 45.493 ;
     RECT  11.04 45.493 22.152 47.221 ;
     RECT  117.36 47.605 117.384 47.795 ;
     RECT  117.36 48.901 117.384 49.091 ;
     RECT  118.032 51.205 118.056 51.443 ;
     RECT  11.04 47.221 22.2 55.429 ;
     RECT  11.04 55.429 22.392 55.811 ;
     RECT  5.472 40.981 5.496 58.355 ;
     RECT  118.56 60.709 118.584 60.899 ;
     RECT  4.848 58.549 4.92 63.205 ;
     RECT  4.8 63.205 4.92 63.251 ;
     RECT  4.8 63.251 4.872 63.683 ;
     RECT  26.448 8.149 26.472 63.923 ;
     RECT  32.256 7.381 36.504 64.115 ;
     RECT  32.256 64.115 33.096 64.163 ;
     RECT  37.488 7.669 40.512 64.211 ;
     RECT  37.488 64.211 38.952 64.259 ;
     RECT  43.584 4.741 43.608 64.451 ;
     RECT  38.016 64.259 38.952 64.499 ;
     RECT  38.016 64.499 38.808 64.547 ;
     RECT  34.8 64.115 36.504 64.595 ;
     RECT  34.8 64.595 36.168 64.643 ;
     RECT  33.072 64.163 33.096 64.739 ;
     RECT  36.144 64.643 36.168 65.555 ;
     RECT  98.928 4.645 99.912 65.651 ;
     RECT  2.4 39.301 3.672 65.795 ;
     RECT  38.784 64.547 38.808 65.891 ;
     RECT  100.944 4.117 100.968 66.037 ;
     RECT  4.8 63.683 4.824 66.373 ;
     RECT  4.32 66.373 4.824 66.419 ;
     RECT  100.944 66.037 101.064 66.467 ;
     RECT  4.32 66.419 4.344 67.283 ;
     RECT  11.04 55.811 22.2 67.381 ;
     RECT  11.04 67.381 22.824 67.667 ;
     RECT  11.04 67.667 22.2 72.275 ;
     RECT  17.04 72.275 22.2 75.155 ;
     RECT  17.04 75.155 19.944 75.203 ;
     RECT  56.4 3.539 56.712 75.541 ;
     RECT  137.4 1.763 137.712 76.261 ;
     RECT  137.232 76.261 137.712 76.309 ;
     RECT  86.736 77.701 86.76 78.037 ;
     RECT  58.704 78.661 58.728 78.901 ;
     RECT  58.704 78.901 58.824 78.947 ;
     RECT  58.752 78.947 58.824 79.043 ;
     RECT  55.2 75.541 56.712 79.093 ;
     RECT  21.024 75.155 22.2 79.235 ;
     RECT  105 2.003 105.312 79.429 ;
     RECT  24 8.051 24.312 79.621 ;
     RECT  21.6 79.235 22.2 79.763 ;
     RECT  54.672 79.093 56.712 79.765 ;
     RECT  104.88 79.429 105.312 79.765 ;
     RECT  117.264 79.717 117.288 79.765 ;
     RECT  122.88 79.717 122.904 79.765 ;
     RECT  45.6 1.763 45.912 79.957 ;
     RECT  45.6 79.957 46.728 80.005 ;
     RECT  22.08 79.763 22.2 80.147 ;
     RECT  29.4 4.691 29.712 80.197 ;
     RECT  51 2.137 51.312 80.197 ;
     RECT  81.264 80.149 81.288 80.245 ;
     RECT  81.168 80.245 81.288 80.291 ;
     RECT  17.28 75.203 19.944 80.339 ;
     RECT  29.4 80.197 30.216 80.341 ;
     RECT  79.728 80.197 79.752 80.341 ;
     RECT  81.168 80.291 81.192 80.341 ;
     RECT  33.072 80.149 33.096 80.387 ;
     RECT  79.344 80.341 81.192 80.387 ;
     RECT  29.4 80.341 30.936 80.485 ;
     RECT  34.8 64.643 35.112 80.485 ;
     RECT  38.976 66.085 39 80.485 ;
     RECT  86.736 78.037 86.856 80.533 ;
     RECT  106.56 80.485 106.584 80.533 ;
     RECT  5.568 79.765 5.592 80.677 ;
     RECT  7.8 23.315 8.112 80.677 ;
     RECT  9.456 80.485 9.48 80.677 ;
     RECT  11.04 72.275 15.96 80.677 ;
     RECT  18.6 80.339 19.944 80.677 ;
     RECT  18.6 80.677 20.76 80.725 ;
     RECT  34.8 80.485 35.352 80.725 ;
     RECT  7.8 80.677 9.48 80.773 ;
     RECT  110.4 1.763 110.712 80.773 ;
     RECT  34.8 80.725 35.736 80.821 ;
     RECT  72.6 6.323 72.912 80.821 ;
     RECT  78 2.723 78.312 80.821 ;
     RECT  83.4 4.595 83.712 80.821 ;
     RECT  129.888 80.773 129.912 80.821 ;
     RECT  121.2 1.763 121.512 80.869 ;
     RECT  22.08 80.147 22.104 80.915 ;
     RECT  5.568 80.677 5.688 80.917 ;
     RECT  18.6 80.725 20.856 80.917 ;
     RECT  23.712 79.621 24.312 80.917 ;
     RECT  121.2 80.869 121.8 80.917 ;
     RECT  122.784 79.765 122.904 80.917 ;
     RECT  100.944 66.467 100.968 80.963 ;
     RECT  40.2 64.211 40.512 81.061 ;
     RECT  83.4 80.821 84.36 81.061 ;
     RECT  85.488 80.917 85.512 81.061 ;
     RECT  18.6 80.917 21.096 81.107 ;
     RECT  23.712 80.917 25.08 81.107 ;
     RECT  38.688 80.485 39 81.109 ;
     RECT  40.08 81.061 40.512 81.109 ;
     RECT  83.4 81.061 85.512 81.109 ;
     RECT  86.736 80.533 87.768 81.109 ;
     RECT  29.4 80.485 31.896 81.157 ;
     RECT  58.752 79.043 58.776 81.205 ;
     RECT  106.56 80.533 106.92 81.205 ;
     RECT  38.688 81.109 40.512 81.253 ;
     RECT  42.768 81.157 42.792 81.299 ;
     RECT  38.688 81.253 40.92 81.347 ;
     RECT  51 80.197 51.672 81.349 ;
     RECT  61.8 5.219 62.112 81.349 ;
     RECT  132 1.763 132.312 81.397 ;
     RECT  104.88 79.765 105.432 81.445 ;
     RECT  106.56 81.205 107.16 81.445 ;
     RECT  132 81.397 132.792 81.445 ;
     RECT  60.384 79.189 60.408 81.539 ;
     RECT  79.344 80.387 80.952 81.539 ;
     RECT  117.264 79.765 117.432 81.539 ;
     RECT  136.416 76.309 137.712 81.539 ;
     RECT  67.2 5.075 67.512 81.589 ;
     RECT  128.592 79.189 128.76 81.589 ;
     RECT  10.8 80.677 15.96 81.635 ;
     RECT  10.8 81.635 15.672 81.683 ;
     RECT  58.752 81.205 59.208 81.829 ;
     RECT  38.688 81.347 39 81.925 ;
     RECT  54.432 79.765 56.712 81.925 ;
     RECT  57.888 81.829 59.208 81.925 ;
     RECT  17.28 80.339 17.592 81.973 ;
     RECT  18.6 81.107 20.856 81.973 ;
     RECT  49.728 80.725 49.752 81.973 ;
     RECT  51 81.349 51.96 81.973 ;
     RECT  2.4 65.795 2.712 82.021 ;
     RECT  5.472 80.917 5.688 82.021 ;
     RECT  34.8 80.821 35.88 82.021 ;
     RECT  5.088 82.021 5.688 82.115 ;
     RECT  10.8 81.683 11.976 82.115 ;
     RECT  33.6 81.205 33.624 82.115 ;
     RECT  45.6 80.005 47.304 82.115 ;
     RECT  74.064 80.677 74.088 82.115 ;
     RECT  129.888 80.821 130.536 82.115 ;
     RECT  132 81.445 133.368 82.115 ;
     RECT  29.4 81.157 32.472 82.163 ;
     RECT  17.28 81.973 20.856 82.165 ;
     RECT  54.432 81.925 59.208 82.165 ;
     RECT  126.6 4.643 126.912 82.165 ;
     RECT  128.544 81.589 128.76 82.165 ;
     RECT  115.8 10.355 116.112 82.261 ;
     RECT  126.6 82.165 128.76 82.261 ;
     RECT  129.888 82.115 129.96 82.261 ;
     RECT  16.992 82.165 21 82.309 ;
     RECT  27.12 80.197 27.144 82.309 ;
     RECT  66.576 81.589 67.512 82.309 ;
     RECT  101.424 82.021 101.448 82.309 ;
     RECT  76.368 82.021 76.392 82.405 ;
     RECT  77.568 80.821 78.312 82.405 ;
     RECT  23.712 81.107 24.312 82.453 ;
     RECT  61.68 81.349 62.112 82.549 ;
     RECT  121.2 80.917 122.904 82.549 ;
     RECT  16.992 82.309 21.144 82.595 ;
     RECT  23.376 82.453 24.408 82.595 ;
     RECT  13.2 81.683 15.672 82.597 ;
     RECT  16.992 82.595 19.368 82.597 ;
     RECT  68.976 82.453 69 82.597 ;
     RECT  94.2 1.859 94.512 82.597 ;
     RECT  126.6 82.261 129.96 82.643 ;
     RECT  7.296 80.773 9.48 82.691 ;
     RECT  27.12 82.309 27.624 82.691 ;
     RECT  29.4 82.163 31.896 82.691 ;
     RECT  34.8 82.021 36.648 82.691 ;
     RECT  40.032 81.347 40.92 82.691 ;
     RECT  49.728 81.973 51.96 82.691 ;
     RECT  53.616 82.165 59.208 82.691 ;
     RECT  61.68 82.549 62.712 82.691 ;
     RECT  79.344 81.539 80.664 82.691 ;
     RECT  83.4 81.109 87.768 82.691 ;
     RECT  101.424 82.309 102.216 82.691 ;
     RECT  110.4 80.773 111.576 82.691 ;
     RECT  115.056 82.261 116.112 82.691 ;
     RECT  125.088 81.781 125.112 82.691 ;
     RECT  83.4 82.691 84.84 82.739 ;
     RECT  94.2 82.597 95.352 82.739 ;
     RECT  48.432 80.821 48.456 82.789 ;
     RECT  68.976 82.597 69.48 82.837 ;
     RECT  88.8 1.763 89.112 82.837 ;
     RECT  48.432 82.789 49.224 82.931 ;
     RECT  63.792 82.597 63.816 82.979 ;
     RECT  38.544 81.925 39 82.981 ;
     RECT  72.48 80.821 72.912 83.029 ;
     RECT  20.4 82.595 21.144 83.075 ;
     RECT  76.368 82.405 78.312 83.077 ;
     RECT  79.344 82.691 80.376 83.077 ;
     RECT  5.088 82.115 5.64 83.125 ;
     RECT  38.16 82.981 39 83.125 ;
     RECT  40.032 82.691 40.68 83.125 ;
     RECT  74.64 82.501 74.712 83.125 ;
     RECT  94.2 82.739 94.512 83.125 ;
     RECT  119.088 81.205 119.112 83.125 ;
     RECT  121.2 82.549 123.864 83.125 ;
     RECT  5.088 83.125 5.688 83.173 ;
     RECT  7.296 82.691 8.112 83.173 ;
     RECT  13.2 82.597 19.368 83.173 ;
     RECT  27.12 82.691 27.144 83.173 ;
     RECT  42.72 82.885 42.744 83.173 ;
     RECT  48.432 82.931 48.456 83.173 ;
     RECT  60.528 82.645 60.552 83.173 ;
     RECT  61.68 82.691 62.664 83.173 ;
     RECT  66.336 82.309 67.512 83.173 ;
     RECT  74.64 83.125 75.192 83.173 ;
     RECT  76.368 83.077 80.376 83.173 ;
     RECT  104.88 81.445 107.16 83.173 ;
     RECT  119.088 83.125 119.16 83.173 ;
     RECT  121.2 83.125 124.392 83.173 ;
     RECT  125.424 82.837 125.448 83.173 ;
     RECT  126.6 82.643 127.512 83.173 ;
     RECT  132 82.115 132.792 83.173 ;
     RECT  136.608 81.539 137.712 83.173 ;
     RECT  2.4 82.021 3.672 83.267 ;
     RECT  76.224 83.173 80.376 83.267 ;
     RECT  128.544 82.643 129.96 83.267 ;
     RECT  131.712 83.173 132.792 83.267 ;
     RECT  104.88 83.173 107.64 83.315 ;
     RECT  117.264 81.539 117.288 83.315 ;
     RECT  128.544 83.267 129.912 83.363 ;
     RECT  27.072 83.173 27.144 83.411 ;
     RECT  44.448 81.589 44.472 83.411 ;
     RECT  45.6 82.115 46.728 83.411 ;
     RECT  86.832 82.691 87.768 83.411 ;
     RECT  135.888 83.173 137.712 83.507 ;
     RECT  34.8 82.691 35.88 83.555 ;
     RECT  54.528 82.691 58.776 83.651 ;
     RECT  5.088 83.173 8.112 83.653 ;
     RECT  115.8 82.691 116.112 83.653 ;
     RECT  42.336 83.173 42.744 83.749 ;
     RECT  50.64 82.691 51.96 83.749 ;
     RECT  53.232 83.173 53.256 83.749 ;
     RECT  99.6 65.651 99.912 83.749 ;
     RECT  9.264 82.691 9.48 83.843 ;
     RECT  11.04 82.115 11.976 83.843 ;
     RECT  120.72 83.173 124.392 83.843 ;
     RECT  137.232 83.507 137.712 83.843 ;
     RECT  102.192 82.691 102.216 83.845 ;
     RECT  120.72 83.843 123.336 83.845 ;
     RECT  105 83.315 107.64 83.891 ;
     RECT  120.192 83.845 123.336 83.891 ;
     RECT  38.16 83.125 40.68 83.893 ;
     RECT  42.144 83.749 42.744 83.893 ;
     RECT  68.928 82.837 69.528 83.893 ;
     RECT  83.4 82.739 84.696 83.893 ;
     RECT  12.96 83.173 19.368 83.939 ;
     RECT  54.768 83.651 58.776 83.939 ;
     RECT  82.512 83.893 84.696 83.939 ;
     RECT  20.4 83.075 20.856 84.035 ;
     RECT  11.328 83.843 11.976 84.037 ;
     RECT  12.96 83.939 14.52 84.037 ;
     RECT  29.4 82.691 30.216 84.037 ;
     RECT  34.8 83.555 35.736 84.083 ;
     RECT  101.328 83.845 102.216 84.083 ;
     RECT  2.4 83.267 2.712 84.249 ;
     RECT  15.552 83.939 18.912 84.249 ;
     RECT  50.064 83.749 53.256 84.249 ;
     RECT  65.76 83.173 67.512 84.249 ;
     RECT  72.432 83.029 72.912 84.249 ;
     RECT  115.8 83.653 117.048 84.249 ;
     RECT  137.4 83.843 137.712 84.249 ;
     RECT  2.4 84.249 2.52 84.263 ;
     RECT  5.088 83.653 8.232 84.263 ;
     RECT  15.552 84.249 18.72 84.263 ;
     RECT  29.136 84.037 30.216 84.263 ;
     RECT  45.6 83.411 45.912 84.263 ;
     RECT  60.528 83.173 62.664 84.263 ;
     RECT  65.76 84.249 67.32 84.263 ;
     RECT  72.432 84.249 72.72 84.263 ;
     RECT  82.512 83.939 84.648 84.263 ;
     RECT  88.8 82.837 89.88 84.263 ;
     RECT  94.032 83.125 94.512 84.263 ;
     RECT  99.6 83.749 100.344 84.263 ;
     RECT  105 83.891 106.584 84.263 ;
     RECT  110.4 82.691 110.712 84.263 ;
     RECT  115.8 84.249 115.92 84.263 ;
     RECT  125.424 83.173 127.512 84.263 ;
     RECT  131.712 83.267 132.744 84.263 ;
     RECT  137.4 84.249 137.52 84.263 ;
     RECT  48 83.173 48.456 84.325 ;
     RECT  77.28 83.267 79.992 84.371 ;
     RECT  79.392 84.371 79.992 84.373 ;
     RECT  20.4 84.035 20.808 84.949 ;
     RECT  34.8 84.083 35.208 84.949 ;
     RECT  87.36 83.411 87.768 84.949 ;
     RECT  23.424 82.595 24.408 85.477 ;
     RECT  31.248 82.691 31.896 85.477 ;
     RECT  34.368 84.949 35.208 85.477 ;
     RECT  42.144 83.893 42.792 85.477 ;
     RECT  48 84.325 48.552 85.477 ;
     RECT  60.528 84.263 61.032 85.477 ;
     RECT  65.76 84.263 66.36 85.477 ;
     RECT  72.432 84.263 72.456 85.477 ;
     RECT  118.656 83.173 119.16 85.477 ;
     RECT  5.088 84.263 7.224 85.523 ;
     RECT  11.328 84.037 14.52 85.523 ;
     RECT  15.552 84.263 18.696 85.523 ;
     RECT  19.728 84.949 20.808 85.523 ;
     RECT  22.896 85.477 24.984 85.523 ;
     RECT  31.248 85.477 32.328 85.523 ;
     RECT  37.536 83.893 40.68 85.523 ;
     RECT  50.064 84.249 51.144 85.523 ;
     RECT  55.296 83.939 58.488 85.523 ;
     RECT  65.76 85.477 66.84 85.523 ;
     RECT  68.928 83.893 70.008 85.523 ;
     RECT  72.048 85.477 73.128 85.523 ;
     RECT  74.16 83.173 75.192 85.523 ;
     RECT  77.28 84.371 78.36 85.523 ;
     RECT  79.392 84.373 80.424 85.523 ;
     RECT  83.568 84.263 84.648 85.523 ;
     RECT  86.688 84.949 87.768 85.523 ;
     RECT  105.552 84.263 106.584 85.523 ;
     RECT  120.192 83.891 122.28 85.523 ;
     RECT  128.544 83.363 129.624 85.523 ;
     RECT  41.712 85.477 42.792 85.571 ;
     RECT  5.088 85.523 6.168 86.208 ;
     RECT  5.112 86.208 6.144 86.224 ;
     RECT  12.432 85.523 14.52 86.208 ;
     RECT  12.456 86.208 13.44 86.224 ;
     RECT  13.464 86.208 14.496 86.224 ;
     RECT  22.896 85.523 23.928 86.208 ;
     RECT  22.92 86.208 23.904 86.224 ;
     RECT  34.368 85.477 35.448 86.208 ;
     RECT  34.392 86.208 35.424 86.224 ;
     RECT  38.592 85.523 39.624 86.208 ;
     RECT  38.616 86.208 39.6 86.224 ;
     RECT  48 85.477 49.08 86.208 ;
     RECT  48.024 86.208 49.056 86.224 ;
     RECT  52.176 84.249 53.256 86.208 ;
     RECT  52.2 86.208 53.232 86.224 ;
     RECT  57.408 85.523 58.488 86.208 ;
     RECT  57.432 86.208 58.464 86.224 ;
     RECT  60.528 85.477 61.608 86.208 ;
     RECT  60.552 86.208 61.584 86.224 ;
     RECT  118.08 85.477 119.16 86.208 ;
     RECT  118.104 86.208 119.136 86.224 ;
     RECT  120.192 85.523 121.272 86.208 ;
     RECT  120.216 86.208 121.248 86.224 ;
     RECT  125.424 84.263 126.504 86.208 ;
     RECT  125.448 86.208 126.48 86.224 ;
     RECT  5.664 86.224 5.688 86.243 ;
     RECT  12.96 86.224 12.984 86.243 ;
     RECT  14.016 86.224 14.04 86.243 ;
     RECT  23.424 86.224 23.448 86.243 ;
     RECT  35.184 86.224 35.208 86.243 ;
     RECT  39.12 86.224 39.144 86.243 ;
     RECT  48.528 86.224 48.552 86.243 ;
     RECT  52.704 86.224 52.728 86.243 ;
     RECT  57.936 86.224 57.96 86.243 ;
     RECT  61.008 86.224 61.032 86.243 ;
     RECT  118.656 86.224 118.68 86.243 ;
     RECT  120.72 86.224 120.744 86.243 ;
     RECT  125.904 86.224 125.928 86.243 ;
     RECT  12.12 0.227 12.48 0.24 ;
     RECT  12.6 0.227 13.008 0.24 ;
     RECT  28.824 0.227 29.232 0.24 ;
     RECT  29.352 0.227 29.76 0.24 ;
     RECT  30.408 0.227 30.816 0.24 ;
     RECT  30.936 0.227 31.344 0.24 ;
     RECT  35.64 0.227 36.048 0.24 ;
     RECT  36.168 0.227 36.576 0.24 ;
     RECT  69.096 0.227 69.504 0.24 ;
     RECT  69.624 0.227 70.032 0.24 ;
     RECT  125.592 0.227 126 0.24 ;
     RECT  126.12 0.227 126.528 0.24 ;
     RECT  130.824 0.227 131.232 0.24 ;
     RECT  131.352 0.227 131.76 0.24 ;
     RECT  12.072 0.24 13.056 1.187 ;
     RECT  28.776 0.24 29.808 1.763 ;
     RECT  30.36 0.24 31.392 1.763 ;
     RECT  35.592 0.24 36.624 1.763 ;
     RECT  69.048 0.24 70.08 1.187 ;
     RECT  125.544 0.24 126.576 1.763 ;
     RECT  130.776 0.24 131.808 0.563 ;
     RECT  130.296 0.563 131.808 1.763 ;
     RECT  5.784 0.611 6.816 1.187 ;
     RECT  6.84 0.611 7.824 1.187 ;
     RECT  10.488 0.611 11.52 1.187 ;
     RECT  16.776 0.611 17.76 1.763 ;
     RECT  34.536 0.611 35.568 1.763 ;
     RECT  36.648 0.611 37.68 1.763 ;
     RECT  43.944 0.611 44.976 1.763 ;
     RECT  49.176 0.611 50.208 1.763 ;
     RECT  50.232 0.611 51.264 1.763 ;
     RECT  54.936 0.611 55.968 1.763 ;
     RECT  56.52 0.611 57.552 1.907 ;
     RECT  62.28 0.611 63.312 1.907 ;
     RECT  107.256 0.611 108.288 1.763 ;
     RECT  112.488 0.611 113.52 1.763 ;
     RECT  113.544 0.611 115.056 1.763 ;
     RECT  75.864 0.995 76.896 1.187 ;
     RECT  18.312 1.091 19.344 1.763 ;
     RECT  7.8 1.187 7.824 2.137 ;
     RECT  12.072 1.187 13.2 1.763 ;
     RECT  26.184 1.187 27.216 1.763 ;
     RECT  32.472 1.187 33.456 1.763 ;
     RECT  52.344 1.187 53.328 1.763 ;
     RECT  64.872 1.187 65.904 1.907 ;
     RECT  70.608 1.187 71.136 1.907 ;
     RECT  101.496 1.187 102.528 1.763 ;
     RECT  103.08 1.187 104.112 1.763 ;
     RECT  122.952 1.187 123.984 1.763 ;
     RECT  127.128 1.187 128.16 1.763 ;
     RECT  135 1.187 135.984 1.763 ;
     RECT  8.112 1.763 9.408 2.915 ;
     RECT  18.6 1.763 20.4 1.811 ;
     RECT  29.4 1.763 29.808 2.137 ;
     RECT  29.832 1.763 30.264 2.821 ;
     RECT  34.8 1.763 35.112 2.137 ;
     RECT  51 1.763 51.264 2.137 ;
     RECT  109.368 1.763 110.4 1.811 ;
     RECT  18.6 1.811 18.912 2.137 ;
     RECT  75.84 1.859 75.864 3.109 ;
     RECT  56.52 1.907 56.808 2.151 ;
     RECT  58.704 1.907 58.728 2.917 ;
     RECT  64.872 1.907 65.448 2.963 ;
     RECT  67.512 1.907 67.608 3.397 ;
     RECT  70.608 1.907 70.632 2.293 ;
     RECT  56.712 2.151 56.808 3.349 ;
     RECT  99.504 2.291 99.6 3.541 ;
     RECT  64.992 2.963 65.448 3.013 ;
     RECT  89.112 3.589 90.624 4.163 ;
     RECT  22.824 3.925 24 4.643 ;
     RECT  98.472 3.973 99.504 4.115 ;
     RECT  65.688 4.069 67.2 4.835 ;
     RECT  98.928 4.115 99.504 4.645 ;
     RECT  99.912 4.117 100.944 80.963 ;
     RECT  24.408 4.307 24.456 5.413 ;
     RECT  28.608 4.499 29.4 4.693 ;
     RECT  22.944 4.643 24 5.125 ;
     RECT  126.912 4.643 127.416 4.645 ;
     RECT  76.92 4.645 78 5.123 ;
     RECT  126.912 4.645 127.968 5.171 ;
     RECT  28.344 4.693 29.4 4.883 ;
     RECT  114.312 4.693 115.8 4.835 ;
     RECT  38.04 4.933 39.024 5.557 ;
     RECT  39.048 4.933 40.2 7.669 ;
     RECT  17.256 5.029 18.6 9.493 ;
     RECT  116.664 5.029 117.792 5.413 ;
     RECT  117.816 5.029 118.848 5.173 ;
     RECT  22.944 5.125 23.856 5.411 ;
     RECT  22.944 5.411 24 5.653 ;
     RECT  35.112 5.651 36.144 7.381 ;
     RECT  22.968 5.653 24 5.939 ;
     RECT  16.2 5.749 17.232 8.965 ;
     RECT  21.096 5.939 21.144 6.757 ;
     RECT  36.504 6.229 37.488 64.259 ;
     RECT  119.928 6.421 121.2 8.197 ;
     RECT  21.096 6.757 22.32 6.947 ;
     RECT  21.096 6.947 21.864 7.813 ;
     RECT  116.568 8.099 117.696 9.827 ;
     RECT  120.024 8.197 121.2 21.973 ;
     RECT  13.512 9.349 14.544 24.661 ;
     RECT  14.568 9.349 15.744 33.013 ;
     RECT  17.592 9.493 18.6 13.909 ;
     RECT  116.424 9.827 117.696 10.355 ;
     RECT  116.112 19.237 117.552 19.525 ;
     RECT  116.112 19.525 117.36 25.667 ;
     RECT  22.824 19.957 24 20.147 ;
     RECT  18.912 20.149 20.304 21.877 ;
     RECT  5.304 21.541 6.816 23.269 ;
     RECT  120.072 21.973 121.2 24.131 ;
     RECT  5.304 23.269 6.288 30.275 ;
     RECT  6.312 23.315 7.8 30.275 ;
     RECT  119.976 24.131 121.2 32.245 ;
     RECT  13.512 24.661 14.496 34.453 ;
     RECT  19.848 25.619 21.072 30.037 ;
     RECT  116.112 25.667 117.408 26.723 ;
     RECT  116.112 28.933 117.504 30.851 ;
     RECT  11.688 29.269 13.2 31.955 ;
     RECT  19.896 30.037 21.072 30.805 ;
     RECT  120.12 32.245 121.2 32.483 ;
     RECT  119.976 32.483 121.2 34.595 ;
     RECT  14.712 33.013 15.744 33.061 ;
     RECT  118.344 33.731 119.328 34.211 ;
     RECT  3.672 39.301 5.088 39.443 ;
     RECT  116.112 47.605 117.36 47.795 ;
     RECT  116.112 47.795 117.384 48.901 ;
     RECT  116.112 48.901 117.36 49.091 ;
     RECT  3.672 58.549 4.848 63.205 ;
     RECT  3.672 63.205 4.8 65.795 ;
     RECT  38.952 64.211 40.2 64.499 ;
     RECT  36.504 64.259 38.016 64.547 ;
     RECT  38.808 64.499 40.2 65.891 ;
     RECT  35.112 64.643 36.144 65.555 ;
     RECT  4.32 65.795 4.8 66.373 ;
     RECT  38.976 65.891 40.2 66.085 ;
     RECT  39 66.085 40.2 81.061 ;
     RECT  22.824 67.381 24 67.667 ;
     RECT  15.96 72.275 17.04 75.203 ;
     RECT  19.944 75.155 21.024 79.235 ;
     RECT  15.96 75.203 17.28 81.635 ;
     RECT  60.408 79.189 61.8 81.349 ;
     RECT  19.944 79.235 21.6 79.763 ;
     RECT  22.2 79.621 23.712 80.147 ;
     RECT  116.112 79.717 117.264 83.315 ;
     RECT  121.512 79.717 122.88 79.765 ;
     RECT  19.944 79.763 22.08 80.677 ;
     RECT  121.512 79.765 122.784 80.869 ;
     RECT  78.312 80.197 79.728 80.341 ;
     RECT  79.752 80.197 81.264 80.245 ;
     RECT  79.752 80.245 81.168 80.341 ;
     RECT  17.592 80.339 18.6 81.973 ;
     RECT  78.312 80.341 79.344 83.077 ;
     RECT  33.072 80.387 33.096 80.485 ;
     RECT  8.112 80.485 9.456 80.677 ;
     RECT  31.896 80.485 33.096 81.157 ;
     RECT  105.432 80.485 106.56 81.445 ;
     RECT  87.768 80.533 88.8 84.215 ;
     RECT  9.48 80.677 10.8 82.115 ;
     RECT  20.76 80.677 22.08 80.725 ;
     RECT  72.912 80.677 74.064 82.115 ;
     RECT  20.856 80.725 22.08 80.915 ;
     RECT  49.752 80.725 51 81.973 ;
     RECT  128.76 80.773 129.888 82.261 ;
     RECT  47.304 80.821 48.432 82.115 ;
     RECT  48.456 80.821 49.728 82.691 ;
     RECT  130.536 80.821 132 82.115 ;
     RECT  121.8 80.869 122.784 80.917 ;
     RECT  20.856 80.915 21.144 80.917 ;
     RECT  21.096 80.917 21.144 81.107 ;
     RECT  84.36 80.917 85.488 81.061 ;
     RECT  85.512 80.917 86.736 81.109 ;
     RECT  99.912 80.963 100.968 82.021 ;
     RECT  39 81.061 40.08 81.109 ;
     RECT  20.856 81.107 21.144 82.165 ;
     RECT  24.312 81.107 24.408 82.453 ;
     RECT  32.472 81.157 33.096 81.205 ;
     RECT  32.472 81.205 33.6 82.115 ;
     RECT  33.624 81.205 34.8 82.115 ;
     RECT  59.208 81.205 60.384 81.539 ;
     RECT  39 81.347 40.032 83.125 ;
     RECT  60.408 81.349 61.68 81.539 ;
     RECT  59.208 81.539 61.68 82.645 ;
     RECT  44.472 81.589 45.6 83.411 ;
     RECT  15.672 81.635 17.28 82.165 ;
     RECT  11.976 81.683 13.2 83.173 ;
     RECT  125.112 81.781 126.6 82.691 ;
     RECT  56.712 81.829 57.888 81.925 ;
     RECT  3.672 82.021 5.088 83.267 ;
     RECT  76.392 82.021 77.568 82.405 ;
     RECT  99.912 82.021 101.424 82.691 ;
     RECT  5.64 82.115 5.688 83.125 ;
     RECT  46.728 82.115 48.432 83.173 ;
     RECT  72.912 82.115 74.088 82.501 ;
     RECT  131.712 82.115 132 83.173 ;
     RECT  15.672 82.165 16.992 82.597 ;
     RECT  21 82.165 21.144 82.309 ;
     RECT  67.512 82.453 68.976 82.837 ;
     RECT  72.912 82.501 74.64 83.173 ;
     RECT  123.864 82.549 125.088 82.691 ;
     RECT  19.368 82.595 20.4 83.939 ;
     RECT  62.712 82.597 63.792 82.691 ;
     RECT  127.512 82.643 128.544 84.215 ;
     RECT  59.208 82.645 60.528 82.691 ;
     RECT  60.552 82.645 61.68 83.173 ;
     RECT  8.112 82.691 9.264 83.653 ;
     RECT  30.216 82.691 31.248 84.215 ;
     RECT  40.68 82.691 40.92 83.173 ;
     RECT  48.456 82.691 50.64 82.789 ;
     RECT  53.616 82.691 54.528 83.173 ;
     RECT  62.664 82.691 63.792 82.979 ;
     RECT  99.912 82.691 102.192 83.749 ;
     RECT  123.864 82.691 126.6 82.837 ;
     RECT  49.224 82.789 50.64 82.931 ;
     RECT  67.512 82.837 68.928 84.249 ;
     RECT  123.864 82.837 125.424 83.125 ;
     RECT  125.448 82.837 126.6 83.173 ;
     RECT  48.456 82.931 50.64 83.749 ;
     RECT  75.192 83.125 76.368 83.173 ;
     RECT  124.392 83.125 125.424 83.795 ;
     RECT  11.976 83.173 12.96 84.037 ;
     RECT  40.68 83.173 42.336 83.749 ;
     RECT  46.728 83.173 48 83.411 ;
     RECT  51.96 83.173 53.232 83.749 ;
     RECT  53.256 83.173 54.528 83.651 ;
     RECT  72.912 83.173 74.16 84.249 ;
     RECT  75.192 83.173 76.224 83.219 ;
     RECT  117.288 83.173 118.656 83.315 ;
     RECT  75.192 83.219 76.176 83.267 ;
     RECT  79.992 83.267 80.376 84.373 ;
     RECT  116.112 83.315 117.048 83.653 ;
     RECT  53.256 83.651 54.768 83.939 ;
     RECT  8.232 83.653 9.264 83.795 ;
     RECT  40.68 83.749 42.144 85.475 ;
     RECT  48.456 83.749 50.064 84.325 ;
     RECT  100.344 83.749 102.192 83.845 ;
     RECT  8.232 83.795 9.216 83.843 ;
     RECT  124.44 83.795 125.424 83.843 ;
     RECT  100.344 83.845 101.328 84.035 ;
     RECT  119.16 83.845 120.192 86.16 ;
     RECT  14.52 83.939 15.552 85.475 ;
     RECT  18.912 83.939 20.4 84.249 ;
     RECT  100.344 84.035 101.28 84.083 ;
     RECT  35.208 84.083 35.448 85.477 ;
     RECT  30.264 84.215 31.248 84.263 ;
     RECT  87.768 84.215 88.752 84.263 ;
     RECT  127.56 84.215 128.544 84.263 ;
     RECT  18.72 84.249 20.4 84.263 ;
     RECT  51.144 84.249 52.176 85.475 ;
     RECT  72.72 84.249 74.16 84.263 ;
     RECT  18.696 84.263 20.4 84.949 ;
     RECT  61.032 84.263 61.608 85.477 ;
     RECT  66.36 84.263 66.84 85.475 ;
     RECT  72.456 84.263 74.16 85.475 ;
     RECT  48.552 84.325 50.064 85.475 ;
     RECT  78.36 84.371 79.392 85.475 ;
     RECT  18.696 84.949 19.728 85.475 ;
     RECT  14.52 85.475 15.504 85.523 ;
     RECT  18.744 85.475 19.68 85.523 ;
     RECT  40.728 85.475 42.144 85.477 ;
     RECT  48.552 85.475 50.016 85.477 ;
     RECT  51.192 85.475 52.176 85.523 ;
     RECT  66.36 85.475 66.768 85.477 ;
     RECT  72.456 85.475 73.056 85.477 ;
     RECT  73.176 85.475 74.112 85.523 ;
     RECT  78.408 85.475 79.344 85.523 ;
     RECT  40.728 85.477 41.712 85.523 ;
     RECT  49.08 85.477 50.016 85.523 ;
     RECT  119.208 86.16 120.144 86.224 ;
     RECT  12.984 86.224 13.392 86.243 ;
     RECT  13.512 86.224 14.016 86.243 ;
  END
END ot_s81_pq_qb_bankp_native
END LIBRARY
